VERSION 5.8 ;
BUSBITCHARS "[]" ;
DIVIDERCHAR "/" ;
UNITS
    DATABASE MICRONS 1000 ;
END UNITS

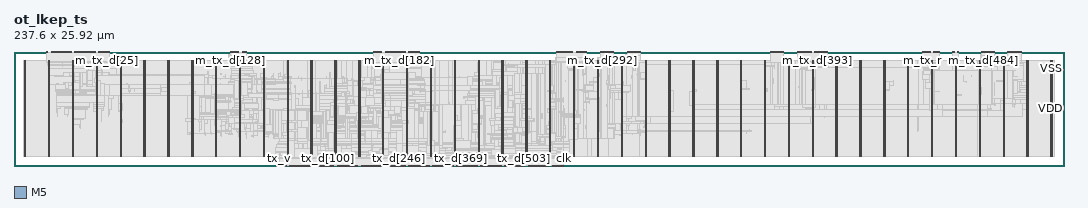
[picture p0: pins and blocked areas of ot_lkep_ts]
MACRO ot_lkep_ts
  FOREIGN ot_lkep_ts 0 0 ;
  CLASS BLOCK ;
  SIZE 237.6 BY 25.92 ;
  PIN clk
    DIRECTION INPUT ;
    USE SIGNAL ;
    PORT
      LAYER M5 ;
        RECT  124.368 0 124.392 0.192 ;
    END
  END clk
  PIN m_tx_d[0]
    DIRECTION INPUT ;
    USE SIGNAL ;
    PORT
      LAYER M5 ;
        RECT  17.904 25.728 17.928 25.92 ;
    END
  END m_tx_d[0]
  PIN m_tx_d[100]
    DIRECTION INPUT ;
    USE SIGNAL ;
    PORT
      LAYER M5 ;
        RECT  15.216 25.728 15.24 25.92 ;
    END
  END m_tx_d[100]
  PIN m_tx_d[101]
    DIRECTION INPUT ;
    USE SIGNAL ;
    PORT
      LAYER M5 ;
        RECT  15.312 25.728 15.336 25.92 ;
    END
  END m_tx_d[101]
  PIN m_tx_d[102]
    DIRECTION INPUT ;
    USE SIGNAL ;
    PORT
      LAYER M5 ;
        RECT  15.408 25.728 15.432 25.92 ;
    END
  END m_tx_d[102]
  PIN m_tx_d[103]
    DIRECTION INPUT ;
    USE SIGNAL ;
    PORT
      LAYER M5 ;
        RECT  15.504 25.728 15.528 25.92 ;
    END
  END m_tx_d[103]
  PIN m_tx_d[104]
    DIRECTION INPUT ;
    USE SIGNAL ;
    PORT
      LAYER M5 ;
        RECT  15.6 25.728 15.624 25.92 ;
    END
  END m_tx_d[104]
  PIN m_tx_d[105]
    DIRECTION INPUT ;
    USE SIGNAL ;
    PORT
      LAYER M5 ;
        RECT  15.696 25.728 15.72 25.92 ;
    END
  END m_tx_d[105]
  PIN m_tx_d[106]
    DIRECTION INPUT ;
    USE SIGNAL ;
    PORT
      LAYER M5 ;
        RECT  15.792 25.728 15.816 25.92 ;
    END
  END m_tx_d[106]
  PIN m_tx_d[107]
    DIRECTION INPUT ;
    USE SIGNAL ;
    PORT
      LAYER M5 ;
        RECT  15.888 25.728 15.912 25.92 ;
    END
  END m_tx_d[107]
  PIN m_tx_d[108]
    DIRECTION INPUT ;
    USE SIGNAL ;
    PORT
      LAYER M5 ;
        RECT  15.984 25.728 16.008 25.92 ;
    END
  END m_tx_d[108]
  PIN m_tx_d[109]
    DIRECTION INPUT ;
    USE SIGNAL ;
    PORT
      LAYER M5 ;
        RECT  16.08 25.728 16.104 25.92 ;
    END
  END m_tx_d[109]
  PIN m_tx_d[10]
    DIRECTION INPUT ;
    USE SIGNAL ;
    PORT
      LAYER M5 ;
        RECT  19.584 25.728 19.608 25.92 ;
    END
  END m_tx_d[10]
  PIN m_tx_d[110]
    DIRECTION INPUT ;
    USE SIGNAL ;
    PORT
      LAYER M5 ;
        RECT  16.176 25.728 16.2 25.92 ;
    END
  END m_tx_d[110]
  PIN m_tx_d[111]
    DIRECTION INPUT ;
    USE SIGNAL ;
    PORT
      LAYER M5 ;
        RECT  16.272 25.728 16.296 25.92 ;
    END
  END m_tx_d[111]
  PIN m_tx_d[112]
    DIRECTION INPUT ;
    USE SIGNAL ;
    PORT
      LAYER M5 ;
        RECT  16.368 25.728 16.392 25.92 ;
    END
  END m_tx_d[112]
  PIN m_tx_d[113]
    DIRECTION INPUT ;
    USE SIGNAL ;
    PORT
      LAYER M5 ;
        RECT  16.464 25.728 16.488 25.92 ;
    END
  END m_tx_d[113]
  PIN m_tx_d[114]
    DIRECTION INPUT ;
    USE SIGNAL ;
    PORT
      LAYER M5 ;
        RECT  16.56 25.728 16.584 25.92 ;
    END
  END m_tx_d[114]
  PIN m_tx_d[115]
    DIRECTION INPUT ;
    USE SIGNAL ;
    PORT
      LAYER M5 ;
        RECT  16.656 25.728 16.68 25.92 ;
    END
  END m_tx_d[115]
  PIN m_tx_d[116]
    DIRECTION INPUT ;
    USE SIGNAL ;
    PORT
      LAYER M5 ;
        RECT  16.752 25.728 16.776 25.92 ;
    END
  END m_tx_d[116]
  PIN m_tx_d[117]
    DIRECTION INPUT ;
    USE SIGNAL ;
    PORT
      LAYER M5 ;
        RECT  16.848 25.728 16.872 25.92 ;
    END
  END m_tx_d[117]
  PIN m_tx_d[118]
    DIRECTION INPUT ;
    USE SIGNAL ;
    PORT
      LAYER M5 ;
        RECT  16.944 25.728 16.968 25.92 ;
    END
  END m_tx_d[118]
  PIN m_tx_d[119]
    DIRECTION INPUT ;
    USE SIGNAL ;
    PORT
      LAYER M5 ;
        RECT  17.04 25.728 17.064 25.92 ;
    END
  END m_tx_d[119]
  PIN m_tx_d[11]
    DIRECTION INPUT ;
    USE SIGNAL ;
    PORT
      LAYER M5 ;
        RECT  19.68 25.728 19.704 25.92 ;
    END
  END m_tx_d[11]
  PIN m_tx_d[120]
    DIRECTION INPUT ;
    USE SIGNAL ;
    PORT
      LAYER M5 ;
        RECT  17.136 25.728 17.16 25.92 ;
    END
  END m_tx_d[120]
  PIN m_tx_d[121]
    DIRECTION INPUT ;
    USE SIGNAL ;
    PORT
      LAYER M5 ;
        RECT  17.232 25.728 17.256 25.92 ;
    END
  END m_tx_d[121]
  PIN m_tx_d[122]
    DIRECTION INPUT ;
    USE SIGNAL ;
    PORT
      LAYER M5 ;
        RECT  17.328 25.728 17.352 25.92 ;
    END
  END m_tx_d[122]
  PIN m_tx_d[123]
    DIRECTION INPUT ;
    USE SIGNAL ;
    PORT
      LAYER M5 ;
        RECT  17.424 25.728 17.448 25.92 ;
    END
  END m_tx_d[123]
  PIN m_tx_d[124]
    DIRECTION INPUT ;
    USE SIGNAL ;
    PORT
      LAYER M5 ;
        RECT  17.52 25.728 17.544 25.92 ;
    END
  END m_tx_d[124]
  PIN m_tx_d[125]
    DIRECTION INPUT ;
    USE SIGNAL ;
    PORT
      LAYER M5 ;
        RECT  17.616 25.728 17.64 25.92 ;
    END
  END m_tx_d[125]
  PIN m_tx_d[126]
    DIRECTION INPUT ;
    USE SIGNAL ;
    PORT
      LAYER M5 ;
        RECT  17.712 25.728 17.736 25.92 ;
    END
  END m_tx_d[126]
  PIN m_tx_d[127]
    DIRECTION INPUT ;
    USE SIGNAL ;
    PORT
      LAYER M5 ;
        RECT  17.808 25.728 17.832 25.92 ;
    END
  END m_tx_d[127]
  PIN m_tx_d[128]
    DIRECTION INPUT ;
    USE SIGNAL ;
    PORT
      LAYER M5 ;
        RECT  49.008 25.728 49.032 25.92 ;
    END
  END m_tx_d[128]
  PIN m_tx_d[129]
    DIRECTION INPUT ;
    USE SIGNAL ;
    PORT
      LAYER M5 ;
        RECT  49.104 25.728 49.128 25.92 ;
    END
  END m_tx_d[129]
  PIN m_tx_d[12]
    DIRECTION INPUT ;
    USE SIGNAL ;
    PORT
      LAYER M5 ;
        RECT  19.776 25.728 19.8 25.92 ;
    END
  END m_tx_d[12]
  PIN m_tx_d[130]
    DIRECTION INPUT ;
    USE SIGNAL ;
    PORT
      LAYER M5 ;
        RECT  49.2 25.728 49.224 25.92 ;
    END
  END m_tx_d[130]
  PIN m_tx_d[131]
    DIRECTION INPUT ;
    USE SIGNAL ;
    PORT
      LAYER M5 ;
        RECT  49.296 25.728 49.32 25.92 ;
    END
  END m_tx_d[131]
  PIN m_tx_d[132]
    DIRECTION INPUT ;
    USE SIGNAL ;
    PORT
      LAYER M5 ;
        RECT  49.392 25.728 49.416 25.92 ;
    END
  END m_tx_d[132]
  PIN m_tx_d[133]
    DIRECTION INPUT ;
    USE SIGNAL ;
    PORT
      LAYER M5 ;
        RECT  49.488 25.728 49.512 25.92 ;
    END
  END m_tx_d[133]
  PIN m_tx_d[134]
    DIRECTION INPUT ;
    USE SIGNAL ;
    PORT
      LAYER M5 ;
        RECT  49.584 25.728 49.608 25.92 ;
    END
  END m_tx_d[134]
  PIN m_tx_d[135]
    DIRECTION INPUT ;
    USE SIGNAL ;
    PORT
      LAYER M5 ;
        RECT  49.68 25.728 49.704 25.92 ;
    END
  END m_tx_d[135]
  PIN m_tx_d[136]
    DIRECTION INPUT ;
    USE SIGNAL ;
    PORT
      LAYER M5 ;
        RECT  49.776 25.728 49.8 25.92 ;
    END
  END m_tx_d[136]
  PIN m_tx_d[137]
    DIRECTION INPUT ;
    USE SIGNAL ;
    PORT
      LAYER M5 ;
        RECT  49.872 25.728 49.896 25.92 ;
    END
  END m_tx_d[137]
  PIN m_tx_d[138]
    DIRECTION INPUT ;
    USE SIGNAL ;
    PORT
      LAYER M5 ;
        RECT  49.968 25.728 49.992 25.92 ;
    END
  END m_tx_d[138]
  PIN m_tx_d[139]
    DIRECTION INPUT ;
    USE SIGNAL ;
    PORT
      LAYER M5 ;
        RECT  50.064 25.728 50.088 25.92 ;
    END
  END m_tx_d[139]
  PIN m_tx_d[13]
    DIRECTION INPUT ;
    USE SIGNAL ;
    PORT
      LAYER M5 ;
        RECT  19.872 25.728 19.896 25.92 ;
    END
  END m_tx_d[13]
  PIN m_tx_d[140]
    DIRECTION INPUT ;
    USE SIGNAL ;
    PORT
      LAYER M5 ;
        RECT  50.16 25.728 50.184 25.92 ;
    END
  END m_tx_d[140]
  PIN m_tx_d[141]
    DIRECTION INPUT ;
    USE SIGNAL ;
    PORT
      LAYER M5 ;
        RECT  50.256 25.728 50.28 25.92 ;
    END
  END m_tx_d[141]
  PIN m_tx_d[142]
    DIRECTION INPUT ;
    USE SIGNAL ;
    PORT
      LAYER M5 ;
        RECT  50.352 25.728 50.376 25.92 ;
    END
  END m_tx_d[142]
  PIN m_tx_d[143]
    DIRECTION INPUT ;
    USE SIGNAL ;
    PORT
      LAYER M5 ;
        RECT  50.448 25.728 50.472 25.92 ;
    END
  END m_tx_d[143]
  PIN m_tx_d[144]
    DIRECTION INPUT ;
    USE SIGNAL ;
    PORT
      LAYER M5 ;
        RECT  50.544 25.728 50.568 25.92 ;
    END
  END m_tx_d[144]
  PIN m_tx_d[145]
    DIRECTION INPUT ;
    USE SIGNAL ;
    PORT
      LAYER M5 ;
        RECT  50.64 25.728 50.664 25.92 ;
    END
  END m_tx_d[145]
  PIN m_tx_d[146]
    DIRECTION INPUT ;
    USE SIGNAL ;
    PORT
      LAYER M5 ;
        RECT  50.736 25.728 50.76 25.92 ;
    END
  END m_tx_d[146]
  PIN m_tx_d[147]
    DIRECTION INPUT ;
    USE SIGNAL ;
    PORT
      LAYER M5 ;
        RECT  50.832 25.728 50.856 25.92 ;
    END
  END m_tx_d[147]
  PIN m_tx_d[148]
    DIRECTION INPUT ;
    USE SIGNAL ;
    PORT
      LAYER M5 ;
        RECT  51.6 25.728 51.624 25.92 ;
    END
  END m_tx_d[148]
  PIN m_tx_d[149]
    DIRECTION INPUT ;
    USE SIGNAL ;
    PORT
      LAYER M5 ;
        RECT  51.696 25.728 51.72 25.92 ;
    END
  END m_tx_d[149]
  PIN m_tx_d[14]
    DIRECTION INPUT ;
    USE SIGNAL ;
    PORT
      LAYER M5 ;
        RECT  19.968 25.728 19.992 25.92 ;
    END
  END m_tx_d[14]
  PIN m_tx_d[150]
    DIRECTION INPUT ;
    USE SIGNAL ;
    PORT
      LAYER M5 ;
        RECT  51.792 25.728 51.816 25.92 ;
    END
  END m_tx_d[150]
  PIN m_tx_d[151]
    DIRECTION INPUT ;
    USE SIGNAL ;
    PORT
      LAYER M5 ;
        RECT  51.888 25.728 51.912 25.92 ;
    END
  END m_tx_d[151]
  PIN m_tx_d[152]
    DIRECTION INPUT ;
    USE SIGNAL ;
    PORT
      LAYER M5 ;
        RECT  51.984 25.728 52.008 25.92 ;
    END
  END m_tx_d[152]
  PIN m_tx_d[153]
    DIRECTION INPUT ;
    USE SIGNAL ;
    PORT
      LAYER M5 ;
        RECT  52.08 25.728 52.104 25.92 ;
    END
  END m_tx_d[153]
  PIN m_tx_d[154]
    DIRECTION INPUT ;
    USE SIGNAL ;
    PORT
      LAYER M5 ;
        RECT  52.176 25.728 52.2 25.92 ;
    END
  END m_tx_d[154]
  PIN m_tx_d[155]
    DIRECTION INPUT ;
    USE SIGNAL ;
    PORT
      LAYER M5 ;
        RECT  52.272 25.728 52.296 25.92 ;
    END
  END m_tx_d[155]
  PIN m_tx_d[156]
    DIRECTION INPUT ;
    USE SIGNAL ;
    PORT
      LAYER M5 ;
        RECT  52.368 25.728 52.392 25.92 ;
    END
  END m_tx_d[156]
  PIN m_tx_d[157]
    DIRECTION INPUT ;
    USE SIGNAL ;
    PORT
      LAYER M5 ;
        RECT  52.464 25.728 52.488 25.92 ;
    END
  END m_tx_d[157]
  PIN m_tx_d[158]
    DIRECTION INPUT ;
    USE SIGNAL ;
    PORT
      LAYER M5 ;
        RECT  52.56 25.728 52.584 25.92 ;
    END
  END m_tx_d[158]
  PIN m_tx_d[159]
    DIRECTION INPUT ;
    USE SIGNAL ;
    PORT
      LAYER M5 ;
        RECT  52.656 25.728 52.68 25.92 ;
    END
  END m_tx_d[159]
  PIN m_tx_d[15]
    DIRECTION INPUT ;
    USE SIGNAL ;
    PORT
      LAYER M5 ;
        RECT  20.064 25.728 20.088 25.92 ;
    END
  END m_tx_d[15]
  PIN m_tx_d[160]
    DIRECTION INPUT ;
    USE SIGNAL ;
    PORT
      LAYER M5 ;
        RECT  85.056 25.728 85.08 25.92 ;
    END
  END m_tx_d[160]
  PIN m_tx_d[161]
    DIRECTION INPUT ;
    USE SIGNAL ;
    PORT
      LAYER M5 ;
        RECT  85.152 25.728 85.176 25.92 ;
    END
  END m_tx_d[161]
  PIN m_tx_d[162]
    DIRECTION INPUT ;
    USE SIGNAL ;
    PORT
      LAYER M5 ;
        RECT  85.248 25.728 85.272 25.92 ;
    END
  END m_tx_d[162]
  PIN m_tx_d[163]
    DIRECTION INPUT ;
    USE SIGNAL ;
    PORT
      LAYER M5 ;
        RECT  85.344 25.728 85.368 25.92 ;
    END
  END m_tx_d[163]
  PIN m_tx_d[164]
    DIRECTION INPUT ;
    USE SIGNAL ;
    PORT
      LAYER M5 ;
        RECT  85.44 25.728 85.464 25.92 ;
    END
  END m_tx_d[164]
  PIN m_tx_d[165]
    DIRECTION INPUT ;
    USE SIGNAL ;
    PORT
      LAYER M5 ;
        RECT  85.536 25.728 85.56 25.92 ;
    END
  END m_tx_d[165]
  PIN m_tx_d[166]
    DIRECTION INPUT ;
    USE SIGNAL ;
    PORT
      LAYER M5 ;
        RECT  85.632 25.728 85.656 25.92 ;
    END
  END m_tx_d[166]
  PIN m_tx_d[167]
    DIRECTION INPUT ;
    USE SIGNAL ;
    PORT
      LAYER M5 ;
        RECT  85.728 25.728 85.752 25.92 ;
    END
  END m_tx_d[167]
  PIN m_tx_d[168]
    DIRECTION INPUT ;
    USE SIGNAL ;
    PORT
      LAYER M5 ;
        RECT  85.824 25.728 85.848 25.92 ;
    END
  END m_tx_d[168]
  PIN m_tx_d[169]
    DIRECTION INPUT ;
    USE SIGNAL ;
    PORT
      LAYER M5 ;
        RECT  85.92 25.728 85.944 25.92 ;
    END
  END m_tx_d[169]
  PIN m_tx_d[16]
    DIRECTION INPUT ;
    USE SIGNAL ;
    PORT
      LAYER M5 ;
        RECT  20.16 25.728 20.184 25.92 ;
    END
  END m_tx_d[16]
  PIN m_tx_d[170]
    DIRECTION INPUT ;
    USE SIGNAL ;
    PORT
      LAYER M5 ;
        RECT  86.016 25.728 86.04 25.92 ;
    END
  END m_tx_d[170]
  PIN m_tx_d[171]
    DIRECTION INPUT ;
    USE SIGNAL ;
    PORT
      LAYER M5 ;
        RECT  86.112 25.728 86.136 25.92 ;
    END
  END m_tx_d[171]
  PIN m_tx_d[172]
    DIRECTION INPUT ;
    USE SIGNAL ;
    PORT
      LAYER M5 ;
        RECT  86.208 25.728 86.232 25.92 ;
    END
  END m_tx_d[172]
  PIN m_tx_d[173]
    DIRECTION INPUT ;
    USE SIGNAL ;
    PORT
      LAYER M5 ;
        RECT  86.304 25.728 86.328 25.92 ;
    END
  END m_tx_d[173]
  PIN m_tx_d[174]
    DIRECTION INPUT ;
    USE SIGNAL ;
    PORT
      LAYER M5 ;
        RECT  86.4 25.728 86.424 25.92 ;
    END
  END m_tx_d[174]
  PIN m_tx_d[175]
    DIRECTION INPUT ;
    USE SIGNAL ;
    PORT
      LAYER M5 ;
        RECT  86.496 25.728 86.52 25.92 ;
    END
  END m_tx_d[175]
  PIN m_tx_d[176]
    DIRECTION INPUT ;
    USE SIGNAL ;
    PORT
      LAYER M5 ;
        RECT  86.592 25.728 86.616 25.92 ;
    END
  END m_tx_d[176]
  PIN m_tx_d[177]
    DIRECTION INPUT ;
    USE SIGNAL ;
    PORT
      LAYER M5 ;
        RECT  86.688 25.728 86.712 25.92 ;
    END
  END m_tx_d[177]
  PIN m_tx_d[178]
    DIRECTION INPUT ;
    USE SIGNAL ;
    PORT
      LAYER M5 ;
        RECT  86.784 25.728 86.808 25.92 ;
    END
  END m_tx_d[178]
  PIN m_tx_d[179]
    DIRECTION INPUT ;
    USE SIGNAL ;
    PORT
      LAYER M5 ;
        RECT  86.88 25.728 86.904 25.92 ;
    END
  END m_tx_d[179]
  PIN m_tx_d[17]
    DIRECTION INPUT ;
    USE SIGNAL ;
    PORT
      LAYER M5 ;
        RECT  20.256 25.728 20.28 25.92 ;
    END
  END m_tx_d[17]
  PIN m_tx_d[180]
    DIRECTION INPUT ;
    USE SIGNAL ;
    PORT
      LAYER M5 ;
        RECT  86.976 25.728 87 25.92 ;
    END
  END m_tx_d[180]
  PIN m_tx_d[181]
    DIRECTION INPUT ;
    USE SIGNAL ;
    PORT
      LAYER M5 ;
        RECT  87.072 25.728 87.096 25.92 ;
    END
  END m_tx_d[181]
  PIN m_tx_d[182]
    DIRECTION INPUT ;
    USE SIGNAL ;
    PORT
      LAYER M5 ;
        RECT  87.168 25.728 87.192 25.92 ;
    END
  END m_tx_d[182]
  PIN m_tx_d[183]
    DIRECTION INPUT ;
    USE SIGNAL ;
    PORT
      LAYER M5 ;
        RECT  87.264 25.728 87.288 25.92 ;
    END
  END m_tx_d[183]
  PIN m_tx_d[184]
    DIRECTION INPUT ;
    USE SIGNAL ;
    PORT
      LAYER M5 ;
        RECT  87.36 25.728 87.384 25.92 ;
    END
  END m_tx_d[184]
  PIN m_tx_d[185]
    DIRECTION INPUT ;
    USE SIGNAL ;
    PORT
      LAYER M5 ;
        RECT  87.456 25.728 87.48 25.92 ;
    END
  END m_tx_d[185]
  PIN m_tx_d[186]
    DIRECTION INPUT ;
    USE SIGNAL ;
    PORT
      LAYER M5 ;
        RECT  87.552 25.728 87.576 25.92 ;
    END
  END m_tx_d[186]
  PIN m_tx_d[187]
    DIRECTION INPUT ;
    USE SIGNAL ;
    PORT
      LAYER M5 ;
        RECT  87.648 25.728 87.672 25.92 ;
    END
  END m_tx_d[187]
  PIN m_tx_d[188]
    DIRECTION INPUT ;
    USE SIGNAL ;
    PORT
      LAYER M5 ;
        RECT  87.744 25.728 87.768 25.92 ;
    END
  END m_tx_d[188]
  PIN m_tx_d[189]
    DIRECTION INPUT ;
    USE SIGNAL ;
    PORT
      LAYER M5 ;
        RECT  87.84 25.728 87.864 25.92 ;
    END
  END m_tx_d[189]
  PIN m_tx_d[18]
    DIRECTION INPUT ;
    USE SIGNAL ;
    PORT
      LAYER M5 ;
        RECT  20.352 25.728 20.376 25.92 ;
    END
  END m_tx_d[18]
  PIN m_tx_d[190]
    DIRECTION INPUT ;
    USE SIGNAL ;
    PORT
      LAYER M5 ;
        RECT  87.936 25.728 87.96 25.92 ;
    END
  END m_tx_d[190]
  PIN m_tx_d[191]
    DIRECTION INPUT ;
    USE SIGNAL ;
    PORT
      LAYER M5 ;
        RECT  88.032 25.728 88.056 25.92 ;
    END
  END m_tx_d[191]
  PIN m_tx_d[192]
    DIRECTION INPUT ;
    USE SIGNAL ;
    PORT
      LAYER M5 ;
        RECT  88.128 25.728 88.152 25.92 ;
    END
  END m_tx_d[192]
  PIN m_tx_d[193]
    DIRECTION INPUT ;
    USE SIGNAL ;
    PORT
      LAYER M5 ;
        RECT  88.224 25.728 88.248 25.92 ;
    END
  END m_tx_d[193]
  PIN m_tx_d[194]
    DIRECTION INPUT ;
    USE SIGNAL ;
    PORT
      LAYER M5 ;
        RECT  88.32 25.728 88.344 25.92 ;
    END
  END m_tx_d[194]
  PIN m_tx_d[195]
    DIRECTION INPUT ;
    USE SIGNAL ;
    PORT
      LAYER M5 ;
        RECT  88.416 25.728 88.44 25.92 ;
    END
  END m_tx_d[195]
  PIN m_tx_d[196]
    DIRECTION INPUT ;
    USE SIGNAL ;
    PORT
      LAYER M5 ;
        RECT  88.512 25.728 88.536 25.92 ;
    END
  END m_tx_d[196]
  PIN m_tx_d[197]
    DIRECTION INPUT ;
    USE SIGNAL ;
    PORT
      LAYER M5 ;
        RECT  88.608 25.728 88.632 25.92 ;
    END
  END m_tx_d[197]
  PIN m_tx_d[198]
    DIRECTION INPUT ;
    USE SIGNAL ;
    PORT
      LAYER M5 ;
        RECT  89.376 25.728 89.4 25.92 ;
    END
  END m_tx_d[198]
  PIN m_tx_d[199]
    DIRECTION INPUT ;
    USE SIGNAL ;
    PORT
      LAYER M5 ;
        RECT  89.472 25.728 89.496 25.92 ;
    END
  END m_tx_d[199]
  PIN m_tx_d[19]
    DIRECTION INPUT ;
    USE SIGNAL ;
    PORT
      LAYER M5 ;
        RECT  20.448 25.728 20.472 25.92 ;
    END
  END m_tx_d[19]
  PIN m_tx_d[1]
    DIRECTION INPUT ;
    USE SIGNAL ;
    PORT
      LAYER M5 ;
        RECT  18 25.728 18.024 25.92 ;
    END
  END m_tx_d[1]
  PIN m_tx_d[200]
    DIRECTION INPUT ;
    USE SIGNAL ;
    PORT
      LAYER M5 ;
        RECT  89.568 25.728 89.592 25.92 ;
    END
  END m_tx_d[200]
  PIN m_tx_d[201]
    DIRECTION INPUT ;
    USE SIGNAL ;
    PORT
      LAYER M5 ;
        RECT  89.664 25.728 89.688 25.92 ;
    END
  END m_tx_d[201]
  PIN m_tx_d[202]
    DIRECTION INPUT ;
    USE SIGNAL ;
    PORT
      LAYER M5 ;
        RECT  89.76 25.728 89.784 25.92 ;
    END
  END m_tx_d[202]
  PIN m_tx_d[203]
    DIRECTION INPUT ;
    USE SIGNAL ;
    PORT
      LAYER M5 ;
        RECT  89.856 25.728 89.88 25.92 ;
    END
  END m_tx_d[203]
  PIN m_tx_d[204]
    DIRECTION INPUT ;
    USE SIGNAL ;
    PORT
      LAYER M5 ;
        RECT  89.952 25.728 89.976 25.92 ;
    END
  END m_tx_d[204]
  PIN m_tx_d[205]
    DIRECTION INPUT ;
    USE SIGNAL ;
    PORT
      LAYER M5 ;
        RECT  90.048 25.728 90.072 25.92 ;
    END
  END m_tx_d[205]
  PIN m_tx_d[206]
    DIRECTION INPUT ;
    USE SIGNAL ;
    PORT
      LAYER M5 ;
        RECT  90.144 25.728 90.168 25.92 ;
    END
  END m_tx_d[206]
  PIN m_tx_d[207]
    DIRECTION INPUT ;
    USE SIGNAL ;
    PORT
      LAYER M5 ;
        RECT  90.24 25.728 90.264 25.92 ;
    END
  END m_tx_d[207]
  PIN m_tx_d[208]
    DIRECTION INPUT ;
    USE SIGNAL ;
    PORT
      LAYER M5 ;
        RECT  90.336 25.728 90.36 25.92 ;
    END
  END m_tx_d[208]
  PIN m_tx_d[209]
    DIRECTION INPUT ;
    USE SIGNAL ;
    PORT
      LAYER M5 ;
        RECT  90.432 25.728 90.456 25.92 ;
    END
  END m_tx_d[209]
  PIN m_tx_d[20]
    DIRECTION INPUT ;
    USE SIGNAL ;
    PORT
      LAYER M5 ;
        RECT  20.544 25.728 20.568 25.92 ;
    END
  END m_tx_d[20]
  PIN m_tx_d[210]
    DIRECTION INPUT ;
    USE SIGNAL ;
    PORT
      LAYER M5 ;
        RECT  90.528 25.728 90.552 25.92 ;
    END
  END m_tx_d[210]
  PIN m_tx_d[211]
    DIRECTION INPUT ;
    USE SIGNAL ;
    PORT
      LAYER M5 ;
        RECT  90.624 25.728 90.648 25.92 ;
    END
  END m_tx_d[211]
  PIN m_tx_d[212]
    DIRECTION INPUT ;
    USE SIGNAL ;
    PORT
      LAYER M5 ;
        RECT  90.72 25.728 90.744 25.92 ;
    END
  END m_tx_d[212]
  PIN m_tx_d[213]
    DIRECTION INPUT ;
    USE SIGNAL ;
    PORT
      LAYER M5 ;
        RECT  90.816 25.728 90.84 25.92 ;
    END
  END m_tx_d[213]
  PIN m_tx_d[214]
    DIRECTION INPUT ;
    USE SIGNAL ;
    PORT
      LAYER M5 ;
        RECT  90.912 25.728 90.936 25.92 ;
    END
  END m_tx_d[214]
  PIN m_tx_d[215]
    DIRECTION INPUT ;
    USE SIGNAL ;
    PORT
      LAYER M5 ;
        RECT  91.008 25.728 91.032 25.92 ;
    END
  END m_tx_d[215]
  PIN m_tx_d[216]
    DIRECTION INPUT ;
    USE SIGNAL ;
    PORT
      LAYER M5 ;
        RECT  91.104 25.728 91.128 25.92 ;
    END
  END m_tx_d[216]
  PIN m_tx_d[217]
    DIRECTION INPUT ;
    USE SIGNAL ;
    PORT
      LAYER M5 ;
        RECT  91.2 25.728 91.224 25.92 ;
    END
  END m_tx_d[217]
  PIN m_tx_d[218]
    DIRECTION INPUT ;
    USE SIGNAL ;
    PORT
      LAYER M5 ;
        RECT  91.296 25.728 91.32 25.92 ;
    END
  END m_tx_d[218]
  PIN m_tx_d[219]
    DIRECTION INPUT ;
    USE SIGNAL ;
    PORT
      LAYER M5 ;
        RECT  91.392 25.728 91.416 25.92 ;
    END
  END m_tx_d[219]
  PIN m_tx_d[21]
    DIRECTION INPUT ;
    USE SIGNAL ;
    PORT
      LAYER M5 ;
        RECT  20.64 25.728 20.664 25.92 ;
    END
  END m_tx_d[21]
  PIN m_tx_d[220]
    DIRECTION INPUT ;
    USE SIGNAL ;
    PORT
      LAYER M5 ;
        RECT  91.488 25.728 91.512 25.92 ;
    END
  END m_tx_d[220]
  PIN m_tx_d[221]
    DIRECTION INPUT ;
    USE SIGNAL ;
    PORT
      LAYER M5 ;
        RECT  91.584 25.728 91.608 25.92 ;
    END
  END m_tx_d[221]
  PIN m_tx_d[222]
    DIRECTION INPUT ;
    USE SIGNAL ;
    PORT
      LAYER M5 ;
        RECT  91.68 25.728 91.704 25.92 ;
    END
  END m_tx_d[222]
  PIN m_tx_d[223]
    DIRECTION INPUT ;
    USE SIGNAL ;
    PORT
      LAYER M5 ;
        RECT  91.776 25.728 91.8 25.92 ;
    END
  END m_tx_d[223]
  PIN m_tx_d[224]
    DIRECTION INPUT ;
    USE SIGNAL ;
    PORT
      LAYER M5 ;
        RECT  81.264 25.728 81.288 25.92 ;
    END
  END m_tx_d[224]
  PIN m_tx_d[225]
    DIRECTION INPUT ;
    USE SIGNAL ;
    PORT
      LAYER M5 ;
        RECT  81.36 25.728 81.384 25.92 ;
    END
  END m_tx_d[225]
  PIN m_tx_d[226]
    DIRECTION INPUT ;
    USE SIGNAL ;
    PORT
      LAYER M5 ;
        RECT  81.456 25.728 81.48 25.92 ;
    END
  END m_tx_d[226]
  PIN m_tx_d[227]
    DIRECTION INPUT ;
    USE SIGNAL ;
    PORT
      LAYER M5 ;
        RECT  81.552 25.728 81.576 25.92 ;
    END
  END m_tx_d[227]
  PIN m_tx_d[228]
    DIRECTION INPUT ;
    USE SIGNAL ;
    PORT
      LAYER M5 ;
        RECT  81.648 25.728 81.672 25.92 ;
    END
  END m_tx_d[228]
  PIN m_tx_d[229]
    DIRECTION INPUT ;
    USE SIGNAL ;
    PORT
      LAYER M5 ;
        RECT  81.744 25.728 81.768 25.92 ;
    END
  END m_tx_d[229]
  PIN m_tx_d[22]
    DIRECTION INPUT ;
    USE SIGNAL ;
    PORT
      LAYER M5 ;
        RECT  20.736 25.728 20.76 25.92 ;
    END
  END m_tx_d[22]
  PIN m_tx_d[230]
    DIRECTION INPUT ;
    USE SIGNAL ;
    PORT
      LAYER M5 ;
        RECT  81.84 25.728 81.864 25.92 ;
    END
  END m_tx_d[230]
  PIN m_tx_d[231]
    DIRECTION INPUT ;
    USE SIGNAL ;
    PORT
      LAYER M5 ;
        RECT  81.936 25.728 81.96 25.92 ;
    END
  END m_tx_d[231]
  PIN m_tx_d[232]
    DIRECTION INPUT ;
    USE SIGNAL ;
    PORT
      LAYER M5 ;
        RECT  82.032 25.728 82.056 25.92 ;
    END
  END m_tx_d[232]
  PIN m_tx_d[233]
    DIRECTION INPUT ;
    USE SIGNAL ;
    PORT
      LAYER M5 ;
        RECT  82.128 25.728 82.152 25.92 ;
    END
  END m_tx_d[233]
  PIN m_tx_d[234]
    DIRECTION INPUT ;
    USE SIGNAL ;
    PORT
      LAYER M5 ;
        RECT  82.224 25.728 82.248 25.92 ;
    END
  END m_tx_d[234]
  PIN m_tx_d[235]
    DIRECTION INPUT ;
    USE SIGNAL ;
    PORT
      LAYER M5 ;
        RECT  82.32 25.728 82.344 25.92 ;
    END
  END m_tx_d[235]
  PIN m_tx_d[236]
    DIRECTION INPUT ;
    USE SIGNAL ;
    PORT
      LAYER M5 ;
        RECT  82.416 25.728 82.44 25.92 ;
    END
  END m_tx_d[236]
  PIN m_tx_d[237]
    DIRECTION INPUT ;
    USE SIGNAL ;
    PORT
      LAYER M5 ;
        RECT  82.512 25.728 82.536 25.92 ;
    END
  END m_tx_d[237]
  PIN m_tx_d[238]
    DIRECTION INPUT ;
    USE SIGNAL ;
    PORT
      LAYER M5 ;
        RECT  82.608 25.728 82.632 25.92 ;
    END
  END m_tx_d[238]
  PIN m_tx_d[239]
    DIRECTION INPUT ;
    USE SIGNAL ;
    PORT
      LAYER M5 ;
        RECT  82.704 25.728 82.728 25.92 ;
    END
  END m_tx_d[239]
  PIN m_tx_d[23]
    DIRECTION INPUT ;
    USE SIGNAL ;
    PORT
      LAYER M5 ;
        RECT  20.832 25.728 20.856 25.92 ;
    END
  END m_tx_d[23]
  PIN m_tx_d[240]
    DIRECTION INPUT ;
    USE SIGNAL ;
    PORT
      LAYER M5 ;
        RECT  82.8 25.728 82.824 25.92 ;
    END
  END m_tx_d[240]
  PIN m_tx_d[241]
    DIRECTION INPUT ;
    USE SIGNAL ;
    PORT
      LAYER M5 ;
        RECT  82.896 25.728 82.92 25.92 ;
    END
  END m_tx_d[241]
  PIN m_tx_d[242]
    DIRECTION INPUT ;
    USE SIGNAL ;
    PORT
      LAYER M5 ;
        RECT  82.992 25.728 83.016 25.92 ;
    END
  END m_tx_d[242]
  PIN m_tx_d[243]
    DIRECTION INPUT ;
    USE SIGNAL ;
    PORT
      LAYER M5 ;
        RECT  83.088 25.728 83.112 25.92 ;
    END
  END m_tx_d[243]
  PIN m_tx_d[244]
    DIRECTION INPUT ;
    USE SIGNAL ;
    PORT
      LAYER M5 ;
        RECT  83.184 25.728 83.208 25.92 ;
    END
  END m_tx_d[244]
  PIN m_tx_d[245]
    DIRECTION INPUT ;
    USE SIGNAL ;
    PORT
      LAYER M5 ;
        RECT  84 25.728 84.024 25.92 ;
    END
  END m_tx_d[245]
  PIN m_tx_d[246]
    DIRECTION INPUT ;
    USE SIGNAL ;
    PORT
      LAYER M5 ;
        RECT  84.096 25.728 84.12 25.92 ;
    END
  END m_tx_d[246]
  PIN m_tx_d[247]
    DIRECTION INPUT ;
    USE SIGNAL ;
    PORT
      LAYER M5 ;
        RECT  84.192 25.728 84.216 25.92 ;
    END
  END m_tx_d[247]
  PIN m_tx_d[248]
    DIRECTION INPUT ;
    USE SIGNAL ;
    PORT
      LAYER M5 ;
        RECT  84.288 25.728 84.312 25.92 ;
    END
  END m_tx_d[248]
  PIN m_tx_d[249]
    DIRECTION INPUT ;
    USE SIGNAL ;
    PORT
      LAYER M5 ;
        RECT  84.384 25.728 84.408 25.92 ;
    END
  END m_tx_d[249]
  PIN m_tx_d[24]
    DIRECTION INPUT ;
    USE SIGNAL ;
    PORT
      LAYER M5 ;
        RECT  20.928 25.728 20.952 25.92 ;
    END
  END m_tx_d[24]
  PIN m_tx_d[250]
    DIRECTION INPUT ;
    USE SIGNAL ;
    PORT
      LAYER M5 ;
        RECT  84.48 25.728 84.504 25.92 ;
    END
  END m_tx_d[250]
  PIN m_tx_d[251]
    DIRECTION INPUT ;
    USE SIGNAL ;
    PORT
      LAYER M5 ;
        RECT  84.576 25.728 84.6 25.92 ;
    END
  END m_tx_d[251]
  PIN m_tx_d[252]
    DIRECTION INPUT ;
    USE SIGNAL ;
    PORT
      LAYER M5 ;
        RECT  84.672 25.728 84.696 25.92 ;
    END
  END m_tx_d[252]
  PIN m_tx_d[253]
    DIRECTION INPUT ;
    USE SIGNAL ;
    PORT
      LAYER M5 ;
        RECT  84.768 25.728 84.792 25.92 ;
    END
  END m_tx_d[253]
  PIN m_tx_d[254]
    DIRECTION INPUT ;
    USE SIGNAL ;
    PORT
      LAYER M5 ;
        RECT  84.864 25.728 84.888 25.92 ;
    END
  END m_tx_d[254]
  PIN m_tx_d[255]
    DIRECTION INPUT ;
    USE SIGNAL ;
    PORT
      LAYER M5 ;
        RECT  84.96 25.728 84.984 25.92 ;
    END
  END m_tx_d[255]
  PIN m_tx_d[256]
    DIRECTION INPUT ;
    USE SIGNAL ;
    PORT
      LAYER M5 ;
        RECT  122.736 25.728 122.76 25.92 ;
    END
  END m_tx_d[256]
  PIN m_tx_d[257]
    DIRECTION INPUT ;
    USE SIGNAL ;
    PORT
      LAYER M5 ;
        RECT  122.832 25.728 122.856 25.92 ;
    END
  END m_tx_d[257]
  PIN m_tx_d[258]
    DIRECTION INPUT ;
    USE SIGNAL ;
    PORT
      LAYER M5 ;
        RECT  122.928 25.728 122.952 25.92 ;
    END
  END m_tx_d[258]
  PIN m_tx_d[259]
    DIRECTION INPUT ;
    USE SIGNAL ;
    PORT
      LAYER M5 ;
        RECT  123.024 25.728 123.048 25.92 ;
    END
  END m_tx_d[259]
  PIN m_tx_d[25]
    DIRECTION INPUT ;
    USE SIGNAL ;
    PORT
      LAYER M5 ;
        RECT  21.024 25.728 21.048 25.92 ;
    END
  END m_tx_d[25]
  PIN m_tx_d[260]
    DIRECTION INPUT ;
    USE SIGNAL ;
    PORT
      LAYER M5 ;
        RECT  123.12 25.728 123.144 25.92 ;
    END
  END m_tx_d[260]
  PIN m_tx_d[261]
    DIRECTION INPUT ;
    USE SIGNAL ;
    PORT
      LAYER M5 ;
        RECT  123.216 25.728 123.24 25.92 ;
    END
  END m_tx_d[261]
  PIN m_tx_d[262]
    DIRECTION INPUT ;
    USE SIGNAL ;
    PORT
      LAYER M5 ;
        RECT  123.312 25.728 123.336 25.92 ;
    END
  END m_tx_d[262]
  PIN m_tx_d[263]
    DIRECTION INPUT ;
    USE SIGNAL ;
    PORT
      LAYER M5 ;
        RECT  123.408 25.728 123.432 25.92 ;
    END
  END m_tx_d[263]
  PIN m_tx_d[264]
    DIRECTION INPUT ;
    USE SIGNAL ;
    PORT
      LAYER M5 ;
        RECT  123.504 25.728 123.528 25.92 ;
    END
  END m_tx_d[264]
  PIN m_tx_d[265]
    DIRECTION INPUT ;
    USE SIGNAL ;
    PORT
      LAYER M5 ;
        RECT  123.6 25.728 123.624 25.92 ;
    END
  END m_tx_d[265]
  PIN m_tx_d[266]
    DIRECTION INPUT ;
    USE SIGNAL ;
    PORT
      LAYER M5 ;
        RECT  123.696 25.728 123.72 25.92 ;
    END
  END m_tx_d[266]
  PIN m_tx_d[267]
    DIRECTION INPUT ;
    USE SIGNAL ;
    PORT
      LAYER M5 ;
        RECT  123.792 25.728 123.816 25.92 ;
    END
  END m_tx_d[267]
  PIN m_tx_d[268]
    DIRECTION INPUT ;
    USE SIGNAL ;
    PORT
      LAYER M5 ;
        RECT  123.888 25.728 123.912 25.92 ;
    END
  END m_tx_d[268]
  PIN m_tx_d[269]
    DIRECTION INPUT ;
    USE SIGNAL ;
    PORT
      LAYER M5 ;
        RECT  123.984 25.728 124.008 25.92 ;
    END
  END m_tx_d[269]
  PIN m_tx_d[26]
    DIRECTION INPUT ;
    USE SIGNAL ;
    PORT
      LAYER M5 ;
        RECT  21.12 25.728 21.144 25.92 ;
    END
  END m_tx_d[26]
  PIN m_tx_d[270]
    DIRECTION INPUT ;
    USE SIGNAL ;
    PORT
      LAYER M5 ;
        RECT  124.08 25.728 124.104 25.92 ;
    END
  END m_tx_d[270]
  PIN m_tx_d[271]
    DIRECTION INPUT ;
    USE SIGNAL ;
    PORT
      LAYER M5 ;
        RECT  124.176 25.728 124.2 25.92 ;
    END
  END m_tx_d[271]
  PIN m_tx_d[272]
    DIRECTION INPUT ;
    USE SIGNAL ;
    PORT
      LAYER M5 ;
        RECT  124.272 25.728 124.296 25.92 ;
    END
  END m_tx_d[272]
  PIN m_tx_d[273]
    DIRECTION INPUT ;
    USE SIGNAL ;
    PORT
      LAYER M5 ;
        RECT  124.368 25.728 124.392 25.92 ;
    END
  END m_tx_d[273]
  PIN m_tx_d[274]
    DIRECTION INPUT ;
    USE SIGNAL ;
    PORT
      LAYER M5 ;
        RECT  124.464 25.728 124.488 25.92 ;
    END
  END m_tx_d[274]
  PIN m_tx_d[275]
    DIRECTION INPUT ;
    USE SIGNAL ;
    PORT
      LAYER M5 ;
        RECT  124.56 25.728 124.584 25.92 ;
    END
  END m_tx_d[275]
  PIN m_tx_d[276]
    DIRECTION INPUT ;
    USE SIGNAL ;
    PORT
      LAYER M5 ;
        RECT  124.656 25.728 124.68 25.92 ;
    END
  END m_tx_d[276]
  PIN m_tx_d[277]
    DIRECTION INPUT ;
    USE SIGNAL ;
    PORT
      LAYER M5 ;
        RECT  124.752 25.728 124.776 25.92 ;
    END
  END m_tx_d[277]
  PIN m_tx_d[278]
    DIRECTION INPUT ;
    USE SIGNAL ;
    PORT
      LAYER M5 ;
        RECT  124.848 25.728 124.872 25.92 ;
    END
  END m_tx_d[278]
  PIN m_tx_d[279]
    DIRECTION INPUT ;
    USE SIGNAL ;
    PORT
      LAYER M5 ;
        RECT  124.944 25.728 124.968 25.92 ;
    END
  END m_tx_d[279]
  PIN m_tx_d[27]
    DIRECTION INPUT ;
    USE SIGNAL ;
    PORT
      LAYER M5 ;
        RECT  21.216 25.728 21.24 25.92 ;
    END
  END m_tx_d[27]
  PIN m_tx_d[280]
    DIRECTION INPUT ;
    USE SIGNAL ;
    PORT
      LAYER M5 ;
        RECT  125.04 25.728 125.064 25.92 ;
    END
  END m_tx_d[280]
  PIN m_tx_d[281]
    DIRECTION INPUT ;
    USE SIGNAL ;
    PORT
      LAYER M5 ;
        RECT  125.136 25.728 125.16 25.92 ;
    END
  END m_tx_d[281]
  PIN m_tx_d[282]
    DIRECTION INPUT ;
    USE SIGNAL ;
    PORT
      LAYER M5 ;
        RECT  125.232 25.728 125.256 25.92 ;
    END
  END m_tx_d[282]
  PIN m_tx_d[283]
    DIRECTION INPUT ;
    USE SIGNAL ;
    PORT
      LAYER M5 ;
        RECT  125.328 25.728 125.352 25.92 ;
    END
  END m_tx_d[283]
  PIN m_tx_d[284]
    DIRECTION INPUT ;
    USE SIGNAL ;
    PORT
      LAYER M5 ;
        RECT  125.424 25.728 125.448 25.92 ;
    END
  END m_tx_d[284]
  PIN m_tx_d[285]
    DIRECTION INPUT ;
    USE SIGNAL ;
    PORT
      LAYER M5 ;
        RECT  125.52 25.728 125.544 25.92 ;
    END
  END m_tx_d[285]
  PIN m_tx_d[286]
    DIRECTION INPUT ;
    USE SIGNAL ;
    PORT
      LAYER M5 ;
        RECT  125.616 25.728 125.64 25.92 ;
    END
  END m_tx_d[286]
  PIN m_tx_d[287]
    DIRECTION INPUT ;
    USE SIGNAL ;
    PORT
      LAYER M5 ;
        RECT  125.712 25.728 125.736 25.92 ;
    END
  END m_tx_d[287]
  PIN m_tx_d[288]
    DIRECTION INPUT ;
    USE SIGNAL ;
    PORT
      LAYER M5 ;
        RECT  132.72 25.728 132.744 25.92 ;
    END
  END m_tx_d[288]
  PIN m_tx_d[289]
    DIRECTION INPUT ;
    USE SIGNAL ;
    PORT
      LAYER M5 ;
        RECT  132.816 25.728 132.84 25.92 ;
    END
  END m_tx_d[289]
  PIN m_tx_d[28]
    DIRECTION INPUT ;
    USE SIGNAL ;
    PORT
      LAYER M5 ;
        RECT  21.312 25.728 21.336 25.92 ;
    END
  END m_tx_d[28]
  PIN m_tx_d[290]
    DIRECTION INPUT ;
    USE SIGNAL ;
    PORT
      LAYER M5 ;
        RECT  132.912 25.728 132.936 25.92 ;
    END
  END m_tx_d[290]
  PIN m_tx_d[291]
    DIRECTION INPUT ;
    USE SIGNAL ;
    PORT
      LAYER M5 ;
        RECT  133.008 25.728 133.032 25.92 ;
    END
  END m_tx_d[291]
  PIN m_tx_d[292]
    DIRECTION INPUT ;
    USE SIGNAL ;
    PORT
      LAYER M5 ;
        RECT  133.104 25.728 133.128 25.92 ;
    END
  END m_tx_d[292]
  PIN m_tx_d[293]
    DIRECTION INPUT ;
    USE SIGNAL ;
    PORT
      LAYER M5 ;
        RECT  133.2 25.728 133.224 25.92 ;
    END
  END m_tx_d[293]
  PIN m_tx_d[294]
    DIRECTION INPUT ;
    USE SIGNAL ;
    PORT
      LAYER M5 ;
        RECT  133.296 25.728 133.32 25.92 ;
    END
  END m_tx_d[294]
  PIN m_tx_d[295]
    DIRECTION INPUT ;
    USE SIGNAL ;
    PORT
      LAYER M5 ;
        RECT  133.392 25.728 133.416 25.92 ;
    END
  END m_tx_d[295]
  PIN m_tx_d[296]
    DIRECTION INPUT ;
    USE SIGNAL ;
    PORT
      LAYER M5 ;
        RECT  133.488 25.728 133.512 25.92 ;
    END
  END m_tx_d[296]
  PIN m_tx_d[297]
    DIRECTION INPUT ;
    USE SIGNAL ;
    PORT
      LAYER M5 ;
        RECT  133.584 25.728 133.608 25.92 ;
    END
  END m_tx_d[297]
  PIN m_tx_d[298]
    DIRECTION INPUT ;
    USE SIGNAL ;
    PORT
      LAYER M5 ;
        RECT  133.68 25.728 133.704 25.92 ;
    END
  END m_tx_d[298]
  PIN m_tx_d[299]
    DIRECTION INPUT ;
    USE SIGNAL ;
    PORT
      LAYER M5 ;
        RECT  133.776 25.728 133.8 25.92 ;
    END
  END m_tx_d[299]
  PIN m_tx_d[29]
    DIRECTION INPUT ;
    USE SIGNAL ;
    PORT
      LAYER M5 ;
        RECT  21.408 25.728 21.432 25.92 ;
    END
  END m_tx_d[29]
  PIN m_tx_d[2]
    DIRECTION INPUT ;
    USE SIGNAL ;
    PORT
      LAYER M5 ;
        RECT  18.096 25.728 18.12 25.92 ;
    END
  END m_tx_d[2]
  PIN m_tx_d[300]
    DIRECTION INPUT ;
    USE SIGNAL ;
    PORT
      LAYER M5 ;
        RECT  133.872 25.728 133.896 25.92 ;
    END
  END m_tx_d[300]
  PIN m_tx_d[301]
    DIRECTION INPUT ;
    USE SIGNAL ;
    PORT
      LAYER M5 ;
        RECT  133.968 25.728 133.992 25.92 ;
    END
  END m_tx_d[301]
  PIN m_tx_d[302]
    DIRECTION INPUT ;
    USE SIGNAL ;
    PORT
      LAYER M5 ;
        RECT  134.064 25.728 134.088 25.92 ;
    END
  END m_tx_d[302]
  PIN m_tx_d[303]
    DIRECTION INPUT ;
    USE SIGNAL ;
    PORT
      LAYER M5 ;
        RECT  134.16 25.728 134.184 25.92 ;
    END
  END m_tx_d[303]
  PIN m_tx_d[304]
    DIRECTION INPUT ;
    USE SIGNAL ;
    PORT
      LAYER M5 ;
        RECT  134.256 25.728 134.28 25.92 ;
    END
  END m_tx_d[304]
  PIN m_tx_d[305]
    DIRECTION INPUT ;
    USE SIGNAL ;
    PORT
      LAYER M5 ;
        RECT  134.352 25.728 134.376 25.92 ;
    END
  END m_tx_d[305]
  PIN m_tx_d[306]
    DIRECTION INPUT ;
    USE SIGNAL ;
    PORT
      LAYER M5 ;
        RECT  134.448 25.728 134.472 25.92 ;
    END
  END m_tx_d[306]
  PIN m_tx_d[307]
    DIRECTION INPUT ;
    USE SIGNAL ;
    PORT
      LAYER M5 ;
        RECT  134.544 25.728 134.568 25.92 ;
    END
  END m_tx_d[307]
  PIN m_tx_d[308]
    DIRECTION INPUT ;
    USE SIGNAL ;
    PORT
      LAYER M5 ;
        RECT  134.64 25.728 134.664 25.92 ;
    END
  END m_tx_d[308]
  PIN m_tx_d[309]
    DIRECTION INPUT ;
    USE SIGNAL ;
    PORT
      LAYER M5 ;
        RECT  134.736 25.728 134.76 25.92 ;
    END
  END m_tx_d[309]
  PIN m_tx_d[30]
    DIRECTION INPUT ;
    USE SIGNAL ;
    PORT
      LAYER M5 ;
        RECT  21.504 25.728 21.528 25.92 ;
    END
  END m_tx_d[30]
  PIN m_tx_d[310]
    DIRECTION INPUT ;
    USE SIGNAL ;
    PORT
      LAYER M5 ;
        RECT  134.832 25.728 134.856 25.92 ;
    END
  END m_tx_d[310]
  PIN m_tx_d[311]
    DIRECTION INPUT ;
    USE SIGNAL ;
    PORT
      LAYER M5 ;
        RECT  134.928 25.728 134.952 25.92 ;
    END
  END m_tx_d[311]
  PIN m_tx_d[312]
    DIRECTION INPUT ;
    USE SIGNAL ;
    PORT
      LAYER M5 ;
        RECT  135.024 25.728 135.048 25.92 ;
    END
  END m_tx_d[312]
  PIN m_tx_d[313]
    DIRECTION INPUT ;
    USE SIGNAL ;
    PORT
      LAYER M5 ;
        RECT  135.12 25.728 135.144 25.92 ;
    END
  END m_tx_d[313]
  PIN m_tx_d[314]
    DIRECTION INPUT ;
    USE SIGNAL ;
    PORT
      LAYER M5 ;
        RECT  135.216 25.728 135.24 25.92 ;
    END
  END m_tx_d[314]
  PIN m_tx_d[315]
    DIRECTION INPUT ;
    USE SIGNAL ;
    PORT
      LAYER M5 ;
        RECT  135.312 25.728 135.336 25.92 ;
    END
  END m_tx_d[315]
  PIN m_tx_d[316]
    DIRECTION INPUT ;
    USE SIGNAL ;
    PORT
      LAYER M5 ;
        RECT  135.408 25.728 135.432 25.92 ;
    END
  END m_tx_d[316]
  PIN m_tx_d[317]
    DIRECTION INPUT ;
    USE SIGNAL ;
    PORT
      LAYER M5 ;
        RECT  135.504 25.728 135.528 25.92 ;
    END
  END m_tx_d[317]
  PIN m_tx_d[318]
    DIRECTION INPUT ;
    USE SIGNAL ;
    PORT
      LAYER M5 ;
        RECT  135.6 25.728 135.624 25.92 ;
    END
  END m_tx_d[318]
  PIN m_tx_d[319]
    DIRECTION INPUT ;
    USE SIGNAL ;
    PORT
      LAYER M5 ;
        RECT  135.696 25.728 135.72 25.92 ;
    END
  END m_tx_d[319]
  PIN m_tx_d[31]
    DIRECTION INPUT ;
    USE SIGNAL ;
    PORT
      LAYER M5 ;
        RECT  21.6 25.728 21.624 25.92 ;
    END
  END m_tx_d[31]
  PIN m_tx_d[320]
    DIRECTION INPUT ;
    USE SIGNAL ;
    PORT
      LAYER M5 ;
        RECT  125.808 25.728 125.832 25.92 ;
    END
  END m_tx_d[320]
  PIN m_tx_d[321]
    DIRECTION INPUT ;
    USE SIGNAL ;
    PORT
      LAYER M5 ;
        RECT  125.904 25.728 125.928 25.92 ;
    END
  END m_tx_d[321]
  PIN m_tx_d[322]
    DIRECTION INPUT ;
    USE SIGNAL ;
    PORT
      LAYER M5 ;
        RECT  126 25.728 126.024 25.92 ;
    END
  END m_tx_d[322]
  PIN m_tx_d[323]
    DIRECTION INPUT ;
    USE SIGNAL ;
    PORT
      LAYER M5 ;
        RECT  126.096 25.728 126.12 25.92 ;
    END
  END m_tx_d[323]
  PIN m_tx_d[324]
    DIRECTION INPUT ;
    USE SIGNAL ;
    PORT
      LAYER M5 ;
        RECT  126.192 25.728 126.216 25.92 ;
    END
  END m_tx_d[324]
  PIN m_tx_d[325]
    DIRECTION INPUT ;
    USE SIGNAL ;
    PORT
      LAYER M5 ;
        RECT  126.288 25.728 126.312 25.92 ;
    END
  END m_tx_d[325]
  PIN m_tx_d[326]
    DIRECTION INPUT ;
    USE SIGNAL ;
    PORT
      LAYER M5 ;
        RECT  126.384 25.728 126.408 25.92 ;
    END
  END m_tx_d[326]
  PIN m_tx_d[327]
    DIRECTION INPUT ;
    USE SIGNAL ;
    PORT
      LAYER M5 ;
        RECT  127.2 25.728 127.224 25.92 ;
    END
  END m_tx_d[327]
  PIN m_tx_d[328]
    DIRECTION INPUT ;
    USE SIGNAL ;
    PORT
      LAYER M5 ;
        RECT  127.296 25.728 127.32 25.92 ;
    END
  END m_tx_d[328]
  PIN m_tx_d[329]
    DIRECTION INPUT ;
    USE SIGNAL ;
    PORT
      LAYER M5 ;
        RECT  127.392 25.728 127.416 25.92 ;
    END
  END m_tx_d[329]
  PIN m_tx_d[32]
    DIRECTION INPUT ;
    USE SIGNAL ;
    PORT
      LAYER M5 ;
        RECT  7.536 25.728 7.56 25.92 ;
    END
  END m_tx_d[32]
  PIN m_tx_d[330]
    DIRECTION INPUT ;
    USE SIGNAL ;
    PORT
      LAYER M5 ;
        RECT  127.488 25.728 127.512 25.92 ;
    END
  END m_tx_d[330]
  PIN m_tx_d[331]
    DIRECTION INPUT ;
    USE SIGNAL ;
    PORT
      LAYER M5 ;
        RECT  127.584 25.728 127.608 25.92 ;
    END
  END m_tx_d[331]
  PIN m_tx_d[332]
    DIRECTION INPUT ;
    USE SIGNAL ;
    PORT
      LAYER M5 ;
        RECT  127.68 25.728 127.704 25.92 ;
    END
  END m_tx_d[332]
  PIN m_tx_d[333]
    DIRECTION INPUT ;
    USE SIGNAL ;
    PORT
      LAYER M5 ;
        RECT  127.776 25.728 127.8 25.92 ;
    END
  END m_tx_d[333]
  PIN m_tx_d[334]
    DIRECTION INPUT ;
    USE SIGNAL ;
    PORT
      LAYER M5 ;
        RECT  127.872 25.728 127.896 25.92 ;
    END
  END m_tx_d[334]
  PIN m_tx_d[335]
    DIRECTION INPUT ;
    USE SIGNAL ;
    PORT
      LAYER M5 ;
        RECT  127.968 25.728 127.992 25.92 ;
    END
  END m_tx_d[335]
  PIN m_tx_d[336]
    DIRECTION INPUT ;
    USE SIGNAL ;
    PORT
      LAYER M5 ;
        RECT  128.064 25.728 128.088 25.92 ;
    END
  END m_tx_d[336]
  PIN m_tx_d[337]
    DIRECTION INPUT ;
    USE SIGNAL ;
    PORT
      LAYER M5 ;
        RECT  128.16 25.728 128.184 25.92 ;
    END
  END m_tx_d[337]
  PIN m_tx_d[338]
    DIRECTION INPUT ;
    USE SIGNAL ;
    PORT
      LAYER M5 ;
        RECT  128.256 25.728 128.28 25.92 ;
    END
  END m_tx_d[338]
  PIN m_tx_d[339]
    DIRECTION INPUT ;
    USE SIGNAL ;
    PORT
      LAYER M5 ;
        RECT  128.352 25.728 128.376 25.92 ;
    END
  END m_tx_d[339]
  PIN m_tx_d[33]
    DIRECTION INPUT ;
    USE SIGNAL ;
    PORT
      LAYER M5 ;
        RECT  7.632 25.728 7.656 25.92 ;
    END
  END m_tx_d[33]
  PIN m_tx_d[340]
    DIRECTION INPUT ;
    USE SIGNAL ;
    PORT
      LAYER M5 ;
        RECT  128.448 25.728 128.472 25.92 ;
    END
  END m_tx_d[340]
  PIN m_tx_d[341]
    DIRECTION INPUT ;
    USE SIGNAL ;
    PORT
      LAYER M5 ;
        RECT  128.544 25.728 128.568 25.92 ;
    END
  END m_tx_d[341]
  PIN m_tx_d[342]
    DIRECTION INPUT ;
    USE SIGNAL ;
    PORT
      LAYER M5 ;
        RECT  128.64 25.728 128.664 25.92 ;
    END
  END m_tx_d[342]
  PIN m_tx_d[343]
    DIRECTION INPUT ;
    USE SIGNAL ;
    PORT
      LAYER M5 ;
        RECT  128.736 25.728 128.76 25.92 ;
    END
  END m_tx_d[343]
  PIN m_tx_d[344]
    DIRECTION INPUT ;
    USE SIGNAL ;
    PORT
      LAYER M5 ;
        RECT  128.832 25.728 128.856 25.92 ;
    END
  END m_tx_d[344]
  PIN m_tx_d[345]
    DIRECTION INPUT ;
    USE SIGNAL ;
    PORT
      LAYER M5 ;
        RECT  128.928 25.728 128.952 25.92 ;
    END
  END m_tx_d[345]
  PIN m_tx_d[346]
    DIRECTION INPUT ;
    USE SIGNAL ;
    PORT
      LAYER M5 ;
        RECT  129.024 25.728 129.048 25.92 ;
    END
  END m_tx_d[346]
  PIN m_tx_d[347]
    DIRECTION INPUT ;
    USE SIGNAL ;
    PORT
      LAYER M5 ;
        RECT  129.12 25.728 129.144 25.92 ;
    END
  END m_tx_d[347]
  PIN m_tx_d[348]
    DIRECTION INPUT ;
    USE SIGNAL ;
    PORT
      LAYER M5 ;
        RECT  129.216 25.728 129.24 25.92 ;
    END
  END m_tx_d[348]
  PIN m_tx_d[349]
    DIRECTION INPUT ;
    USE SIGNAL ;
    PORT
      LAYER M5 ;
        RECT  129.312 25.728 129.336 25.92 ;
    END
  END m_tx_d[349]
  PIN m_tx_d[34]
    DIRECTION INPUT ;
    USE SIGNAL ;
    PORT
      LAYER M5 ;
        RECT  7.44 25.728 7.464 25.92 ;
    END
  END m_tx_d[34]
  PIN m_tx_d[350]
    DIRECTION INPUT ;
    USE SIGNAL ;
    PORT
      LAYER M5 ;
        RECT  129.408 25.728 129.432 25.92 ;
    END
  END m_tx_d[350]
  PIN m_tx_d[351]
    DIRECTION INPUT ;
    USE SIGNAL ;
    PORT
      LAYER M5 ;
        RECT  129.504 25.728 129.528 25.92 ;
    END
  END m_tx_d[351]
  PIN m_tx_d[352]
    DIRECTION INPUT ;
    USE SIGNAL ;
    PORT
      LAYER M5 ;
        RECT  138.864 25.728 138.888 25.92 ;
    END
  END m_tx_d[352]
  PIN m_tx_d[353]
    DIRECTION INPUT ;
    USE SIGNAL ;
    PORT
      LAYER M5 ;
        RECT  138.96 25.728 138.984 25.92 ;
    END
  END m_tx_d[353]
  PIN m_tx_d[354]
    DIRECTION INPUT ;
    USE SIGNAL ;
    PORT
      LAYER M5 ;
        RECT  139.056 25.728 139.08 25.92 ;
    END
  END m_tx_d[354]
  PIN m_tx_d[355]
    DIRECTION INPUT ;
    USE SIGNAL ;
    PORT
      LAYER M5 ;
        RECT  139.152 25.728 139.176 25.92 ;
    END
  END m_tx_d[355]
  PIN m_tx_d[356]
    DIRECTION INPUT ;
    USE SIGNAL ;
    PORT
      LAYER M5 ;
        RECT  139.248 25.728 139.272 25.92 ;
    END
  END m_tx_d[356]
  PIN m_tx_d[357]
    DIRECTION INPUT ;
    USE SIGNAL ;
    PORT
      LAYER M5 ;
        RECT  139.344 25.728 139.368 25.92 ;
    END
  END m_tx_d[357]
  PIN m_tx_d[358]
    DIRECTION INPUT ;
    USE SIGNAL ;
    PORT
      LAYER M5 ;
        RECT  139.44 25.728 139.464 25.92 ;
    END
  END m_tx_d[358]
  PIN m_tx_d[359]
    DIRECTION INPUT ;
    USE SIGNAL ;
    PORT
      LAYER M5 ;
        RECT  139.536 25.728 139.56 25.92 ;
    END
  END m_tx_d[359]
  PIN m_tx_d[35]
    DIRECTION INPUT ;
    USE SIGNAL ;
    PORT
      LAYER M5 ;
        RECT  7.344 25.728 7.368 25.92 ;
    END
  END m_tx_d[35]
  PIN m_tx_d[360]
    DIRECTION INPUT ;
    USE SIGNAL ;
    PORT
      LAYER M5 ;
        RECT  139.632 25.728 139.656 25.92 ;
    END
  END m_tx_d[360]
  PIN m_tx_d[361]
    DIRECTION INPUT ;
    USE SIGNAL ;
    PORT
      LAYER M5 ;
        RECT  139.728 25.728 139.752 25.92 ;
    END
  END m_tx_d[361]
  PIN m_tx_d[362]
    DIRECTION INPUT ;
    USE SIGNAL ;
    PORT
      LAYER M5 ;
        RECT  139.824 25.728 139.848 25.92 ;
    END
  END m_tx_d[362]
  PIN m_tx_d[363]
    DIRECTION INPUT ;
    USE SIGNAL ;
    PORT
      LAYER M5 ;
        RECT  139.92 25.728 139.944 25.92 ;
    END
  END m_tx_d[363]
  PIN m_tx_d[364]
    DIRECTION INPUT ;
    USE SIGNAL ;
    PORT
      LAYER M5 ;
        RECT  140.016 25.728 140.04 25.92 ;
    END
  END m_tx_d[364]
  PIN m_tx_d[365]
    DIRECTION INPUT ;
    USE SIGNAL ;
    PORT
      LAYER M5 ;
        RECT  140.112 25.728 140.136 25.92 ;
    END
  END m_tx_d[365]
  PIN m_tx_d[366]
    DIRECTION INPUT ;
    USE SIGNAL ;
    PORT
      LAYER M5 ;
        RECT  140.208 25.728 140.232 25.92 ;
    END
  END m_tx_d[366]
  PIN m_tx_d[367]
    DIRECTION INPUT ;
    USE SIGNAL ;
    PORT
      LAYER M5 ;
        RECT  140.304 25.728 140.328 25.92 ;
    END
  END m_tx_d[367]
  PIN m_tx_d[368]
    DIRECTION INPUT ;
    USE SIGNAL ;
    PORT
      LAYER M5 ;
        RECT  140.4 25.728 140.424 25.92 ;
    END
  END m_tx_d[368]
  PIN m_tx_d[369]
    DIRECTION INPUT ;
    USE SIGNAL ;
    PORT
      LAYER M5 ;
        RECT  140.496 25.728 140.52 25.92 ;
    END
  END m_tx_d[369]
  PIN m_tx_d[36]
    DIRECTION INPUT ;
    USE SIGNAL ;
    PORT
      LAYER M5 ;
        RECT  8.4 25.728 8.424 25.92 ;
    END
  END m_tx_d[36]
  PIN m_tx_d[370]
    DIRECTION INPUT ;
    USE SIGNAL ;
    PORT
      LAYER M5 ;
        RECT  140.592 25.728 140.616 25.92 ;
    END
  END m_tx_d[370]
  PIN m_tx_d[371]
    DIRECTION INPUT ;
    USE SIGNAL ;
    PORT
      LAYER M5 ;
        RECT  140.688 25.728 140.712 25.92 ;
    END
  END m_tx_d[371]
  PIN m_tx_d[372]
    DIRECTION INPUT ;
    USE SIGNAL ;
    PORT
      LAYER M5 ;
        RECT  140.784 25.728 140.808 25.92 ;
    END
  END m_tx_d[372]
  PIN m_tx_d[373]
    DIRECTION INPUT ;
    USE SIGNAL ;
    PORT
      LAYER M5 ;
        RECT  140.88 25.728 140.904 25.92 ;
    END
  END m_tx_d[373]
  PIN m_tx_d[374]
    DIRECTION INPUT ;
    USE SIGNAL ;
    PORT
      LAYER M5 ;
        RECT  140.976 25.728 141 25.92 ;
    END
  END m_tx_d[374]
  PIN m_tx_d[375]
    DIRECTION INPUT ;
    USE SIGNAL ;
    PORT
      LAYER M5 ;
        RECT  141.072 25.728 141.096 25.92 ;
    END
  END m_tx_d[375]
  PIN m_tx_d[376]
    DIRECTION INPUT ;
    USE SIGNAL ;
    PORT
      LAYER M5 ;
        RECT  141.168 25.728 141.192 25.92 ;
    END
  END m_tx_d[376]
  PIN m_tx_d[377]
    DIRECTION INPUT ;
    USE SIGNAL ;
    PORT
      LAYER M5 ;
        RECT  141.264 25.728 141.288 25.92 ;
    END
  END m_tx_d[377]
  PIN m_tx_d[378]
    DIRECTION INPUT ;
    USE SIGNAL ;
    PORT
      LAYER M5 ;
        RECT  141.36 25.728 141.384 25.92 ;
    END
  END m_tx_d[378]
  PIN m_tx_d[379]
    DIRECTION INPUT ;
    USE SIGNAL ;
    PORT
      LAYER M5 ;
        RECT  141.456 25.728 141.48 25.92 ;
    END
  END m_tx_d[379]
  PIN m_tx_d[37]
    DIRECTION INPUT ;
    USE SIGNAL ;
    PORT
      LAYER M5 ;
        RECT  8.496 25.728 8.52 25.92 ;
    END
  END m_tx_d[37]
  PIN m_tx_d[380]
    DIRECTION INPUT ;
    USE SIGNAL ;
    PORT
      LAYER M5 ;
        RECT  141.552 25.728 141.576 25.92 ;
    END
  END m_tx_d[380]
  PIN m_tx_d[381]
    DIRECTION INPUT ;
    USE SIGNAL ;
    PORT
      LAYER M5 ;
        RECT  141.648 25.728 141.672 25.92 ;
    END
  END m_tx_d[381]
  PIN m_tx_d[382]
    DIRECTION INPUT ;
    USE SIGNAL ;
    PORT
      LAYER M5 ;
        RECT  141.744 25.728 141.768 25.92 ;
    END
  END m_tx_d[382]
  PIN m_tx_d[383]
    DIRECTION INPUT ;
    USE SIGNAL ;
    PORT
      LAYER M5 ;
        RECT  141.84 25.728 141.864 25.92 ;
    END
  END m_tx_d[383]
  PIN m_tx_d[384]
    DIRECTION INPUT ;
    USE SIGNAL ;
    PORT
      LAYER M5 ;
        RECT  180.336 25.728 180.36 25.92 ;
    END
  END m_tx_d[384]
  PIN m_tx_d[385]
    DIRECTION INPUT ;
    USE SIGNAL ;
    PORT
      LAYER M5 ;
        RECT  180.432 25.728 180.456 25.92 ;
    END
  END m_tx_d[385]
  PIN m_tx_d[386]
    DIRECTION INPUT ;
    USE SIGNAL ;
    PORT
      LAYER M5 ;
        RECT  181.2 25.728 181.224 25.92 ;
    END
  END m_tx_d[386]
  PIN m_tx_d[387]
    DIRECTION INPUT ;
    USE SIGNAL ;
    PORT
      LAYER M5 ;
        RECT  181.296 25.728 181.32 25.92 ;
    END
  END m_tx_d[387]
  PIN m_tx_d[388]
    DIRECTION INPUT ;
    USE SIGNAL ;
    PORT
      LAYER M5 ;
        RECT  181.392 25.728 181.416 25.92 ;
    END
  END m_tx_d[388]
  PIN m_tx_d[389]
    DIRECTION INPUT ;
    USE SIGNAL ;
    PORT
      LAYER M5 ;
        RECT  181.488 25.728 181.512 25.92 ;
    END
  END m_tx_d[389]
  PIN m_tx_d[38]
    DIRECTION INPUT ;
    USE SIGNAL ;
    PORT
      LAYER M5 ;
        RECT  8.592 25.728 8.616 25.92 ;
    END
  END m_tx_d[38]
  PIN m_tx_d[390]
    DIRECTION INPUT ;
    USE SIGNAL ;
    PORT
      LAYER M5 ;
        RECT  181.584 25.728 181.608 25.92 ;
    END
  END m_tx_d[390]
  PIN m_tx_d[391]
    DIRECTION INPUT ;
    USE SIGNAL ;
    PORT
      LAYER M5 ;
        RECT  181.68 25.728 181.704 25.92 ;
    END
  END m_tx_d[391]
  PIN m_tx_d[392]
    DIRECTION INPUT ;
    USE SIGNAL ;
    PORT
      LAYER M5 ;
        RECT  181.776 25.728 181.8 25.92 ;
    END
  END m_tx_d[392]
  PIN m_tx_d[393]
    DIRECTION INPUT ;
    USE SIGNAL ;
    PORT
      LAYER M5 ;
        RECT  181.872 25.728 181.896 25.92 ;
    END
  END m_tx_d[393]
  PIN m_tx_d[394]
    DIRECTION INPUT ;
    USE SIGNAL ;
    PORT
      LAYER M5 ;
        RECT  181.968 25.728 181.992 25.92 ;
    END
  END m_tx_d[394]
  PIN m_tx_d[395]
    DIRECTION INPUT ;
    USE SIGNAL ;
    PORT
      LAYER M5 ;
        RECT  182.064 25.728 182.088 25.92 ;
    END
  END m_tx_d[395]
  PIN m_tx_d[396]
    DIRECTION INPUT ;
    USE SIGNAL ;
    PORT
      LAYER M5 ;
        RECT  182.16 25.728 182.184 25.92 ;
    END
  END m_tx_d[396]
  PIN m_tx_d[397]
    DIRECTION INPUT ;
    USE SIGNAL ;
    PORT
      LAYER M5 ;
        RECT  182.256 25.728 182.28 25.92 ;
    END
  END m_tx_d[397]
  PIN m_tx_d[398]
    DIRECTION INPUT ;
    USE SIGNAL ;
    PORT
      LAYER M5 ;
        RECT  182.352 25.728 182.376 25.92 ;
    END
  END m_tx_d[398]
  PIN m_tx_d[399]
    DIRECTION INPUT ;
    USE SIGNAL ;
    PORT
      LAYER M5 ;
        RECT  182.448 25.728 182.472 25.92 ;
    END
  END m_tx_d[399]
  PIN m_tx_d[39]
    DIRECTION INPUT ;
    USE SIGNAL ;
    PORT
      LAYER M5 ;
        RECT  8.688 25.728 8.712 25.92 ;
    END
  END m_tx_d[39]
  PIN m_tx_d[3]
    DIRECTION INPUT ;
    USE SIGNAL ;
    PORT
      LAYER M5 ;
        RECT  18.192 25.728 18.216 25.92 ;
    END
  END m_tx_d[3]
  PIN m_tx_d[400]
    DIRECTION INPUT ;
    USE SIGNAL ;
    PORT
      LAYER M5 ;
        RECT  182.544 25.728 182.568 25.92 ;
    END
  END m_tx_d[400]
  PIN m_tx_d[401]
    DIRECTION INPUT ;
    USE SIGNAL ;
    PORT
      LAYER M5 ;
        RECT  182.64 25.728 182.664 25.92 ;
    END
  END m_tx_d[401]
  PIN m_tx_d[402]
    DIRECTION INPUT ;
    USE SIGNAL ;
    PORT
      LAYER M5 ;
        RECT  182.736 25.728 182.76 25.92 ;
    END
  END m_tx_d[402]
  PIN m_tx_d[403]
    DIRECTION INPUT ;
    USE SIGNAL ;
    PORT
      LAYER M5 ;
        RECT  182.832 25.728 182.856 25.92 ;
    END
  END m_tx_d[403]
  PIN m_tx_d[404]
    DIRECTION INPUT ;
    USE SIGNAL ;
    PORT
      LAYER M5 ;
        RECT  182.928 25.728 182.952 25.92 ;
    END
  END m_tx_d[404]
  PIN m_tx_d[405]
    DIRECTION INPUT ;
    USE SIGNAL ;
    PORT
      LAYER M5 ;
        RECT  183.024 25.728 183.048 25.92 ;
    END
  END m_tx_d[405]
  PIN m_tx_d[406]
    DIRECTION INPUT ;
    USE SIGNAL ;
    PORT
      LAYER M5 ;
        RECT  183.12 25.728 183.144 25.92 ;
    END
  END m_tx_d[406]
  PIN m_tx_d[407]
    DIRECTION INPUT ;
    USE SIGNAL ;
    PORT
      LAYER M5 ;
        RECT  183.216 25.728 183.24 25.92 ;
    END
  END m_tx_d[407]
  PIN m_tx_d[408]
    DIRECTION INPUT ;
    USE SIGNAL ;
    PORT
      LAYER M5 ;
        RECT  183.312 25.728 183.336 25.92 ;
    END
  END m_tx_d[408]
  PIN m_tx_d[409]
    DIRECTION INPUT ;
    USE SIGNAL ;
    PORT
      LAYER M5 ;
        RECT  183.408 25.728 183.432 25.92 ;
    END
  END m_tx_d[409]
  PIN m_tx_d[40]
    DIRECTION INPUT ;
    USE SIGNAL ;
    PORT
      LAYER M5 ;
        RECT  8.784 25.728 8.808 25.92 ;
    END
  END m_tx_d[40]
  PIN m_tx_d[410]
    DIRECTION INPUT ;
    USE SIGNAL ;
    PORT
      LAYER M5 ;
        RECT  183.504 25.728 183.528 25.92 ;
    END
  END m_tx_d[410]
  PIN m_tx_d[411]
    DIRECTION INPUT ;
    USE SIGNAL ;
    PORT
      LAYER M5 ;
        RECT  183.6 25.728 183.624 25.92 ;
    END
  END m_tx_d[411]
  PIN m_tx_d[412]
    DIRECTION INPUT ;
    USE SIGNAL ;
    PORT
      LAYER M5 ;
        RECT  183.696 25.728 183.72 25.92 ;
    END
  END m_tx_d[412]
  PIN m_tx_d[413]
    DIRECTION INPUT ;
    USE SIGNAL ;
    PORT
      LAYER M5 ;
        RECT  183.792 25.728 183.816 25.92 ;
    END
  END m_tx_d[413]
  PIN m_tx_d[414]
    DIRECTION INPUT ;
    USE SIGNAL ;
    PORT
      LAYER M5 ;
        RECT  183.888 25.728 183.912 25.92 ;
    END
  END m_tx_d[414]
  PIN m_tx_d[415]
    DIRECTION INPUT ;
    USE SIGNAL ;
    PORT
      LAYER M5 ;
        RECT  183.984 25.728 184.008 25.92 ;
    END
  END m_tx_d[415]
  PIN m_tx_d[416]
    DIRECTION INPUT ;
    USE SIGNAL ;
    PORT
      LAYER M5 ;
        RECT  171.12 25.728 171.144 25.92 ;
    END
  END m_tx_d[416]
  PIN m_tx_d[417]
    DIRECTION INPUT ;
    USE SIGNAL ;
    PORT
      LAYER M5 ;
        RECT  171.216 25.728 171.24 25.92 ;
    END
  END m_tx_d[417]
  PIN m_tx_d[418]
    DIRECTION INPUT ;
    USE SIGNAL ;
    PORT
      LAYER M5 ;
        RECT  171.312 25.728 171.336 25.92 ;
    END
  END m_tx_d[418]
  PIN m_tx_d[419]
    DIRECTION INPUT ;
    USE SIGNAL ;
    PORT
      LAYER M5 ;
        RECT  171.408 25.728 171.432 25.92 ;
    END
  END m_tx_d[419]
  PIN m_tx_d[41]
    DIRECTION INPUT ;
    USE SIGNAL ;
    PORT
      LAYER M5 ;
        RECT  8.88 25.728 8.904 25.92 ;
    END
  END m_tx_d[41]
  PIN m_tx_d[420]
    DIRECTION INPUT ;
    USE SIGNAL ;
    PORT
      LAYER M5 ;
        RECT  171.504 25.728 171.528 25.92 ;
    END
  END m_tx_d[420]
  PIN m_tx_d[421]
    DIRECTION INPUT ;
    USE SIGNAL ;
    PORT
      LAYER M5 ;
        RECT  171.6 25.728 171.624 25.92 ;
    END
  END m_tx_d[421]
  PIN m_tx_d[422]
    DIRECTION INPUT ;
    USE SIGNAL ;
    PORT
      LAYER M5 ;
        RECT  171.696 25.728 171.72 25.92 ;
    END
  END m_tx_d[422]
  PIN m_tx_d[423]
    DIRECTION INPUT ;
    USE SIGNAL ;
    PORT
      LAYER M5 ;
        RECT  171.792 25.728 171.816 25.92 ;
    END
  END m_tx_d[423]
  PIN m_tx_d[424]
    DIRECTION INPUT ;
    USE SIGNAL ;
    PORT
      LAYER M5 ;
        RECT  171.888 25.728 171.912 25.92 ;
    END
  END m_tx_d[424]
  PIN m_tx_d[425]
    DIRECTION INPUT ;
    USE SIGNAL ;
    PORT
      LAYER M5 ;
        RECT  171.984 25.728 172.008 25.92 ;
    END
  END m_tx_d[425]
  PIN m_tx_d[426]
    DIRECTION INPUT ;
    USE SIGNAL ;
    PORT
      LAYER M5 ;
        RECT  172.08 25.728 172.104 25.92 ;
    END
  END m_tx_d[426]
  PIN m_tx_d[427]
    DIRECTION INPUT ;
    USE SIGNAL ;
    PORT
      LAYER M5 ;
        RECT  172.176 25.728 172.2 25.92 ;
    END
  END m_tx_d[427]
  PIN m_tx_d[428]
    DIRECTION INPUT ;
    USE SIGNAL ;
    PORT
      LAYER M5 ;
        RECT  172.272 25.728 172.296 25.92 ;
    END
  END m_tx_d[428]
  PIN m_tx_d[429]
    DIRECTION INPUT ;
    USE SIGNAL ;
    PORT
      LAYER M5 ;
        RECT  172.368 25.728 172.392 25.92 ;
    END
  END m_tx_d[429]
  PIN m_tx_d[42]
    DIRECTION INPUT ;
    USE SIGNAL ;
    PORT
      LAYER M5 ;
        RECT  8.976 25.728 9 25.92 ;
    END
  END m_tx_d[42]
  PIN m_tx_d[430]
    DIRECTION INPUT ;
    USE SIGNAL ;
    PORT
      LAYER M5 ;
        RECT  172.464 25.728 172.488 25.92 ;
    END
  END m_tx_d[430]
  PIN m_tx_d[431]
    DIRECTION INPUT ;
    USE SIGNAL ;
    PORT
      LAYER M5 ;
        RECT  172.56 25.728 172.584 25.92 ;
    END
  END m_tx_d[431]
  PIN m_tx_d[432]
    DIRECTION INPUT ;
    USE SIGNAL ;
    PORT
      LAYER M5 ;
        RECT  172.656 25.728 172.68 25.92 ;
    END
  END m_tx_d[432]
  PIN m_tx_d[433]
    DIRECTION INPUT ;
    USE SIGNAL ;
    PORT
      LAYER M5 ;
        RECT  172.752 25.728 172.776 25.92 ;
    END
  END m_tx_d[433]
  PIN m_tx_d[434]
    DIRECTION INPUT ;
    USE SIGNAL ;
    PORT
      LAYER M5 ;
        RECT  172.848 25.728 172.872 25.92 ;
    END
  END m_tx_d[434]
  PIN m_tx_d[435]
    DIRECTION INPUT ;
    USE SIGNAL ;
    PORT
      LAYER M5 ;
        RECT  172.944 25.728 172.968 25.92 ;
    END
  END m_tx_d[435]
  PIN m_tx_d[436]
    DIRECTION INPUT ;
    USE SIGNAL ;
    PORT
      LAYER M5 ;
        RECT  173.04 25.728 173.064 25.92 ;
    END
  END m_tx_d[436]
  PIN m_tx_d[437]
    DIRECTION INPUT ;
    USE SIGNAL ;
    PORT
      LAYER M5 ;
        RECT  173.136 25.728 173.16 25.92 ;
    END
  END m_tx_d[437]
  PIN m_tx_d[438]
    DIRECTION INPUT ;
    USE SIGNAL ;
    PORT
      LAYER M5 ;
        RECT  173.232 25.728 173.256 25.92 ;
    END
  END m_tx_d[438]
  PIN m_tx_d[439]
    DIRECTION INPUT ;
    USE SIGNAL ;
    PORT
      LAYER M5 ;
        RECT  173.328 25.728 173.352 25.92 ;
    END
  END m_tx_d[439]
  PIN m_tx_d[43]
    DIRECTION INPUT ;
    USE SIGNAL ;
    PORT
      LAYER M5 ;
        RECT  9.072 25.728 9.096 25.92 ;
    END
  END m_tx_d[43]
  PIN m_tx_d[440]
    DIRECTION INPUT ;
    USE SIGNAL ;
    PORT
      LAYER M5 ;
        RECT  173.424 25.728 173.448 25.92 ;
    END
  END m_tx_d[440]
  PIN m_tx_d[441]
    DIRECTION INPUT ;
    USE SIGNAL ;
    PORT
      LAYER M5 ;
        RECT  173.52 25.728 173.544 25.92 ;
    END
  END m_tx_d[441]
  PIN m_tx_d[442]
    DIRECTION INPUT ;
    USE SIGNAL ;
    PORT
      LAYER M5 ;
        RECT  173.616 25.728 173.64 25.92 ;
    END
  END m_tx_d[442]
  PIN m_tx_d[443]
    DIRECTION INPUT ;
    USE SIGNAL ;
    PORT
      LAYER M5 ;
        RECT  173.712 25.728 173.736 25.92 ;
    END
  END m_tx_d[443]
  PIN m_tx_d[444]
    DIRECTION INPUT ;
    USE SIGNAL ;
    PORT
      LAYER M5 ;
        RECT  173.808 25.728 173.832 25.92 ;
    END
  END m_tx_d[444]
  PIN m_tx_d[445]
    DIRECTION INPUT ;
    USE SIGNAL ;
    PORT
      LAYER M5 ;
        RECT  173.904 25.728 173.928 25.92 ;
    END
  END m_tx_d[445]
  PIN m_tx_d[446]
    DIRECTION INPUT ;
    USE SIGNAL ;
    PORT
      LAYER M5 ;
        RECT  174 25.728 174.024 25.92 ;
    END
  END m_tx_d[446]
  PIN m_tx_d[447]
    DIRECTION INPUT ;
    USE SIGNAL ;
    PORT
      LAYER M5 ;
        RECT  174.096 25.728 174.12 25.92 ;
    END
  END m_tx_d[447]
  PIN m_tx_d[448]
    DIRECTION INPUT ;
    USE SIGNAL ;
    PORT
      LAYER M5 ;
        RECT  177.264 25.728 177.288 25.92 ;
    END
  END m_tx_d[448]
  PIN m_tx_d[449]
    DIRECTION INPUT ;
    USE SIGNAL ;
    PORT
      LAYER M5 ;
        RECT  177.36 25.728 177.384 25.92 ;
    END
  END m_tx_d[449]
  PIN m_tx_d[44]
    DIRECTION INPUT ;
    USE SIGNAL ;
    PORT
      LAYER M5 ;
        RECT  9.168 25.728 9.192 25.92 ;
    END
  END m_tx_d[44]
  PIN m_tx_d[450]
    DIRECTION INPUT ;
    USE SIGNAL ;
    PORT
      LAYER M5 ;
        RECT  177.456 25.728 177.48 25.92 ;
    END
  END m_tx_d[450]
  PIN m_tx_d[451]
    DIRECTION INPUT ;
    USE SIGNAL ;
    PORT
      LAYER M5 ;
        RECT  177.552 25.728 177.576 25.92 ;
    END
  END m_tx_d[451]
  PIN m_tx_d[452]
    DIRECTION INPUT ;
    USE SIGNAL ;
    PORT
      LAYER M5 ;
        RECT  177.648 25.728 177.672 25.92 ;
    END
  END m_tx_d[452]
  PIN m_tx_d[453]
    DIRECTION INPUT ;
    USE SIGNAL ;
    PORT
      LAYER M5 ;
        RECT  177.744 25.728 177.768 25.92 ;
    END
  END m_tx_d[453]
  PIN m_tx_d[454]
    DIRECTION INPUT ;
    USE SIGNAL ;
    PORT
      LAYER M5 ;
        RECT  177.84 25.728 177.864 25.92 ;
    END
  END m_tx_d[454]
  PIN m_tx_d[455]
    DIRECTION INPUT ;
    USE SIGNAL ;
    PORT
      LAYER M5 ;
        RECT  177.936 25.728 177.96 25.92 ;
    END
  END m_tx_d[455]
  PIN m_tx_d[456]
    DIRECTION INPUT ;
    USE SIGNAL ;
    PORT
      LAYER M5 ;
        RECT  178.032 25.728 178.056 25.92 ;
    END
  END m_tx_d[456]
  PIN m_tx_d[457]
    DIRECTION INPUT ;
    USE SIGNAL ;
    PORT
      LAYER M5 ;
        RECT  178.128 25.728 178.152 25.92 ;
    END
  END m_tx_d[457]
  PIN m_tx_d[458]
    DIRECTION INPUT ;
    USE SIGNAL ;
    PORT
      LAYER M5 ;
        RECT  178.224 25.728 178.248 25.92 ;
    END
  END m_tx_d[458]
  PIN m_tx_d[459]
    DIRECTION INPUT ;
    USE SIGNAL ;
    PORT
      LAYER M5 ;
        RECT  178.32 25.728 178.344 25.92 ;
    END
  END m_tx_d[459]
  PIN m_tx_d[45]
    DIRECTION INPUT ;
    USE SIGNAL ;
    PORT
      LAYER M5 ;
        RECT  9.264 25.728 9.288 25.92 ;
    END
  END m_tx_d[45]
  PIN m_tx_d[460]
    DIRECTION INPUT ;
    USE SIGNAL ;
    PORT
      LAYER M5 ;
        RECT  178.416 25.728 178.44 25.92 ;
    END
  END m_tx_d[460]
  PIN m_tx_d[461]
    DIRECTION INPUT ;
    USE SIGNAL ;
    PORT
      LAYER M5 ;
        RECT  178.512 25.728 178.536 25.92 ;
    END
  END m_tx_d[461]
  PIN m_tx_d[462]
    DIRECTION INPUT ;
    USE SIGNAL ;
    PORT
      LAYER M5 ;
        RECT  178.608 25.728 178.632 25.92 ;
    END
  END m_tx_d[462]
  PIN m_tx_d[463]
    DIRECTION INPUT ;
    USE SIGNAL ;
    PORT
      LAYER M5 ;
        RECT  178.704 25.728 178.728 25.92 ;
    END
  END m_tx_d[463]
  PIN m_tx_d[464]
    DIRECTION INPUT ;
    USE SIGNAL ;
    PORT
      LAYER M5 ;
        RECT  178.8 25.728 178.824 25.92 ;
    END
  END m_tx_d[464]
  PIN m_tx_d[465]
    DIRECTION INPUT ;
    USE SIGNAL ;
    PORT
      LAYER M5 ;
        RECT  178.896 25.728 178.92 25.92 ;
    END
  END m_tx_d[465]
  PIN m_tx_d[466]
    DIRECTION INPUT ;
    USE SIGNAL ;
    PORT
      LAYER M5 ;
        RECT  178.992 25.728 179.016 25.92 ;
    END
  END m_tx_d[466]
  PIN m_tx_d[467]
    DIRECTION INPUT ;
    USE SIGNAL ;
    PORT
      LAYER M5 ;
        RECT  179.088 25.728 179.112 25.92 ;
    END
  END m_tx_d[467]
  PIN m_tx_d[468]
    DIRECTION INPUT ;
    USE SIGNAL ;
    PORT
      LAYER M5 ;
        RECT  179.184 25.728 179.208 25.92 ;
    END
  END m_tx_d[468]
  PIN m_tx_d[469]
    DIRECTION INPUT ;
    USE SIGNAL ;
    PORT
      LAYER M5 ;
        RECT  179.28 25.728 179.304 25.92 ;
    END
  END m_tx_d[469]
  PIN m_tx_d[46]
    DIRECTION INPUT ;
    USE SIGNAL ;
    PORT
      LAYER M5 ;
        RECT  9.36 25.728 9.384 25.92 ;
    END
  END m_tx_d[46]
  PIN m_tx_d[470]
    DIRECTION INPUT ;
    USE SIGNAL ;
    PORT
      LAYER M5 ;
        RECT  179.376 25.728 179.4 25.92 ;
    END
  END m_tx_d[470]
  PIN m_tx_d[471]
    DIRECTION INPUT ;
    USE SIGNAL ;
    PORT
      LAYER M5 ;
        RECT  179.472 25.728 179.496 25.92 ;
    END
  END m_tx_d[471]
  PIN m_tx_d[472]
    DIRECTION INPUT ;
    USE SIGNAL ;
    PORT
      LAYER M5 ;
        RECT  179.568 25.728 179.592 25.92 ;
    END
  END m_tx_d[472]
  PIN m_tx_d[473]
    DIRECTION INPUT ;
    USE SIGNAL ;
    PORT
      LAYER M5 ;
        RECT  179.664 25.728 179.688 25.92 ;
    END
  END m_tx_d[473]
  PIN m_tx_d[474]
    DIRECTION INPUT ;
    USE SIGNAL ;
    PORT
      LAYER M5 ;
        RECT  179.76 25.728 179.784 25.92 ;
    END
  END m_tx_d[474]
  PIN m_tx_d[475]
    DIRECTION INPUT ;
    USE SIGNAL ;
    PORT
      LAYER M5 ;
        RECT  179.856 25.728 179.88 25.92 ;
    END
  END m_tx_d[475]
  PIN m_tx_d[476]
    DIRECTION INPUT ;
    USE SIGNAL ;
    PORT
      LAYER M5 ;
        RECT  179.952 25.728 179.976 25.92 ;
    END
  END m_tx_d[476]
  PIN m_tx_d[477]
    DIRECTION INPUT ;
    USE SIGNAL ;
    PORT
      LAYER M5 ;
        RECT  180.048 25.728 180.072 25.92 ;
    END
  END m_tx_d[477]
  PIN m_tx_d[478]
    DIRECTION INPUT ;
    USE SIGNAL ;
    PORT
      LAYER M5 ;
        RECT  180.144 25.728 180.168 25.92 ;
    END
  END m_tx_d[478]
  PIN m_tx_d[479]
    DIRECTION INPUT ;
    USE SIGNAL ;
    PORT
      LAYER M5 ;
        RECT  180.24 25.728 180.264 25.92 ;
    END
  END m_tx_d[479]
  PIN m_tx_d[47]
    DIRECTION INPUT ;
    USE SIGNAL ;
    PORT
      LAYER M5 ;
        RECT  9.456 25.728 9.48 25.92 ;
    END
  END m_tx_d[47]
  PIN m_tx_d[480]
    DIRECTION INPUT ;
    USE SIGNAL ;
    PORT
      LAYER M5 ;
        RECT  218.976 25.728 219 25.92 ;
    END
  END m_tx_d[480]
  PIN m_tx_d[481]
    DIRECTION INPUT ;
    USE SIGNAL ;
    PORT
      LAYER M5 ;
        RECT  219.072 25.728 219.096 25.92 ;
    END
  END m_tx_d[481]
  PIN m_tx_d[482]
    DIRECTION INPUT ;
    USE SIGNAL ;
    PORT
      LAYER M5 ;
        RECT  219.168 25.728 219.192 25.92 ;
    END
  END m_tx_d[482]
  PIN m_tx_d[483]
    DIRECTION INPUT ;
    USE SIGNAL ;
    PORT
      LAYER M5 ;
        RECT  219.264 25.728 219.288 25.92 ;
    END
  END m_tx_d[483]
  PIN m_tx_d[484]
    DIRECTION INPUT ;
    USE SIGNAL ;
    PORT
      LAYER M5 ;
        RECT  219.36 25.728 219.384 25.92 ;
    END
  END m_tx_d[484]
  PIN m_tx_d[485]
    DIRECTION INPUT ;
    USE SIGNAL ;
    PORT
      LAYER M5 ;
        RECT  219.456 25.728 219.48 25.92 ;
    END
  END m_tx_d[485]
  PIN m_tx_d[486]
    DIRECTION INPUT ;
    USE SIGNAL ;
    PORT
      LAYER M5 ;
        RECT  219.552 25.728 219.576 25.92 ;
    END
  END m_tx_d[486]
  PIN m_tx_d[487]
    DIRECTION INPUT ;
    USE SIGNAL ;
    PORT
      LAYER M5 ;
        RECT  219.648 25.728 219.672 25.92 ;
    END
  END m_tx_d[487]
  PIN m_tx_d[488]
    DIRECTION INPUT ;
    USE SIGNAL ;
    PORT
      LAYER M5 ;
        RECT  219.744 25.728 219.768 25.92 ;
    END
  END m_tx_d[488]
  PIN m_tx_d[489]
    DIRECTION INPUT ;
    USE SIGNAL ;
    PORT
      LAYER M5 ;
        RECT  219.84 25.728 219.864 25.92 ;
    END
  END m_tx_d[489]
  PIN m_tx_d[48]
    DIRECTION INPUT ;
    USE SIGNAL ;
    PORT
      LAYER M5 ;
        RECT  9.552 25.728 9.576 25.92 ;
    END
  END m_tx_d[48]
  PIN m_tx_d[490]
    DIRECTION INPUT ;
    USE SIGNAL ;
    PORT
      LAYER M5 ;
        RECT  219.936 25.728 219.96 25.92 ;
    END
  END m_tx_d[490]
  PIN m_tx_d[491]
    DIRECTION INPUT ;
    USE SIGNAL ;
    PORT
      LAYER M5 ;
        RECT  220.032 25.728 220.056 25.92 ;
    END
  END m_tx_d[491]
  PIN m_tx_d[492]
    DIRECTION INPUT ;
    USE SIGNAL ;
    PORT
      LAYER M5 ;
        RECT  220.128 25.728 220.152 25.92 ;
    END
  END m_tx_d[492]
  PIN m_tx_d[493]
    DIRECTION INPUT ;
    USE SIGNAL ;
    PORT
      LAYER M5 ;
        RECT  220.224 25.728 220.248 25.92 ;
    END
  END m_tx_d[493]
  PIN m_tx_d[494]
    DIRECTION INPUT ;
    USE SIGNAL ;
    PORT
      LAYER M5 ;
        RECT  220.32 25.728 220.344 25.92 ;
    END
  END m_tx_d[494]
  PIN m_tx_d[495]
    DIRECTION INPUT ;
    USE SIGNAL ;
    PORT
      LAYER M5 ;
        RECT  220.416 25.728 220.44 25.92 ;
    END
  END m_tx_d[495]
  PIN m_tx_d[496]
    DIRECTION INPUT ;
    USE SIGNAL ;
    PORT
      LAYER M5 ;
        RECT  220.512 25.728 220.536 25.92 ;
    END
  END m_tx_d[496]
  PIN m_tx_d[497]
    DIRECTION INPUT ;
    USE SIGNAL ;
    PORT
      LAYER M5 ;
        RECT  220.608 25.728 220.632 25.92 ;
    END
  END m_tx_d[497]
  PIN m_tx_d[498]
    DIRECTION INPUT ;
    USE SIGNAL ;
    PORT
      LAYER M5 ;
        RECT  220.704 25.728 220.728 25.92 ;
    END
  END m_tx_d[498]
  PIN m_tx_d[499]
    DIRECTION INPUT ;
    USE SIGNAL ;
    PORT
      LAYER M5 ;
        RECT  220.8 25.728 220.824 25.92 ;
    END
  END m_tx_d[499]
  PIN m_tx_d[49]
    DIRECTION INPUT ;
    USE SIGNAL ;
    PORT
      LAYER M5 ;
        RECT  9.648 25.728 9.672 25.92 ;
    END
  END m_tx_d[49]
  PIN m_tx_d[4]
    DIRECTION INPUT ;
    USE SIGNAL ;
    PORT
      LAYER M5 ;
        RECT  18.288 25.728 18.312 25.92 ;
    END
  END m_tx_d[4]
  PIN m_tx_d[500]
    DIRECTION INPUT ;
    USE SIGNAL ;
    PORT
      LAYER M5 ;
        RECT  220.896 25.728 220.92 25.92 ;
    END
  END m_tx_d[500]
  PIN m_tx_d[501]
    DIRECTION INPUT ;
    USE SIGNAL ;
    PORT
      LAYER M5 ;
        RECT  220.992 25.728 221.016 25.92 ;
    END
  END m_tx_d[501]
  PIN m_tx_d[502]
    DIRECTION INPUT ;
    USE SIGNAL ;
    PORT
      LAYER M5 ;
        RECT  221.088 25.728 221.112 25.92 ;
    END
  END m_tx_d[502]
  PIN m_tx_d[503]
    DIRECTION INPUT ;
    USE SIGNAL ;
    PORT
      LAYER M5 ;
        RECT  221.184 25.728 221.208 25.92 ;
    END
  END m_tx_d[503]
  PIN m_tx_d[504]
    DIRECTION INPUT ;
    USE SIGNAL ;
    PORT
      LAYER M5 ;
        RECT  221.28 25.728 221.304 25.92 ;
    END
  END m_tx_d[504]
  PIN m_tx_d[505]
    DIRECTION INPUT ;
    USE SIGNAL ;
    PORT
      LAYER M5 ;
        RECT  221.376 25.728 221.4 25.92 ;
    END
  END m_tx_d[505]
  PIN m_tx_d[506]
    DIRECTION INPUT ;
    USE SIGNAL ;
    PORT
      LAYER M5 ;
        RECT  221.472 25.728 221.496 25.92 ;
    END
  END m_tx_d[506]
  PIN m_tx_d[507]
    DIRECTION INPUT ;
    USE SIGNAL ;
    PORT
      LAYER M5 ;
        RECT  221.568 25.728 221.592 25.92 ;
    END
  END m_tx_d[507]
  PIN m_tx_d[508]
    DIRECTION INPUT ;
    USE SIGNAL ;
    PORT
      LAYER M5 ;
        RECT  221.664 25.728 221.688 25.92 ;
    END
  END m_tx_d[508]
  PIN m_tx_d[509]
    DIRECTION INPUT ;
    USE SIGNAL ;
    PORT
      LAYER M5 ;
        RECT  221.76 25.728 221.784 25.92 ;
    END
  END m_tx_d[509]
  PIN m_tx_d[50]
    DIRECTION INPUT ;
    USE SIGNAL ;
    PORT
      LAYER M5 ;
        RECT  9.744 25.728 9.768 25.92 ;
    END
  END m_tx_d[50]
  PIN m_tx_d[510]
    DIRECTION INPUT ;
    USE SIGNAL ;
    PORT
      LAYER M5 ;
        RECT  221.856 25.728 221.88 25.92 ;
    END
  END m_tx_d[510]
  PIN m_tx_d[511]
    DIRECTION INPUT ;
    USE SIGNAL ;
    PORT
      LAYER M5 ;
        RECT  221.952 25.728 221.976 25.92 ;
    END
  END m_tx_d[511]
  PIN m_tx_d[512]
    DIRECTION INPUT ;
    USE SIGNAL ;
    PORT
      LAYER M5 ;
        RECT  224.88 25.728 224.904 25.92 ;
    END
  END m_tx_d[512]
  PIN m_tx_d[513]
    DIRECTION INPUT ;
    USE SIGNAL ;
    PORT
      LAYER M5 ;
        RECT  224.976 25.728 225 25.92 ;
    END
  END m_tx_d[513]
  PIN m_tx_d[514]
    DIRECTION INPUT ;
    USE SIGNAL ;
    PORT
      LAYER M5 ;
        RECT  225.072 25.728 225.096 25.92 ;
    END
  END m_tx_d[514]
  PIN m_tx_d[515]
    DIRECTION INPUT ;
    USE SIGNAL ;
    PORT
      LAYER M5 ;
        RECT  225.168 25.728 225.192 25.92 ;
    END
  END m_tx_d[515]
  PIN m_tx_d[516]
    DIRECTION INPUT ;
    USE SIGNAL ;
    PORT
      LAYER M5 ;
        RECT  225.264 25.728 225.288 25.92 ;
    END
  END m_tx_d[516]
  PIN m_tx_d[517]
    DIRECTION INPUT ;
    USE SIGNAL ;
    PORT
      LAYER M5 ;
        RECT  225.36 25.728 225.384 25.92 ;
    END
  END m_tx_d[517]
  PIN m_tx_d[518]
    DIRECTION INPUT ;
    USE SIGNAL ;
    PORT
      LAYER M5 ;
        RECT  225.456 25.728 225.48 25.92 ;
    END
  END m_tx_d[518]
  PIN m_tx_d[519]
    DIRECTION INPUT ;
    USE SIGNAL ;
    PORT
      LAYER M5 ;
        RECT  225.552 25.728 225.576 25.92 ;
    END
  END m_tx_d[519]
  PIN m_tx_d[51]
    DIRECTION INPUT ;
    USE SIGNAL ;
    PORT
      LAYER M5 ;
        RECT  9.84 25.728 9.864 25.92 ;
    END
  END m_tx_d[51]
  PIN m_tx_d[520]
    DIRECTION INPUT ;
    USE SIGNAL ;
    PORT
      LAYER M5 ;
        RECT  225.648 25.728 225.672 25.92 ;
    END
  END m_tx_d[520]
  PIN m_tx_d[521]
    DIRECTION INPUT ;
    USE SIGNAL ;
    PORT
      LAYER M5 ;
        RECT  225.744 25.728 225.768 25.92 ;
    END
  END m_tx_d[521]
  PIN m_tx_d[522]
    DIRECTION INPUT ;
    USE SIGNAL ;
    PORT
      LAYER M5 ;
        RECT  225.84 25.728 225.864 25.92 ;
    END
  END m_tx_d[522]
  PIN m_tx_d[523]
    DIRECTION INPUT ;
    USE SIGNAL ;
    PORT
      LAYER M5 ;
        RECT  225.936 25.728 225.96 25.92 ;
    END
  END m_tx_d[523]
  PIN m_tx_d[524]
    DIRECTION INPUT ;
    USE SIGNAL ;
    PORT
      LAYER M5 ;
        RECT  226.032 25.728 226.056 25.92 ;
    END
  END m_tx_d[524]
  PIN m_tx_d[525]
    DIRECTION INPUT ;
    USE SIGNAL ;
    PORT
      LAYER M5 ;
        RECT  226.128 25.728 226.152 25.92 ;
    END
  END m_tx_d[525]
  PIN m_tx_d[526]
    DIRECTION INPUT ;
    USE SIGNAL ;
    PORT
      LAYER M5 ;
        RECT  226.224 25.728 226.248 25.92 ;
    END
  END m_tx_d[526]
  PIN m_tx_d[527]
    DIRECTION INPUT ;
    USE SIGNAL ;
    PORT
      LAYER M5 ;
        RECT  226.32 25.728 226.344 25.92 ;
    END
  END m_tx_d[527]
  PIN m_tx_d[528]
    DIRECTION INPUT ;
    USE SIGNAL ;
    PORT
      LAYER M5 ;
        RECT  226.416 25.728 226.44 25.92 ;
    END
  END m_tx_d[528]
  PIN m_tx_d[529]
    DIRECTION INPUT ;
    USE SIGNAL ;
    PORT
      LAYER M5 ;
        RECT  226.512 25.728 226.536 25.92 ;
    END
  END m_tx_d[529]
  PIN m_tx_d[52]
    DIRECTION INPUT ;
    USE SIGNAL ;
    PORT
      LAYER M5 ;
        RECT  9.936 25.728 9.96 25.92 ;
    END
  END m_tx_d[52]
  PIN m_tx_d[530]
    DIRECTION INPUT ;
    USE SIGNAL ;
    PORT
      LAYER M5 ;
        RECT  226.608 25.728 226.632 25.92 ;
    END
  END m_tx_d[530]
  PIN m_tx_d[531]
    DIRECTION INPUT ;
    USE SIGNAL ;
    PORT
      LAYER M5 ;
        RECT  226.704 25.728 226.728 25.92 ;
    END
  END m_tx_d[531]
  PIN m_tx_d[532]
    DIRECTION INPUT ;
    USE SIGNAL ;
    PORT
      LAYER M5 ;
        RECT  226.8 25.728 226.824 25.92 ;
    END
  END m_tx_d[532]
  PIN m_tx_d[533]
    DIRECTION INPUT ;
    USE SIGNAL ;
    PORT
      LAYER M5 ;
        RECT  226.896 25.728 226.92 25.92 ;
    END
  END m_tx_d[533]
  PIN m_tx_d[534]
    DIRECTION INPUT ;
    USE SIGNAL ;
    PORT
      LAYER M5 ;
        RECT  226.992 25.728 227.016 25.92 ;
    END
  END m_tx_d[534]
  PIN m_tx_d[535]
    DIRECTION INPUT ;
    USE SIGNAL ;
    PORT
      LAYER M5 ;
        RECT  227.088 25.728 227.112 25.92 ;
    END
  END m_tx_d[535]
  PIN m_tx_d[536]
    DIRECTION INPUT ;
    USE SIGNAL ;
    PORT
      LAYER M5 ;
        RECT  227.184 25.728 227.208 25.92 ;
    END
  END m_tx_d[536]
  PIN m_tx_d[537]
    DIRECTION INPUT ;
    USE SIGNAL ;
    PORT
      LAYER M5 ;
        RECT  227.28 25.728 227.304 25.92 ;
    END
  END m_tx_d[537]
  PIN m_tx_d[538]
    DIRECTION INPUT ;
    USE SIGNAL ;
    PORT
      LAYER M5 ;
        RECT  227.376 25.728 227.4 25.92 ;
    END
  END m_tx_d[538]
  PIN m_tx_d[539]
    DIRECTION INPUT ;
    USE SIGNAL ;
    PORT
      LAYER M5 ;
        RECT  227.472 25.728 227.496 25.92 ;
    END
  END m_tx_d[539]
  PIN m_tx_d[53]
    DIRECTION INPUT ;
    USE SIGNAL ;
    PORT
      LAYER M5 ;
        RECT  10.032 25.728 10.056 25.92 ;
    END
  END m_tx_d[53]
  PIN m_tx_d[540]
    DIRECTION INPUT ;
    USE SIGNAL ;
    PORT
      LAYER M5 ;
        RECT  227.568 25.728 227.592 25.92 ;
    END
  END m_tx_d[540]
  PIN m_tx_d[541]
    DIRECTION INPUT ;
    USE SIGNAL ;
    PORT
      LAYER M5 ;
        RECT  227.664 25.728 227.688 25.92 ;
    END
  END m_tx_d[541]
  PIN m_tx_d[542]
    DIRECTION INPUT ;
    USE SIGNAL ;
    PORT
      LAYER M5 ;
        RECT  227.76 25.728 227.784 25.92 ;
    END
  END m_tx_d[542]
  PIN m_tx_d[543]
    DIRECTION INPUT ;
    USE SIGNAL ;
    PORT
      LAYER M5 ;
        RECT  227.856 25.728 227.88 25.92 ;
    END
  END m_tx_d[543]
  PIN m_tx_d[544]
    DIRECTION INPUT ;
    USE SIGNAL ;
    PORT
      LAYER M5 ;
        RECT  205.68 25.728 205.704 25.92 ;
    END
  END m_tx_d[544]
  PIN m_tx_d[54]
    DIRECTION INPUT ;
    USE SIGNAL ;
    PORT
      LAYER M5 ;
        RECT  10.128 25.728 10.152 25.92 ;
    END
  END m_tx_d[54]
  PIN m_tx_d[55]
    DIRECTION INPUT ;
    USE SIGNAL ;
    PORT
      LAYER M5 ;
        RECT  10.224 25.728 10.248 25.92 ;
    END
  END m_tx_d[55]
  PIN m_tx_d[56]
    DIRECTION INPUT ;
    USE SIGNAL ;
    PORT
      LAYER M5 ;
        RECT  10.32 25.728 10.344 25.92 ;
    END
  END m_tx_d[56]
  PIN m_tx_d[57]
    DIRECTION INPUT ;
    USE SIGNAL ;
    PORT
      LAYER M5 ;
        RECT  10.416 25.728 10.44 25.92 ;
    END
  END m_tx_d[57]
  PIN m_tx_d[58]
    DIRECTION INPUT ;
    USE SIGNAL ;
    PORT
      LAYER M5 ;
        RECT  10.512 25.728 10.536 25.92 ;
    END
  END m_tx_d[58]
  PIN m_tx_d[59]
    DIRECTION INPUT ;
    USE SIGNAL ;
    PORT
      LAYER M5 ;
        RECT  10.608 25.728 10.632 25.92 ;
    END
  END m_tx_d[59]
  PIN m_tx_d[5]
    DIRECTION INPUT ;
    USE SIGNAL ;
    PORT
      LAYER M5 ;
        RECT  18.384 25.728 18.408 25.92 ;
    END
  END m_tx_d[5]
  PIN m_tx_d[60]
    DIRECTION INPUT ;
    USE SIGNAL ;
    PORT
      LAYER M5 ;
        RECT  10.704 25.728 10.728 25.92 ;
    END
  END m_tx_d[60]
  PIN m_tx_d[61]
    DIRECTION INPUT ;
    USE SIGNAL ;
    PORT
      LAYER M5 ;
        RECT  10.8 25.728 10.824 25.92 ;
    END
  END m_tx_d[61]
  PIN m_tx_d[62]
    DIRECTION INPUT ;
    USE SIGNAL ;
    PORT
      LAYER M5 ;
        RECT  10.896 25.728 10.92 25.92 ;
    END
  END m_tx_d[62]
  PIN m_tx_d[63]
    DIRECTION INPUT ;
    USE SIGNAL ;
    PORT
      LAYER M5 ;
        RECT  10.992 25.728 11.016 25.92 ;
    END
  END m_tx_d[63]
  PIN m_tx_d[64]
    DIRECTION INPUT ;
    USE SIGNAL ;
    PORT
      LAYER M5 ;
        RECT  11.088 25.728 11.112 25.92 ;
    END
  END m_tx_d[64]
  PIN m_tx_d[65]
    DIRECTION INPUT ;
    USE SIGNAL ;
    PORT
      LAYER M5 ;
        RECT  11.184 25.728 11.208 25.92 ;
    END
  END m_tx_d[65]
  PIN m_tx_d[66]
    DIRECTION INPUT ;
    USE SIGNAL ;
    PORT
      LAYER M5 ;
        RECT  11.28 25.728 11.304 25.92 ;
    END
  END m_tx_d[66]
  PIN m_tx_d[67]
    DIRECTION INPUT ;
    USE SIGNAL ;
    PORT
      LAYER M5 ;
        RECT  11.376 25.728 11.4 25.92 ;
    END
  END m_tx_d[67]
  PIN m_tx_d[68]
    DIRECTION INPUT ;
    USE SIGNAL ;
    PORT
      LAYER M5 ;
        RECT  11.472 25.728 11.496 25.92 ;
    END
  END m_tx_d[68]
  PIN m_tx_d[69]
    DIRECTION INPUT ;
    USE SIGNAL ;
    PORT
      LAYER M5 ;
        RECT  11.568 25.728 11.592 25.92 ;
    END
  END m_tx_d[69]
  PIN m_tx_d[6]
    DIRECTION INPUT ;
    USE SIGNAL ;
    PORT
      LAYER M5 ;
        RECT  19.2 25.728 19.224 25.92 ;
    END
  END m_tx_d[6]
  PIN m_tx_d[70]
    DIRECTION INPUT ;
    USE SIGNAL ;
    PORT
      LAYER M5 ;
        RECT  11.664 25.728 11.688 25.92 ;
    END
  END m_tx_d[70]
  PIN m_tx_d[71]
    DIRECTION INPUT ;
    USE SIGNAL ;
    PORT
      LAYER M5 ;
        RECT  11.76 25.728 11.784 25.92 ;
    END
  END m_tx_d[71]
  PIN m_tx_d[72]
    DIRECTION INPUT ;
    USE SIGNAL ;
    PORT
      LAYER M5 ;
        RECT  11.856 25.728 11.88 25.92 ;
    END
  END m_tx_d[72]
  PIN m_tx_d[73]
    DIRECTION INPUT ;
    USE SIGNAL ;
    PORT
      LAYER M5 ;
        RECT  11.952 25.728 11.976 25.92 ;
    END
  END m_tx_d[73]
  PIN m_tx_d[74]
    DIRECTION INPUT ;
    USE SIGNAL ;
    PORT
      LAYER M5 ;
        RECT  12.048 25.728 12.072 25.92 ;
    END
  END m_tx_d[74]
  PIN m_tx_d[75]
    DIRECTION INPUT ;
    USE SIGNAL ;
    PORT
      LAYER M5 ;
        RECT  12.144 25.728 12.168 25.92 ;
    END
  END m_tx_d[75]
  PIN m_tx_d[76]
    DIRECTION INPUT ;
    USE SIGNAL ;
    PORT
      LAYER M5 ;
        RECT  12.24 25.728 12.264 25.92 ;
    END
  END m_tx_d[76]
  PIN m_tx_d[77]
    DIRECTION INPUT ;
    USE SIGNAL ;
    PORT
      LAYER M5 ;
        RECT  12.336 25.728 12.36 25.92 ;
    END
  END m_tx_d[77]
  PIN m_tx_d[78]
    DIRECTION INPUT ;
    USE SIGNAL ;
    PORT
      LAYER M5 ;
        RECT  12.432 25.728 12.456 25.92 ;
    END
  END m_tx_d[78]
  PIN m_tx_d[79]
    DIRECTION INPUT ;
    USE SIGNAL ;
    PORT
      LAYER M5 ;
        RECT  12.528 25.728 12.552 25.92 ;
    END
  END m_tx_d[79]
  PIN m_tx_d[7]
    DIRECTION INPUT ;
    USE SIGNAL ;
    PORT
      LAYER M5 ;
        RECT  19.296 25.728 19.32 25.92 ;
    END
  END m_tx_d[7]
  PIN m_tx_d[80]
    DIRECTION INPUT ;
    USE SIGNAL ;
    PORT
      LAYER M5 ;
        RECT  12.624 25.728 12.648 25.92 ;
    END
  END m_tx_d[80]
  PIN m_tx_d[81]
    DIRECTION INPUT ;
    USE SIGNAL ;
    PORT
      LAYER M5 ;
        RECT  12.72 25.728 12.744 25.92 ;
    END
  END m_tx_d[81]
  PIN m_tx_d[82]
    DIRECTION INPUT ;
    USE SIGNAL ;
    PORT
      LAYER M5 ;
        RECT  12.816 25.728 12.84 25.92 ;
    END
  END m_tx_d[82]
  PIN m_tx_d[83]
    DIRECTION INPUT ;
    USE SIGNAL ;
    PORT
      LAYER M5 ;
        RECT  12.912 25.728 12.936 25.92 ;
    END
  END m_tx_d[83]
  PIN m_tx_d[84]
    DIRECTION INPUT ;
    USE SIGNAL ;
    PORT
      LAYER M5 ;
        RECT  13.008 25.728 13.032 25.92 ;
    END
  END m_tx_d[84]
  PIN m_tx_d[85]
    DIRECTION INPUT ;
    USE SIGNAL ;
    PORT
      LAYER M5 ;
        RECT  13.776 25.728 13.8 25.92 ;
    END
  END m_tx_d[85]
  PIN m_tx_d[86]
    DIRECTION INPUT ;
    USE SIGNAL ;
    PORT
      LAYER M5 ;
        RECT  13.872 25.728 13.896 25.92 ;
    END
  END m_tx_d[86]
  PIN m_tx_d[87]
    DIRECTION INPUT ;
    USE SIGNAL ;
    PORT
      LAYER M5 ;
        RECT  13.968 25.728 13.992 25.92 ;
    END
  END m_tx_d[87]
  PIN m_tx_d[88]
    DIRECTION INPUT ;
    USE SIGNAL ;
    PORT
      LAYER M5 ;
        RECT  14.064 25.728 14.088 25.92 ;
    END
  END m_tx_d[88]
  PIN m_tx_d[89]
    DIRECTION INPUT ;
    USE SIGNAL ;
    PORT
      LAYER M5 ;
        RECT  14.16 25.728 14.184 25.92 ;
    END
  END m_tx_d[89]
  PIN m_tx_d[8]
    DIRECTION INPUT ;
    USE SIGNAL ;
    PORT
      LAYER M5 ;
        RECT  19.392 25.728 19.416 25.92 ;
    END
  END m_tx_d[8]
  PIN m_tx_d[90]
    DIRECTION INPUT ;
    USE SIGNAL ;
    PORT
      LAYER M5 ;
        RECT  14.256 25.728 14.28 25.92 ;
    END
  END m_tx_d[90]
  PIN m_tx_d[91]
    DIRECTION INPUT ;
    USE SIGNAL ;
    PORT
      LAYER M5 ;
        RECT  14.352 25.728 14.376 25.92 ;
    END
  END m_tx_d[91]
  PIN m_tx_d[92]
    DIRECTION INPUT ;
    USE SIGNAL ;
    PORT
      LAYER M5 ;
        RECT  14.448 25.728 14.472 25.92 ;
    END
  END m_tx_d[92]
  PIN m_tx_d[93]
    DIRECTION INPUT ;
    USE SIGNAL ;
    PORT
      LAYER M5 ;
        RECT  14.544 25.728 14.568 25.92 ;
    END
  END m_tx_d[93]
  PIN m_tx_d[94]
    DIRECTION INPUT ;
    USE SIGNAL ;
    PORT
      LAYER M5 ;
        RECT  14.64 25.728 14.664 25.92 ;
    END
  END m_tx_d[94]
  PIN m_tx_d[95]
    DIRECTION INPUT ;
    USE SIGNAL ;
    PORT
      LAYER M5 ;
        RECT  14.736 25.728 14.76 25.92 ;
    END
  END m_tx_d[95]
  PIN m_tx_d[96]
    DIRECTION INPUT ;
    USE SIGNAL ;
    PORT
      LAYER M5 ;
        RECT  14.832 25.728 14.856 25.92 ;
    END
  END m_tx_d[96]
  PIN m_tx_d[97]
    DIRECTION INPUT ;
    USE SIGNAL ;
    PORT
      LAYER M5 ;
        RECT  14.928 25.728 14.952 25.92 ;
    END
  END m_tx_d[97]
  PIN m_tx_d[98]
    DIRECTION INPUT ;
    USE SIGNAL ;
    PORT
      LAYER M5 ;
        RECT  15.024 25.728 15.048 25.92 ;
    END
  END m_tx_d[98]
  PIN m_tx_d[99]
    DIRECTION INPUT ;
    USE SIGNAL ;
    PORT
      LAYER M5 ;
        RECT  15.12 25.728 15.144 25.92 ;
    END
  END m_tx_d[99]
  PIN m_tx_d[9]
    DIRECTION INPUT ;
    USE SIGNAL ;
    PORT
      LAYER M5 ;
        RECT  19.488 25.728 19.512 25.92 ;
    END
  END m_tx_d[9]
  PIN m_tx_e[0]
    DIRECTION INPUT ;
    USE SIGNAL ;
    PORT
      LAYER M5 ;
        RECT  207.024 25.728 207.048 25.92 ;
    END
  END m_tx_e[0]
  PIN m_tx_e[10]
    DIRECTION INPUT ;
    USE SIGNAL ;
    PORT
      LAYER M5 ;
        RECT  208.656 25.728 208.68 25.92 ;
    END
  END m_tx_e[10]
  PIN m_tx_e[11]
    DIRECTION INPUT ;
    USE SIGNAL ;
    PORT
      LAYER M5 ;
        RECT  208.752 25.728 208.776 25.92 ;
    END
  END m_tx_e[11]
  PIN m_tx_e[12]
    DIRECTION INPUT ;
    USE SIGNAL ;
    PORT
      LAYER M5 ;
        RECT  208.848 25.728 208.872 25.92 ;
    END
  END m_tx_e[12]
  PIN m_tx_e[13]
    DIRECTION INPUT ;
    USE SIGNAL ;
    PORT
      LAYER M5 ;
        RECT  208.944 25.728 208.968 25.92 ;
    END
  END m_tx_e[13]
  PIN m_tx_e[14]
    DIRECTION INPUT ;
    USE SIGNAL ;
    PORT
      LAYER M5 ;
        RECT  209.04 25.728 209.064 25.92 ;
    END
  END m_tx_e[14]
  PIN m_tx_e[15]
    DIRECTION INPUT ;
    USE SIGNAL ;
    PORT
      LAYER M5 ;
        RECT  209.136 25.728 209.16 25.92 ;
    END
  END m_tx_e[15]
  PIN m_tx_e[16]
    DIRECTION INPUT ;
    USE SIGNAL ;
    PORT
      LAYER M5 ;
        RECT  209.232 25.728 209.256 25.92 ;
    END
  END m_tx_e[16]
  PIN m_tx_e[17]
    DIRECTION INPUT ;
    USE SIGNAL ;
    PORT
      LAYER M5 ;
        RECT  209.328 25.728 209.352 25.92 ;
    END
  END m_tx_e[17]
  PIN m_tx_e[18]
    DIRECTION INPUT ;
    USE SIGNAL ;
    PORT
      LAYER M5 ;
        RECT  212.592 25.728 212.616 25.92 ;
    END
  END m_tx_e[18]
  PIN m_tx_e[19]
    DIRECTION INPUT ;
    USE SIGNAL ;
    PORT
      LAYER M5 ;
        RECT  212.688 25.728 212.712 25.92 ;
    END
  END m_tx_e[19]
  PIN m_tx_e[1]
    DIRECTION INPUT ;
    USE SIGNAL ;
    PORT
      LAYER M5 ;
        RECT  207.12 25.728 207.144 25.92 ;
    END
  END m_tx_e[1]
  PIN m_tx_e[20]
    DIRECTION INPUT ;
    USE SIGNAL ;
    PORT
      LAYER M5 ;
        RECT  212.784 25.728 212.808 25.92 ;
    END
  END m_tx_e[20]
  PIN m_tx_e[21]
    DIRECTION INPUT ;
    USE SIGNAL ;
    PORT
      LAYER M5 ;
        RECT  212.496 25.728 212.52 25.92 ;
    END
  END m_tx_e[21]
  PIN m_tx_e[22]
    DIRECTION INPUT ;
    USE SIGNAL ;
    PORT
      LAYER M5 ;
        RECT  212.4 25.728 212.424 25.92 ;
    END
  END m_tx_e[22]
  PIN m_tx_e[23]
    DIRECTION INPUT ;
    USE SIGNAL ;
    PORT
      LAYER M5 ;
        RECT  213.6 25.728 213.624 25.92 ;
    END
  END m_tx_e[23]
  PIN m_tx_e[2]
    DIRECTION INPUT ;
    USE SIGNAL ;
    PORT
      LAYER M5 ;
        RECT  207.216 25.728 207.24 25.92 ;
    END
  END m_tx_e[2]
  PIN m_tx_e[3]
    DIRECTION INPUT ;
    USE SIGNAL ;
    PORT
      LAYER M5 ;
        RECT  207.312 25.728 207.336 25.92 ;
    END
  END m_tx_e[3]
  PIN m_tx_e[4]
    DIRECTION INPUT ;
    USE SIGNAL ;
    PORT
      LAYER M5 ;
        RECT  207.408 25.728 207.432 25.92 ;
    END
  END m_tx_e[4]
  PIN m_tx_e[5]
    DIRECTION INPUT ;
    USE SIGNAL ;
    PORT
      LAYER M5 ;
        RECT  208.176 25.728 208.2 25.92 ;
    END
  END m_tx_e[5]
  PIN m_tx_e[6]
    DIRECTION INPUT ;
    USE SIGNAL ;
    PORT
      LAYER M5 ;
        RECT  208.272 25.728 208.296 25.92 ;
    END
  END m_tx_e[6]
  PIN m_tx_e[7]
    DIRECTION INPUT ;
    USE SIGNAL ;
    PORT
      LAYER M5 ;
        RECT  208.368 25.728 208.392 25.92 ;
    END
  END m_tx_e[7]
  PIN m_tx_e[8]
    DIRECTION INPUT ;
    USE SIGNAL ;
    PORT
      LAYER M5 ;
        RECT  208.464 25.728 208.488 25.92 ;
    END
  END m_tx_e[8]
  PIN m_tx_e[9]
    DIRECTION INPUT ;
    USE SIGNAL ;
    PORT
      LAYER M5 ;
        RECT  208.56 25.728 208.584 25.92 ;
    END
  END m_tx_e[9]
  PIN m_tx_r
    DIRECTION OUTPUT ;
    USE SIGNAL ;
    PORT
      LAYER M5 ;
        RECT  205.776 25.728 205.8 25.92 ;
    END
  END m_tx_r
  PIN m_tx_s[0]
    DIRECTION INPUT ;
    USE SIGNAL ;
    PORT
      LAYER M5 ;
        RECT  205.872 25.728 205.896 25.92 ;
    END
  END m_tx_s[0]
  PIN m_tx_s[10]
    DIRECTION INPUT ;
    USE SIGNAL ;
    PORT
      LAYER M5 ;
        RECT  206.832 25.728 206.856 25.92 ;
    END
  END m_tx_s[10]
  PIN m_tx_s[11]
    DIRECTION INPUT ;
    USE SIGNAL ;
    PORT
      LAYER M5 ;
        RECT  206.928 25.728 206.952 25.92 ;
    END
  END m_tx_s[11]
  PIN m_tx_s[1]
    DIRECTION INPUT ;
    USE SIGNAL ;
    PORT
      LAYER M5 ;
        RECT  205.968 25.728 205.992 25.92 ;
    END
  END m_tx_s[1]
  PIN m_tx_s[2]
    DIRECTION INPUT ;
    USE SIGNAL ;
    PORT
      LAYER M5 ;
        RECT  206.064 25.728 206.088 25.92 ;
    END
  END m_tx_s[2]
  PIN m_tx_s[3]
    DIRECTION INPUT ;
    USE SIGNAL ;
    PORT
      LAYER M5 ;
        RECT  206.16 25.728 206.184 25.92 ;
    END
  END m_tx_s[3]
  PIN m_tx_s[4]
    DIRECTION INPUT ;
    USE SIGNAL ;
    PORT
      LAYER M5 ;
        RECT  206.256 25.728 206.28 25.92 ;
    END
  END m_tx_s[4]
  PIN m_tx_s[5]
    DIRECTION INPUT ;
    USE SIGNAL ;
    PORT
      LAYER M5 ;
        RECT  206.352 25.728 206.376 25.92 ;
    END
  END m_tx_s[5]
  PIN m_tx_s[6]
    DIRECTION INPUT ;
    USE SIGNAL ;
    PORT
      LAYER M5 ;
        RECT  206.448 25.728 206.472 25.92 ;
    END
  END m_tx_s[6]
  PIN m_tx_s[7]
    DIRECTION INPUT ;
    USE SIGNAL ;
    PORT
      LAYER M5 ;
        RECT  206.544 25.728 206.568 25.92 ;
    END
  END m_tx_s[7]
  PIN m_tx_s[8]
    DIRECTION INPUT ;
    USE SIGNAL ;
    PORT
      LAYER M5 ;
        RECT  206.64 25.728 206.664 25.92 ;
    END
  END m_tx_s[8]
  PIN m_tx_s[9]
    DIRECTION INPUT ;
    USE SIGNAL ;
    PORT
      LAYER M5 ;
        RECT  206.736 25.728 206.76 25.92 ;
    END
  END m_tx_s[9]
  PIN m_tx_v
    DIRECTION INPUT ;
    USE SIGNAL ;
    PORT
      LAYER M5 ;
        RECT  213.696 25.728 213.72 25.92 ;
    END
  END m_tx_v
  PIN rst_n
    DIRECTION INPUT ;
    USE SIGNAL ;
    PORT
      LAYER M5 ;
        RECT  124.272 0 124.296 0.192 ;
    END
  END rst_n
  PIN tx_cr
    DIRECTION INPUT ;
    USE SIGNAL ;
    PORT
      LAYER M5 ;
        RECT  124.176 0 124.2 0.192 ;
    END
  END tx_cr
  PIN tx_d[0]
    DIRECTION OUTPUT ;
    USE SIGNAL ;
    PORT
      LAYER M5 ;
        RECT  60.096 0 60.12 0.192 ;
    END
  END tx_d[0]
  PIN tx_d[100]
    DIRECTION OUTPUT ;
    USE SIGNAL ;
    PORT
      LAYER M5 ;
        RECT  71.04 0 71.064 0.192 ;
    END
  END tx_d[100]
  PIN tx_d[101]
    DIRECTION OUTPUT ;
    USE SIGNAL ;
    PORT
      LAYER M5 ;
        RECT  71.136 0 71.16 0.192 ;
    END
  END tx_d[101]
  PIN tx_d[102]
    DIRECTION OUTPUT ;
    USE SIGNAL ;
    PORT
      LAYER M5 ;
        RECT  71.232 0 71.256 0.192 ;
    END
  END tx_d[102]
  PIN tx_d[103]
    DIRECTION OUTPUT ;
    USE SIGNAL ;
    PORT
      LAYER M5 ;
        RECT  71.328 0 71.352 0.192 ;
    END
  END tx_d[103]
  PIN tx_d[104]
    DIRECTION OUTPUT ;
    USE SIGNAL ;
    PORT
      LAYER M5 ;
        RECT  71.424 0 71.448 0.192 ;
    END
  END tx_d[104]
  PIN tx_d[105]
    DIRECTION OUTPUT ;
    USE SIGNAL ;
    PORT
      LAYER M5 ;
        RECT  71.52 0 71.544 0.192 ;
    END
  END tx_d[105]
  PIN tx_d[106]
    DIRECTION OUTPUT ;
    USE SIGNAL ;
    PORT
      LAYER M5 ;
        RECT  71.616 0 71.64 0.192 ;
    END
  END tx_d[106]
  PIN tx_d[107]
    DIRECTION OUTPUT ;
    USE SIGNAL ;
    PORT
      LAYER M5 ;
        RECT  71.712 0 71.736 0.192 ;
    END
  END tx_d[107]
  PIN tx_d[108]
    DIRECTION OUTPUT ;
    USE SIGNAL ;
    PORT
      LAYER M5 ;
        RECT  71.808 0 71.832 0.192 ;
    END
  END tx_d[108]
  PIN tx_d[109]
    DIRECTION OUTPUT ;
    USE SIGNAL ;
    PORT
      LAYER M5 ;
        RECT  71.904 0 71.928 0.192 ;
    END
  END tx_d[109]
  PIN tx_d[10]
    DIRECTION OUTPUT ;
    USE SIGNAL ;
    PORT
      LAYER M5 ;
        RECT  61.056 0 61.08 0.192 ;
    END
  END tx_d[10]
  PIN tx_d[110]
    DIRECTION OUTPUT ;
    USE SIGNAL ;
    PORT
      LAYER M5 ;
        RECT  72 0 72.024 0.192 ;
    END
  END tx_d[110]
  PIN tx_d[111]
    DIRECTION OUTPUT ;
    USE SIGNAL ;
    PORT
      LAYER M5 ;
        RECT  72.096 0 72.12 0.192 ;
    END
  END tx_d[111]
  PIN tx_d[112]
    DIRECTION OUTPUT ;
    USE SIGNAL ;
    PORT
      LAYER M5 ;
        RECT  72.192 0 72.216 0.192 ;
    END
  END tx_d[112]
  PIN tx_d[113]
    DIRECTION OUTPUT ;
    USE SIGNAL ;
    PORT
      LAYER M5 ;
        RECT  72.288 0 72.312 0.192 ;
    END
  END tx_d[113]
  PIN tx_d[114]
    DIRECTION OUTPUT ;
    USE SIGNAL ;
    PORT
      LAYER M5 ;
        RECT  72.384 0 72.408 0.192 ;
    END
  END tx_d[114]
  PIN tx_d[115]
    DIRECTION OUTPUT ;
    USE SIGNAL ;
    PORT
      LAYER M5 ;
        RECT  73.2 0 73.224 0.192 ;
    END
  END tx_d[115]
  PIN tx_d[116]
    DIRECTION OUTPUT ;
    USE SIGNAL ;
    PORT
      LAYER M5 ;
        RECT  73.296 0 73.32 0.192 ;
    END
  END tx_d[116]
  PIN tx_d[117]
    DIRECTION OUTPUT ;
    USE SIGNAL ;
    PORT
      LAYER M5 ;
        RECT  73.392 0 73.416 0.192 ;
    END
  END tx_d[117]
  PIN tx_d[118]
    DIRECTION OUTPUT ;
    USE SIGNAL ;
    PORT
      LAYER M5 ;
        RECT  73.488 0 73.512 0.192 ;
    END
  END tx_d[118]
  PIN tx_d[119]
    DIRECTION OUTPUT ;
    USE SIGNAL ;
    PORT
      LAYER M5 ;
        RECT  73.584 0 73.608 0.192 ;
    END
  END tx_d[119]
  PIN tx_d[11]
    DIRECTION OUTPUT ;
    USE SIGNAL ;
    PORT
      LAYER M5 ;
        RECT  61.152 0 61.176 0.192 ;
    END
  END tx_d[11]
  PIN tx_d[120]
    DIRECTION OUTPUT ;
    USE SIGNAL ;
    PORT
      LAYER M5 ;
        RECT  73.68 0 73.704 0.192 ;
    END
  END tx_d[120]
  PIN tx_d[121]
    DIRECTION OUTPUT ;
    USE SIGNAL ;
    PORT
      LAYER M5 ;
        RECT  73.776 0 73.8 0.192 ;
    END
  END tx_d[121]
  PIN tx_d[122]
    DIRECTION OUTPUT ;
    USE SIGNAL ;
    PORT
      LAYER M5 ;
        RECT  73.872 0 73.896 0.192 ;
    END
  END tx_d[122]
  PIN tx_d[123]
    DIRECTION OUTPUT ;
    USE SIGNAL ;
    PORT
      LAYER M5 ;
        RECT  73.968 0 73.992 0.192 ;
    END
  END tx_d[123]
  PIN tx_d[124]
    DIRECTION OUTPUT ;
    USE SIGNAL ;
    PORT
      LAYER M5 ;
        RECT  74.064 0 74.088 0.192 ;
    END
  END tx_d[124]
  PIN tx_d[125]
    DIRECTION OUTPUT ;
    USE SIGNAL ;
    PORT
      LAYER M5 ;
        RECT  74.16 0 74.184 0.192 ;
    END
  END tx_d[125]
  PIN tx_d[126]
    DIRECTION OUTPUT ;
    USE SIGNAL ;
    PORT
      LAYER M5 ;
        RECT  74.256 0 74.28 0.192 ;
    END
  END tx_d[126]
  PIN tx_d[127]
    DIRECTION OUTPUT ;
    USE SIGNAL ;
    PORT
      LAYER M5 ;
        RECT  74.352 0 74.376 0.192 ;
    END
  END tx_d[127]
  PIN tx_d[128]
    DIRECTION OUTPUT ;
    USE SIGNAL ;
    PORT
      LAYER M5 ;
        RECT  74.448 0 74.472 0.192 ;
    END
  END tx_d[128]
  PIN tx_d[129]
    DIRECTION OUTPUT ;
    USE SIGNAL ;
    PORT
      LAYER M5 ;
        RECT  74.544 0 74.568 0.192 ;
    END
  END tx_d[129]
  PIN tx_d[12]
    DIRECTION OUTPUT ;
    USE SIGNAL ;
    PORT
      LAYER M5 ;
        RECT  61.248 0 61.272 0.192 ;
    END
  END tx_d[12]
  PIN tx_d[130]
    DIRECTION OUTPUT ;
    USE SIGNAL ;
    PORT
      LAYER M5 ;
        RECT  74.64 0 74.664 0.192 ;
    END
  END tx_d[130]
  PIN tx_d[131]
    DIRECTION OUTPUT ;
    USE SIGNAL ;
    PORT
      LAYER M5 ;
        RECT  74.736 0 74.76 0.192 ;
    END
  END tx_d[131]
  PIN tx_d[132]
    DIRECTION OUTPUT ;
    USE SIGNAL ;
    PORT
      LAYER M5 ;
        RECT  74.832 0 74.856 0.192 ;
    END
  END tx_d[132]
  PIN tx_d[133]
    DIRECTION OUTPUT ;
    USE SIGNAL ;
    PORT
      LAYER M5 ;
        RECT  74.928 0 74.952 0.192 ;
    END
  END tx_d[133]
  PIN tx_d[134]
    DIRECTION OUTPUT ;
    USE SIGNAL ;
    PORT
      LAYER M5 ;
        RECT  75.024 0 75.048 0.192 ;
    END
  END tx_d[134]
  PIN tx_d[135]
    DIRECTION OUTPUT ;
    USE SIGNAL ;
    PORT
      LAYER M5 ;
        RECT  75.12 0 75.144 0.192 ;
    END
  END tx_d[135]
  PIN tx_d[136]
    DIRECTION OUTPUT ;
    USE SIGNAL ;
    PORT
      LAYER M5 ;
        RECT  75.216 0 75.24 0.192 ;
    END
  END tx_d[136]
  PIN tx_d[137]
    DIRECTION OUTPUT ;
    USE SIGNAL ;
    PORT
      LAYER M5 ;
        RECT  75.312 0 75.336 0.192 ;
    END
  END tx_d[137]
  PIN tx_d[138]
    DIRECTION OUTPUT ;
    USE SIGNAL ;
    PORT
      LAYER M5 ;
        RECT  75.408 0 75.432 0.192 ;
    END
  END tx_d[138]
  PIN tx_d[139]
    DIRECTION OUTPUT ;
    USE SIGNAL ;
    PORT
      LAYER M5 ;
        RECT  75.504 0 75.528 0.192 ;
    END
  END tx_d[139]
  PIN tx_d[13]
    DIRECTION OUTPUT ;
    USE SIGNAL ;
    PORT
      LAYER M5 ;
        RECT  61.344 0 61.368 0.192 ;
    END
  END tx_d[13]
  PIN tx_d[140]
    DIRECTION OUTPUT ;
    USE SIGNAL ;
    PORT
      LAYER M5 ;
        RECT  75.6 0 75.624 0.192 ;
    END
  END tx_d[140]
  PIN tx_d[141]
    DIRECTION OUTPUT ;
    USE SIGNAL ;
    PORT
      LAYER M5 ;
        RECT  75.696 0 75.72 0.192 ;
    END
  END tx_d[141]
  PIN tx_d[142]
    DIRECTION OUTPUT ;
    USE SIGNAL ;
    PORT
      LAYER M5 ;
        RECT  75.792 0 75.816 0.192 ;
    END
  END tx_d[142]
  PIN tx_d[143]
    DIRECTION OUTPUT ;
    USE SIGNAL ;
    PORT
      LAYER M5 ;
        RECT  75.888 0 75.912 0.192 ;
    END
  END tx_d[143]
  PIN tx_d[144]
    DIRECTION OUTPUT ;
    USE SIGNAL ;
    PORT
      LAYER M5 ;
        RECT  75.984 0 76.008 0.192 ;
    END
  END tx_d[144]
  PIN tx_d[145]
    DIRECTION OUTPUT ;
    USE SIGNAL ;
    PORT
      LAYER M5 ;
        RECT  76.08 0 76.104 0.192 ;
    END
  END tx_d[145]
  PIN tx_d[146]
    DIRECTION OUTPUT ;
    USE SIGNAL ;
    PORT
      LAYER M5 ;
        RECT  76.176 0 76.2 0.192 ;
    END
  END tx_d[146]
  PIN tx_d[147]
    DIRECTION OUTPUT ;
    USE SIGNAL ;
    PORT
      LAYER M5 ;
        RECT  76.272 0 76.296 0.192 ;
    END
  END tx_d[147]
  PIN tx_d[148]
    DIRECTION OUTPUT ;
    USE SIGNAL ;
    PORT
      LAYER M5 ;
        RECT  76.368 0 76.392 0.192 ;
    END
  END tx_d[148]
  PIN tx_d[149]
    DIRECTION OUTPUT ;
    USE SIGNAL ;
    PORT
      LAYER M5 ;
        RECT  76.464 0 76.488 0.192 ;
    END
  END tx_d[149]
  PIN tx_d[14]
    DIRECTION OUTPUT ;
    USE SIGNAL ;
    PORT
      LAYER M5 ;
        RECT  61.44 0 61.464 0.192 ;
    END
  END tx_d[14]
  PIN tx_d[150]
    DIRECTION OUTPUT ;
    USE SIGNAL ;
    PORT
      LAYER M5 ;
        RECT  76.56 0 76.584 0.192 ;
    END
  END tx_d[150]
  PIN tx_d[151]
    DIRECTION OUTPUT ;
    USE SIGNAL ;
    PORT
      LAYER M5 ;
        RECT  76.656 0 76.68 0.192 ;
    END
  END tx_d[151]
  PIN tx_d[152]
    DIRECTION OUTPUT ;
    USE SIGNAL ;
    PORT
      LAYER M5 ;
        RECT  76.752 0 76.776 0.192 ;
    END
  END tx_d[152]
  PIN tx_d[153]
    DIRECTION OUTPUT ;
    USE SIGNAL ;
    PORT
      LAYER M5 ;
        RECT  76.848 0 76.872 0.192 ;
    END
  END tx_d[153]
  PIN tx_d[154]
    DIRECTION OUTPUT ;
    USE SIGNAL ;
    PORT
      LAYER M5 ;
        RECT  76.944 0 76.968 0.192 ;
    END
  END tx_d[154]
  PIN tx_d[155]
    DIRECTION OUTPUT ;
    USE SIGNAL ;
    PORT
      LAYER M5 ;
        RECT  77.04 0 77.064 0.192 ;
    END
  END tx_d[155]
  PIN tx_d[156]
    DIRECTION OUTPUT ;
    USE SIGNAL ;
    PORT
      LAYER M5 ;
        RECT  77.136 0 77.16 0.192 ;
    END
  END tx_d[156]
  PIN tx_d[157]
    DIRECTION OUTPUT ;
    USE SIGNAL ;
    PORT
      LAYER M5 ;
        RECT  77.232 0 77.256 0.192 ;
    END
  END tx_d[157]
  PIN tx_d[158]
    DIRECTION OUTPUT ;
    USE SIGNAL ;
    PORT
      LAYER M5 ;
        RECT  77.328 0 77.352 0.192 ;
    END
  END tx_d[158]
  PIN tx_d[159]
    DIRECTION OUTPUT ;
    USE SIGNAL ;
    PORT
      LAYER M5 ;
        RECT  77.424 0 77.448 0.192 ;
    END
  END tx_d[159]
  PIN tx_d[15]
    DIRECTION OUTPUT ;
    USE SIGNAL ;
    PORT
      LAYER M5 ;
        RECT  61.536 0 61.56 0.192 ;
    END
  END tx_d[15]
  PIN tx_d[160]
    DIRECTION OUTPUT ;
    USE SIGNAL ;
    PORT
      LAYER M5 ;
        RECT  77.52 0 77.544 0.192 ;
    END
  END tx_d[160]
  PIN tx_d[161]
    DIRECTION OUTPUT ;
    USE SIGNAL ;
    PORT
      LAYER M5 ;
        RECT  77.616 0 77.64 0.192 ;
    END
  END tx_d[161]
  PIN tx_d[162]
    DIRECTION OUTPUT ;
    USE SIGNAL ;
    PORT
      LAYER M5 ;
        RECT  77.712 0 77.736 0.192 ;
    END
  END tx_d[162]
  PIN tx_d[163]
    DIRECTION OUTPUT ;
    USE SIGNAL ;
    PORT
      LAYER M5 ;
        RECT  77.808 0 77.832 0.192 ;
    END
  END tx_d[163]
  PIN tx_d[164]
    DIRECTION OUTPUT ;
    USE SIGNAL ;
    PORT
      LAYER M5 ;
        RECT  78.576 0 78.6 0.192 ;
    END
  END tx_d[164]
  PIN tx_d[165]
    DIRECTION OUTPUT ;
    USE SIGNAL ;
    PORT
      LAYER M5 ;
        RECT  78.672 0 78.696 0.192 ;
    END
  END tx_d[165]
  PIN tx_d[166]
    DIRECTION OUTPUT ;
    USE SIGNAL ;
    PORT
      LAYER M5 ;
        RECT  78.768 0 78.792 0.192 ;
    END
  END tx_d[166]
  PIN tx_d[167]
    DIRECTION OUTPUT ;
    USE SIGNAL ;
    PORT
      LAYER M5 ;
        RECT  78.864 0 78.888 0.192 ;
    END
  END tx_d[167]
  PIN tx_d[168]
    DIRECTION OUTPUT ;
    USE SIGNAL ;
    PORT
      LAYER M5 ;
        RECT  78.96 0 78.984 0.192 ;
    END
  END tx_d[168]
  PIN tx_d[169]
    DIRECTION OUTPUT ;
    USE SIGNAL ;
    PORT
      LAYER M5 ;
        RECT  79.056 0 79.08 0.192 ;
    END
  END tx_d[169]
  PIN tx_d[16]
    DIRECTION OUTPUT ;
    USE SIGNAL ;
    PORT
      LAYER M5 ;
        RECT  61.632 0 61.656 0.192 ;
    END
  END tx_d[16]
  PIN tx_d[170]
    DIRECTION OUTPUT ;
    USE SIGNAL ;
    PORT
      LAYER M5 ;
        RECT  79.152 0 79.176 0.192 ;
    END
  END tx_d[170]
  PIN tx_d[171]
    DIRECTION OUTPUT ;
    USE SIGNAL ;
    PORT
      LAYER M5 ;
        RECT  79.248 0 79.272 0.192 ;
    END
  END tx_d[171]
  PIN tx_d[172]
    DIRECTION OUTPUT ;
    USE SIGNAL ;
    PORT
      LAYER M5 ;
        RECT  79.344 0 79.368 0.192 ;
    END
  END tx_d[172]
  PIN tx_d[173]
    DIRECTION OUTPUT ;
    USE SIGNAL ;
    PORT
      LAYER M5 ;
        RECT  79.44 0 79.464 0.192 ;
    END
  END tx_d[173]
  PIN tx_d[174]
    DIRECTION OUTPUT ;
    USE SIGNAL ;
    PORT
      LAYER M5 ;
        RECT  79.536 0 79.56 0.192 ;
    END
  END tx_d[174]
  PIN tx_d[175]
    DIRECTION OUTPUT ;
    USE SIGNAL ;
    PORT
      LAYER M5 ;
        RECT  79.632 0 79.656 0.192 ;
    END
  END tx_d[175]
  PIN tx_d[176]
    DIRECTION OUTPUT ;
    USE SIGNAL ;
    PORT
      LAYER M5 ;
        RECT  79.728 0 79.752 0.192 ;
    END
  END tx_d[176]
  PIN tx_d[177]
    DIRECTION OUTPUT ;
    USE SIGNAL ;
    PORT
      LAYER M5 ;
        RECT  79.824 0 79.848 0.192 ;
    END
  END tx_d[177]
  PIN tx_d[178]
    DIRECTION OUTPUT ;
    USE SIGNAL ;
    PORT
      LAYER M5 ;
        RECT  79.92 0 79.944 0.192 ;
    END
  END tx_d[178]
  PIN tx_d[179]
    DIRECTION OUTPUT ;
    USE SIGNAL ;
    PORT
      LAYER M5 ;
        RECT  80.016 0 80.04 0.192 ;
    END
  END tx_d[179]
  PIN tx_d[17]
    DIRECTION OUTPUT ;
    USE SIGNAL ;
    PORT
      LAYER M5 ;
        RECT  62.4 0 62.424 0.192 ;
    END
  END tx_d[17]
  PIN tx_d[180]
    DIRECTION OUTPUT ;
    USE SIGNAL ;
    PORT
      LAYER M5 ;
        RECT  80.112 0 80.136 0.192 ;
    END
  END tx_d[180]
  PIN tx_d[181]
    DIRECTION OUTPUT ;
    USE SIGNAL ;
    PORT
      LAYER M5 ;
        RECT  80.208 0 80.232 0.192 ;
    END
  END tx_d[181]
  PIN tx_d[182]
    DIRECTION OUTPUT ;
    USE SIGNAL ;
    PORT
      LAYER M5 ;
        RECT  80.304 0 80.328 0.192 ;
    END
  END tx_d[182]
  PIN tx_d[183]
    DIRECTION OUTPUT ;
    USE SIGNAL ;
    PORT
      LAYER M5 ;
        RECT  80.4 0 80.424 0.192 ;
    END
  END tx_d[183]
  PIN tx_d[184]
    DIRECTION OUTPUT ;
    USE SIGNAL ;
    PORT
      LAYER M5 ;
        RECT  80.496 0 80.52 0.192 ;
    END
  END tx_d[184]
  PIN tx_d[185]
    DIRECTION OUTPUT ;
    USE SIGNAL ;
    PORT
      LAYER M5 ;
        RECT  80.592 0 80.616 0.192 ;
    END
  END tx_d[185]
  PIN tx_d[186]
    DIRECTION OUTPUT ;
    USE SIGNAL ;
    PORT
      LAYER M5 ;
        RECT  80.688 0 80.712 0.192 ;
    END
  END tx_d[186]
  PIN tx_d[187]
    DIRECTION OUTPUT ;
    USE SIGNAL ;
    PORT
      LAYER M5 ;
        RECT  80.784 0 80.808 0.192 ;
    END
  END tx_d[187]
  PIN tx_d[188]
    DIRECTION OUTPUT ;
    USE SIGNAL ;
    PORT
      LAYER M5 ;
        RECT  80.88 0 80.904 0.192 ;
    END
  END tx_d[188]
  PIN tx_d[189]
    DIRECTION OUTPUT ;
    USE SIGNAL ;
    PORT
      LAYER M5 ;
        RECT  80.976 0 81 0.192 ;
    END
  END tx_d[189]
  PIN tx_d[18]
    DIRECTION OUTPUT ;
    USE SIGNAL ;
    PORT
      LAYER M5 ;
        RECT  62.496 0 62.52 0.192 ;
    END
  END tx_d[18]
  PIN tx_d[190]
    DIRECTION OUTPUT ;
    USE SIGNAL ;
    PORT
      LAYER M5 ;
        RECT  81.072 0 81.096 0.192 ;
    END
  END tx_d[190]
  PIN tx_d[191]
    DIRECTION OUTPUT ;
    USE SIGNAL ;
    PORT
      LAYER M5 ;
        RECT  81.168 0 81.192 0.192 ;
    END
  END tx_d[191]
  PIN tx_d[192]
    DIRECTION OUTPUT ;
    USE SIGNAL ;
    PORT
      LAYER M5 ;
        RECT  81.264 0 81.288 0.192 ;
    END
  END tx_d[192]
  PIN tx_d[193]
    DIRECTION OUTPUT ;
    USE SIGNAL ;
    PORT
      LAYER M5 ;
        RECT  81.36 0 81.384 0.192 ;
    END
  END tx_d[193]
  PIN tx_d[194]
    DIRECTION OUTPUT ;
    USE SIGNAL ;
    PORT
      LAYER M5 ;
        RECT  81.456 0 81.48 0.192 ;
    END
  END tx_d[194]
  PIN tx_d[195]
    DIRECTION OUTPUT ;
    USE SIGNAL ;
    PORT
      LAYER M5 ;
        RECT  81.552 0 81.576 0.192 ;
    END
  END tx_d[195]
  PIN tx_d[196]
    DIRECTION OUTPUT ;
    USE SIGNAL ;
    PORT
      LAYER M5 ;
        RECT  81.648 0 81.672 0.192 ;
    END
  END tx_d[196]
  PIN tx_d[197]
    DIRECTION OUTPUT ;
    USE SIGNAL ;
    PORT
      LAYER M5 ;
        RECT  81.744 0 81.768 0.192 ;
    END
  END tx_d[197]
  PIN tx_d[198]
    DIRECTION OUTPUT ;
    USE SIGNAL ;
    PORT
      LAYER M5 ;
        RECT  81.84 0 81.864 0.192 ;
    END
  END tx_d[198]
  PIN tx_d[199]
    DIRECTION OUTPUT ;
    USE SIGNAL ;
    PORT
      LAYER M5 ;
        RECT  81.936 0 81.96 0.192 ;
    END
  END tx_d[199]
  PIN tx_d[19]
    DIRECTION OUTPUT ;
    USE SIGNAL ;
    PORT
      LAYER M5 ;
        RECT  62.592 0 62.616 0.192 ;
    END
  END tx_d[19]
  PIN tx_d[1]
    DIRECTION OUTPUT ;
    USE SIGNAL ;
    PORT
      LAYER M5 ;
        RECT  60.192 0 60.216 0.192 ;
    END
  END tx_d[1]
  PIN tx_d[200]
    DIRECTION OUTPUT ;
    USE SIGNAL ;
    PORT
      LAYER M5 ;
        RECT  82.032 0 82.056 0.192 ;
    END
  END tx_d[200]
  PIN tx_d[201]
    DIRECTION OUTPUT ;
    USE SIGNAL ;
    PORT
      LAYER M5 ;
        RECT  82.128 0 82.152 0.192 ;
    END
  END tx_d[201]
  PIN tx_d[202]
    DIRECTION OUTPUT ;
    USE SIGNAL ;
    PORT
      LAYER M5 ;
        RECT  82.224 0 82.248 0.192 ;
    END
  END tx_d[202]
  PIN tx_d[203]
    DIRECTION OUTPUT ;
    USE SIGNAL ;
    PORT
      LAYER M5 ;
        RECT  82.32 0 82.344 0.192 ;
    END
  END tx_d[203]
  PIN tx_d[204]
    DIRECTION OUTPUT ;
    USE SIGNAL ;
    PORT
      LAYER M5 ;
        RECT  82.416 0 82.44 0.192 ;
    END
  END tx_d[204]
  PIN tx_d[205]
    DIRECTION OUTPUT ;
    USE SIGNAL ;
    PORT
      LAYER M5 ;
        RECT  82.512 0 82.536 0.192 ;
    END
  END tx_d[205]
  PIN tx_d[206]
    DIRECTION OUTPUT ;
    USE SIGNAL ;
    PORT
      LAYER M5 ;
        RECT  82.608 0 82.632 0.192 ;
    END
  END tx_d[206]
  PIN tx_d[207]
    DIRECTION OUTPUT ;
    USE SIGNAL ;
    PORT
      LAYER M5 ;
        RECT  82.704 0 82.728 0.192 ;
    END
  END tx_d[207]
  PIN tx_d[208]
    DIRECTION OUTPUT ;
    USE SIGNAL ;
    PORT
      LAYER M5 ;
        RECT  82.8 0 82.824 0.192 ;
    END
  END tx_d[208]
  PIN tx_d[209]
    DIRECTION OUTPUT ;
    USE SIGNAL ;
    PORT
      LAYER M5 ;
        RECT  82.896 0 82.92 0.192 ;
    END
  END tx_d[209]
  PIN tx_d[20]
    DIRECTION OUTPUT ;
    USE SIGNAL ;
    PORT
      LAYER M5 ;
        RECT  62.688 0 62.712 0.192 ;
    END
  END tx_d[20]
  PIN tx_d[210]
    DIRECTION OUTPUT ;
    USE SIGNAL ;
    PORT
      LAYER M5 ;
        RECT  82.992 0 83.016 0.192 ;
    END
  END tx_d[210]
  PIN tx_d[211]
    DIRECTION OUTPUT ;
    USE SIGNAL ;
    PORT
      LAYER M5 ;
        RECT  83.088 0 83.112 0.192 ;
    END
  END tx_d[211]
  PIN tx_d[212]
    DIRECTION OUTPUT ;
    USE SIGNAL ;
    PORT
      LAYER M5 ;
        RECT  83.184 0 83.208 0.192 ;
    END
  END tx_d[212]
  PIN tx_d[213]
    DIRECTION OUTPUT ;
    USE SIGNAL ;
    PORT
      LAYER M5 ;
        RECT  84 0 84.024 0.192 ;
    END
  END tx_d[213]
  PIN tx_d[214]
    DIRECTION OUTPUT ;
    USE SIGNAL ;
    PORT
      LAYER M5 ;
        RECT  84.096 0 84.12 0.192 ;
    END
  END tx_d[214]
  PIN tx_d[215]
    DIRECTION OUTPUT ;
    USE SIGNAL ;
    PORT
      LAYER M5 ;
        RECT  84.192 0 84.216 0.192 ;
    END
  END tx_d[215]
  PIN tx_d[216]
    DIRECTION OUTPUT ;
    USE SIGNAL ;
    PORT
      LAYER M5 ;
        RECT  84.288 0 84.312 0.192 ;
    END
  END tx_d[216]
  PIN tx_d[217]
    DIRECTION OUTPUT ;
    USE SIGNAL ;
    PORT
      LAYER M5 ;
        RECT  84.384 0 84.408 0.192 ;
    END
  END tx_d[217]
  PIN tx_d[218]
    DIRECTION OUTPUT ;
    USE SIGNAL ;
    PORT
      LAYER M5 ;
        RECT  84.48 0 84.504 0.192 ;
    END
  END tx_d[218]
  PIN tx_d[219]
    DIRECTION OUTPUT ;
    USE SIGNAL ;
    PORT
      LAYER M5 ;
        RECT  84.576 0 84.6 0.192 ;
    END
  END tx_d[219]
  PIN tx_d[21]
    DIRECTION OUTPUT ;
    USE SIGNAL ;
    PORT
      LAYER M5 ;
        RECT  62.784 0 62.808 0.192 ;
    END
  END tx_d[21]
  PIN tx_d[220]
    DIRECTION OUTPUT ;
    USE SIGNAL ;
    PORT
      LAYER M5 ;
        RECT  84.672 0 84.696 0.192 ;
    END
  END tx_d[220]
  PIN tx_d[221]
    DIRECTION OUTPUT ;
    USE SIGNAL ;
    PORT
      LAYER M5 ;
        RECT  84.768 0 84.792 0.192 ;
    END
  END tx_d[221]
  PIN tx_d[222]
    DIRECTION OUTPUT ;
    USE SIGNAL ;
    PORT
      LAYER M5 ;
        RECT  84.864 0 84.888 0.192 ;
    END
  END tx_d[222]
  PIN tx_d[223]
    DIRECTION OUTPUT ;
    USE SIGNAL ;
    PORT
      LAYER M5 ;
        RECT  84.96 0 84.984 0.192 ;
    END
  END tx_d[223]
  PIN tx_d[224]
    DIRECTION OUTPUT ;
    USE SIGNAL ;
    PORT
      LAYER M5 ;
        RECT  85.056 0 85.08 0.192 ;
    END
  END tx_d[224]
  PIN tx_d[225]
    DIRECTION OUTPUT ;
    USE SIGNAL ;
    PORT
      LAYER M5 ;
        RECT  85.152 0 85.176 0.192 ;
    END
  END tx_d[225]
  PIN tx_d[226]
    DIRECTION OUTPUT ;
    USE SIGNAL ;
    PORT
      LAYER M5 ;
        RECT  85.248 0 85.272 0.192 ;
    END
  END tx_d[226]
  PIN tx_d[227]
    DIRECTION OUTPUT ;
    USE SIGNAL ;
    PORT
      LAYER M5 ;
        RECT  85.344 0 85.368 0.192 ;
    END
  END tx_d[227]
  PIN tx_d[228]
    DIRECTION OUTPUT ;
    USE SIGNAL ;
    PORT
      LAYER M5 ;
        RECT  85.44 0 85.464 0.192 ;
    END
  END tx_d[228]
  PIN tx_d[229]
    DIRECTION OUTPUT ;
    USE SIGNAL ;
    PORT
      LAYER M5 ;
        RECT  85.536 0 85.56 0.192 ;
    END
  END tx_d[229]
  PIN tx_d[22]
    DIRECTION OUTPUT ;
    USE SIGNAL ;
    PORT
      LAYER M5 ;
        RECT  62.88 0 62.904 0.192 ;
    END
  END tx_d[22]
  PIN tx_d[230]
    DIRECTION OUTPUT ;
    USE SIGNAL ;
    PORT
      LAYER M5 ;
        RECT  85.632 0 85.656 0.192 ;
    END
  END tx_d[230]
  PIN tx_d[231]
    DIRECTION OUTPUT ;
    USE SIGNAL ;
    PORT
      LAYER M5 ;
        RECT  85.728 0 85.752 0.192 ;
    END
  END tx_d[231]
  PIN tx_d[232]
    DIRECTION OUTPUT ;
    USE SIGNAL ;
    PORT
      LAYER M5 ;
        RECT  85.824 0 85.848 0.192 ;
    END
  END tx_d[232]
  PIN tx_d[233]
    DIRECTION OUTPUT ;
    USE SIGNAL ;
    PORT
      LAYER M5 ;
        RECT  85.92 0 85.944 0.192 ;
    END
  END tx_d[233]
  PIN tx_d[234]
    DIRECTION OUTPUT ;
    USE SIGNAL ;
    PORT
      LAYER M5 ;
        RECT  86.016 0 86.04 0.192 ;
    END
  END tx_d[234]
  PIN tx_d[235]
    DIRECTION OUTPUT ;
    USE SIGNAL ;
    PORT
      LAYER M5 ;
        RECT  86.112 0 86.136 0.192 ;
    END
  END tx_d[235]
  PIN tx_d[236]
    DIRECTION OUTPUT ;
    USE SIGNAL ;
    PORT
      LAYER M5 ;
        RECT  86.208 0 86.232 0.192 ;
    END
  END tx_d[236]
  PIN tx_d[237]
    DIRECTION OUTPUT ;
    USE SIGNAL ;
    PORT
      LAYER M5 ;
        RECT  86.304 0 86.328 0.192 ;
    END
  END tx_d[237]
  PIN tx_d[238]
    DIRECTION OUTPUT ;
    USE SIGNAL ;
    PORT
      LAYER M5 ;
        RECT  86.4 0 86.424 0.192 ;
    END
  END tx_d[238]
  PIN tx_d[239]
    DIRECTION OUTPUT ;
    USE SIGNAL ;
    PORT
      LAYER M5 ;
        RECT  86.496 0 86.52 0.192 ;
    END
  END tx_d[239]
  PIN tx_d[23]
    DIRECTION OUTPUT ;
    USE SIGNAL ;
    PORT
      LAYER M5 ;
        RECT  62.976 0 63 0.192 ;
    END
  END tx_d[23]
  PIN tx_d[240]
    DIRECTION OUTPUT ;
    USE SIGNAL ;
    PORT
      LAYER M5 ;
        RECT  86.592 0 86.616 0.192 ;
    END
  END tx_d[240]
  PIN tx_d[241]
    DIRECTION OUTPUT ;
    USE SIGNAL ;
    PORT
      LAYER M5 ;
        RECT  86.688 0 86.712 0.192 ;
    END
  END tx_d[241]
  PIN tx_d[242]
    DIRECTION OUTPUT ;
    USE SIGNAL ;
    PORT
      LAYER M5 ;
        RECT  86.784 0 86.808 0.192 ;
    END
  END tx_d[242]
  PIN tx_d[243]
    DIRECTION OUTPUT ;
    USE SIGNAL ;
    PORT
      LAYER M5 ;
        RECT  86.88 0 86.904 0.192 ;
    END
  END tx_d[243]
  PIN tx_d[244]
    DIRECTION OUTPUT ;
    USE SIGNAL ;
    PORT
      LAYER M5 ;
        RECT  86.976 0 87 0.192 ;
    END
  END tx_d[244]
  PIN tx_d[245]
    DIRECTION OUTPUT ;
    USE SIGNAL ;
    PORT
      LAYER M5 ;
        RECT  87.072 0 87.096 0.192 ;
    END
  END tx_d[245]
  PIN tx_d[246]
    DIRECTION OUTPUT ;
    USE SIGNAL ;
    PORT
      LAYER M5 ;
        RECT  87.168 0 87.192 0.192 ;
    END
  END tx_d[246]
  PIN tx_d[247]
    DIRECTION OUTPUT ;
    USE SIGNAL ;
    PORT
      LAYER M5 ;
        RECT  87.264 0 87.288 0.192 ;
    END
  END tx_d[247]
  PIN tx_d[248]
    DIRECTION OUTPUT ;
    USE SIGNAL ;
    PORT
      LAYER M5 ;
        RECT  87.36 0 87.384 0.192 ;
    END
  END tx_d[248]
  PIN tx_d[249]
    DIRECTION OUTPUT ;
    USE SIGNAL ;
    PORT
      LAYER M5 ;
        RECT  87.456 0 87.48 0.192 ;
    END
  END tx_d[249]
  PIN tx_d[24]
    DIRECTION OUTPUT ;
    USE SIGNAL ;
    PORT
      LAYER M5 ;
        RECT  63.072 0 63.096 0.192 ;
    END
  END tx_d[24]
  PIN tx_d[250]
    DIRECTION OUTPUT ;
    USE SIGNAL ;
    PORT
      LAYER M5 ;
        RECT  87.552 0 87.576 0.192 ;
    END
  END tx_d[250]
  PIN tx_d[251]
    DIRECTION OUTPUT ;
    USE SIGNAL ;
    PORT
      LAYER M5 ;
        RECT  87.648 0 87.672 0.192 ;
    END
  END tx_d[251]
  PIN tx_d[252]
    DIRECTION OUTPUT ;
    USE SIGNAL ;
    PORT
      LAYER M5 ;
        RECT  87.744 0 87.768 0.192 ;
    END
  END tx_d[252]
  PIN tx_d[253]
    DIRECTION OUTPUT ;
    USE SIGNAL ;
    PORT
      LAYER M5 ;
        RECT  87.84 0 87.864 0.192 ;
    END
  END tx_d[253]
  PIN tx_d[254]
    DIRECTION OUTPUT ;
    USE SIGNAL ;
    PORT
      LAYER M5 ;
        RECT  87.936 0 87.96 0.192 ;
    END
  END tx_d[254]
  PIN tx_d[255]
    DIRECTION OUTPUT ;
    USE SIGNAL ;
    PORT
      LAYER M5 ;
        RECT  88.032 0 88.056 0.192 ;
    END
  END tx_d[255]
  PIN tx_d[256]
    DIRECTION OUTPUT ;
    USE SIGNAL ;
    PORT
      LAYER M5 ;
        RECT  88.128 0 88.152 0.192 ;
    END
  END tx_d[256]
  PIN tx_d[257]
    DIRECTION OUTPUT ;
    USE SIGNAL ;
    PORT
      LAYER M5 ;
        RECT  88.224 0 88.248 0.192 ;
    END
  END tx_d[257]
  PIN tx_d[258]
    DIRECTION OUTPUT ;
    USE SIGNAL ;
    PORT
      LAYER M5 ;
        RECT  88.32 0 88.344 0.192 ;
    END
  END tx_d[258]
  PIN tx_d[259]
    DIRECTION OUTPUT ;
    USE SIGNAL ;
    PORT
      LAYER M5 ;
        RECT  88.416 0 88.44 0.192 ;
    END
  END tx_d[259]
  PIN tx_d[25]
    DIRECTION OUTPUT ;
    USE SIGNAL ;
    PORT
      LAYER M5 ;
        RECT  63.168 0 63.192 0.192 ;
    END
  END tx_d[25]
  PIN tx_d[260]
    DIRECTION OUTPUT ;
    USE SIGNAL ;
    PORT
      LAYER M5 ;
        RECT  88.512 0 88.536 0.192 ;
    END
  END tx_d[260]
  PIN tx_d[261]
    DIRECTION OUTPUT ;
    USE SIGNAL ;
    PORT
      LAYER M5 ;
        RECT  88.608 0 88.632 0.192 ;
    END
  END tx_d[261]
  PIN tx_d[262]
    DIRECTION OUTPUT ;
    USE SIGNAL ;
    PORT
      LAYER M5 ;
        RECT  89.376 0 89.4 0.192 ;
    END
  END tx_d[262]
  PIN tx_d[263]
    DIRECTION OUTPUT ;
    USE SIGNAL ;
    PORT
      LAYER M5 ;
        RECT  89.472 0 89.496 0.192 ;
    END
  END tx_d[263]
  PIN tx_d[264]
    DIRECTION OUTPUT ;
    USE SIGNAL ;
    PORT
      LAYER M5 ;
        RECT  89.568 0 89.592 0.192 ;
    END
  END tx_d[264]
  PIN tx_d[265]
    DIRECTION OUTPUT ;
    USE SIGNAL ;
    PORT
      LAYER M5 ;
        RECT  89.664 0 89.688 0.192 ;
    END
  END tx_d[265]
  PIN tx_d[266]
    DIRECTION OUTPUT ;
    USE SIGNAL ;
    PORT
      LAYER M5 ;
        RECT  89.76 0 89.784 0.192 ;
    END
  END tx_d[266]
  PIN tx_d[267]
    DIRECTION OUTPUT ;
    USE SIGNAL ;
    PORT
      LAYER M5 ;
        RECT  89.856 0 89.88 0.192 ;
    END
  END tx_d[267]
  PIN tx_d[268]
    DIRECTION OUTPUT ;
    USE SIGNAL ;
    PORT
      LAYER M5 ;
        RECT  89.952 0 89.976 0.192 ;
    END
  END tx_d[268]
  PIN tx_d[269]
    DIRECTION OUTPUT ;
    USE SIGNAL ;
    PORT
      LAYER M5 ;
        RECT  90.048 0 90.072 0.192 ;
    END
  END tx_d[269]
  PIN tx_d[26]
    DIRECTION OUTPUT ;
    USE SIGNAL ;
    PORT
      LAYER M5 ;
        RECT  63.264 0 63.288 0.192 ;
    END
  END tx_d[26]
  PIN tx_d[270]
    DIRECTION OUTPUT ;
    USE SIGNAL ;
    PORT
      LAYER M5 ;
        RECT  90.144 0 90.168 0.192 ;
    END
  END tx_d[270]
  PIN tx_d[271]
    DIRECTION OUTPUT ;
    USE SIGNAL ;
    PORT
      LAYER M5 ;
        RECT  90.24 0 90.264 0.192 ;
    END
  END tx_d[271]
  PIN tx_d[272]
    DIRECTION OUTPUT ;
    USE SIGNAL ;
    PORT
      LAYER M5 ;
        RECT  90.336 0 90.36 0.192 ;
    END
  END tx_d[272]
  PIN tx_d[273]
    DIRECTION OUTPUT ;
    USE SIGNAL ;
    PORT
      LAYER M5 ;
        RECT  90.432 0 90.456 0.192 ;
    END
  END tx_d[273]
  PIN tx_d[274]
    DIRECTION OUTPUT ;
    USE SIGNAL ;
    PORT
      LAYER M5 ;
        RECT  90.528 0 90.552 0.192 ;
    END
  END tx_d[274]
  PIN tx_d[275]
    DIRECTION OUTPUT ;
    USE SIGNAL ;
    PORT
      LAYER M5 ;
        RECT  90.624 0 90.648 0.192 ;
    END
  END tx_d[275]
  PIN tx_d[276]
    DIRECTION OUTPUT ;
    USE SIGNAL ;
    PORT
      LAYER M5 ;
        RECT  90.72 0 90.744 0.192 ;
    END
  END tx_d[276]
  PIN tx_d[277]
    DIRECTION OUTPUT ;
    USE SIGNAL ;
    PORT
      LAYER M5 ;
        RECT  90.816 0 90.84 0.192 ;
    END
  END tx_d[277]
  PIN tx_d[278]
    DIRECTION OUTPUT ;
    USE SIGNAL ;
    PORT
      LAYER M5 ;
        RECT  90.912 0 90.936 0.192 ;
    END
  END tx_d[278]
  PIN tx_d[279]
    DIRECTION OUTPUT ;
    USE SIGNAL ;
    PORT
      LAYER M5 ;
        RECT  91.008 0 91.032 0.192 ;
    END
  END tx_d[279]
  PIN tx_d[27]
    DIRECTION OUTPUT ;
    USE SIGNAL ;
    PORT
      LAYER M5 ;
        RECT  63.36 0 63.384 0.192 ;
    END
  END tx_d[27]
  PIN tx_d[280]
    DIRECTION OUTPUT ;
    USE SIGNAL ;
    PORT
      LAYER M5 ;
        RECT  91.104 0 91.128 0.192 ;
    END
  END tx_d[280]
  PIN tx_d[281]
    DIRECTION OUTPUT ;
    USE SIGNAL ;
    PORT
      LAYER M5 ;
        RECT  91.2 0 91.224 0.192 ;
    END
  END tx_d[281]
  PIN tx_d[282]
    DIRECTION OUTPUT ;
    USE SIGNAL ;
    PORT
      LAYER M5 ;
        RECT  91.296 0 91.32 0.192 ;
    END
  END tx_d[282]
  PIN tx_d[283]
    DIRECTION OUTPUT ;
    USE SIGNAL ;
    PORT
      LAYER M5 ;
        RECT  91.392 0 91.416 0.192 ;
    END
  END tx_d[283]
  PIN tx_d[284]
    DIRECTION OUTPUT ;
    USE SIGNAL ;
    PORT
      LAYER M5 ;
        RECT  91.488 0 91.512 0.192 ;
    END
  END tx_d[284]
  PIN tx_d[285]
    DIRECTION OUTPUT ;
    USE SIGNAL ;
    PORT
      LAYER M5 ;
        RECT  91.584 0 91.608 0.192 ;
    END
  END tx_d[285]
  PIN tx_d[286]
    DIRECTION OUTPUT ;
    USE SIGNAL ;
    PORT
      LAYER M5 ;
        RECT  91.68 0 91.704 0.192 ;
    END
  END tx_d[286]
  PIN tx_d[287]
    DIRECTION OUTPUT ;
    USE SIGNAL ;
    PORT
      LAYER M5 ;
        RECT  91.776 0 91.8 0.192 ;
    END
  END tx_d[287]
  PIN tx_d[288]
    DIRECTION OUTPUT ;
    USE SIGNAL ;
    PORT
      LAYER M5 ;
        RECT  91.872 0 91.896 0.192 ;
    END
  END tx_d[288]
  PIN tx_d[289]
    DIRECTION OUTPUT ;
    USE SIGNAL ;
    PORT
      LAYER M5 ;
        RECT  91.968 0 91.992 0.192 ;
    END
  END tx_d[289]
  PIN tx_d[28]
    DIRECTION OUTPUT ;
    USE SIGNAL ;
    PORT
      LAYER M5 ;
        RECT  63.456 0 63.48 0.192 ;
    END
  END tx_d[28]
  PIN tx_d[290]
    DIRECTION OUTPUT ;
    USE SIGNAL ;
    PORT
      LAYER M5 ;
        RECT  92.064 0 92.088 0.192 ;
    END
  END tx_d[290]
  PIN tx_d[291]
    DIRECTION OUTPUT ;
    USE SIGNAL ;
    PORT
      LAYER M5 ;
        RECT  92.16 0 92.184 0.192 ;
    END
  END tx_d[291]
  PIN tx_d[292]
    DIRECTION OUTPUT ;
    USE SIGNAL ;
    PORT
      LAYER M5 ;
        RECT  92.256 0 92.28 0.192 ;
    END
  END tx_d[292]
  PIN tx_d[293]
    DIRECTION OUTPUT ;
    USE SIGNAL ;
    PORT
      LAYER M5 ;
        RECT  92.352 0 92.376 0.192 ;
    END
  END tx_d[293]
  PIN tx_d[294]
    DIRECTION OUTPUT ;
    USE SIGNAL ;
    PORT
      LAYER M5 ;
        RECT  92.448 0 92.472 0.192 ;
    END
  END tx_d[294]
  PIN tx_d[295]
    DIRECTION OUTPUT ;
    USE SIGNAL ;
    PORT
      LAYER M5 ;
        RECT  92.544 0 92.568 0.192 ;
    END
  END tx_d[295]
  PIN tx_d[296]
    DIRECTION OUTPUT ;
    USE SIGNAL ;
    PORT
      LAYER M5 ;
        RECT  92.64 0 92.664 0.192 ;
    END
  END tx_d[296]
  PIN tx_d[297]
    DIRECTION OUTPUT ;
    USE SIGNAL ;
    PORT
      LAYER M5 ;
        RECT  92.736 0 92.76 0.192 ;
    END
  END tx_d[297]
  PIN tx_d[298]
    DIRECTION OUTPUT ;
    USE SIGNAL ;
    PORT
      LAYER M5 ;
        RECT  92.832 0 92.856 0.192 ;
    END
  END tx_d[298]
  PIN tx_d[299]
    DIRECTION OUTPUT ;
    USE SIGNAL ;
    PORT
      LAYER M5 ;
        RECT  92.928 0 92.952 0.192 ;
    END
  END tx_d[299]
  PIN tx_d[29]
    DIRECTION OUTPUT ;
    USE SIGNAL ;
    PORT
      LAYER M5 ;
        RECT  63.552 0 63.576 0.192 ;
    END
  END tx_d[29]
  PIN tx_d[2]
    DIRECTION OUTPUT ;
    USE SIGNAL ;
    PORT
      LAYER M5 ;
        RECT  60.288 0 60.312 0.192 ;
    END
  END tx_d[2]
  PIN tx_d[300]
    DIRECTION OUTPUT ;
    USE SIGNAL ;
    PORT
      LAYER M5 ;
        RECT  93.024 0 93.048 0.192 ;
    END
  END tx_d[300]
  PIN tx_d[301]
    DIRECTION OUTPUT ;
    USE SIGNAL ;
    PORT
      LAYER M5 ;
        RECT  93.12 0 93.144 0.192 ;
    END
  END tx_d[301]
  PIN tx_d[302]
    DIRECTION OUTPUT ;
    USE SIGNAL ;
    PORT
      LAYER M5 ;
        RECT  93.216 0 93.24 0.192 ;
    END
  END tx_d[302]
  PIN tx_d[303]
    DIRECTION OUTPUT ;
    USE SIGNAL ;
    PORT
      LAYER M5 ;
        RECT  93.312 0 93.336 0.192 ;
    END
  END tx_d[303]
  PIN tx_d[304]
    DIRECTION OUTPUT ;
    USE SIGNAL ;
    PORT
      LAYER M5 ;
        RECT  93.408 0 93.432 0.192 ;
    END
  END tx_d[304]
  PIN tx_d[305]
    DIRECTION OUTPUT ;
    USE SIGNAL ;
    PORT
      LAYER M5 ;
        RECT  93.504 0 93.528 0.192 ;
    END
  END tx_d[305]
  PIN tx_d[306]
    DIRECTION OUTPUT ;
    USE SIGNAL ;
    PORT
      LAYER M5 ;
        RECT  93.6 0 93.624 0.192 ;
    END
  END tx_d[306]
  PIN tx_d[307]
    DIRECTION OUTPUT ;
    USE SIGNAL ;
    PORT
      LAYER M5 ;
        RECT  93.696 0 93.72 0.192 ;
    END
  END tx_d[307]
  PIN tx_d[308]
    DIRECTION OUTPUT ;
    USE SIGNAL ;
    PORT
      LAYER M5 ;
        RECT  93.792 0 93.816 0.192 ;
    END
  END tx_d[308]
  PIN tx_d[309]
    DIRECTION OUTPUT ;
    USE SIGNAL ;
    PORT
      LAYER M5 ;
        RECT  93.888 0 93.912 0.192 ;
    END
  END tx_d[309]
  PIN tx_d[30]
    DIRECTION OUTPUT ;
    USE SIGNAL ;
    PORT
      LAYER M5 ;
        RECT  63.648 0 63.672 0.192 ;
    END
  END tx_d[30]
  PIN tx_d[310]
    DIRECTION OUTPUT ;
    USE SIGNAL ;
    PORT
      LAYER M5 ;
        RECT  93.984 0 94.008 0.192 ;
    END
  END tx_d[310]
  PIN tx_d[311]
    DIRECTION OUTPUT ;
    USE SIGNAL ;
    PORT
      LAYER M5 ;
        RECT  94.8 0 94.824 0.192 ;
    END
  END tx_d[311]
  PIN tx_d[312]
    DIRECTION OUTPUT ;
    USE SIGNAL ;
    PORT
      LAYER M5 ;
        RECT  94.896 0 94.92 0.192 ;
    END
  END tx_d[312]
  PIN tx_d[313]
    DIRECTION OUTPUT ;
    USE SIGNAL ;
    PORT
      LAYER M5 ;
        RECT  94.992 0 95.016 0.192 ;
    END
  END tx_d[313]
  PIN tx_d[314]
    DIRECTION OUTPUT ;
    USE SIGNAL ;
    PORT
      LAYER M5 ;
        RECT  95.088 0 95.112 0.192 ;
    END
  END tx_d[314]
  PIN tx_d[315]
    DIRECTION OUTPUT ;
    USE SIGNAL ;
    PORT
      LAYER M5 ;
        RECT  95.184 0 95.208 0.192 ;
    END
  END tx_d[315]
  PIN tx_d[316]
    DIRECTION OUTPUT ;
    USE SIGNAL ;
    PORT
      LAYER M5 ;
        RECT  95.28 0 95.304 0.192 ;
    END
  END tx_d[316]
  PIN tx_d[317]
    DIRECTION OUTPUT ;
    USE SIGNAL ;
    PORT
      LAYER M5 ;
        RECT  95.376 0 95.4 0.192 ;
    END
  END tx_d[317]
  PIN tx_d[318]
    DIRECTION OUTPUT ;
    USE SIGNAL ;
    PORT
      LAYER M5 ;
        RECT  95.472 0 95.496 0.192 ;
    END
  END tx_d[318]
  PIN tx_d[319]
    DIRECTION OUTPUT ;
    USE SIGNAL ;
    PORT
      LAYER M5 ;
        RECT  95.568 0 95.592 0.192 ;
    END
  END tx_d[319]
  PIN tx_d[31]
    DIRECTION OUTPUT ;
    USE SIGNAL ;
    PORT
      LAYER M5 ;
        RECT  63.744 0 63.768 0.192 ;
    END
  END tx_d[31]
  PIN tx_d[320]
    DIRECTION OUTPUT ;
    USE SIGNAL ;
    PORT
      LAYER M5 ;
        RECT  95.664 0 95.688 0.192 ;
    END
  END tx_d[320]
  PIN tx_d[321]
    DIRECTION OUTPUT ;
    USE SIGNAL ;
    PORT
      LAYER M5 ;
        RECT  95.76 0 95.784 0.192 ;
    END
  END tx_d[321]
  PIN tx_d[322]
    DIRECTION OUTPUT ;
    USE SIGNAL ;
    PORT
      LAYER M5 ;
        RECT  95.856 0 95.88 0.192 ;
    END
  END tx_d[322]
  PIN tx_d[323]
    DIRECTION OUTPUT ;
    USE SIGNAL ;
    PORT
      LAYER M5 ;
        RECT  95.952 0 95.976 0.192 ;
    END
  END tx_d[323]
  PIN tx_d[324]
    DIRECTION OUTPUT ;
    USE SIGNAL ;
    PORT
      LAYER M5 ;
        RECT  96.048 0 96.072 0.192 ;
    END
  END tx_d[324]
  PIN tx_d[325]
    DIRECTION OUTPUT ;
    USE SIGNAL ;
    PORT
      LAYER M5 ;
        RECT  96.144 0 96.168 0.192 ;
    END
  END tx_d[325]
  PIN tx_d[326]
    DIRECTION OUTPUT ;
    USE SIGNAL ;
    PORT
      LAYER M5 ;
        RECT  96.24 0 96.264 0.192 ;
    END
  END tx_d[326]
  PIN tx_d[327]
    DIRECTION OUTPUT ;
    USE SIGNAL ;
    PORT
      LAYER M5 ;
        RECT  96.336 0 96.36 0.192 ;
    END
  END tx_d[327]
  PIN tx_d[328]
    DIRECTION OUTPUT ;
    USE SIGNAL ;
    PORT
      LAYER M5 ;
        RECT  96.432 0 96.456 0.192 ;
    END
  END tx_d[328]
  PIN tx_d[329]
    DIRECTION OUTPUT ;
    USE SIGNAL ;
    PORT
      LAYER M5 ;
        RECT  96.528 0 96.552 0.192 ;
    END
  END tx_d[329]
  PIN tx_d[32]
    DIRECTION OUTPUT ;
    USE SIGNAL ;
    PORT
      LAYER M5 ;
        RECT  63.84 0 63.864 0.192 ;
    END
  END tx_d[32]
  PIN tx_d[330]
    DIRECTION OUTPUT ;
    USE SIGNAL ;
    PORT
      LAYER M5 ;
        RECT  96.624 0 96.648 0.192 ;
    END
  END tx_d[330]
  PIN tx_d[331]
    DIRECTION OUTPUT ;
    USE SIGNAL ;
    PORT
      LAYER M5 ;
        RECT  96.72 0 96.744 0.192 ;
    END
  END tx_d[331]
  PIN tx_d[332]
    DIRECTION OUTPUT ;
    USE SIGNAL ;
    PORT
      LAYER M5 ;
        RECT  96.816 0 96.84 0.192 ;
    END
  END tx_d[332]
  PIN tx_d[333]
    DIRECTION OUTPUT ;
    USE SIGNAL ;
    PORT
      LAYER M5 ;
        RECT  96.912 0 96.936 0.192 ;
    END
  END tx_d[333]
  PIN tx_d[334]
    DIRECTION OUTPUT ;
    USE SIGNAL ;
    PORT
      LAYER M5 ;
        RECT  97.008 0 97.032 0.192 ;
    END
  END tx_d[334]
  PIN tx_d[335]
    DIRECTION OUTPUT ;
    USE SIGNAL ;
    PORT
      LAYER M5 ;
        RECT  97.104 0 97.128 0.192 ;
    END
  END tx_d[335]
  PIN tx_d[336]
    DIRECTION OUTPUT ;
    USE SIGNAL ;
    PORT
      LAYER M5 ;
        RECT  97.2 0 97.224 0.192 ;
    END
  END tx_d[336]
  PIN tx_d[337]
    DIRECTION OUTPUT ;
    USE SIGNAL ;
    PORT
      LAYER M5 ;
        RECT  97.296 0 97.32 0.192 ;
    END
  END tx_d[337]
  PIN tx_d[338]
    DIRECTION OUTPUT ;
    USE SIGNAL ;
    PORT
      LAYER M5 ;
        RECT  97.392 0 97.416 0.192 ;
    END
  END tx_d[338]
  PIN tx_d[339]
    DIRECTION OUTPUT ;
    USE SIGNAL ;
    PORT
      LAYER M5 ;
        RECT  97.488 0 97.512 0.192 ;
    END
  END tx_d[339]
  PIN tx_d[33]
    DIRECTION OUTPUT ;
    USE SIGNAL ;
    PORT
      LAYER M5 ;
        RECT  63.936 0 63.96 0.192 ;
    END
  END tx_d[33]
  PIN tx_d[340]
    DIRECTION OUTPUT ;
    USE SIGNAL ;
    PORT
      LAYER M5 ;
        RECT  97.584 0 97.608 0.192 ;
    END
  END tx_d[340]
  PIN tx_d[341]
    DIRECTION OUTPUT ;
    USE SIGNAL ;
    PORT
      LAYER M5 ;
        RECT  97.68 0 97.704 0.192 ;
    END
  END tx_d[341]
  PIN tx_d[342]
    DIRECTION OUTPUT ;
    USE SIGNAL ;
    PORT
      LAYER M5 ;
        RECT  97.776 0 97.8 0.192 ;
    END
  END tx_d[342]
  PIN tx_d[343]
    DIRECTION OUTPUT ;
    USE SIGNAL ;
    PORT
      LAYER M5 ;
        RECT  97.872 0 97.896 0.192 ;
    END
  END tx_d[343]
  PIN tx_d[344]
    DIRECTION OUTPUT ;
    USE SIGNAL ;
    PORT
      LAYER M5 ;
        RECT  97.968 0 97.992 0.192 ;
    END
  END tx_d[344]
  PIN tx_d[345]
    DIRECTION OUTPUT ;
    USE SIGNAL ;
    PORT
      LAYER M5 ;
        RECT  98.064 0 98.088 0.192 ;
    END
  END tx_d[345]
  PIN tx_d[346]
    DIRECTION OUTPUT ;
    USE SIGNAL ;
    PORT
      LAYER M5 ;
        RECT  98.16 0 98.184 0.192 ;
    END
  END tx_d[346]
  PIN tx_d[347]
    DIRECTION OUTPUT ;
    USE SIGNAL ;
    PORT
      LAYER M5 ;
        RECT  98.256 0 98.28 0.192 ;
    END
  END tx_d[347]
  PIN tx_d[348]
    DIRECTION OUTPUT ;
    USE SIGNAL ;
    PORT
      LAYER M5 ;
        RECT  98.352 0 98.376 0.192 ;
    END
  END tx_d[348]
  PIN tx_d[349]
    DIRECTION OUTPUT ;
    USE SIGNAL ;
    PORT
      LAYER M5 ;
        RECT  98.448 0 98.472 0.192 ;
    END
  END tx_d[349]
  PIN tx_d[34]
    DIRECTION OUTPUT ;
    USE SIGNAL ;
    PORT
      LAYER M5 ;
        RECT  64.032 0 64.056 0.192 ;
    END
  END tx_d[34]
  PIN tx_d[350]
    DIRECTION OUTPUT ;
    USE SIGNAL ;
    PORT
      LAYER M5 ;
        RECT  98.544 0 98.568 0.192 ;
    END
  END tx_d[350]
  PIN tx_d[351]
    DIRECTION OUTPUT ;
    USE SIGNAL ;
    PORT
      LAYER M5 ;
        RECT  98.64 0 98.664 0.192 ;
    END
  END tx_d[351]
  PIN tx_d[352]
    DIRECTION OUTPUT ;
    USE SIGNAL ;
    PORT
      LAYER M5 ;
        RECT  98.736 0 98.76 0.192 ;
    END
  END tx_d[352]
  PIN tx_d[353]
    DIRECTION OUTPUT ;
    USE SIGNAL ;
    PORT
      LAYER M5 ;
        RECT  98.832 0 98.856 0.192 ;
    END
  END tx_d[353]
  PIN tx_d[354]
    DIRECTION OUTPUT ;
    USE SIGNAL ;
    PORT
      LAYER M5 ;
        RECT  98.928 0 98.952 0.192 ;
    END
  END tx_d[354]
  PIN tx_d[355]
    DIRECTION OUTPUT ;
    USE SIGNAL ;
    PORT
      LAYER M5 ;
        RECT  99.024 0 99.048 0.192 ;
    END
  END tx_d[355]
  PIN tx_d[356]
    DIRECTION OUTPUT ;
    USE SIGNAL ;
    PORT
      LAYER M5 ;
        RECT  99.12 0 99.144 0.192 ;
    END
  END tx_d[356]
  PIN tx_d[357]
    DIRECTION OUTPUT ;
    USE SIGNAL ;
    PORT
      LAYER M5 ;
        RECT  99.216 0 99.24 0.192 ;
    END
  END tx_d[357]
  PIN tx_d[358]
    DIRECTION OUTPUT ;
    USE SIGNAL ;
    PORT
      LAYER M5 ;
        RECT  99.312 0 99.336 0.192 ;
    END
  END tx_d[358]
  PIN tx_d[359]
    DIRECTION OUTPUT ;
    USE SIGNAL ;
    PORT
      LAYER M5 ;
        RECT  99.408 0 99.432 0.192 ;
    END
  END tx_d[359]
  PIN tx_d[35]
    DIRECTION OUTPUT ;
    USE SIGNAL ;
    PORT
      LAYER M5 ;
        RECT  64.128 0 64.152 0.192 ;
    END
  END tx_d[35]
  PIN tx_d[360]
    DIRECTION OUTPUT ;
    USE SIGNAL ;
    PORT
      LAYER M5 ;
        RECT  100.176 0 100.2 0.192 ;
    END
  END tx_d[360]
  PIN tx_d[361]
    DIRECTION OUTPUT ;
    USE SIGNAL ;
    PORT
      LAYER M5 ;
        RECT  100.272 0 100.296 0.192 ;
    END
  END tx_d[361]
  PIN tx_d[362]
    DIRECTION OUTPUT ;
    USE SIGNAL ;
    PORT
      LAYER M5 ;
        RECT  100.368 0 100.392 0.192 ;
    END
  END tx_d[362]
  PIN tx_d[363]
    DIRECTION OUTPUT ;
    USE SIGNAL ;
    PORT
      LAYER M5 ;
        RECT  100.464 0 100.488 0.192 ;
    END
  END tx_d[363]
  PIN tx_d[364]
    DIRECTION OUTPUT ;
    USE SIGNAL ;
    PORT
      LAYER M5 ;
        RECT  100.56 0 100.584 0.192 ;
    END
  END tx_d[364]
  PIN tx_d[365]
    DIRECTION OUTPUT ;
    USE SIGNAL ;
    PORT
      LAYER M5 ;
        RECT  100.656 0 100.68 0.192 ;
    END
  END tx_d[365]
  PIN tx_d[366]
    DIRECTION OUTPUT ;
    USE SIGNAL ;
    PORT
      LAYER M5 ;
        RECT  100.752 0 100.776 0.192 ;
    END
  END tx_d[366]
  PIN tx_d[367]
    DIRECTION OUTPUT ;
    USE SIGNAL ;
    PORT
      LAYER M5 ;
        RECT  100.848 0 100.872 0.192 ;
    END
  END tx_d[367]
  PIN tx_d[368]
    DIRECTION OUTPUT ;
    USE SIGNAL ;
    PORT
      LAYER M5 ;
        RECT  100.944 0 100.968 0.192 ;
    END
  END tx_d[368]
  PIN tx_d[369]
    DIRECTION OUTPUT ;
    USE SIGNAL ;
    PORT
      LAYER M5 ;
        RECT  101.04 0 101.064 0.192 ;
    END
  END tx_d[369]
  PIN tx_d[36]
    DIRECTION OUTPUT ;
    USE SIGNAL ;
    PORT
      LAYER M5 ;
        RECT  64.224 0 64.248 0.192 ;
    END
  END tx_d[36]
  PIN tx_d[370]
    DIRECTION OUTPUT ;
    USE SIGNAL ;
    PORT
      LAYER M5 ;
        RECT  101.136 0 101.16 0.192 ;
    END
  END tx_d[370]
  PIN tx_d[371]
    DIRECTION OUTPUT ;
    USE SIGNAL ;
    PORT
      LAYER M5 ;
        RECT  101.232 0 101.256 0.192 ;
    END
  END tx_d[371]
  PIN tx_d[372]
    DIRECTION OUTPUT ;
    USE SIGNAL ;
    PORT
      LAYER M5 ;
        RECT  101.328 0 101.352 0.192 ;
    END
  END tx_d[372]
  PIN tx_d[373]
    DIRECTION OUTPUT ;
    USE SIGNAL ;
    PORT
      LAYER M5 ;
        RECT  101.424 0 101.448 0.192 ;
    END
  END tx_d[373]
  PIN tx_d[374]
    DIRECTION OUTPUT ;
    USE SIGNAL ;
    PORT
      LAYER M5 ;
        RECT  101.52 0 101.544 0.192 ;
    END
  END tx_d[374]
  PIN tx_d[375]
    DIRECTION OUTPUT ;
    USE SIGNAL ;
    PORT
      LAYER M5 ;
        RECT  101.616 0 101.64 0.192 ;
    END
  END tx_d[375]
  PIN tx_d[376]
    DIRECTION OUTPUT ;
    USE SIGNAL ;
    PORT
      LAYER M5 ;
        RECT  101.712 0 101.736 0.192 ;
    END
  END tx_d[376]
  PIN tx_d[377]
    DIRECTION OUTPUT ;
    USE SIGNAL ;
    PORT
      LAYER M5 ;
        RECT  101.808 0 101.832 0.192 ;
    END
  END tx_d[377]
  PIN tx_d[378]
    DIRECTION OUTPUT ;
    USE SIGNAL ;
    PORT
      LAYER M5 ;
        RECT  101.904 0 101.928 0.192 ;
    END
  END tx_d[378]
  PIN tx_d[379]
    DIRECTION OUTPUT ;
    USE SIGNAL ;
    PORT
      LAYER M5 ;
        RECT  102 0 102.024 0.192 ;
    END
  END tx_d[379]
  PIN tx_d[37]
    DIRECTION OUTPUT ;
    USE SIGNAL ;
    PORT
      LAYER M5 ;
        RECT  64.32 0 64.344 0.192 ;
    END
  END tx_d[37]
  PIN tx_d[380]
    DIRECTION OUTPUT ;
    USE SIGNAL ;
    PORT
      LAYER M5 ;
        RECT  102.096 0 102.12 0.192 ;
    END
  END tx_d[380]
  PIN tx_d[381]
    DIRECTION OUTPUT ;
    USE SIGNAL ;
    PORT
      LAYER M5 ;
        RECT  102.192 0 102.216 0.192 ;
    END
  END tx_d[381]
  PIN tx_d[382]
    DIRECTION OUTPUT ;
    USE SIGNAL ;
    PORT
      LAYER M5 ;
        RECT  102.288 0 102.312 0.192 ;
    END
  END tx_d[382]
  PIN tx_d[383]
    DIRECTION OUTPUT ;
    USE SIGNAL ;
    PORT
      LAYER M5 ;
        RECT  102.384 0 102.408 0.192 ;
    END
  END tx_d[383]
  PIN tx_d[384]
    DIRECTION OUTPUT ;
    USE SIGNAL ;
    PORT
      LAYER M5 ;
        RECT  102.48 0 102.504 0.192 ;
    END
  END tx_d[384]
  PIN tx_d[385]
    DIRECTION OUTPUT ;
    USE SIGNAL ;
    PORT
      LAYER M5 ;
        RECT  102.576 0 102.6 0.192 ;
    END
  END tx_d[385]
  PIN tx_d[386]
    DIRECTION OUTPUT ;
    USE SIGNAL ;
    PORT
      LAYER M5 ;
        RECT  102.672 0 102.696 0.192 ;
    END
  END tx_d[386]
  PIN tx_d[387]
    DIRECTION OUTPUT ;
    USE SIGNAL ;
    PORT
      LAYER M5 ;
        RECT  102.768 0 102.792 0.192 ;
    END
  END tx_d[387]
  PIN tx_d[388]
    DIRECTION OUTPUT ;
    USE SIGNAL ;
    PORT
      LAYER M5 ;
        RECT  102.864 0 102.888 0.192 ;
    END
  END tx_d[388]
  PIN tx_d[389]
    DIRECTION OUTPUT ;
    USE SIGNAL ;
    PORT
      LAYER M5 ;
        RECT  102.96 0 102.984 0.192 ;
    END
  END tx_d[389]
  PIN tx_d[38]
    DIRECTION OUTPUT ;
    USE SIGNAL ;
    PORT
      LAYER M5 ;
        RECT  64.416 0 64.44 0.192 ;
    END
  END tx_d[38]
  PIN tx_d[390]
    DIRECTION OUTPUT ;
    USE SIGNAL ;
    PORT
      LAYER M5 ;
        RECT  103.056 0 103.08 0.192 ;
    END
  END tx_d[390]
  PIN tx_d[391]
    DIRECTION OUTPUT ;
    USE SIGNAL ;
    PORT
      LAYER M5 ;
        RECT  103.152 0 103.176 0.192 ;
    END
  END tx_d[391]
  PIN tx_d[392]
    DIRECTION OUTPUT ;
    USE SIGNAL ;
    PORT
      LAYER M5 ;
        RECT  103.248 0 103.272 0.192 ;
    END
  END tx_d[392]
  PIN tx_d[393]
    DIRECTION OUTPUT ;
    USE SIGNAL ;
    PORT
      LAYER M5 ;
        RECT  103.344 0 103.368 0.192 ;
    END
  END tx_d[393]
  PIN tx_d[394]
    DIRECTION OUTPUT ;
    USE SIGNAL ;
    PORT
      LAYER M5 ;
        RECT  103.44 0 103.464 0.192 ;
    END
  END tx_d[394]
  PIN tx_d[395]
    DIRECTION OUTPUT ;
    USE SIGNAL ;
    PORT
      LAYER M5 ;
        RECT  103.536 0 103.56 0.192 ;
    END
  END tx_d[395]
  PIN tx_d[396]
    DIRECTION OUTPUT ;
    USE SIGNAL ;
    PORT
      LAYER M5 ;
        RECT  103.632 0 103.656 0.192 ;
    END
  END tx_d[396]
  PIN tx_d[397]
    DIRECTION OUTPUT ;
    USE SIGNAL ;
    PORT
      LAYER M5 ;
        RECT  103.728 0 103.752 0.192 ;
    END
  END tx_d[397]
  PIN tx_d[398]
    DIRECTION OUTPUT ;
    USE SIGNAL ;
    PORT
      LAYER M5 ;
        RECT  103.824 0 103.848 0.192 ;
    END
  END tx_d[398]
  PIN tx_d[399]
    DIRECTION OUTPUT ;
    USE SIGNAL ;
    PORT
      LAYER M5 ;
        RECT  103.92 0 103.944 0.192 ;
    END
  END tx_d[399]
  PIN tx_d[39]
    DIRECTION OUTPUT ;
    USE SIGNAL ;
    PORT
      LAYER M5 ;
        RECT  64.512 0 64.536 0.192 ;
    END
  END tx_d[39]
  PIN tx_d[3]
    DIRECTION OUTPUT ;
    USE SIGNAL ;
    PORT
      LAYER M5 ;
        RECT  60.384 0 60.408 0.192 ;
    END
  END tx_d[3]
  PIN tx_d[400]
    DIRECTION OUTPUT ;
    USE SIGNAL ;
    PORT
      LAYER M5 ;
        RECT  104.016 0 104.04 0.192 ;
    END
  END tx_d[400]
  PIN tx_d[401]
    DIRECTION OUTPUT ;
    USE SIGNAL ;
    PORT
      LAYER M5 ;
        RECT  104.112 0 104.136 0.192 ;
    END
  END tx_d[401]
  PIN tx_d[402]
    DIRECTION OUTPUT ;
    USE SIGNAL ;
    PORT
      LAYER M5 ;
        RECT  104.208 0 104.232 0.192 ;
    END
  END tx_d[402]
  PIN tx_d[403]
    DIRECTION OUTPUT ;
    USE SIGNAL ;
    PORT
      LAYER M5 ;
        RECT  104.304 0 104.328 0.192 ;
    END
  END tx_d[403]
  PIN tx_d[404]
    DIRECTION OUTPUT ;
    USE SIGNAL ;
    PORT
      LAYER M5 ;
        RECT  104.4 0 104.424 0.192 ;
    END
  END tx_d[404]
  PIN tx_d[405]
    DIRECTION OUTPUT ;
    USE SIGNAL ;
    PORT
      LAYER M5 ;
        RECT  104.496 0 104.52 0.192 ;
    END
  END tx_d[405]
  PIN tx_d[406]
    DIRECTION OUTPUT ;
    USE SIGNAL ;
    PORT
      LAYER M5 ;
        RECT  104.592 0 104.616 0.192 ;
    END
  END tx_d[406]
  PIN tx_d[407]
    DIRECTION OUTPUT ;
    USE SIGNAL ;
    PORT
      LAYER M5 ;
        RECT  104.688 0 104.712 0.192 ;
    END
  END tx_d[407]
  PIN tx_d[408]
    DIRECTION OUTPUT ;
    USE SIGNAL ;
    PORT
      LAYER M5 ;
        RECT  104.784 0 104.808 0.192 ;
    END
  END tx_d[408]
  PIN tx_d[409]
    DIRECTION OUTPUT ;
    USE SIGNAL ;
    PORT
      LAYER M5 ;
        RECT  105.6 0 105.624 0.192 ;
    END
  END tx_d[409]
  PIN tx_d[40]
    DIRECTION OUTPUT ;
    USE SIGNAL ;
    PORT
      LAYER M5 ;
        RECT  64.608 0 64.632 0.192 ;
    END
  END tx_d[40]
  PIN tx_d[410]
    DIRECTION OUTPUT ;
    USE SIGNAL ;
    PORT
      LAYER M5 ;
        RECT  105.696 0 105.72 0.192 ;
    END
  END tx_d[410]
  PIN tx_d[411]
    DIRECTION OUTPUT ;
    USE SIGNAL ;
    PORT
      LAYER M5 ;
        RECT  105.792 0 105.816 0.192 ;
    END
  END tx_d[411]
  PIN tx_d[412]
    DIRECTION OUTPUT ;
    USE SIGNAL ;
    PORT
      LAYER M5 ;
        RECT  105.888 0 105.912 0.192 ;
    END
  END tx_d[412]
  PIN tx_d[413]
    DIRECTION OUTPUT ;
    USE SIGNAL ;
    PORT
      LAYER M5 ;
        RECT  105.984 0 106.008 0.192 ;
    END
  END tx_d[413]
  PIN tx_d[414]
    DIRECTION OUTPUT ;
    USE SIGNAL ;
    PORT
      LAYER M5 ;
        RECT  106.08 0 106.104 0.192 ;
    END
  END tx_d[414]
  PIN tx_d[415]
    DIRECTION OUTPUT ;
    USE SIGNAL ;
    PORT
      LAYER M5 ;
        RECT  106.176 0 106.2 0.192 ;
    END
  END tx_d[415]
  PIN tx_d[416]
    DIRECTION OUTPUT ;
    USE SIGNAL ;
    PORT
      LAYER M5 ;
        RECT  106.272 0 106.296 0.192 ;
    END
  END tx_d[416]
  PIN tx_d[417]
    DIRECTION OUTPUT ;
    USE SIGNAL ;
    PORT
      LAYER M5 ;
        RECT  106.368 0 106.392 0.192 ;
    END
  END tx_d[417]
  PIN tx_d[418]
    DIRECTION OUTPUT ;
    USE SIGNAL ;
    PORT
      LAYER M5 ;
        RECT  106.464 0 106.488 0.192 ;
    END
  END tx_d[418]
  PIN tx_d[419]
    DIRECTION OUTPUT ;
    USE SIGNAL ;
    PORT
      LAYER M5 ;
        RECT  106.56 0 106.584 0.192 ;
    END
  END tx_d[419]
  PIN tx_d[41]
    DIRECTION OUTPUT ;
    USE SIGNAL ;
    PORT
      LAYER M5 ;
        RECT  64.704 0 64.728 0.192 ;
    END
  END tx_d[41]
  PIN tx_d[420]
    DIRECTION OUTPUT ;
    USE SIGNAL ;
    PORT
      LAYER M5 ;
        RECT  106.656 0 106.68 0.192 ;
    END
  END tx_d[420]
  PIN tx_d[421]
    DIRECTION OUTPUT ;
    USE SIGNAL ;
    PORT
      LAYER M5 ;
        RECT  106.752 0 106.776 0.192 ;
    END
  END tx_d[421]
  PIN tx_d[422]
    DIRECTION OUTPUT ;
    USE SIGNAL ;
    PORT
      LAYER M5 ;
        RECT  106.848 0 106.872 0.192 ;
    END
  END tx_d[422]
  PIN tx_d[423]
    DIRECTION OUTPUT ;
    USE SIGNAL ;
    PORT
      LAYER M5 ;
        RECT  106.944 0 106.968 0.192 ;
    END
  END tx_d[423]
  PIN tx_d[424]
    DIRECTION OUTPUT ;
    USE SIGNAL ;
    PORT
      LAYER M5 ;
        RECT  107.04 0 107.064 0.192 ;
    END
  END tx_d[424]
  PIN tx_d[425]
    DIRECTION OUTPUT ;
    USE SIGNAL ;
    PORT
      LAYER M5 ;
        RECT  107.136 0 107.16 0.192 ;
    END
  END tx_d[425]
  PIN tx_d[426]
    DIRECTION OUTPUT ;
    USE SIGNAL ;
    PORT
      LAYER M5 ;
        RECT  107.232 0 107.256 0.192 ;
    END
  END tx_d[426]
  PIN tx_d[427]
    DIRECTION OUTPUT ;
    USE SIGNAL ;
    PORT
      LAYER M5 ;
        RECT  107.328 0 107.352 0.192 ;
    END
  END tx_d[427]
  PIN tx_d[428]
    DIRECTION OUTPUT ;
    USE SIGNAL ;
    PORT
      LAYER M5 ;
        RECT  107.424 0 107.448 0.192 ;
    END
  END tx_d[428]
  PIN tx_d[429]
    DIRECTION OUTPUT ;
    USE SIGNAL ;
    PORT
      LAYER M5 ;
        RECT  107.52 0 107.544 0.192 ;
    END
  END tx_d[429]
  PIN tx_d[42]
    DIRECTION OUTPUT ;
    USE SIGNAL ;
    PORT
      LAYER M5 ;
        RECT  64.8 0 64.824 0.192 ;
    END
  END tx_d[42]
  PIN tx_d[430]
    DIRECTION OUTPUT ;
    USE SIGNAL ;
    PORT
      LAYER M5 ;
        RECT  107.616 0 107.64 0.192 ;
    END
  END tx_d[430]
  PIN tx_d[431]
    DIRECTION OUTPUT ;
    USE SIGNAL ;
    PORT
      LAYER M5 ;
        RECT  107.712 0 107.736 0.192 ;
    END
  END tx_d[431]
  PIN tx_d[432]
    DIRECTION OUTPUT ;
    USE SIGNAL ;
    PORT
      LAYER M5 ;
        RECT  107.808 0 107.832 0.192 ;
    END
  END tx_d[432]
  PIN tx_d[433]
    DIRECTION OUTPUT ;
    USE SIGNAL ;
    PORT
      LAYER M5 ;
        RECT  107.904 0 107.928 0.192 ;
    END
  END tx_d[433]
  PIN tx_d[434]
    DIRECTION OUTPUT ;
    USE SIGNAL ;
    PORT
      LAYER M5 ;
        RECT  108 0 108.024 0.192 ;
    END
  END tx_d[434]
  PIN tx_d[435]
    DIRECTION OUTPUT ;
    USE SIGNAL ;
    PORT
      LAYER M5 ;
        RECT  108.096 0 108.12 0.192 ;
    END
  END tx_d[435]
  PIN tx_d[436]
    DIRECTION OUTPUT ;
    USE SIGNAL ;
    PORT
      LAYER M5 ;
        RECT  108.192 0 108.216 0.192 ;
    END
  END tx_d[436]
  PIN tx_d[437]
    DIRECTION OUTPUT ;
    USE SIGNAL ;
    PORT
      LAYER M5 ;
        RECT  108.288 0 108.312 0.192 ;
    END
  END tx_d[437]
  PIN tx_d[438]
    DIRECTION OUTPUT ;
    USE SIGNAL ;
    PORT
      LAYER M5 ;
        RECT  108.384 0 108.408 0.192 ;
    END
  END tx_d[438]
  PIN tx_d[439]
    DIRECTION OUTPUT ;
    USE SIGNAL ;
    PORT
      LAYER M5 ;
        RECT  108.48 0 108.504 0.192 ;
    END
  END tx_d[439]
  PIN tx_d[43]
    DIRECTION OUTPUT ;
    USE SIGNAL ;
    PORT
      LAYER M5 ;
        RECT  64.896 0 64.92 0.192 ;
    END
  END tx_d[43]
  PIN tx_d[440]
    DIRECTION OUTPUT ;
    USE SIGNAL ;
    PORT
      LAYER M5 ;
        RECT  108.576 0 108.6 0.192 ;
    END
  END tx_d[440]
  PIN tx_d[441]
    DIRECTION OUTPUT ;
    USE SIGNAL ;
    PORT
      LAYER M5 ;
        RECT  108.672 0 108.696 0.192 ;
    END
  END tx_d[441]
  PIN tx_d[442]
    DIRECTION OUTPUT ;
    USE SIGNAL ;
    PORT
      LAYER M5 ;
        RECT  108.768 0 108.792 0.192 ;
    END
  END tx_d[442]
  PIN tx_d[443]
    DIRECTION OUTPUT ;
    USE SIGNAL ;
    PORT
      LAYER M5 ;
        RECT  108.864 0 108.888 0.192 ;
    END
  END tx_d[443]
  PIN tx_d[444]
    DIRECTION OUTPUT ;
    USE SIGNAL ;
    PORT
      LAYER M5 ;
        RECT  108.96 0 108.984 0.192 ;
    END
  END tx_d[444]
  PIN tx_d[445]
    DIRECTION OUTPUT ;
    USE SIGNAL ;
    PORT
      LAYER M5 ;
        RECT  109.056 0 109.08 0.192 ;
    END
  END tx_d[445]
  PIN tx_d[446]
    DIRECTION OUTPUT ;
    USE SIGNAL ;
    PORT
      LAYER M5 ;
        RECT  109.152 0 109.176 0.192 ;
    END
  END tx_d[446]
  PIN tx_d[447]
    DIRECTION OUTPUT ;
    USE SIGNAL ;
    PORT
      LAYER M5 ;
        RECT  109.248 0 109.272 0.192 ;
    END
  END tx_d[447]
  PIN tx_d[448]
    DIRECTION OUTPUT ;
    USE SIGNAL ;
    PORT
      LAYER M5 ;
        RECT  109.344 0 109.368 0.192 ;
    END
  END tx_d[448]
  PIN tx_d[449]
    DIRECTION OUTPUT ;
    USE SIGNAL ;
    PORT
      LAYER M5 ;
        RECT  109.44 0 109.464 0.192 ;
    END
  END tx_d[449]
  PIN tx_d[44]
    DIRECTION OUTPUT ;
    USE SIGNAL ;
    PORT
      LAYER M5 ;
        RECT  64.992 0 65.016 0.192 ;
    END
  END tx_d[44]
  PIN tx_d[450]
    DIRECTION OUTPUT ;
    USE SIGNAL ;
    PORT
      LAYER M5 ;
        RECT  109.536 0 109.56 0.192 ;
    END
  END tx_d[450]
  PIN tx_d[451]
    DIRECTION OUTPUT ;
    USE SIGNAL ;
    PORT
      LAYER M5 ;
        RECT  109.632 0 109.656 0.192 ;
    END
  END tx_d[451]
  PIN tx_d[452]
    DIRECTION OUTPUT ;
    USE SIGNAL ;
    PORT
      LAYER M5 ;
        RECT  109.728 0 109.752 0.192 ;
    END
  END tx_d[452]
  PIN tx_d[453]
    DIRECTION OUTPUT ;
    USE SIGNAL ;
    PORT
      LAYER M5 ;
        RECT  109.824 0 109.848 0.192 ;
    END
  END tx_d[453]
  PIN tx_d[454]
    DIRECTION OUTPUT ;
    USE SIGNAL ;
    PORT
      LAYER M5 ;
        RECT  109.92 0 109.944 0.192 ;
    END
  END tx_d[454]
  PIN tx_d[455]
    DIRECTION OUTPUT ;
    USE SIGNAL ;
    PORT
      LAYER M5 ;
        RECT  110.016 0 110.04 0.192 ;
    END
  END tx_d[455]
  PIN tx_d[456]
    DIRECTION OUTPUT ;
    USE SIGNAL ;
    PORT
      LAYER M5 ;
        RECT  110.112 0 110.136 0.192 ;
    END
  END tx_d[456]
  PIN tx_d[457]
    DIRECTION OUTPUT ;
    USE SIGNAL ;
    PORT
      LAYER M5 ;
        RECT  110.208 0 110.232 0.192 ;
    END
  END tx_d[457]
  PIN tx_d[458]
    DIRECTION OUTPUT ;
    USE SIGNAL ;
    PORT
      LAYER M5 ;
        RECT  110.976 0 111 0.192 ;
    END
  END tx_d[458]
  PIN tx_d[459]
    DIRECTION OUTPUT ;
    USE SIGNAL ;
    PORT
      LAYER M5 ;
        RECT  111.072 0 111.096 0.192 ;
    END
  END tx_d[459]
  PIN tx_d[45]
    DIRECTION OUTPUT ;
    USE SIGNAL ;
    PORT
      LAYER M5 ;
        RECT  65.088 0 65.112 0.192 ;
    END
  END tx_d[45]
  PIN tx_d[460]
    DIRECTION OUTPUT ;
    USE SIGNAL ;
    PORT
      LAYER M5 ;
        RECT  111.168 0 111.192 0.192 ;
    END
  END tx_d[460]
  PIN tx_d[461]
    DIRECTION OUTPUT ;
    USE SIGNAL ;
    PORT
      LAYER M5 ;
        RECT  111.264 0 111.288 0.192 ;
    END
  END tx_d[461]
  PIN tx_d[462]
    DIRECTION OUTPUT ;
    USE SIGNAL ;
    PORT
      LAYER M5 ;
        RECT  111.36 0 111.384 0.192 ;
    END
  END tx_d[462]
  PIN tx_d[463]
    DIRECTION OUTPUT ;
    USE SIGNAL ;
    PORT
      LAYER M5 ;
        RECT  111.456 0 111.48 0.192 ;
    END
  END tx_d[463]
  PIN tx_d[464]
    DIRECTION OUTPUT ;
    USE SIGNAL ;
    PORT
      LAYER M5 ;
        RECT  111.552 0 111.576 0.192 ;
    END
  END tx_d[464]
  PIN tx_d[465]
    DIRECTION OUTPUT ;
    USE SIGNAL ;
    PORT
      LAYER M5 ;
        RECT  111.648 0 111.672 0.192 ;
    END
  END tx_d[465]
  PIN tx_d[466]
    DIRECTION OUTPUT ;
    USE SIGNAL ;
    PORT
      LAYER M5 ;
        RECT  111.744 0 111.768 0.192 ;
    END
  END tx_d[466]
  PIN tx_d[467]
    DIRECTION OUTPUT ;
    USE SIGNAL ;
    PORT
      LAYER M5 ;
        RECT  111.84 0 111.864 0.192 ;
    END
  END tx_d[467]
  PIN tx_d[468]
    DIRECTION OUTPUT ;
    USE SIGNAL ;
    PORT
      LAYER M5 ;
        RECT  111.936 0 111.96 0.192 ;
    END
  END tx_d[468]
  PIN tx_d[469]
    DIRECTION OUTPUT ;
    USE SIGNAL ;
    PORT
      LAYER M5 ;
        RECT  112.032 0 112.056 0.192 ;
    END
  END tx_d[469]
  PIN tx_d[46]
    DIRECTION OUTPUT ;
    USE SIGNAL ;
    PORT
      LAYER M5 ;
        RECT  65.184 0 65.208 0.192 ;
    END
  END tx_d[46]
  PIN tx_d[470]
    DIRECTION OUTPUT ;
    USE SIGNAL ;
    PORT
      LAYER M5 ;
        RECT  112.128 0 112.152 0.192 ;
    END
  END tx_d[470]
  PIN tx_d[471]
    DIRECTION OUTPUT ;
    USE SIGNAL ;
    PORT
      LAYER M5 ;
        RECT  112.224 0 112.248 0.192 ;
    END
  END tx_d[471]
  PIN tx_d[472]
    DIRECTION OUTPUT ;
    USE SIGNAL ;
    PORT
      LAYER M5 ;
        RECT  112.32 0 112.344 0.192 ;
    END
  END tx_d[472]
  PIN tx_d[473]
    DIRECTION OUTPUT ;
    USE SIGNAL ;
    PORT
      LAYER M5 ;
        RECT  112.416 0 112.44 0.192 ;
    END
  END tx_d[473]
  PIN tx_d[474]
    DIRECTION OUTPUT ;
    USE SIGNAL ;
    PORT
      LAYER M5 ;
        RECT  112.512 0 112.536 0.192 ;
    END
  END tx_d[474]
  PIN tx_d[475]
    DIRECTION OUTPUT ;
    USE SIGNAL ;
    PORT
      LAYER M5 ;
        RECT  112.608 0 112.632 0.192 ;
    END
  END tx_d[475]
  PIN tx_d[476]
    DIRECTION OUTPUT ;
    USE SIGNAL ;
    PORT
      LAYER M5 ;
        RECT  112.704 0 112.728 0.192 ;
    END
  END tx_d[476]
  PIN tx_d[477]
    DIRECTION OUTPUT ;
    USE SIGNAL ;
    PORT
      LAYER M5 ;
        RECT  112.8 0 112.824 0.192 ;
    END
  END tx_d[477]
  PIN tx_d[478]
    DIRECTION OUTPUT ;
    USE SIGNAL ;
    PORT
      LAYER M5 ;
        RECT  112.896 0 112.92 0.192 ;
    END
  END tx_d[478]
  PIN tx_d[479]
    DIRECTION OUTPUT ;
    USE SIGNAL ;
    PORT
      LAYER M5 ;
        RECT  112.992 0 113.016 0.192 ;
    END
  END tx_d[479]
  PIN tx_d[47]
    DIRECTION OUTPUT ;
    USE SIGNAL ;
    PORT
      LAYER M5 ;
        RECT  65.28 0 65.304 0.192 ;
    END
  END tx_d[47]
  PIN tx_d[480]
    DIRECTION OUTPUT ;
    USE SIGNAL ;
    PORT
      LAYER M5 ;
        RECT  113.088 0 113.112 0.192 ;
    END
  END tx_d[480]
  PIN tx_d[481]
    DIRECTION OUTPUT ;
    USE SIGNAL ;
    PORT
      LAYER M5 ;
        RECT  113.184 0 113.208 0.192 ;
    END
  END tx_d[481]
  PIN tx_d[482]
    DIRECTION OUTPUT ;
    USE SIGNAL ;
    PORT
      LAYER M5 ;
        RECT  113.28 0 113.304 0.192 ;
    END
  END tx_d[482]
  PIN tx_d[483]
    DIRECTION OUTPUT ;
    USE SIGNAL ;
    PORT
      LAYER M5 ;
        RECT  113.376 0 113.4 0.192 ;
    END
  END tx_d[483]
  PIN tx_d[484]
    DIRECTION OUTPUT ;
    USE SIGNAL ;
    PORT
      LAYER M5 ;
        RECT  113.472 0 113.496 0.192 ;
    END
  END tx_d[484]
  PIN tx_d[485]
    DIRECTION OUTPUT ;
    USE SIGNAL ;
    PORT
      LAYER M5 ;
        RECT  113.568 0 113.592 0.192 ;
    END
  END tx_d[485]
  PIN tx_d[486]
    DIRECTION OUTPUT ;
    USE SIGNAL ;
    PORT
      LAYER M5 ;
        RECT  113.664 0 113.688 0.192 ;
    END
  END tx_d[486]
  PIN tx_d[487]
    DIRECTION OUTPUT ;
    USE SIGNAL ;
    PORT
      LAYER M5 ;
        RECT  113.76 0 113.784 0.192 ;
    END
  END tx_d[487]
  PIN tx_d[488]
    DIRECTION OUTPUT ;
    USE SIGNAL ;
    PORT
      LAYER M5 ;
        RECT  113.856 0 113.88 0.192 ;
    END
  END tx_d[488]
  PIN tx_d[489]
    DIRECTION OUTPUT ;
    USE SIGNAL ;
    PORT
      LAYER M5 ;
        RECT  113.952 0 113.976 0.192 ;
    END
  END tx_d[489]
  PIN tx_d[48]
    DIRECTION OUTPUT ;
    USE SIGNAL ;
    PORT
      LAYER M5 ;
        RECT  65.376 0 65.4 0.192 ;
    END
  END tx_d[48]
  PIN tx_d[490]
    DIRECTION OUTPUT ;
    USE SIGNAL ;
    PORT
      LAYER M5 ;
        RECT  114.048 0 114.072 0.192 ;
    END
  END tx_d[490]
  PIN tx_d[491]
    DIRECTION OUTPUT ;
    USE SIGNAL ;
    PORT
      LAYER M5 ;
        RECT  114.144 0 114.168 0.192 ;
    END
  END tx_d[491]
  PIN tx_d[492]
    DIRECTION OUTPUT ;
    USE SIGNAL ;
    PORT
      LAYER M5 ;
        RECT  114.24 0 114.264 0.192 ;
    END
  END tx_d[492]
  PIN tx_d[493]
    DIRECTION OUTPUT ;
    USE SIGNAL ;
    PORT
      LAYER M5 ;
        RECT  114.336 0 114.36 0.192 ;
    END
  END tx_d[493]
  PIN tx_d[494]
    DIRECTION OUTPUT ;
    USE SIGNAL ;
    PORT
      LAYER M5 ;
        RECT  114.432 0 114.456 0.192 ;
    END
  END tx_d[494]
  PIN tx_d[495]
    DIRECTION OUTPUT ;
    USE SIGNAL ;
    PORT
      LAYER M5 ;
        RECT  114.528 0 114.552 0.192 ;
    END
  END tx_d[495]
  PIN tx_d[496]
    DIRECTION OUTPUT ;
    USE SIGNAL ;
    PORT
      LAYER M5 ;
        RECT  114.624 0 114.648 0.192 ;
    END
  END tx_d[496]
  PIN tx_d[497]
    DIRECTION OUTPUT ;
    USE SIGNAL ;
    PORT
      LAYER M5 ;
        RECT  114.72 0 114.744 0.192 ;
    END
  END tx_d[497]
  PIN tx_d[498]
    DIRECTION OUTPUT ;
    USE SIGNAL ;
    PORT
      LAYER M5 ;
        RECT  114.816 0 114.84 0.192 ;
    END
  END tx_d[498]
  PIN tx_d[499]
    DIRECTION OUTPUT ;
    USE SIGNAL ;
    PORT
      LAYER M5 ;
        RECT  114.912 0 114.936 0.192 ;
    END
  END tx_d[499]
  PIN tx_d[49]
    DIRECTION OUTPUT ;
    USE SIGNAL ;
    PORT
      LAYER M5 ;
        RECT  65.472 0 65.496 0.192 ;
    END
  END tx_d[49]
  PIN tx_d[4]
    DIRECTION OUTPUT ;
    USE SIGNAL ;
    PORT
      LAYER M5 ;
        RECT  60.48 0 60.504 0.192 ;
    END
  END tx_d[4]
  PIN tx_d[500]
    DIRECTION OUTPUT ;
    USE SIGNAL ;
    PORT
      LAYER M5 ;
        RECT  115.008 0 115.032 0.192 ;
    END
  END tx_d[500]
  PIN tx_d[501]
    DIRECTION OUTPUT ;
    USE SIGNAL ;
    PORT
      LAYER M5 ;
        RECT  115.104 0 115.128 0.192 ;
    END
  END tx_d[501]
  PIN tx_d[502]
    DIRECTION OUTPUT ;
    USE SIGNAL ;
    PORT
      LAYER M5 ;
        RECT  115.2 0 115.224 0.192 ;
    END
  END tx_d[502]
  PIN tx_d[503]
    DIRECTION OUTPUT ;
    USE SIGNAL ;
    PORT
      LAYER M5 ;
        RECT  115.296 0 115.32 0.192 ;
    END
  END tx_d[503]
  PIN tx_d[504]
    DIRECTION OUTPUT ;
    USE SIGNAL ;
    PORT
      LAYER M5 ;
        RECT  115.392 0 115.416 0.192 ;
    END
  END tx_d[504]
  PIN tx_d[505]
    DIRECTION OUTPUT ;
    USE SIGNAL ;
    PORT
      LAYER M5 ;
        RECT  115.488 0 115.512 0.192 ;
    END
  END tx_d[505]
  PIN tx_d[506]
    DIRECTION OUTPUT ;
    USE SIGNAL ;
    PORT
      LAYER M5 ;
        RECT  115.584 0 115.608 0.192 ;
    END
  END tx_d[506]
  PIN tx_d[507]
    DIRECTION OUTPUT ;
    USE SIGNAL ;
    PORT
      LAYER M5 ;
        RECT  116.4 0 116.424 0.192 ;
    END
  END tx_d[507]
  PIN tx_d[508]
    DIRECTION OUTPUT ;
    USE SIGNAL ;
    PORT
      LAYER M5 ;
        RECT  116.496 0 116.52 0.192 ;
    END
  END tx_d[508]
  PIN tx_d[509]
    DIRECTION OUTPUT ;
    USE SIGNAL ;
    PORT
      LAYER M5 ;
        RECT  116.592 0 116.616 0.192 ;
    END
  END tx_d[509]
  PIN tx_d[50]
    DIRECTION OUTPUT ;
    USE SIGNAL ;
    PORT
      LAYER M5 ;
        RECT  65.568 0 65.592 0.192 ;
    END
  END tx_d[50]
  PIN tx_d[510]
    DIRECTION OUTPUT ;
    USE SIGNAL ;
    PORT
      LAYER M5 ;
        RECT  116.688 0 116.712 0.192 ;
    END
  END tx_d[510]
  PIN tx_d[511]
    DIRECTION OUTPUT ;
    USE SIGNAL ;
    PORT
      LAYER M5 ;
        RECT  116.784 0 116.808 0.192 ;
    END
  END tx_d[511]
  PIN tx_d[512]
    DIRECTION OUTPUT ;
    USE SIGNAL ;
    PORT
      LAYER M5 ;
        RECT  116.88 0 116.904 0.192 ;
    END
  END tx_d[512]
  PIN tx_d[513]
    DIRECTION OUTPUT ;
    USE SIGNAL ;
    PORT
      LAYER M5 ;
        RECT  116.976 0 117 0.192 ;
    END
  END tx_d[513]
  PIN tx_d[514]
    DIRECTION OUTPUT ;
    USE SIGNAL ;
    PORT
      LAYER M5 ;
        RECT  117.072 0 117.096 0.192 ;
    END
  END tx_d[514]
  PIN tx_d[515]
    DIRECTION OUTPUT ;
    USE SIGNAL ;
    PORT
      LAYER M5 ;
        RECT  117.168 0 117.192 0.192 ;
    END
  END tx_d[515]
  PIN tx_d[516]
    DIRECTION OUTPUT ;
    USE SIGNAL ;
    PORT
      LAYER M5 ;
        RECT  117.264 0 117.288 0.192 ;
    END
  END tx_d[516]
  PIN tx_d[517]
    DIRECTION OUTPUT ;
    USE SIGNAL ;
    PORT
      LAYER M5 ;
        RECT  117.36 0 117.384 0.192 ;
    END
  END tx_d[517]
  PIN tx_d[518]
    DIRECTION OUTPUT ;
    USE SIGNAL ;
    PORT
      LAYER M5 ;
        RECT  117.456 0 117.48 0.192 ;
    END
  END tx_d[518]
  PIN tx_d[519]
    DIRECTION OUTPUT ;
    USE SIGNAL ;
    PORT
      LAYER M5 ;
        RECT  117.552 0 117.576 0.192 ;
    END
  END tx_d[519]
  PIN tx_d[51]
    DIRECTION OUTPUT ;
    USE SIGNAL ;
    PORT
      LAYER M5 ;
        RECT  65.664 0 65.688 0.192 ;
    END
  END tx_d[51]
  PIN tx_d[520]
    DIRECTION OUTPUT ;
    USE SIGNAL ;
    PORT
      LAYER M5 ;
        RECT  117.648 0 117.672 0.192 ;
    END
  END tx_d[520]
  PIN tx_d[521]
    DIRECTION OUTPUT ;
    USE SIGNAL ;
    PORT
      LAYER M5 ;
        RECT  117.744 0 117.768 0.192 ;
    END
  END tx_d[521]
  PIN tx_d[522]
    DIRECTION OUTPUT ;
    USE SIGNAL ;
    PORT
      LAYER M5 ;
        RECT  117.84 0 117.864 0.192 ;
    END
  END tx_d[522]
  PIN tx_d[523]
    DIRECTION OUTPUT ;
    USE SIGNAL ;
    PORT
      LAYER M5 ;
        RECT  117.936 0 117.96 0.192 ;
    END
  END tx_d[523]
  PIN tx_d[524]
    DIRECTION OUTPUT ;
    USE SIGNAL ;
    PORT
      LAYER M5 ;
        RECT  118.032 0 118.056 0.192 ;
    END
  END tx_d[524]
  PIN tx_d[525]
    DIRECTION OUTPUT ;
    USE SIGNAL ;
    PORT
      LAYER M5 ;
        RECT  118.128 0 118.152 0.192 ;
    END
  END tx_d[525]
  PIN tx_d[526]
    DIRECTION OUTPUT ;
    USE SIGNAL ;
    PORT
      LAYER M5 ;
        RECT  118.224 0 118.248 0.192 ;
    END
  END tx_d[526]
  PIN tx_d[527]
    DIRECTION OUTPUT ;
    USE SIGNAL ;
    PORT
      LAYER M5 ;
        RECT  118.32 0 118.344 0.192 ;
    END
  END tx_d[527]
  PIN tx_d[528]
    DIRECTION OUTPUT ;
    USE SIGNAL ;
    PORT
      LAYER M5 ;
        RECT  118.416 0 118.44 0.192 ;
    END
  END tx_d[528]
  PIN tx_d[529]
    DIRECTION OUTPUT ;
    USE SIGNAL ;
    PORT
      LAYER M5 ;
        RECT  118.512 0 118.536 0.192 ;
    END
  END tx_d[529]
  PIN tx_d[52]
    DIRECTION OUTPUT ;
    USE SIGNAL ;
    PORT
      LAYER M5 ;
        RECT  65.76 0 65.784 0.192 ;
    END
  END tx_d[52]
  PIN tx_d[530]
    DIRECTION OUTPUT ;
    USE SIGNAL ;
    PORT
      LAYER M5 ;
        RECT  118.608 0 118.632 0.192 ;
    END
  END tx_d[530]
  PIN tx_d[531]
    DIRECTION OUTPUT ;
    USE SIGNAL ;
    PORT
      LAYER M5 ;
        RECT  118.704 0 118.728 0.192 ;
    END
  END tx_d[531]
  PIN tx_d[532]
    DIRECTION OUTPUT ;
    USE SIGNAL ;
    PORT
      LAYER M5 ;
        RECT  118.8 0 118.824 0.192 ;
    END
  END tx_d[532]
  PIN tx_d[533]
    DIRECTION OUTPUT ;
    USE SIGNAL ;
    PORT
      LAYER M5 ;
        RECT  118.896 0 118.92 0.192 ;
    END
  END tx_d[533]
  PIN tx_d[534]
    DIRECTION OUTPUT ;
    USE SIGNAL ;
    PORT
      LAYER M5 ;
        RECT  118.992 0 119.016 0.192 ;
    END
  END tx_d[534]
  PIN tx_d[535]
    DIRECTION OUTPUT ;
    USE SIGNAL ;
    PORT
      LAYER M5 ;
        RECT  119.088 0 119.112 0.192 ;
    END
  END tx_d[535]
  PIN tx_d[536]
    DIRECTION OUTPUT ;
    USE SIGNAL ;
    PORT
      LAYER M5 ;
        RECT  119.184 0 119.208 0.192 ;
    END
  END tx_d[536]
  PIN tx_d[537]
    DIRECTION OUTPUT ;
    USE SIGNAL ;
    PORT
      LAYER M5 ;
        RECT  119.28 0 119.304 0.192 ;
    END
  END tx_d[537]
  PIN tx_d[538]
    DIRECTION OUTPUT ;
    USE SIGNAL ;
    PORT
      LAYER M5 ;
        RECT  119.376 0 119.4 0.192 ;
    END
  END tx_d[538]
  PIN tx_d[539]
    DIRECTION OUTPUT ;
    USE SIGNAL ;
    PORT
      LAYER M5 ;
        RECT  119.472 0 119.496 0.192 ;
    END
  END tx_d[539]
  PIN tx_d[53]
    DIRECTION OUTPUT ;
    USE SIGNAL ;
    PORT
      LAYER M5 ;
        RECT  65.856 0 65.88 0.192 ;
    END
  END tx_d[53]
  PIN tx_d[540]
    DIRECTION OUTPUT ;
    USE SIGNAL ;
    PORT
      LAYER M5 ;
        RECT  119.568 0 119.592 0.192 ;
    END
  END tx_d[540]
  PIN tx_d[541]
    DIRECTION OUTPUT ;
    USE SIGNAL ;
    PORT
      LAYER M5 ;
        RECT  119.664 0 119.688 0.192 ;
    END
  END tx_d[541]
  PIN tx_d[542]
    DIRECTION OUTPUT ;
    USE SIGNAL ;
    PORT
      LAYER M5 ;
        RECT  119.76 0 119.784 0.192 ;
    END
  END tx_d[542]
  PIN tx_d[543]
    DIRECTION OUTPUT ;
    USE SIGNAL ;
    PORT
      LAYER M5 ;
        RECT  119.856 0 119.88 0.192 ;
    END
  END tx_d[543]
  PIN tx_d[544]
    DIRECTION OUTPUT ;
    USE SIGNAL ;
    PORT
      LAYER M5 ;
        RECT  119.952 0 119.976 0.192 ;
    END
  END tx_d[544]
  PIN tx_d[545]
    DIRECTION OUTPUT ;
    USE SIGNAL ;
    PORT
      LAYER M5 ;
        RECT  120.048 0 120.072 0.192 ;
    END
  END tx_d[545]
  PIN tx_d[546]
    DIRECTION OUTPUT ;
    USE SIGNAL ;
    PORT
      LAYER M5 ;
        RECT  120.144 0 120.168 0.192 ;
    END
  END tx_d[546]
  PIN tx_d[547]
    DIRECTION OUTPUT ;
    USE SIGNAL ;
    PORT
      LAYER M5 ;
        RECT  120.24 0 120.264 0.192 ;
    END
  END tx_d[547]
  PIN tx_d[548]
    DIRECTION OUTPUT ;
    USE SIGNAL ;
    PORT
      LAYER M5 ;
        RECT  120.336 0 120.36 0.192 ;
    END
  END tx_d[548]
  PIN tx_d[549]
    DIRECTION OUTPUT ;
    USE SIGNAL ;
    PORT
      LAYER M5 ;
        RECT  120.432 0 120.456 0.192 ;
    END
  END tx_d[549]
  PIN tx_d[54]
    DIRECTION OUTPUT ;
    USE SIGNAL ;
    PORT
      LAYER M5 ;
        RECT  65.952 0 65.976 0.192 ;
    END
  END tx_d[54]
  PIN tx_d[550]
    DIRECTION OUTPUT ;
    USE SIGNAL ;
    PORT
      LAYER M5 ;
        RECT  120.528 0 120.552 0.192 ;
    END
  END tx_d[550]
  PIN tx_d[551]
    DIRECTION OUTPUT ;
    USE SIGNAL ;
    PORT
      LAYER M5 ;
        RECT  120.624 0 120.648 0.192 ;
    END
  END tx_d[551]
  PIN tx_d[552]
    DIRECTION OUTPUT ;
    USE SIGNAL ;
    PORT
      LAYER M5 ;
        RECT  120.72 0 120.744 0.192 ;
    END
  END tx_d[552]
  PIN tx_d[553]
    DIRECTION OUTPUT ;
    USE SIGNAL ;
    PORT
      LAYER M5 ;
        RECT  120.816 0 120.84 0.192 ;
    END
  END tx_d[553]
  PIN tx_d[554]
    DIRECTION OUTPUT ;
    USE SIGNAL ;
    PORT
      LAYER M5 ;
        RECT  120.912 0 120.936 0.192 ;
    END
  END tx_d[554]
  PIN tx_d[555]
    DIRECTION OUTPUT ;
    USE SIGNAL ;
    PORT
      LAYER M5 ;
        RECT  121.008 0 121.032 0.192 ;
    END
  END tx_d[555]
  PIN tx_d[556]
    DIRECTION OUTPUT ;
    USE SIGNAL ;
    PORT
      LAYER M5 ;
        RECT  121.776 0 121.8 0.192 ;
    END
  END tx_d[556]
  PIN tx_d[557]
    DIRECTION OUTPUT ;
    USE SIGNAL ;
    PORT
      LAYER M5 ;
        RECT  121.872 0 121.896 0.192 ;
    END
  END tx_d[557]
  PIN tx_d[558]
    DIRECTION OUTPUT ;
    USE SIGNAL ;
    PORT
      LAYER M5 ;
        RECT  121.968 0 121.992 0.192 ;
    END
  END tx_d[558]
  PIN tx_d[559]
    DIRECTION OUTPUT ;
    USE SIGNAL ;
    PORT
      LAYER M5 ;
        RECT  122.064 0 122.088 0.192 ;
    END
  END tx_d[559]
  PIN tx_d[55]
    DIRECTION OUTPUT ;
    USE SIGNAL ;
    PORT
      LAYER M5 ;
        RECT  66.048 0 66.072 0.192 ;
    END
  END tx_d[55]
  PIN tx_d[560]
    DIRECTION OUTPUT ;
    USE SIGNAL ;
    PORT
      LAYER M5 ;
        RECT  122.16 0 122.184 0.192 ;
    END
  END tx_d[560]
  PIN tx_d[561]
    DIRECTION OUTPUT ;
    USE SIGNAL ;
    PORT
      LAYER M5 ;
        RECT  122.256 0 122.28 0.192 ;
    END
  END tx_d[561]
  PIN tx_d[562]
    DIRECTION OUTPUT ;
    USE SIGNAL ;
    PORT
      LAYER M5 ;
        RECT  122.352 0 122.376 0.192 ;
    END
  END tx_d[562]
  PIN tx_d[563]
    DIRECTION OUTPUT ;
    USE SIGNAL ;
    PORT
      LAYER M5 ;
        RECT  122.448 0 122.472 0.192 ;
    END
  END tx_d[563]
  PIN tx_d[564]
    DIRECTION OUTPUT ;
    USE SIGNAL ;
    PORT
      LAYER M5 ;
        RECT  122.544 0 122.568 0.192 ;
    END
  END tx_d[564]
  PIN tx_d[565]
    DIRECTION OUTPUT ;
    USE SIGNAL ;
    PORT
      LAYER M5 ;
        RECT  122.64 0 122.664 0.192 ;
    END
  END tx_d[565]
  PIN tx_d[566]
    DIRECTION OUTPUT ;
    USE SIGNAL ;
    PORT
      LAYER M5 ;
        RECT  122.736 0 122.76 0.192 ;
    END
  END tx_d[566]
  PIN tx_d[567]
    DIRECTION OUTPUT ;
    USE SIGNAL ;
    PORT
      LAYER M5 ;
        RECT  122.832 0 122.856 0.192 ;
    END
  END tx_d[567]
  PIN tx_d[568]
    DIRECTION OUTPUT ;
    USE SIGNAL ;
    PORT
      LAYER M5 ;
        RECT  122.928 0 122.952 0.192 ;
    END
  END tx_d[568]
  PIN tx_d[569]
    DIRECTION OUTPUT ;
    USE SIGNAL ;
    PORT
      LAYER M5 ;
        RECT  123.024 0 123.048 0.192 ;
    END
  END tx_d[569]
  PIN tx_d[56]
    DIRECTION OUTPUT ;
    USE SIGNAL ;
    PORT
      LAYER M5 ;
        RECT  66.144 0 66.168 0.192 ;
    END
  END tx_d[56]
  PIN tx_d[570]
    DIRECTION OUTPUT ;
    USE SIGNAL ;
    PORT
      LAYER M5 ;
        RECT  123.12 0 123.144 0.192 ;
    END
  END tx_d[570]
  PIN tx_d[571]
    DIRECTION OUTPUT ;
    USE SIGNAL ;
    PORT
      LAYER M5 ;
        RECT  123.216 0 123.24 0.192 ;
    END
  END tx_d[571]
  PIN tx_d[572]
    DIRECTION OUTPUT ;
    USE SIGNAL ;
    PORT
      LAYER M5 ;
        RECT  123.312 0 123.336 0.192 ;
    END
  END tx_d[572]
  PIN tx_d[573]
    DIRECTION OUTPUT ;
    USE SIGNAL ;
    PORT
      LAYER M5 ;
        RECT  123.408 0 123.432 0.192 ;
    END
  END tx_d[573]
  PIN tx_d[574]
    DIRECTION OUTPUT ;
    USE SIGNAL ;
    PORT
      LAYER M5 ;
        RECT  123.504 0 123.528 0.192 ;
    END
  END tx_d[574]
  PIN tx_d[575]
    DIRECTION OUTPUT ;
    USE SIGNAL ;
    PORT
      LAYER M5 ;
        RECT  123.6 0 123.624 0.192 ;
    END
  END tx_d[575]
  PIN tx_d[576]
    DIRECTION OUTPUT ;
    USE SIGNAL ;
    PORT
      LAYER M5 ;
        RECT  123.696 0 123.72 0.192 ;
    END
  END tx_d[576]
  PIN tx_d[577]
    DIRECTION OUTPUT ;
    USE SIGNAL ;
    PORT
      LAYER M5 ;
        RECT  123.792 0 123.816 0.192 ;
    END
  END tx_d[577]
  PIN tx_d[578]
    DIRECTION OUTPUT ;
    USE SIGNAL ;
    PORT
      LAYER M5 ;
        RECT  123.888 0 123.912 0.192 ;
    END
  END tx_d[578]
  PIN tx_d[579]
    DIRECTION OUTPUT ;
    USE SIGNAL ;
    PORT
      LAYER M5 ;
        RECT  123.984 0 124.008 0.192 ;
    END
  END tx_d[579]
  PIN tx_d[57]
    DIRECTION OUTPUT ;
    USE SIGNAL ;
    PORT
      LAYER M5 ;
        RECT  66.24 0 66.264 0.192 ;
    END
  END tx_d[57]
  PIN tx_d[580]
    DIRECTION OUTPUT ;
    USE SIGNAL ;
    PORT
      LAYER M5 ;
        RECT  124.08 0 124.104 0.192 ;
    END
  END tx_d[580]
  PIN tx_d[58]
    DIRECTION OUTPUT ;
    USE SIGNAL ;
    PORT
      LAYER M5 ;
        RECT  66.336 0 66.36 0.192 ;
    END
  END tx_d[58]
  PIN tx_d[59]
    DIRECTION OUTPUT ;
    USE SIGNAL ;
    PORT
      LAYER M5 ;
        RECT  66.432 0 66.456 0.192 ;
    END
  END tx_d[59]
  PIN tx_d[5]
    DIRECTION OUTPUT ;
    USE SIGNAL ;
    PORT
      LAYER M5 ;
        RECT  60.576 0 60.6 0.192 ;
    END
  END tx_d[5]
  PIN tx_d[60]
    DIRECTION OUTPUT ;
    USE SIGNAL ;
    PORT
      LAYER M5 ;
        RECT  66.528 0 66.552 0.192 ;
    END
  END tx_d[60]
  PIN tx_d[61]
    DIRECTION OUTPUT ;
    USE SIGNAL ;
    PORT
      LAYER M5 ;
        RECT  66.624 0 66.648 0.192 ;
    END
  END tx_d[61]
  PIN tx_d[62]
    DIRECTION OUTPUT ;
    USE SIGNAL ;
    PORT
      LAYER M5 ;
        RECT  66.72 0 66.744 0.192 ;
    END
  END tx_d[62]
  PIN tx_d[63]
    DIRECTION OUTPUT ;
    USE SIGNAL ;
    PORT
      LAYER M5 ;
        RECT  66.816 0 66.84 0.192 ;
    END
  END tx_d[63]
  PIN tx_d[64]
    DIRECTION OUTPUT ;
    USE SIGNAL ;
    PORT
      LAYER M5 ;
        RECT  66.912 0 66.936 0.192 ;
    END
  END tx_d[64]
  PIN tx_d[65]
    DIRECTION OUTPUT ;
    USE SIGNAL ;
    PORT
      LAYER M5 ;
        RECT  67.008 0 67.032 0.192 ;
    END
  END tx_d[65]
  PIN tx_d[66]
    DIRECTION OUTPUT ;
    USE SIGNAL ;
    PORT
      LAYER M5 ;
        RECT  67.776 0 67.8 0.192 ;
    END
  END tx_d[66]
  PIN tx_d[67]
    DIRECTION OUTPUT ;
    USE SIGNAL ;
    PORT
      LAYER M5 ;
        RECT  67.872 0 67.896 0.192 ;
    END
  END tx_d[67]
  PIN tx_d[68]
    DIRECTION OUTPUT ;
    USE SIGNAL ;
    PORT
      LAYER M5 ;
        RECT  67.968 0 67.992 0.192 ;
    END
  END tx_d[68]
  PIN tx_d[69]
    DIRECTION OUTPUT ;
    USE SIGNAL ;
    PORT
      LAYER M5 ;
        RECT  68.064 0 68.088 0.192 ;
    END
  END tx_d[69]
  PIN tx_d[6]
    DIRECTION OUTPUT ;
    USE SIGNAL ;
    PORT
      LAYER M5 ;
        RECT  60.672 0 60.696 0.192 ;
    END
  END tx_d[6]
  PIN tx_d[70]
    DIRECTION OUTPUT ;
    USE SIGNAL ;
    PORT
      LAYER M5 ;
        RECT  68.16 0 68.184 0.192 ;
    END
  END tx_d[70]
  PIN tx_d[71]
    DIRECTION OUTPUT ;
    USE SIGNAL ;
    PORT
      LAYER M5 ;
        RECT  68.256 0 68.28 0.192 ;
    END
  END tx_d[71]
  PIN tx_d[72]
    DIRECTION OUTPUT ;
    USE SIGNAL ;
    PORT
      LAYER M5 ;
        RECT  68.352 0 68.376 0.192 ;
    END
  END tx_d[72]
  PIN tx_d[73]
    DIRECTION OUTPUT ;
    USE SIGNAL ;
    PORT
      LAYER M5 ;
        RECT  68.448 0 68.472 0.192 ;
    END
  END tx_d[73]
  PIN tx_d[74]
    DIRECTION OUTPUT ;
    USE SIGNAL ;
    PORT
      LAYER M5 ;
        RECT  68.544 0 68.568 0.192 ;
    END
  END tx_d[74]
  PIN tx_d[75]
    DIRECTION OUTPUT ;
    USE SIGNAL ;
    PORT
      LAYER M5 ;
        RECT  68.64 0 68.664 0.192 ;
    END
  END tx_d[75]
  PIN tx_d[76]
    DIRECTION OUTPUT ;
    USE SIGNAL ;
    PORT
      LAYER M5 ;
        RECT  68.736 0 68.76 0.192 ;
    END
  END tx_d[76]
  PIN tx_d[77]
    DIRECTION OUTPUT ;
    USE SIGNAL ;
    PORT
      LAYER M5 ;
        RECT  68.832 0 68.856 0.192 ;
    END
  END tx_d[77]
  PIN tx_d[78]
    DIRECTION OUTPUT ;
    USE SIGNAL ;
    PORT
      LAYER M5 ;
        RECT  68.928 0 68.952 0.192 ;
    END
  END tx_d[78]
  PIN tx_d[79]
    DIRECTION OUTPUT ;
    USE SIGNAL ;
    PORT
      LAYER M5 ;
        RECT  69.024 0 69.048 0.192 ;
    END
  END tx_d[79]
  PIN tx_d[7]
    DIRECTION OUTPUT ;
    USE SIGNAL ;
    PORT
      LAYER M5 ;
        RECT  60.768 0 60.792 0.192 ;
    END
  END tx_d[7]
  PIN tx_d[80]
    DIRECTION OUTPUT ;
    USE SIGNAL ;
    PORT
      LAYER M5 ;
        RECT  69.12 0 69.144 0.192 ;
    END
  END tx_d[80]
  PIN tx_d[81]
    DIRECTION OUTPUT ;
    USE SIGNAL ;
    PORT
      LAYER M5 ;
        RECT  69.216 0 69.24 0.192 ;
    END
  END tx_d[81]
  PIN tx_d[82]
    DIRECTION OUTPUT ;
    USE SIGNAL ;
    PORT
      LAYER M5 ;
        RECT  69.312 0 69.336 0.192 ;
    END
  END tx_d[82]
  PIN tx_d[83]
    DIRECTION OUTPUT ;
    USE SIGNAL ;
    PORT
      LAYER M5 ;
        RECT  69.408 0 69.432 0.192 ;
    END
  END tx_d[83]
  PIN tx_d[84]
    DIRECTION OUTPUT ;
    USE SIGNAL ;
    PORT
      LAYER M5 ;
        RECT  69.504 0 69.528 0.192 ;
    END
  END tx_d[84]
  PIN tx_d[85]
    DIRECTION OUTPUT ;
    USE SIGNAL ;
    PORT
      LAYER M5 ;
        RECT  69.6 0 69.624 0.192 ;
    END
  END tx_d[85]
  PIN tx_d[86]
    DIRECTION OUTPUT ;
    USE SIGNAL ;
    PORT
      LAYER M5 ;
        RECT  69.696 0 69.72 0.192 ;
    END
  END tx_d[86]
  PIN tx_d[87]
    DIRECTION OUTPUT ;
    USE SIGNAL ;
    PORT
      LAYER M5 ;
        RECT  69.792 0 69.816 0.192 ;
    END
  END tx_d[87]
  PIN tx_d[88]
    DIRECTION OUTPUT ;
    USE SIGNAL ;
    PORT
      LAYER M5 ;
        RECT  69.888 0 69.912 0.192 ;
    END
  END tx_d[88]
  PIN tx_d[89]
    DIRECTION OUTPUT ;
    USE SIGNAL ;
    PORT
      LAYER M5 ;
        RECT  69.984 0 70.008 0.192 ;
    END
  END tx_d[89]
  PIN tx_d[8]
    DIRECTION OUTPUT ;
    USE SIGNAL ;
    PORT
      LAYER M5 ;
        RECT  60.864 0 60.888 0.192 ;
    END
  END tx_d[8]
  PIN tx_d[90]
    DIRECTION OUTPUT ;
    USE SIGNAL ;
    PORT
      LAYER M5 ;
        RECT  70.08 0 70.104 0.192 ;
    END
  END tx_d[90]
  PIN tx_d[91]
    DIRECTION OUTPUT ;
    USE SIGNAL ;
    PORT
      LAYER M5 ;
        RECT  70.176 0 70.2 0.192 ;
    END
  END tx_d[91]
  PIN tx_d[92]
    DIRECTION OUTPUT ;
    USE SIGNAL ;
    PORT
      LAYER M5 ;
        RECT  70.272 0 70.296 0.192 ;
    END
  END tx_d[92]
  PIN tx_d[93]
    DIRECTION OUTPUT ;
    USE SIGNAL ;
    PORT
      LAYER M5 ;
        RECT  70.368 0 70.392 0.192 ;
    END
  END tx_d[93]
  PIN tx_d[94]
    DIRECTION OUTPUT ;
    USE SIGNAL ;
    PORT
      LAYER M5 ;
        RECT  70.464 0 70.488 0.192 ;
    END
  END tx_d[94]
  PIN tx_d[95]
    DIRECTION OUTPUT ;
    USE SIGNAL ;
    PORT
      LAYER M5 ;
        RECT  70.56 0 70.584 0.192 ;
    END
  END tx_d[95]
  PIN tx_d[96]
    DIRECTION OUTPUT ;
    USE SIGNAL ;
    PORT
      LAYER M5 ;
        RECT  70.656 0 70.68 0.192 ;
    END
  END tx_d[96]
  PIN tx_d[97]
    DIRECTION OUTPUT ;
    USE SIGNAL ;
    PORT
      LAYER M5 ;
        RECT  70.752 0 70.776 0.192 ;
    END
  END tx_d[97]
  PIN tx_d[98]
    DIRECTION OUTPUT ;
    USE SIGNAL ;
    PORT
      LAYER M5 ;
        RECT  70.848 0 70.872 0.192 ;
    END
  END tx_d[98]
  PIN tx_d[99]
    DIRECTION OUTPUT ;
    USE SIGNAL ;
    PORT
      LAYER M5 ;
        RECT  70.944 0 70.968 0.192 ;
    END
  END tx_d[99]
  PIN tx_d[9]
    DIRECTION OUTPUT ;
    USE SIGNAL ;
    PORT
      LAYER M5 ;
        RECT  60.96 0 60.984 0.192 ;
    END
  END tx_d[9]
  PIN tx_v
    DIRECTION OUTPUT ;
    USE SIGNAL ;
    PORT
      LAYER M5 ;
        RECT  60 0 60.024 0.192 ;
    END
  END tx_v
  PIN VDD
    DIRECTION INOUT ;
    USE POWER ;
    PORT
      LAYER M5 ;
        RECT  234.792 2.151 234.912 23.769 ;
        RECT  229.392 2.151 229.512 23.769 ;
        RECT  223.992 2.151 224.112 23.769 ;
        RECT  218.592 2.151 218.712 23.769 ;
        RECT  213.192 2.151 213.312 23.769 ;
        RECT  207.792 2.151 207.912 23.769 ;
        RECT  202.392 2.151 202.512 23.769 ;
        RECT  196.992 2.151 197.112 23.769 ;
        RECT  191.592 2.151 191.712 23.769 ;
        RECT  186.192 2.151 186.312 23.769 ;
        RECT  180.792 2.151 180.912 23.769 ;
        RECT  175.392 2.151 175.512 23.769 ;
        RECT  169.992 2.151 170.112 23.769 ;
        RECT  164.592 2.151 164.712 23.769 ;
        RECT  159.192 2.151 159.312 23.769 ;
        RECT  153.792 2.151 153.912 23.769 ;
        RECT  148.392 2.151 148.512 23.769 ;
        RECT  142.992 2.151 143.112 23.769 ;
        RECT  137.592 2.151 137.712 23.769 ;
        RECT  132.192 2.151 132.312 23.769 ;
        RECT  126.792 2.151 126.912 23.769 ;
        RECT  121.392 2.151 121.512 23.769 ;
        RECT  115.992 2.151 116.112 23.769 ;
        RECT  110.592 2.151 110.712 23.769 ;
        RECT  105.192 2.151 105.312 23.769 ;
        RECT  99.792 2.151 99.912 23.769 ;
        RECT  94.392 2.151 94.512 23.769 ;
        RECT  88.992 2.151 89.112 23.769 ;
        RECT  83.592 2.151 83.712 23.769 ;
        RECT  78.192 2.151 78.312 23.769 ;
        RECT  72.792 2.151 72.912 23.769 ;
        RECT  67.392 2.151 67.512 23.769 ;
        RECT  61.992 2.151 62.112 23.769 ;
        RECT  56.592 2.151 56.712 23.769 ;
        RECT  51.192 2.151 51.312 23.769 ;
        RECT  45.792 2.151 45.912 23.769 ;
        RECT  40.392 2.151 40.512 23.769 ;
        RECT  34.992 2.151 35.112 23.769 ;
        RECT  29.592 2.151 29.712 23.769 ;
        RECT  24.192 2.151 24.312 23.769 ;
        RECT  18.792 2.151 18.912 23.769 ;
        RECT  13.392 2.151 13.512 23.769 ;
        RECT  7.992 2.151 8.112 23.769 ;
        RECT  2.592 2.151 2.712 23.769 ;
    END
  END VDD
  PIN VSS
    DIRECTION INOUT ;
    USE GROUND ;
    PORT
      LAYER M5 ;
        RECT  234.6 2.137 234.72 23.783 ;
        RECT  229.2 2.137 229.32 23.783 ;
        RECT  223.8 2.137 223.92 23.783 ;
        RECT  218.4 2.137 218.52 23.783 ;
        RECT  213 2.137 213.12 23.783 ;
        RECT  207.6 2.137 207.72 23.783 ;
        RECT  202.2 2.137 202.32 23.783 ;
        RECT  196.8 2.137 196.92 23.783 ;
        RECT  191.4 2.137 191.52 23.783 ;
        RECT  186 2.137 186.12 23.783 ;
        RECT  180.6 2.137 180.72 23.783 ;
        RECT  175.2 2.137 175.32 23.783 ;
        RECT  169.8 2.137 169.92 23.783 ;
        RECT  164.4 2.137 164.52 23.783 ;
        RECT  159 2.137 159.12 23.783 ;
        RECT  153.6 2.137 153.72 23.783 ;
        RECT  148.2 2.137 148.32 23.783 ;
        RECT  142.8 2.137 142.92 23.783 ;
        RECT  137.4 2.137 137.52 23.783 ;
        RECT  132 2.137 132.12 23.783 ;
        RECT  126.6 2.137 126.72 23.783 ;
        RECT  121.2 2.137 121.32 23.783 ;
        RECT  115.8 2.137 115.92 23.783 ;
        RECT  110.4 2.137 110.52 23.783 ;
        RECT  105 2.137 105.12 23.783 ;
        RECT  99.6 2.137 99.72 23.783 ;
        RECT  94.2 2.137 94.32 23.783 ;
        RECT  88.8 2.137 88.92 23.783 ;
        RECT  83.4 2.137 83.52 23.783 ;
        RECT  78 2.137 78.12 23.783 ;
        RECT  72.6 2.137 72.72 23.783 ;
        RECT  67.2 2.137 67.32 23.783 ;
        RECT  61.8 2.137 61.92 23.783 ;
        RECT  56.4 2.137 56.52 23.783 ;
        RECT  51 2.137 51.12 23.783 ;
        RECT  45.6 2.137 45.72 23.783 ;
        RECT  40.2 2.137 40.32 23.783 ;
        RECT  34.8 2.137 34.92 23.783 ;
        RECT  29.4 2.137 29.52 23.783 ;
        RECT  24 2.137 24.12 23.783 ;
        RECT  18.6 2.137 18.72 23.783 ;
        RECT  13.2 2.137 13.32 23.783 ;
        RECT  7.8 2.137 7.92 23.783 ;
        RECT  2.4 2.137 2.52 23.783 ;
    END
  END VSS
  # OT_OBS_CLOSED layer=M5 d_um=1.536 added=233
  OBS
    LAYER RVTN ;
     RECT  2.16 2.16 235.44 2.295 ;
     RECT  2.16 2.565 235.44 2.835 ;
     RECT  2.16 3.105 235.44 3.375 ;
     RECT  2.16 3.645 235.44 3.915 ;
     RECT  2.16 4.185 235.44 4.455 ;
     RECT  2.16 4.725 235.44 4.995 ;
     RECT  2.16 5.265 235.44 5.535 ;
     RECT  2.16 5.805 235.44 6.075 ;
     RECT  2.16 6.345 235.44 6.615 ;
     RECT  2.16 6.885 235.44 7.155 ;
     RECT  2.16 7.425 235.44 7.695 ;
     RECT  2.16 7.965 235.44 8.235 ;
     RECT  2.16 8.505 235.44 8.775 ;
     RECT  2.16 9.045 235.44 9.315 ;
     RECT  2.16 9.585 235.44 9.855 ;
     RECT  2.16 10.125 235.44 10.395 ;
     RECT  2.16 10.665 235.44 10.935 ;
     RECT  2.16 11.205 235.44 11.475 ;
     RECT  2.16 11.745 235.44 12.015 ;
     RECT  2.16 12.285 235.44 12.555 ;
     RECT  2.16 12.825 235.44 13.095 ;
     RECT  2.16 13.365 235.44 13.635 ;
     RECT  2.16 13.905 235.44 14.175 ;
     RECT  2.16 14.445 235.44 14.715 ;
     RECT  2.16 14.985 235.44 15.255 ;
     RECT  2.16 15.525 235.44 15.795 ;
     RECT  2.16 16.065 235.44 16.335 ;
     RECT  2.16 16.605 235.44 16.875 ;
     RECT  2.16 17.145 235.44 17.415 ;
     RECT  2.16 17.685 235.44 17.955 ;
     RECT  2.16 18.225 235.44 18.495 ;
     RECT  2.16 18.765 235.44 19.035 ;
     RECT  2.16 19.305 235.44 19.575 ;
     RECT  2.16 19.845 235.44 20.115 ;
     RECT  2.16 20.385 235.44 20.655 ;
     RECT  2.16 20.925 235.44 21.195 ;
     RECT  2.16 21.465 235.44 21.735 ;
     RECT  2.16 22.005 235.44 22.275 ;
     RECT  2.16 22.545 235.44 22.815 ;
     RECT  2.16 23.085 235.44 23.355 ;
     RECT  2.16 23.625 235.44 23.76 ;
    LAYER RVTP ;
     RECT  2.16 2.295 235.44 2.565 ;
     RECT  2.16 2.835 235.44 3.105 ;
     RECT  2.16 3.375 235.44 3.645 ;
     RECT  2.16 3.915 235.44 4.185 ;
     RECT  2.16 4.455 235.44 4.725 ;
     RECT  2.16 4.995 235.44 5.265 ;
     RECT  2.16 5.535 235.44 5.805 ;
     RECT  2.16 6.075 235.44 6.345 ;
     RECT  2.16 6.615 235.44 6.885 ;
     RECT  2.16 7.155 235.44 7.425 ;
     RECT  2.16 7.695 235.44 7.965 ;
     RECT  2.16 8.235 235.44 8.505 ;
     RECT  2.16 8.775 235.44 9.045 ;
     RECT  2.16 9.315 235.44 9.585 ;
     RECT  2.16 9.855 235.44 10.125 ;
     RECT  2.16 10.395 235.44 10.665 ;
     RECT  2.16 10.935 235.44 11.205 ;
     RECT  2.16 11.475 235.44 11.745 ;
     RECT  2.16 12.015 235.44 12.285 ;
     RECT  2.16 12.555 235.44 12.825 ;
     RECT  2.16 13.095 235.44 13.365 ;
     RECT  2.16 13.635 235.44 13.905 ;
     RECT  2.16 14.175 235.44 14.445 ;
     RECT  2.16 14.715 235.44 14.985 ;
     RECT  2.16 15.255 235.44 15.525 ;
     RECT  2.16 15.795 235.44 16.065 ;
     RECT  2.16 16.335 235.44 16.605 ;
     RECT  2.16 16.875 235.44 17.145 ;
     RECT  2.16 17.415 235.44 17.685 ;
     RECT  2.16 17.955 235.44 18.225 ;
     RECT  2.16 18.495 235.44 18.765 ;
     RECT  2.16 19.035 235.44 19.305 ;
     RECT  2.16 19.575 235.44 19.845 ;
     RECT  2.16 20.115 235.44 20.385 ;
     RECT  2.16 20.655 235.44 20.925 ;
     RECT  2.16 21.195 235.44 21.465 ;
     RECT  2.16 21.735 235.44 22.005 ;
     RECT  2.16 22.275 235.44 22.545 ;
     RECT  2.16 22.815 235.44 23.085 ;
     RECT  2.16 23.355 235.44 23.625 ;
    LAYER M1 ;
     RECT  2.16 2.151 235.44 23.769 ;
    LAYER M2 ;
     RECT  2.16 2.151 60.979 23.769 ;
     RECT  60.979 2.106 61.655 23.769 ;
     RECT  64.795 1.152 64.895 1.17 ;
     RECT  61.655 2.151 66.307 23.769 ;
     RECT  66.307 2.106 68.279 23.769 ;
     RECT  68.279 2.151 73.219 23.769 ;
     RECT  73.219 2.106 74.075 23.769 ;
     RECT  74.075 2.151 75.235 23.769 ;
     RECT  75.235 2.034 76.487 23.769 ;
     RECT  76.487 2.106 78.539 23.769 ;
     RECT  78.539 2.151 80.059 23.769 ;
     RECT  80.059 2.106 80.915 23.769 ;
     RECT  80.915 2.151 82.831 23.769 ;
     RECT  82.831 2.106 83.795 23.769 ;
     RECT  83.795 2.151 89.131 23.769 ;
     RECT  89.131 2.106 90.095 23.769 ;
     RECT  90.095 2.151 95.251 23.769 ;
     RECT  95.251 2.106 95.323 23.769 ;
     RECT  95.323 2.034 96.179 23.769 ;
     RECT  96.179 2.151 98.347 23.769 ;
     RECT  98.347 2.106 99.275 23.769 ;
     RECT  99.275 2.151 106.987 23.769 ;
     RECT  106.987 2.106 107.951 23.769 ;
     RECT  107.951 2.151 110.299 23.769 ;
     RECT  110.299 2.106 111.119 23.769 ;
     RECT  111.119 2.151 114.655 23.769 ;
     RECT  114.655 2.106 115.079 23.769 ;
     RECT  115.079 2.151 115.159 23.769 ;
     RECT  115.159 2.151 117.931 23.814 ;
     RECT  117.931 2.106 118.643 23.814 ;
     RECT  118.643 2.151 119.587 23.814 ;
     RECT  119.587 2.106 120.155 23.814 ;
     RECT  120.155 2.151 122.539 23.814 ;
     RECT  122.539 2.151 123.619 23.886 ;
     RECT  123.619 2.106 124.727 23.886 ;
     RECT  124.727 2.151 129.695 23.886 ;
     RECT  129.695 2.151 130.603 23.814 ;
     RECT  130.603 2.151 134.527 23.85 ;
     RECT  134.527 2.151 141.431 23.886 ;
     RECT  141.431 2.151 217.967 23.814 ;
     RECT  217.967 2.151 235.44 23.769 ;
    LAYER M3 ;
     RECT  74.016 0.187 76.662 0.235 ;
     RECT  82.872 0.187 82.89 0.235 ;
     RECT  87.192 0.187 87.642 0.235 ;
     RECT  90.756 0.187 93.366 0.235 ;
     RECT  94.968 0.187 94.986 0.235 ;
     RECT  100.368 0.187 101.646 0.235 ;
     RECT  105.732 0.187 106.29 0.235 ;
     RECT  107.028 0.187 107.046 0.235 ;
     RECT  108.684 0.187 108.702 0.235 ;
     RECT  115.272 0.187 115.29 0.235 ;
     RECT  116.532 0.187 116.55 0.235 ;
     RECT  86.976 0.235 87.642 0.283 ;
     RECT  105.732 0.235 107.046 0.283 ;
     RECT  122.4 0.187 123.03 0.283 ;
     RECT  108.684 0.235 109.242 0.331 ;
     RECT  65.196 0.187 65.214 0.523 ;
     RECT  71.928 0.187 72.414 0.523 ;
     RECT  73.908 0.235 76.662 0.523 ;
     RECT  77.508 0.187 77.526 0.523 ;
     RECT  79.056 0.187 79.29 0.523 ;
     RECT  85.86 0.187 85.878 0.523 ;
     RECT  116.532 0.235 116.658 0.523 ;
     RECT  62.964 0.187 63.558 0.571 ;
     RECT  64.872 0.523 65.214 0.571 ;
     RECT  66.672 0.187 68.706 0.571 ;
     RECT  73.908 0.523 77.526 0.571 ;
     RECT  78.66 0.523 79.29 0.571 ;
     RECT  80.136 0.187 80.154 0.571 ;
     RECT  81.036 0.187 81.342 0.571 ;
     RECT  82.872 0.235 83.214 0.571 ;
     RECT  88.704 0.187 88.722 0.571 ;
     RECT  94.968 0.235 95.13 0.571 ;
     RECT  95.976 0.187 96.822 0.571 ;
     RECT  99.18 0.523 99.198 0.571 ;
     RECT  100.368 0.235 101.862 0.571 ;
     RECT  108.684 0.331 109.278 0.571 ;
     RECT  110.052 0.235 110.286 0.571 ;
     RECT  116.388 0.523 116.658 0.571 ;
     RECT  118.872 0.475 118.89 0.571 ;
     RECT  119.772 0.187 119.79 0.571 ;
     RECT  120.636 0.187 120.654 0.571 ;
     RECT  122.364 0.283 123.03 0.571 ;
     RECT  123.876 0.187 123.894 0.571 ;
     RECT  112.716 0.571 113.058 0.619 ;
     RECT  70.38 0.187 70.398 1.099 ;
     RECT  71.46 0.523 72.414 1.099 ;
     RECT  73.908 0.571 77.742 1.099 ;
     RECT  78.66 0.571 80.298 1.099 ;
     RECT  81.036 0.571 81.954 1.099 ;
     RECT  116.388 0.571 116.946 1.099 ;
     RECT  60.732 0.187 60.75 1.147 ;
     RECT  62.748 0.571 63.558 1.147 ;
     RECT  64.872 0.571 68.706 1.147 ;
     RECT  73.62 1.099 77.742 1.147 ;
     RECT  82.872 0.571 83.934 1.147 ;
     RECT  85.14 0.523 85.878 1.147 ;
     RECT  94.968 0.571 96.822 1.147 ;
     RECT  97.884 0.571 99.198 1.147 ;
     RECT  103.932 0.187 104.562 1.147 ;
     RECT  60.48 1.147 61.254 1.195 ;
     RECT  62.748 1.147 68.706 1.675 ;
     RECT  100.368 0.571 101.97 1.675 ;
     RECT  118.872 0.571 118.926 1.675 ;
     RECT  122.364 0.571 123.894 1.675 ;
     RECT  60.372 1.195 61.254 1.723 ;
     RECT  62.424 1.675 68.706 1.723 ;
     RECT  70.38 1.099 72.414 1.723 ;
     RECT  73.44 1.147 77.742 1.723 ;
     RECT  78.66 1.099 81.954 1.723 ;
     RECT  82.872 1.147 85.878 1.723 ;
     RECT  86.976 0.283 87.678 1.723 ;
     RECT  88.632 0.571 88.722 1.723 ;
     RECT  89.856 0.523 89.874 1.723 ;
     RECT  90.756 0.235 93.474 1.723 ;
     RECT  94.968 1.147 99.198 1.723 ;
     RECT  100.188 1.675 101.97 1.723 ;
     RECT  103.536 1.147 104.562 1.723 ;
     RECT  105.732 0.283 107.082 1.723 ;
     RECT  108.684 0.571 110.286 1.723 ;
     RECT  111.384 0.187 111.762 1.723 ;
     RECT  112.716 0.619 113.238 1.723 ;
     RECT  115.272 0.235 115.362 1.723 ;
     RECT  116.388 1.099 117.342 1.723 ;
     RECT  118.224 1.675 118.926 1.723 ;
     RECT  119.772 0.571 120.654 1.723 ;
     RECT  121.968 1.675 123.894 1.723 ;
     RECT  73.332 1.723 77.814 1.771 ;
     RECT  121.788 1.723 124.29 1.771 ;
     RECT  94.932 1.723 110.286 1.819 ;
     RECT  111.204 1.723 115.47 1.819 ;
     RECT  121.788 1.771 124.686 1.819 ;
     RECT  59.94 1.723 61.398 2.101 ;
     RECT  62.28 1.723 72.414 2.101 ;
     RECT  73.332 1.771 77.886 2.101 ;
     RECT  78.624 1.723 94.05 2.101 ;
     RECT  59.94 2.101 72.414 2.143 ;
     RECT  73.224 2.101 94.05 2.143 ;
     RECT  94.932 1.819 115.506 2.143 ;
     RECT  116.388 1.723 121.05 2.143 ;
     RECT  121.788 1.819 125.082 2.143 ;
     RECT  59.94 2.143 125.082 2.263 ;
     RECT  2.415 2.143 2.505 2.413 ;
     RECT  7.815 2.143 7.905 2.413 ;
     RECT  13.215 2.143 13.305 2.413 ;
     RECT  18.615 2.143 18.705 2.413 ;
     RECT  24.015 2.143 24.105 2.413 ;
     RECT  29.415 2.143 29.505 2.413 ;
     RECT  34.815 2.143 34.905 2.413 ;
     RECT  40.215 2.143 40.305 2.413 ;
     RECT  45.615 2.143 45.705 2.413 ;
     RECT  51.015 2.143 51.105 2.413 ;
     RECT  56.415 2.143 56.505 2.413 ;
     RECT  126.615 2.143 126.705 2.413 ;
     RECT  132.015 2.143 132.105 2.413 ;
     RECT  137.415 2.143 137.505 2.413 ;
     RECT  142.815 2.143 142.905 2.413 ;
     RECT  148.215 2.143 148.305 2.413 ;
     RECT  153.615 2.143 153.705 2.413 ;
     RECT  159.015 2.143 159.105 2.413 ;
     RECT  164.415 2.143 164.505 2.413 ;
     RECT  169.815 2.143 169.905 2.413 ;
     RECT  175.215 2.143 175.305 2.413 ;
     RECT  180.615 2.143 180.705 2.413 ;
     RECT  186.015 2.143 186.105 2.413 ;
     RECT  191.415 2.143 191.505 2.413 ;
     RECT  196.815 2.143 196.905 2.413 ;
     RECT  202.215 2.143 202.305 2.413 ;
     RECT  207.615 2.143 207.705 2.413 ;
     RECT  213.015 2.143 213.105 2.413 ;
     RECT  218.415 2.143 218.505 2.413 ;
     RECT  223.815 2.143 223.905 2.413 ;
     RECT  229.215 2.143 229.305 2.413 ;
     RECT  234.615 2.143 234.705 2.413 ;
     RECT  59.832 2.263 125.082 2.605 ;
     RECT  59.184 2.605 125.082 2.641 ;
     RECT  59.184 2.641 125.298 3.001 ;
     RECT  59.184 3.001 125.442 3.181 ;
     RECT  59.184 3.181 125.73 4.109 ;
     RECT  59.292 4.109 125.73 4.289 ;
     RECT  59.364 4.289 125.73 4.919 ;
     RECT  59.616 4.919 125.73 5.189 ;
     RECT  59.904 5.189 125.73 5.459 ;
     RECT  126.615 2.413 126.897 5.995 ;
     RECT  60.048 5.459 125.73 6.277 ;
     RECT  126.615 5.995 126.99 6.277 ;
     RECT  56.415 2.413 56.697 6.313 ;
     RECT  58.716 6.283 58.734 6.313 ;
     RECT  58.716 6.313 58.842 6.349 ;
     RECT  60.048 6.277 126.99 6.385 ;
     RECT  128.088 6.349 128.106 6.385 ;
     RECT  60.048 6.385 128.106 6.421 ;
     RECT  60.048 6.421 128.214 6.511 ;
     RECT  60.048 6.511 128.826 6.571 ;
     RECT  132.015 2.413 132.297 6.583 ;
     RECT  132.015 6.583 132.894 6.619 ;
     RECT  56.415 6.313 56.79 6.655 ;
     RECT  57.528 6.421 57.546 6.655 ;
     RECT  135.9 6.139 135.918 6.667 ;
     RECT  51.015 2.413 51.297 6.691 ;
     RECT  54.144 6.349 54.162 6.691 ;
     RECT  58.716 6.349 58.95 6.691 ;
     RECT  59.94 6.571 128.826 6.691 ;
     RECT  52.668 6.277 52.686 6.809 ;
     RECT  53.82 6.691 54.162 6.845 ;
     RECT  58.716 6.691 128.826 6.859 ;
     RECT  46.98 6.655 46.998 6.889 ;
     RECT  55.188 6.889 55.206 6.925 ;
     RECT  137.415 2.413 137.697 6.925 ;
     RECT  54.144 6.845 54.162 6.961 ;
     RECT  55.08 6.925 55.206 6.961 ;
     RECT  58.716 6.859 129.366 6.961 ;
     RECT  132.015 6.619 133.146 6.961 ;
     RECT  46.764 6.889 46.998 6.989 ;
     RECT  58.716 6.961 129.618 7.045 ;
     RECT  50.796 6.691 51.297 7.051 ;
     RECT  136.908 6.925 137.697 7.051 ;
     RECT  132.015 6.961 133.866 7.099 ;
     RECT  43.272 6.961 43.29 7.123 ;
     RECT  48.78 7.051 48.798 7.123 ;
     RECT  132.015 7.099 134.046 7.147 ;
     RECT  135.216 6.667 135.918 7.147 ;
     RECT  43.236 7.123 43.29 7.159 ;
     RECT  56.415 6.655 57.546 7.159 ;
     RECT  58.716 7.045 129.69 7.187 ;
     RECT  128.124 7.187 129.69 7.195 ;
     RECT  130.536 6.955 130.554 7.195 ;
     RECT  132.015 7.147 135.918 7.229 ;
     RECT  40.215 2.413 40.497 7.231 ;
     RECT  48.78 7.123 49.482 7.231 ;
     RECT  52.56 6.817 52.578 7.231 ;
     RECT  128.124 7.195 130.554 7.231 ;
     RECT  135.9 7.229 135.918 7.231 ;
     RECT  136.764 7.051 137.697 7.231 ;
     RECT  48.6 7.231 49.482 7.259 ;
     RECT  44.676 7.231 44.694 7.321 ;
     RECT  48.6 7.259 49.41 7.349 ;
     RECT  132.015 7.229 135.162 7.349 ;
     RECT  139.968 7.231 139.986 7.349 ;
     RECT  44.532 7.321 44.694 7.357 ;
     RECT  45.615 2.413 45.897 7.357 ;
     RECT  141.768 6.853 141.786 7.357 ;
     RECT  52.344 7.231 52.578 7.385 ;
     RECT  132.015 7.349 135.126 7.385 ;
     RECT  135.9 7.231 137.697 7.385 ;
     RECT  43.2 7.159 43.29 7.387 ;
     RECT  44.424 7.357 44.694 7.421 ;
     RECT  45.504 7.357 45.897 7.421 ;
     RECT  48.6 7.349 49.23 7.421 ;
     RECT  140.724 7.321 140.742 7.435 ;
     RECT  141.66 7.357 141.786 7.435 ;
     RECT  48.6 7.421 48.69 7.465 ;
     RECT  56.415 7.159 57.726 7.465 ;
     RECT  58.716 7.187 127.314 7.465 ;
     RECT  138.564 7.387 138.582 7.465 ;
     RECT  39.312 7.231 40.497 7.501 ;
     RECT  45.615 7.421 45.897 7.501 ;
     RECT  46.764 6.989 46.926 7.501 ;
     RECT  50.724 7.051 51.297 7.501 ;
     RECT  137.196 7.385 137.697 7.501 ;
     RECT  138.42 7.465 138.582 7.501 ;
     RECT  140.724 7.435 141.786 7.501 ;
     RECT  142.815 2.413 143.097 7.501 ;
     RECT  52.56 7.385 52.578 7.591 ;
     RECT  137.196 7.501 138.582 7.591 ;
     RECT  44.532 7.421 44.694 7.619 ;
     RECT  43.2 7.387 43.362 7.655 ;
     RECT  45.615 7.501 46.926 7.655 ;
     RECT  137.196 7.591 139.122 7.663 ;
     RECT  54.144 6.961 55.206 7.723 ;
     RECT  54.108 7.723 55.206 7.735 ;
     RECT  56.415 7.465 127.314 7.735 ;
     RECT  128.124 7.231 131.13 7.735 ;
     RECT  132.015 7.385 132.318 7.735 ;
     RECT  137.196 7.663 139.23 7.763 ;
     RECT  50.472 7.501 51.297 7.771 ;
     RECT  165.744 7.465 165.762 7.771 ;
     RECT  166.968 7.699 166.986 7.771 ;
     RECT  162.468 7.699 162.486 7.799 ;
     RECT  166.896 7.771 166.986 7.799 ;
     RECT  46.8 7.655 46.926 7.861 ;
     RECT  50.472 7.771 51.39 7.861 ;
     RECT  47.88 7.465 48.69 7.889 ;
     RECT  50.328 7.861 51.39 7.889 ;
     RECT  54.108 7.735 127.314 7.889 ;
     RECT  138.492 7.763 139.23 7.889 ;
     RECT  165.528 7.771 166.158 7.897 ;
     RECT  166.896 7.799 166.914 7.897 ;
     RECT  204.444 7.771 204.462 7.897 ;
     RECT  54.108 7.889 95.562 7.925 ;
     RECT  140.544 7.501 143.097 7.925 ;
     RECT  204.408 7.897 204.462 7.933 ;
     RECT  46.8 7.861 46.998 7.949 ;
     RECT  141.012 7.925 143.097 7.961 ;
     RECT  165.528 7.897 166.914 7.961 ;
     RECT  96.336 7.889 127.314 7.969 ;
     RECT  55.764 7.925 95.562 7.997 ;
     RECT  96.336 7.969 127.386 8.155 ;
     RECT  128.124 7.735 132.318 8.155 ;
     RECT  47.88 7.889 48.618 8.167 ;
     RECT  166.356 7.961 166.374 8.195 ;
     RECT  42.012 7.771 42.03 8.239 ;
     RECT  54.108 7.925 54.99 8.239 ;
     RECT  47.844 8.167 48.618 8.267 ;
     RECT  50.328 7.889 51.297 8.275 ;
     RECT  52.56 7.591 52.722 8.311 ;
     RECT  133.272 7.385 135.126 8.311 ;
     RECT  135.9 7.385 136.026 8.311 ;
     RECT  141.012 7.961 141.75 8.339 ;
     RECT  49.716 8.275 51.297 8.477 ;
     RECT  96.336 8.155 132.318 8.509 ;
     RECT  133.272 8.311 136.026 8.509 ;
     RECT  96.336 8.509 136.026 8.581 ;
     RECT  15.12 8.581 15.138 8.743 ;
     RECT  55.836 7.997 95.562 8.743 ;
     RECT  142.815 7.961 143.097 8.743 ;
     RECT  96.336 8.581 136.206 8.771 ;
     RECT  52.2 8.311 52.722 8.815 ;
     RECT  46.98 7.949 46.998 8.851 ;
     RECT  48.6 8.267 48.618 8.851 ;
     RECT  55.764 8.743 95.562 8.969 ;
     RECT  142.344 8.743 143.097 8.969 ;
     RECT  53.604 8.239 54.99 9.067 ;
     RECT  45.615 7.655 45.897 9.085 ;
     RECT  46.764 8.851 46.998 9.085 ;
     RECT  47.844 8.267 47.862 9.085 ;
     RECT  138.492 7.889 139.158 9.085 ;
     RECT  46.764 9.085 47.862 9.113 ;
     RECT  48.6 8.851 49.05 9.113 ;
     RECT  53.46 9.067 55.026 9.121 ;
     RECT  55.764 8.969 90.018 9.121 ;
     RECT  138.492 9.085 139.194 9.239 ;
     RECT  14.904 8.743 15.138 9.247 ;
     RECT  13.215 2.413 13.497 9.391 ;
     RECT  14.796 9.247 15.138 9.391 ;
     RECT  90.756 8.969 95.562 9.391 ;
     RECT  96.336 8.771 136.134 9.391 ;
     RECT  137.196 7.763 137.697 9.391 ;
     RECT  53.46 9.121 90.018 9.509 ;
     RECT  52.092 8.815 52.722 9.517 ;
     RECT  53.46 9.509 89.838 9.517 ;
     RECT  141.012 8.339 141.03 9.589 ;
     RECT  180.615 2.413 180.897 9.595 ;
     RECT  49.932 8.477 51.297 9.625 ;
     RECT  138.528 9.239 139.194 9.625 ;
     RECT  140.472 9.589 141.03 9.625 ;
     RECT  43.2 7.655 43.218 9.661 ;
     RECT  49.86 9.625 51.297 9.661 ;
     RECT  52.092 9.517 89.838 9.661 ;
     RECT  138.528 9.625 141.03 9.689 ;
     RECT  90.756 9.391 136.134 9.751 ;
     RECT  142.56 8.969 143.097 9.787 ;
     RECT  49.86 9.661 89.838 9.815 ;
     RECT  24.015 2.413 24.297 9.859 ;
     RECT  140.544 9.689 141.03 9.895 ;
     RECT  90.756 9.751 136.314 9.931 ;
     RECT  90.648 9.931 136.314 9.959 ;
     RECT  140.544 9.895 141.678 10.012 ;
     RECT  137.124 9.391 137.697 10.027 ;
     RECT  54.684 9.815 89.838 10.049 ;
     RECT  138.528 9.689 139.77 10.049 ;
     RECT  39.168 7.501 40.497 10.057 ;
     RECT  42.012 8.239 42.318 10.057 ;
     RECT  46.98 9.113 47.862 10.057 ;
     RECT  48.6 9.113 48.618 10.057 ;
     RECT  138.528 10.049 139.662 10.061 ;
     RECT  140.544 10.012 141.714 10.093 ;
     RECT  142.524 9.787 143.097 10.093 ;
     RECT  41.832 10.057 42.318 10.165 ;
     RECT  137.124 10.027 137.79 10.205 ;
     RECT  55.044 10.049 89.838 10.315 ;
     RECT  90.648 9.959 136.242 10.315 ;
     RECT  140.544 10.093 143.097 10.355 ;
     RECT  13.215 9.391 15.138 10.561 ;
     RECT  46.98 10.057 48.618 10.561 ;
     RECT  24.015 9.859 24.534 10.589 ;
     RECT  41.652 10.165 42.318 10.589 ;
     RECT  55.044 10.315 136.242 10.589 ;
     RECT  96.876 10.589 136.17 10.625 ;
     RECT  46.764 10.561 48.618 10.633 ;
     RECT  13.215 10.561 15.786 10.669 ;
     RECT  38.772 10.057 40.497 10.669 ;
     RECT  43.2 9.661 43.722 10.741 ;
     RECT  44.532 7.619 44.55 10.741 ;
     RECT  38.772 10.669 41.094 10.769 ;
     RECT  138.528 10.061 139.158 10.831 ;
     RECT  55.044 10.589 96.138 10.859 ;
     RECT  138.528 10.831 139.662 10.859 ;
     RECT  46.656 10.633 48.618 10.867 ;
     RECT  49.86 9.815 53.91 10.867 ;
     RECT  55.044 10.859 96.102 10.939 ;
     RECT  46.656 10.867 53.91 10.967 ;
     RECT  45.36 9.085 45.897 10.975 ;
     RECT  46.656 10.967 48.618 10.975 ;
     RECT  49.356 10.967 53.91 11.069 ;
     RECT  42.012 10.589 42.318 11.101 ;
     RECT  43.2 10.741 44.55 11.101 ;
     RECT  54.72 10.939 96.102 11.165 ;
     RECT  52.2 11.069 53.91 11.173 ;
     RECT  54.72 11.165 91.89 11.173 ;
     RECT  42.012 11.101 44.55 11.209 ;
     RECT  45.36 10.975 48.618 11.209 ;
     RECT  52.2 11.173 91.89 11.273 ;
     RECT  9.9 11.137 9.918 11.371 ;
     RECT  49.356 11.069 51.354 11.435 ;
     RECT  52.2 11.273 52.722 11.669 ;
     RECT  92.88 11.165 96.102 11.669 ;
     RECT  220.356 11.281 220.374 11.669 ;
     RECT  12.168 11.281 12.186 11.677 ;
     RECT  95.94 11.669 96.102 11.705 ;
     RECT  96.876 10.625 135.954 11.705 ;
     RECT  21.384 11.209 21.402 11.713 ;
     RECT  42.012 11.209 48.618 11.713 ;
     RECT  11.448 11.677 12.186 11.749 ;
     RECT  96.084 11.705 96.102 11.785 ;
     RECT  96.876 11.705 96.966 11.785 ;
     RECT  153.615 2.413 153.897 11.785 ;
     RECT  164.415 2.413 164.697 11.785 ;
     RECT  172.008 11.515 172.026 11.803 ;
     RECT  49.824 11.435 51.354 11.821 ;
     RECT  53.82 11.273 91.89 11.911 ;
     RECT  92.88 11.669 94.95 11.911 ;
     RECT  42.012 11.713 48.942 11.939 ;
     RECT  96.084 11.785 96.966 11.939 ;
     RECT  97.992 11.705 135.954 11.939 ;
     RECT  183.384 11.011 183.402 11.947 ;
     RECT  96.948 11.939 96.966 11.975 ;
     RECT  96.084 11.939 96.102 11.981 ;
     RECT  172.008 11.803 172.494 11.983 ;
     RECT  53.82 11.911 94.95 12.019 ;
     RECT  98.352 11.939 135.954 12.091 ;
     RECT  45.36 11.939 48.942 12.181 ;
     RECT  49.824 11.821 51.498 12.181 ;
     RECT  52.308 11.669 52.722 12.181 ;
     RECT  53.604 12.019 94.95 12.181 ;
     RECT  42.012 11.939 44.55 12.209 ;
     RECT  98.352 12.091 136.026 12.209 ;
     RECT  9.828 11.371 9.918 12.217 ;
     RECT  52.308 12.181 94.95 12.232 ;
     RECT  52.308 12.232 68.346 12.281 ;
     RECT  175.215 2.413 175.497 12.283 ;
     RECT  18.615 2.413 18.897 12.289 ;
     RECT  99.615 12.209 136.026 12.289 ;
     RECT  137.124 10.205 137.697 12.289 ;
     RECT  207.615 2.413 207.897 12.331 ;
     RECT  24.015 10.589 24.297 12.361 ;
     RECT  148.215 2.413 148.497 12.361 ;
     RECT  159.015 2.413 159.297 12.361 ;
     RECT  169.815 2.413 170.097 12.361 ;
     RECT  207.504 12.331 207.897 12.361 ;
     RECT  53.892 12.281 68.346 12.389 ;
     RECT  69.156 12.232 94.95 12.389 ;
     RECT  99.615 12.289 137.697 12.389 ;
     RECT  148.104 12.361 148.497 12.413 ;
     RECT  153.504 11.785 153.897 12.413 ;
     RECT  158.904 12.361 159.297 12.413 ;
     RECT  164.304 11.785 164.697 12.413 ;
     RECT  169.704 12.361 170.097 12.413 ;
     RECT  45.36 12.181 51.498 12.427 ;
     RECT  45.36 12.427 51.534 12.479 ;
     RECT  19.728 10.057 19.746 12.487 ;
     RECT  53.892 12.389 67.497 12.515 ;
     RECT  207.072 12.361 207.897 12.557 ;
     RECT  223.815 2.413 224.097 12.571 ;
     RECT  174.528 12.283 175.497 12.595 ;
     RECT  23.616 12.361 24.297 12.631 ;
     RECT  45.36 12.479 51.297 12.749 ;
     RECT  53.892 12.515 55.278 12.749 ;
     RECT  69.156 12.389 92.142 12.749 ;
     RECT  13.215 10.669 16.218 12.757 ;
     RECT  52.308 12.281 53.118 12.757 ;
     RECT  56.052 12.515 67.497 12.785 ;
     RECT  228.168 11.131 228.186 12.793 ;
     RECT  229.215 2.413 229.497 12.793 ;
     RECT  180.216 9.595 180.897 12.811 ;
     RECT  92.88 12.389 94.95 12.857 ;
     RECT  21.384 11.713 21.618 12.865 ;
     RECT  99.615 12.389 100.206 12.893 ;
     RECT  11.448 11.749 12.258 12.901 ;
     RECT  13.215 12.757 16.542 12.901 ;
     RECT  101.124 12.389 137.697 12.929 ;
     RECT  63.612 12.785 67.497 13.019 ;
     RECT  96.912 12.829 96.93 13.019 ;
     RECT  221.076 12.859 221.094 13.019 ;
     RECT  9.612 12.217 9.918 13.027 ;
     RECT  63.648 13.019 67.497 13.055 ;
     RECT  17.928 12.289 18.897 13.063 ;
     RECT  19.728 12.487 20.322 13.063 ;
     RECT  52.2 12.757 53.118 13.063 ;
     RECT  53.892 12.749 55.242 13.063 ;
     RECT  98.352 12.209 98.37 13.063 ;
     RECT  178.992 12.619 179.01 13.063 ;
     RECT  180.18 12.811 180.897 13.063 ;
     RECT  220.284 11.785 220.302 13.063 ;
     RECT  98.352 13.063 98.442 13.091 ;
     RECT  178.992 13.063 180.897 13.171 ;
     RECT  49.392 12.749 51.297 13.289 ;
     RECT  11.448 12.901 16.542 13.333 ;
     RECT  178.992 13.171 181.314 13.333 ;
     RECT  9.612 13.027 10.53 13.369 ;
     RECT  11.448 13.333 17.118 13.369 ;
     RECT  17.928 13.063 20.322 13.369 ;
     RECT  69.228 12.749 92.142 13.369 ;
     RECT  92.88 12.857 93.006 13.369 ;
     RECT  226.368 13.135 226.386 13.369 ;
     RECT  172.008 11.983 173.142 13.405 ;
     RECT  174.204 12.595 175.497 13.405 ;
     RECT  42.012 12.209 42.318 13.441 ;
     RECT  69.228 13.369 93.006 13.469 ;
     RECT  153.615 12.413 153.897 13.531 ;
     RECT  69.228 13.469 77.274 13.559 ;
     RECT  101.772 12.929 137.697 13.559 ;
     RECT  138.6 10.859 139.662 13.567 ;
     RECT  140.58 10.355 143.097 13.567 ;
     RECT  152.928 13.531 153.897 13.567 ;
     RECT  49.86 13.289 51.297 13.603 ;
     RECT  152.568 13.567 153.897 13.613 ;
     RECT  136.764 13.559 137.697 13.639 ;
     RECT  138.6 13.567 143.097 13.639 ;
     RECT  152.928 13.613 153.897 13.661 ;
     RECT  63.684 13.055 67.497 13.667 ;
     RECT  101.772 13.559 136.026 13.667 ;
     RECT  98.424 13.091 98.442 13.675 ;
     RECT  94.215 12.857 94.95 13.703 ;
     RECT  98.424 13.675 98.622 13.829 ;
     RECT  218.415 2.413 218.697 13.867 ;
     RECT  221.976 13.801 221.994 13.901 ;
     RECT  220.284 13.063 220.986 13.915 ;
     RECT  164.415 12.413 164.697 13.945 ;
     RECT  225.972 13.369 226.386 13.945 ;
     RECT  186.015 2.413 186.297 13.963 ;
     RECT  196.815 2.413 197.097 13.963 ;
     RECT  207.615 12.557 207.897 13.963 ;
     RECT  100.908 13.801 100.926 13.973 ;
     RECT  17.928 13.369 20.394 13.981 ;
     RECT  153.504 13.661 153.897 13.997 ;
     RECT  164.304 13.945 164.697 13.997 ;
     RECT  218.304 13.867 218.697 13.997 ;
     RECT  185.904 13.963 186.297 14.009 ;
     RECT  196.704 13.963 197.097 14.009 ;
     RECT  52.2 13.063 55.242 14.099 ;
     RECT  69.228 13.559 77.094 14.099 ;
     RECT  228.168 12.793 229.497 14.107 ;
     RECT  49.86 13.603 51.426 14.143 ;
     RECT  52.2 14.099 55.062 14.143 ;
     RECT  207.504 13.963 207.897 14.155 ;
     RECT  207.252 14.155 207.897 14.203 ;
     RECT  207.18 14.203 207.897 14.215 ;
     RECT  23.616 12.631 24.534 14.243 ;
     RECT  49.86 14.143 55.062 14.279 ;
     RECT  78.015 13.469 93.006 14.279 ;
     RECT  98.424 13.829 98.442 14.279 ;
     RECT  82.98 14.279 93.006 14.299 ;
     RECT  45.36 12.749 48.618 14.341 ;
     RECT  82.98 14.299 93.186 14.369 ;
     RECT  9.612 13.369 17.118 14.449 ;
     RECT  17.892 13.981 20.394 14.449 ;
     RECT  208.872 11.821 208.89 14.485 ;
     RECT  45.36 14.341 49.05 14.521 ;
     RECT  210.132 11.755 210.15 14.521 ;
     RECT  213.015 2.413 213.297 14.611 ;
     RECT  45.36 14.521 49.122 14.675 ;
     RECT  183.384 11.947 183.834 14.731 ;
     RECT  210.132 14.521 210.186 14.791 ;
     RECT  76.86 14.099 77.094 14.819 ;
     RECT  45.36 14.675 49.014 14.909 ;
     RECT  76.86 14.819 77.022 14.909 ;
     RECT  102.24 13.667 136.026 14.909 ;
     RECT  223.128 12.571 224.097 14.909 ;
     RECT  56.052 12.785 62.838 14.981 ;
     RECT  49.86 14.279 53.91 14.989 ;
     RECT  69.228 14.099 76.086 15.025 ;
     RECT  76.86 14.909 76.878 15.025 ;
     RECT  78.015 14.279 82.242 15.025 ;
     RECT  82.98 14.369 93.006 15.025 ;
     RECT  182.268 12.523 182.286 15.025 ;
     RECT  225.972 13.945 226.674 15.061 ;
     RECT  227.808 14.107 229.497 15.061 ;
     RECT  178.488 13.333 181.314 15.223 ;
     RECT  223.2 14.909 224.097 15.259 ;
     RECT  21.384 12.865 22.014 15.295 ;
     RECT  43.272 12.209 44.55 15.331 ;
     RECT  45.36 14.909 47.862 15.331 ;
     RECT  178.38 15.223 181.314 15.331 ;
     RECT  63.684 13.667 64.35 15.359 ;
     RECT  136.764 13.639 143.097 15.421 ;
     RECT  65.376 13.667 67.497 15.449 ;
     RECT  48.6 14.909 49.014 15.457 ;
     RECT  49.752 14.989 53.91 15.457 ;
     RECT  220.284 13.915 221.886 15.499 ;
     RECT  220.284 15.499 222.318 15.529 ;
     RECT  225.972 15.061 229.497 15.565 ;
     RECT  153.615 13.997 153.897 15.592 ;
     RECT  164.415 13.997 164.697 15.592 ;
     RECT  186.015 14.009 186.297 15.592 ;
     RECT  196.815 14.009 197.097 15.592 ;
     RECT  218.415 13.997 218.697 15.592 ;
     RECT  41.904 13.441 42.318 15.601 ;
     RECT  43.272 15.331 47.862 15.601 ;
     RECT  169.815 12.413 170.097 15.601 ;
     RECT  182.16 15.025 182.286 15.601 ;
     RECT  206.496 14.215 207.897 15.601 ;
     RECT  225.864 15.565 229.497 15.601 ;
     RECT  136.764 15.421 143.154 15.629 ;
     RECT  153.504 15.592 153.897 15.629 ;
     RECT  164.304 15.592 164.697 15.629 ;
     RECT  185.904 15.592 186.297 15.629 ;
     RECT  196.704 15.592 197.097 15.629 ;
     RECT  41.904 15.601 47.862 15.691 ;
     RECT  48.6 15.457 53.91 15.691 ;
     RECT  78.015 15.025 93.006 15.691 ;
     RECT  41.904 15.691 53.91 15.719 ;
     RECT  101.664 15.295 101.97 15.719 ;
     RECT  136.764 15.629 143.097 15.719 ;
     RECT  223.2 15.259 224.694 15.755 ;
     RECT  177.984 15.331 181.314 15.763 ;
     RECT  77.688 15.691 93.006 15.773 ;
     RECT  102.708 14.909 136.026 15.871 ;
     RECT  225.72 15.601 229.497 15.871 ;
     RECT  218.304 15.592 218.697 15.899 ;
     RECT  21.384 15.295 22.59 15.961 ;
     RECT  39.168 10.769 40.497 15.961 ;
     RECT  177.372 15.763 181.314 15.961 ;
     RECT  182.16 15.601 182.43 15.961 ;
     RECT  183.384 14.731 183.87 15.961 ;
     RECT  9.612 14.449 20.394 15.979 ;
     RECT  21.348 15.961 22.59 15.979 ;
     RECT  210.132 14.791 210.258 15.979 ;
     RECT  212.328 14.611 213.297 15.979 ;
     RECT  219.816 15.529 222.318 15.979 ;
     RECT  45.615 15.719 53.91 15.989 ;
     RECT  69.228 15.025 76.878 15.989 ;
     RECT  172.008 13.405 175.497 15.997 ;
     RECT  48.6 15.989 53.91 16.024 ;
     RECT  150.48 15.601 150.498 16.027 ;
     RECT  162.468 15.601 162.486 16.027 ;
     RECT  169.815 15.601 170.442 16.027 ;
     RECT  177.372 15.961 182.43 16.027 ;
     RECT  194.364 15.601 194.382 16.027 ;
     RECT  102.672 15.871 136.026 16.033 ;
     RECT  136.764 15.719 138.294 16.033 ;
     RECT  9.612 15.979 22.59 16.069 ;
     RECT  210.132 15.979 210.366 16.075 ;
     RECT  214.344 15.601 214.362 16.075 ;
     RECT  219.6 15.979 222.318 16.075 ;
     RECT  48.6 16.024 54.054 16.105 ;
     RECT  218.415 15.899 218.697 16.105 ;
     RECT  219.492 16.075 222.318 16.105 ;
     RECT  223.2 15.755 224.097 16.105 ;
     RECT  54.864 14.279 55.062 16.141 ;
     RECT  56.052 14.981 62.73 16.141 ;
     RECT  169.815 16.027 170.55 16.141 ;
     RECT  206.352 15.601 207.897 16.141 ;
     RECT  212.328 15.979 213.318 16.141 ;
     RECT  150.48 16.027 150.57 16.157 ;
     RECT  162.468 16.027 162.558 16.157 ;
     RECT  194.364 16.027 194.454 16.157 ;
     RECT  214.344 16.075 214.434 16.157 ;
     RECT  153.615 15.629 153.897 16.171 ;
     RECT  210.132 16.075 210.474 16.205 ;
     RECT  214.416 16.157 214.434 16.205 ;
     RECT  177.372 16.027 182.502 16.219 ;
     RECT  183.384 15.961 183.942 16.219 ;
     RECT  64.476 16.141 64.494 16.259 ;
     RECT  78.015 15.773 93.006 16.259 ;
     RECT  212.328 16.141 213.426 16.259 ;
     RECT  41.904 15.719 44.766 16.267 ;
     RECT  48.6 16.105 54.09 16.267 ;
     RECT  54.864 16.141 62.73 16.267 ;
     RECT  166.464 16.171 166.482 16.267 ;
     RECT  102.672 16.033 138.294 16.295 ;
     RECT  146.484 16.171 146.502 16.301 ;
     RECT  150.48 16.157 150.498 16.301 ;
     RECT  153.615 16.171 154.494 16.301 ;
     RECT  162.468 16.157 162.486 16.301 ;
     RECT  190.404 16.171 190.422 16.301 ;
     RECT  194.364 16.157 194.382 16.301 ;
     RECT  198.36 16.171 198.378 16.301 ;
     RECT  63.684 15.359 63.702 16.303 ;
     RECT  66.744 15.449 67.497 16.303 ;
     RECT  9.612 16.069 22.734 16.315 ;
     RECT  38.772 15.961 40.497 16.339 ;
     RECT  48.6 16.267 62.73 16.367 ;
     RECT  38.772 16.339 40.59 16.375 ;
     RECT  41.328 16.267 44.766 16.375 ;
     RECT  54.864 16.367 62.73 16.375 ;
     RECT  68.328 12.389 68.346 16.375 ;
     RECT  69.228 15.989 75.834 16.397 ;
     RECT  46.764 15.989 47.862 16.403 ;
     RECT  63.684 16.303 64.386 16.403 ;
     RECT  177.372 16.219 183.942 16.411 ;
     RECT  48.6 16.367 54.09 16.439 ;
     RECT  177.372 16.411 184.23 16.501 ;
     RECT  212.328 16.259 213.297 16.501 ;
     RECT  102.852 16.295 138.294 16.507 ;
     RECT  139.032 15.719 143.097 16.507 ;
     RECT  48.6 16.439 54.018 16.529 ;
     RECT  54.864 16.375 62.802 16.529 ;
     RECT  68.22 16.375 68.346 16.529 ;
     RECT  69.228 16.397 69.534 16.529 ;
     RECT  210.132 16.205 210.258 16.529 ;
     RECT  9.612 16.315 22.77 16.537 ;
     RECT  45.615 15.989 45.99 16.541 ;
     RECT  46.764 16.403 46.998 16.541 ;
     RECT  212.112 16.501 213.297 16.541 ;
     RECT  38.772 16.375 44.766 16.601 ;
     RECT  48.6 16.529 53.982 16.601 ;
     RECT  41.58 16.601 44.766 16.609 ;
     RECT  45.615 16.541 45.897 16.609 ;
     RECT  38.772 16.601 40.806 16.637 ;
     RECT  177.156 16.501 184.23 16.645 ;
     RECT  208.872 14.485 209.394 16.645 ;
     RECT  210.132 16.529 210.186 16.645 ;
     RECT  54.864 16.529 62.514 16.673 ;
     RECT  218.415 16.105 224.097 16.681 ;
     RECT  224.964 15.871 229.497 16.681 ;
     RECT  149.22 16.747 149.238 16.771 ;
     RECT  70.272 16.397 75.834 16.799 ;
     RECT  9.612 16.537 22.806 16.807 ;
     RECT  26.208 16.339 26.226 16.807 ;
     RECT  169.815 16.141 170.586 16.807 ;
     RECT  171.432 15.997 175.497 16.807 ;
     RECT  177.048 16.645 184.23 16.829 ;
     RECT  70.272 16.799 75.69 16.835 ;
     RECT  25.992 16.807 26.226 16.879 ;
     RECT  34.815 2.413 35.097 16.891 ;
     RECT  94.215 13.703 94.497 16.891 ;
     RECT  166.464 16.267 166.518 16.891 ;
     RECT  206.136 16.141 207.897 16.891 ;
     RECT  208.872 16.645 210.186 16.891 ;
     RECT  166.464 16.891 166.59 16.925 ;
     RECT  206.136 16.891 210.186 16.951 ;
     RECT  25.992 16.879 26.37 16.979 ;
     RECT  9.432 16.807 22.806 17.032 ;
     RECT  23.616 14.243 24.297 17.032 ;
     RECT  99.615 12.893 99.897 17.035 ;
     RECT  159.015 12.413 159.297 17.035 ;
     RECT  164.415 15.629 164.697 17.035 ;
     RECT  34.815 16.891 35.19 17.069 ;
     RECT  54.864 16.673 55.134 17.069 ;
     RECT  65.376 15.449 65.394 17.069 ;
     RECT  66.708 16.303 67.497 17.069 ;
     RECT  94.215 16.891 94.59 17.069 ;
     RECT  102.852 16.507 143.097 17.069 ;
     RECT  99.615 17.035 99.99 17.075 ;
     RECT  148.215 12.413 148.497 17.077 ;
     RECT  149.22 16.771 149.562 17.077 ;
     RECT  103.392 17.069 143.097 17.083 ;
     RECT  166.5 16.925 166.59 17.083 ;
     RECT  204.408 7.933 204.606 17.083 ;
     RECT  41.58 16.609 45.897 17.105 ;
     RECT  169.815 16.807 175.497 17.131 ;
     RECT  78.015 16.259 78.822 17.149 ;
     RECT  79.776 16.259 93.006 17.149 ;
     RECT  25.992 16.979 26.298 17.185 ;
     RECT  9.432 17.032 24.297 17.221 ;
     RECT  148.215 17.077 149.562 17.221 ;
     RECT  153.615 16.301 153.897 17.221 ;
     RECT  159.015 17.035 159.39 17.221 ;
     RECT  164.415 17.035 164.79 17.221 ;
     RECT  169.815 17.131 175.518 17.221 ;
     RECT  186.015 15.629 186.297 17.221 ;
     RECT  191.415 2.413 191.697 17.221 ;
     RECT  196.815 15.629 197.097 17.221 ;
     RECT  202.215 2.413 202.497 17.221 ;
     RECT  218.415 16.681 229.497 17.221 ;
     RECT  148.104 17.221 149.562 17.261 ;
     RECT  158.904 17.221 159.39 17.261 ;
     RECT  169.704 17.221 175.518 17.261 ;
     RECT  191.304 17.221 191.697 17.261 ;
     RECT  202.104 17.221 202.497 17.261 ;
     RECT  153.504 17.221 153.897 17.275 ;
     RECT  166.5 17.083 166.698 17.309 ;
     RECT  47.844 16.403 47.862 17.339 ;
     RECT  78.015 17.149 93.006 17.339 ;
     RECT  103.392 17.083 143.226 17.339 ;
     RECT  148.215 17.261 149.562 17.339 ;
     RECT  56.052 16.673 62.514 17.347 ;
     RECT  41.58 17.105 44.55 17.375 ;
     RECT  48.6 16.601 53.802 17.383 ;
     RECT  142.704 17.339 143.226 17.405 ;
     RECT  131.652 17.339 141.858 17.411 ;
     RECT  169.815 17.261 175.518 17.413 ;
     RECT  185.904 17.221 186.297 17.419 ;
     RECT  41.904 17.375 44.55 17.447 ;
     RECT  56.052 17.347 62.55 17.447 ;
     RECT  166.5 17.309 166.626 17.453 ;
     RECT  169.815 17.413 175.698 17.453 ;
     RECT  194.364 17.083 194.49 17.453 ;
     RECT  46.836 16.541 46.998 17.455 ;
     RECT  212.292 16.541 213.297 17.491 ;
     RECT  166.5 17.453 166.518 17.501 ;
     RECT  185.904 17.419 186.318 17.515 ;
     RECT  191.415 17.261 191.697 17.515 ;
     RECT  196.704 17.221 197.097 17.515 ;
     RECT  198.288 17.083 198.306 17.515 ;
     RECT  202.215 17.261 202.497 17.515 ;
     RECT  70.272 16.835 75.546 17.519 ;
     RECT  142.704 17.405 143.19 17.549 ;
     RECT  148.215 17.339 148.59 17.549 ;
     RECT  159.015 17.261 159.39 17.549 ;
     RECT  164.304 17.221 164.79 17.549 ;
     RECT  212.292 17.491 213.39 17.549 ;
     RECT  25.956 17.185 26.298 17.563 ;
     RECT  48.6 17.383 53.946 17.563 ;
     RECT  38.808 16.637 40.806 17.581 ;
     RECT  46.836 17.455 47.034 17.581 ;
     RECT  25.848 17.563 26.298 17.609 ;
     RECT  42.012 17.447 44.55 17.609 ;
     RECT  48.6 17.563 54.054 17.609 ;
     RECT  78.015 17.339 92.97 17.609 ;
     RECT  144.036 9.931 144.054 17.609 ;
     RECT  205.56 16.951 210.186 17.609 ;
     RECT  25.848 17.609 26.046 17.645 ;
     RECT  103.392 17.339 130.77 17.645 ;
     RECT  153.504 17.275 154.278 17.645 ;
     RECT  155.808 17.347 155.826 17.645 ;
     RECT  185.904 17.515 186.39 17.645 ;
     RECT  190.404 17.515 190.422 17.645 ;
     RECT  191.415 17.515 191.79 17.645 ;
     RECT  196.704 17.515 197.19 17.645 ;
     RECT  202.215 17.515 202.59 17.645 ;
     RECT  42.084 17.609 44.442 17.681 ;
     RECT  46.836 17.581 47.07 17.681 ;
     RECT  70.272 17.519 70.722 17.725 ;
     RECT  204.408 17.083 204.642 17.725 ;
     RECT  27.324 16.879 27.342 17.755 ;
     RECT  48.6 17.609 53.982 17.761 ;
     RECT  63.684 16.403 63.702 17.761 ;
     RECT  153.504 17.645 153.897 17.789 ;
     RECT  164.304 17.549 164.697 17.789 ;
     RECT  194.364 17.453 194.454 17.789 ;
     RECT  218.304 17.221 229.497 17.789 ;
     RECT  198.288 17.515 198.378 17.803 ;
     RECT  31.752 17.803 31.77 17.845 ;
     RECT  34.815 17.069 35.097 17.851 ;
     RECT  33.228 17.803 33.246 17.879 ;
     RECT  38.772 17.581 40.806 17.879 ;
     RECT  48.456 17.761 53.982 17.879 ;
     RECT  71.496 17.519 75.546 17.879 ;
     RECT  150.48 17.761 150.498 17.879 ;
     RECT  162.468 17.761 162.486 17.879 ;
     RECT  198.144 17.803 198.378 17.879 ;
     RECT  31.68 17.845 31.77 17.885 ;
     RECT  34.704 17.851 35.097 17.888 ;
     RECT  38.772 17.879 40.497 17.915 ;
     RECT  30.852 17.887 30.87 17.959 ;
     RECT  33.3 17.887 33.318 17.959 ;
     RECT  198.324 17.879 198.378 17.959 ;
     RECT  38.808 17.915 40.497 17.981 ;
     RECT  30.78 17.959 30.87 17.987 ;
     RECT  33.3 17.959 33.39 17.987 ;
     RECT  204.408 17.725 204.75 18.031 ;
     RECT  194.436 17.789 194.454 18.059 ;
     RECT  198.324 17.959 198.558 18.059 ;
     RECT  72.615 17.879 75.546 18.121 ;
     RECT  203.76 18.031 204.75 18.121 ;
     RECT  205.56 17.609 209.682 18.121 ;
     RECT  169.815 17.453 175.59 18.125 ;
     RECT  26.784 17.755 27.342 18.149 ;
     RECT  30.78 17.987 30.798 18.149 ;
     RECT  33.372 17.987 33.39 18.149 ;
     RECT  63.576 17.761 63.702 18.149 ;
     RECT  70.164 17.725 70.722 18.149 ;
     RECT  76.752 15.989 76.878 18.149 ;
     RECT  72.615 18.121 75.942 18.173 ;
     RECT  198.324 18.059 198.342 18.173 ;
     RECT  26.784 18.149 27.234 18.185 ;
     RECT  26.784 18.185 26.802 18.221 ;
     RECT  31.752 17.885 31.77 18.221 ;
     RECT  214.344 17.761 214.362 18.283 ;
     RECT  142.704 17.549 143.097 18.301 ;
     RECT  43.164 17.681 44.442 18.329 ;
     RECT  63.756 18.157 63.774 18.329 ;
     RECT  103.392 17.645 130.698 18.329 ;
     RECT  185.904 17.645 186.297 18.329 ;
     RECT  196.704 17.645 197.097 18.329 ;
     RECT  106.668 18.329 130.698 18.391 ;
     RECT  7.815 2.413 8.097 18.427 ;
     RECT  9.36 17.221 24.297 18.427 ;
     RECT  131.652 17.411 141.714 18.427 ;
     RECT  142.488 18.301 143.097 18.427 ;
     RECT  25.632 17.959 25.65 18.463 ;
     RECT  54.864 17.069 54.882 18.463 ;
     RECT  43.164 18.329 43.902 18.491 ;
     RECT  70.704 18.149 70.722 18.491 ;
     RECT  78.015 17.609 92.934 18.491 ;
     RECT  214.344 18.283 214.398 18.509 ;
     RECT  54.864 18.463 55.062 18.523 ;
     RECT  39.168 17.981 40.497 18.527 ;
     RECT  106.668 18.391 130.734 18.527 ;
     RECT  25.596 18.463 25.65 18.535 ;
     RECT  80.136 18.491 92.934 18.535 ;
     RECT  25.524 18.535 25.65 18.571 ;
     RECT  54.756 18.523 55.062 18.571 ;
     RECT  78.015 18.491 79.362 18.571 ;
     RECT  106.704 18.527 130.734 18.571 ;
     RECT  131.652 18.427 143.097 18.571 ;
     RECT  46.764 17.887 46.782 18.599 ;
     RECT  106.704 18.571 143.097 18.599 ;
     RECT  56.052 17.447 62.514 18.661 ;
     RECT  25.524 18.571 25.686 18.689 ;
     RECT  72.615 18.173 75.546 18.689 ;
     RECT  77.832 18.571 79.362 18.689 ;
     RECT  80.136 18.535 93.006 18.689 ;
     RECT  106.704 18.599 141.786 18.689 ;
     RECT  56.052 18.661 62.586 18.697 ;
     RECT  77.832 18.689 79.254 18.697 ;
     RECT  131.58 18.689 141.786 18.701 ;
     RECT  56.052 18.697 62.694 18.733 ;
     RECT  80.28 18.689 92.898 18.749 ;
     RECT  25.668 18.689 25.686 18.761 ;
     RECT  70.74 18.661 70.758 18.761 ;
     RECT  39.6 18.527 40.497 18.797 ;
     RECT  55.98 18.733 62.694 18.841 ;
     RECT  177.156 16.829 184.23 18.841 ;
     RECT  186.015 18.329 186.297 18.841 ;
     RECT  48.456 17.879 53.946 18.869 ;
     RECT  131.58 18.701 136.674 18.893 ;
     RECT  26.748 18.805 26.766 18.959 ;
     RECT  72.615 18.689 75.438 18.959 ;
     RECT  77.688 18.697 79.254 18.959 ;
     RECT  48.528 18.869 53.946 18.967 ;
     RECT  54.72 18.571 55.062 18.967 ;
     RECT  55.98 18.841 62.766 18.995 ;
     RECT  48.528 18.967 55.062 19.031 ;
     RECT  131.58 18.893 136.602 19.031 ;
     RECT  103.392 18.329 105.93 19.075 ;
     RECT  103.068 19.075 105.93 19.099 ;
     RECT  48.996 19.031 55.062 19.111 ;
     RECT  76.752 18.149 76.77 19.111 ;
     RECT  77.688 18.959 78.39 19.111 ;
     RECT  102.6 19.099 105.93 19.133 ;
     RECT  142.815 18.599 143.097 19.147 ;
     RECT  148.215 17.549 148.497 19.147 ;
     RECT  153.615 17.789 153.897 19.147 ;
     RECT  159.015 17.549 159.297 19.147 ;
     RECT  164.415 17.789 164.697 19.147 ;
     RECT  169.815 18.125 175.497 19.147 ;
     RECT  191.415 17.645 191.697 19.147 ;
     RECT  196.815 18.329 197.097 19.147 ;
     RECT  202.215 17.645 202.497 19.147 ;
     RECT  203.76 18.121 209.682 19.147 ;
     RECT  212.292 17.549 213.297 19.147 ;
     RECT  106.704 18.689 130.662 19.181 ;
     RECT  55.98 18.995 62.658 19.229 ;
     RECT  69.228 16.529 69.246 19.229 ;
     RECT  76.752 19.111 78.39 19.229 ;
     RECT  102.6 19.133 102.762 19.229 ;
     RECT  103.536 19.133 105.93 19.229 ;
     RECT  131.58 19.031 136.566 19.229 ;
     RECT  202.215 19.147 202.59 19.229 ;
     RECT  218.415 17.789 229.497 19.229 ;
     RECT  142.815 19.147 143.19 19.277 ;
     RECT  146.484 19.147 146.502 19.277 ;
     RECT  148.215 19.147 148.59 19.277 ;
     RECT  153.615 19.147 154.494 19.277 ;
     RECT  159.015 19.147 159.39 19.277 ;
     RECT  164.415 19.147 164.79 19.277 ;
     RECT  169.815 19.147 175.59 19.277 ;
     RECT  186.015 18.841 186.39 19.277 ;
     RECT  190.404 19.147 190.422 19.277 ;
     RECT  191.415 19.147 191.79 19.277 ;
     RECT  194.364 19.147 194.382 19.277 ;
     RECT  196.815 19.147 197.19 19.277 ;
     RECT  203.76 19.147 210.366 19.277 ;
     RECT  214.344 18.509 214.362 19.277 ;
     RECT  80.604 18.749 92.898 19.301 ;
     RECT  80.604 19.301 92.826 19.337 ;
     RECT  76.752 19.229 78.297 19.379 ;
     RECT  103.716 19.229 105.93 19.381 ;
     RECT  106.704 19.181 130.626 19.381 ;
     RECT  166.464 19.147 166.482 19.381 ;
     RECT  177.156 18.841 184.914 19.381 ;
     RECT  166.464 19.381 166.626 19.387 ;
     RECT  169.815 19.277 175.497 19.471 ;
     RECT  55.98 19.229 59.886 19.499 ;
     RECT  76.752 19.379 76.77 19.499 ;
     RECT  80.964 19.337 92.826 19.499 ;
     RECT  186.015 19.277 186.297 19.507 ;
     RECT  212.292 19.147 213.39 19.507 ;
     RECT  169.704 19.471 175.497 19.517 ;
     RECT  185.832 19.507 186.297 19.543 ;
     RECT  142.815 19.277 143.154 19.579 ;
     RECT  103.716 19.381 130.626 19.643 ;
     RECT  165.744 19.387 166.626 19.643 ;
     RECT  177.156 19.381 184.95 19.643 ;
     RECT  48.996 19.111 55.098 19.651 ;
     RECT  115.236 19.643 130.626 19.661 ;
     RECT  80.964 19.499 92.718 19.679 ;
     RECT  165.744 19.643 166.59 19.679 ;
     RECT  218.415 19.229 228.474 19.679 ;
     RECT  137.415 18.701 141.786 19.741 ;
     RECT  142.632 19.579 143.154 19.741 ;
     RECT  48.996 19.651 55.17 19.769 ;
     RECT  55.98 19.499 59.094 19.769 ;
     RECT  71.496 17.879 71.874 19.769 ;
     RECT  72.615 18.959 74.682 19.769 ;
     RECT  76.356 19.651 76.518 19.769 ;
     RECT  81.468 19.679 92.718 19.769 ;
     RECT  103.716 19.643 114.282 19.769 ;
     RECT  118.008 19.661 130.626 19.769 ;
     RECT  165.744 19.679 166.482 19.769 ;
     RECT  45.615 17.105 45.897 19.771 ;
     RECT  49.068 19.769 55.17 19.777 ;
     RECT  55.98 19.769 57.438 19.777 ;
     RECT  177.156 19.643 184.806 19.777 ;
     RECT  203.76 19.277 209.646 19.777 ;
     RECT  76.356 19.769 76.374 19.805 ;
     RECT  81.468 19.769 92.646 19.805 ;
     RECT  48.024 19.771 48.042 19.811 ;
     RECT  165.744 19.769 165.762 19.811 ;
     RECT  72.615 19.769 73.314 19.819 ;
     RECT  49.068 19.777 57.438 19.841 ;
     RECT  150.48 19.147 150.498 19.849 ;
     RECT  162.468 19.147 162.486 19.849 ;
     RECT  70.56 19.777 70.578 19.853 ;
     RECT  75.42 18.959 75.438 19.853 ;
     RECT  176.832 19.777 184.806 19.853 ;
     RECT  46.764 19.615 46.782 19.877 ;
     RECT  55.836 19.841 57.438 19.877 ;
     RECT  58.284 19.769 58.842 19.877 ;
     RECT  137.415 19.741 143.154 19.877 ;
     RECT  150.48 19.849 150.57 19.877 ;
     RECT  153.615 19.277 153.954 19.877 ;
     RECT  162.468 19.849 162.558 19.877 ;
     RECT  164.415 19.277 164.754 19.877 ;
     RECT  153.615 19.877 153.897 19.912 ;
     RECT  164.415 19.877 164.697 19.912 ;
     RECT  196.815 19.277 197.097 19.912 ;
     RECT  218.415 19.679 222.57 19.921 ;
     RECT  150.552 19.877 150.57 19.949 ;
     RECT  162.54 19.877 162.558 19.949 ;
     RECT  196.704 19.912 197.097 19.949 ;
     RECT  43.884 18.491 43.902 19.963 ;
     RECT  119.412 19.769 130.626 19.963 ;
     RECT  78.015 19.379 78.297 20.011 ;
     RECT  79.236 18.959 79.254 20.011 ;
     RECT  55.836 19.877 57.042 20.039 ;
     RECT  65.088 19.345 65.106 20.039 ;
     RECT  74.052 19.769 74.682 20.039 ;
     RECT  78.015 20.011 79.254 20.039 ;
     RECT  118.008 19.769 118.674 20.039 ;
     RECT  212.292 19.507 213.642 20.039 ;
     RECT  60.66 19.229 62.514 20.047 ;
     RECT  78.015 20.039 78.642 20.048 ;
     RECT  153.504 19.912 153.897 20.048 ;
     RECT  164.304 19.912 164.697 20.048 ;
     RECT  119.412 19.963 131.166 20.059 ;
     RECT  131.904 19.229 136.494 20.059 ;
     RECT  81.468 19.805 92.394 20.075 ;
     RECT  185.796 19.543 186.297 20.083 ;
     RECT  101.088 20.011 101.106 20.093 ;
     RECT  55.872 20.039 57.042 20.111 ;
     RECT  98.604 20.011 98.622 20.141 ;
     RECT  60.66 20.047 62.73 20.147 ;
     RECT  64.368 20.047 64.386 20.147 ;
     RECT  70.704 20.047 70.722 20.147 ;
     RECT  74.052 20.039 74.466 20.147 ;
     RECT  47.808 19.849 47.898 20.155 ;
     RECT  59.868 19.499 59.886 20.155 ;
     RECT  60.66 20.147 62.154 20.155 ;
     RECT  100.8 20.107 100.818 20.219 ;
     RECT  115.236 19.661 117.162 20.219 ;
     RECT  119.412 20.059 136.494 20.219 ;
     RECT  185.796 20.083 186.426 20.219 ;
     RECT  47.34 20.155 47.898 20.309 ;
     RECT  58.32 19.877 58.698 20.309 ;
     RECT  64.188 20.155 64.206 20.309 ;
     RECT  72.432 19.819 73.314 20.309 ;
     RECT  212.292 20.039 213.534 20.309 ;
     RECT  102.744 19.229 102.762 20.333 ;
     RECT  59.868 20.155 62.154 20.345 ;
     RECT  81.468 20.075 92.322 20.345 ;
     RECT  103.716 19.769 114.174 20.345 ;
     RECT  7.815 18.427 24.297 20.381 ;
     RECT  47.808 20.309 47.898 20.381 ;
     RECT  104.184 20.345 114.174 20.381 ;
     RECT  104.184 20.381 105.894 20.429 ;
     RECT  49.068 19.841 54.954 20.453 ;
     RECT  58.464 20.309 58.698 20.453 ;
     RECT  49.104 20.453 54.954 20.489 ;
     RECT  63.288 20.389 63.306 20.489 ;
     RECT  106.668 20.381 106.686 20.489 ;
     RECT  45 19.771 45.897 20.573 ;
     RECT  43.884 19.963 44.154 20.579 ;
     RECT  108.072 20.381 113.922 20.579 ;
     RECT  119.7 20.219 136.494 20.579 ;
     RECT  58.68 20.453 58.698 20.615 ;
     RECT  43.884 20.579 43.938 20.621 ;
     RECT  47.88 20.381 47.898 20.651 ;
     RECT  61.236 20.345 62.154 20.651 ;
     RECT  118.116 20.039 118.674 20.669 ;
     RECT  72.615 20.309 73.314 20.687 ;
     RECT  177.156 19.853 184.806 20.695 ;
     RECT  117.144 20.219 117.162 20.717 ;
     RECT  120.312 20.579 130.878 20.759 ;
     RECT  214.956 20.539 215.262 20.759 ;
     RECT  49.104 20.489 54.81 20.849 ;
     RECT  177.156 20.695 184.842 20.849 ;
     RECT  177.156 20.849 184.662 20.857 ;
     RECT  177.048 20.857 184.662 20.875 ;
     RECT  211.5 20.059 211.518 20.885 ;
     RECT  118.584 20.669 118.674 20.893 ;
     RECT  214.956 20.759 214.974 20.909 ;
     RECT  49.104 20.849 54.63 20.921 ;
     RECT  176.904 20.875 184.662 20.921 ;
     RECT  55.872 20.111 56.697 20.957 ;
     RECT  143.928 17.653 143.946 20.957 ;
     RECT  59.868 20.345 60.354 20.993 ;
     RECT  118.584 20.893 118.71 21.005 ;
     RECT  46.764 20.695 46.854 21.029 ;
     RECT  58.716 20.731 58.734 21.029 ;
     RECT  118.584 21.005 118.674 21.029 ;
     RECT  203.508 19.777 209.646 21.029 ;
     RECT  131.976 20.579 136.494 21.091 ;
     RECT  137.415 19.877 143.097 21.091 ;
     RECT  121.215 20.759 130.878 21.101 ;
     RECT  60.336 20.993 60.354 21.155 ;
     RECT  71.496 19.769 71.514 21.191 ;
     RECT  177.048 20.921 184.662 21.197 ;
     RECT  185.796 20.219 186.297 21.245 ;
     RECT  104.184 20.429 105.297 21.263 ;
     RECT  177.156 21.197 184.662 21.293 ;
     RECT  61.815 20.651 62.154 21.299 ;
     RECT  118.62 21.029 118.674 21.299 ;
     RECT  131.976 21.091 143.097 21.299 ;
     RECT  201.456 18.769 201.474 21.299 ;
     RECT  74.052 20.147 74.07 21.389 ;
     RECT  131.976 21.299 136.494 21.433 ;
     RECT  43.884 20.621 43.902 21.497 ;
     RECT  108.288 20.579 113.922 21.497 ;
     RECT  120.312 20.759 120.33 21.533 ;
     RECT  118.656 21.299 118.674 21.569 ;
     RECT  153.615 20.048 153.897 21.631 ;
     RECT  164.415 20.048 164.697 21.631 ;
     RECT  196.815 19.949 197.097 21.631 ;
     RECT  49.104 20.921 54.09 21.659 ;
     RECT  131.904 21.433 136.494 21.677 ;
     RECT  153.504 21.631 153.897 21.677 ;
     RECT  164.304 21.631 164.697 21.677 ;
     RECT  185.904 21.245 186.297 21.677 ;
     RECT  196.704 21.631 197.097 21.677 ;
     RECT  203.508 21.029 209.502 21.731 ;
     RECT  203.724 21.731 209.502 21.811 ;
     RECT  108.288 21.497 110.697 21.839 ;
     RECT  203.724 21.811 209.538 21.965 ;
     RECT  49.104 21.659 53.982 22.045 ;
     RECT  81.468 20.345 92.214 22.045 ;
     RECT  121.215 21.101 130.626 22.073 ;
     RECT  204.084 21.965 209.538 22.109 ;
     RECT  7.815 20.381 23.094 22.171 ;
     RECT  204.372 22.109 209.538 22.199 ;
     RECT  81.18 22.045 92.214 22.207 ;
     RECT  177.156 21.293 184.338 22.207 ;
     RECT  111.42 21.497 113.922 22.301 ;
     RECT  204.48 22.199 209.538 22.343 ;
     RECT  48.96 22.045 53.982 22.469 ;
     RECT  217.944 19.921 222.57 22.469 ;
     RECT  176.976 22.207 184.338 22.513 ;
     RECT  111.42 22.301 113.274 22.577 ;
     RECT  48.96 22.469 53.658 22.585 ;
     RECT  122.292 22.073 130.626 22.613 ;
     RECT  122.292 22.613 130.266 22.649 ;
     RECT  122.292 22.649 130.158 22.739 ;
     RECT  204.516 22.343 209.538 22.739 ;
     RECT  223.815 19.679 228.474 22.739 ;
     RECT  7.74 22.171 23.094 22.747 ;
     RECT  212.292 20.309 213.354 22.747 ;
     RECT  132.015 21.677 136.494 22.775 ;
     RECT  115.236 20.219 116.097 22.783 ;
     RECT  205.452 22.739 209.538 22.811 ;
     RECT  122.436 22.739 130.158 22.847 ;
     RECT  111.42 22.577 112.554 22.877 ;
     RECT  176.868 22.513 184.338 22.891 ;
     RECT  7.488 22.747 23.094 23.009 ;
     RECT  176.868 22.891 184.518 23.009 ;
     RECT  111.528 22.877 112.554 23.021 ;
     RECT  111.528 23.021 111.978 23.081 ;
     RECT  169.815 19.517 175.497 23.081 ;
     RECT  111.96 23.081 111.978 23.117 ;
     RECT  217.944 22.469 222.354 23.189 ;
     RECT  22.392 23.009 22.41 23.279 ;
     RECT  48.852 22.585 53.658 23.279 ;
     RECT  122.508 22.847 130.158 23.279 ;
     RECT  132.015 22.775 136.314 23.279 ;
     RECT  137.415 21.299 143.097 23.279 ;
     RECT  176.868 23.009 184.41 23.279 ;
     RECT  205.488 22.811 209.538 23.279 ;
     RECT  217.944 23.189 221.994 23.279 ;
     RECT  223.815 22.739 228.366 23.279 ;
     RECT  48.852 23.279 53.406 23.287 ;
     RECT  80.964 22.207 92.214 23.351 ;
     RECT  122.508 23.279 129.87 23.351 ;
     RECT  205.632 23.279 209.538 23.351 ;
     RECT  7.488 23.009 21.654 23.405 ;
     RECT  169.815 23.081 174.474 23.405 ;
     RECT  176.868 23.279 184.014 23.405 ;
     RECT  212.148 22.747 213.354 23.405 ;
     RECT  104.832 21.263 105.297 23.423 ;
     RECT  7.488 23.405 21.51 23.453 ;
     RECT  212.256 23.405 213.354 23.453 ;
     RECT  137.415 23.279 141.894 23.501 ;
     RECT  2.415 2.413 2.697 23.507 ;
     RECT  24.015 20.381 24.297 23.507 ;
     RECT  29.415 2.413 29.697 23.507 ;
     RECT  34.815 17.888 35.097 23.507 ;
     RECT  40.215 18.797 40.497 23.507 ;
     RECT  45.615 20.573 45.897 23.507 ;
     RECT  56.415 20.957 56.697 23.507 ;
     RECT  61.815 21.299 62.097 23.507 ;
     RECT  67.215 17.069 67.497 23.507 ;
     RECT  72.615 20.687 72.897 23.507 ;
     RECT  78.015 20.048 78.297 23.507 ;
     RECT  94.215 17.069 94.497 23.507 ;
     RECT  99.615 17.075 99.897 23.507 ;
     RECT  105.015 23.423 105.297 23.507 ;
     RECT  108.54 21.839 110.697 23.507 ;
     RECT  115.164 22.783 116.097 23.507 ;
     RECT  121.215 22.073 121.497 23.507 ;
     RECT  137.415 23.501 141.714 23.507 ;
     RECT  142.815 23.279 143.097 23.507 ;
     RECT  148.215 19.277 148.497 23.507 ;
     RECT  153.615 21.677 153.897 23.507 ;
     RECT  159.015 19.277 159.297 23.507 ;
     RECT  164.415 21.677 164.697 23.507 ;
     RECT  175.215 23.081 175.497 23.507 ;
     RECT  186.015 21.677 186.297 23.507 ;
     RECT  191.415 19.277 191.697 23.507 ;
     RECT  196.815 21.677 197.097 23.507 ;
     RECT  202.215 19.229 202.497 23.507 ;
     RECT  223.815 23.279 227.97 23.507 ;
     RECT  229.215 19.229 229.497 23.507 ;
     RECT  234.615 2.413 234.897 23.507 ;
     RECT  7.488 23.453 21.15 23.549 ;
     RECT  48.528 23.287 53.406 23.549 ;
     RECT  80.964 23.351 92.106 23.549 ;
     RECT  108.54 23.507 110.505 23.549 ;
     RECT  122.508 23.351 129.798 23.549 ;
     RECT  132.015 23.279 135.954 23.549 ;
     RECT  138.312 23.507 141.714 23.549 ;
     RECT  176.868 23.405 183.834 23.549 ;
     RECT  205.632 23.351 209.394 23.549 ;
     RECT  217.944 23.279 221.922 23.549 ;
     RECT  224.748 23.507 227.97 23.549 ;
     RECT  80.964 23.549 88.074 23.597 ;
     RECT  122.508 23.549 129.69 23.597 ;
     RECT  138.312 23.549 141.426 23.597 ;
     RECT  88.815 23.549 91.746 23.621 ;
     RECT  169.815 23.405 170.514 23.621 ;
     RECT  122.508 23.597 124.254 23.645 ;
     RECT  128.268 23.597 129.69 23.645 ;
     RECT  132.015 23.549 135.522 23.645 ;
     RECT  171.252 23.405 174.474 23.645 ;
     RECT  108.648 23.549 110.505 23.657 ;
     RECT  171.252 23.645 171.342 23.657 ;
     RECT  172.08 23.645 174.474 23.657 ;
     RECT  7.488 23.549 21.042 23.665 ;
     RECT  212.4 23.453 213.354 23.665 ;
     RECT  108.648 23.657 109.386 23.693 ;
     RECT  129.6 23.645 129.69 23.693 ;
     RECT  109.368 23.693 109.386 23.729 ;
     RECT  172.08 23.657 174.078 23.729 ;
     RECT  7.38 23.665 21.042 23.741 ;
     RECT  48.528 23.549 52.578 23.741 ;
     RECT  80.964 23.597 87.21 23.741 ;
     RECT  88.056 23.597 88.074 23.741 ;
     RECT  89.892 23.621 91.746 23.741 ;
     RECT  172.08 23.729 173.538 23.741 ;
     RECT  176.868 23.549 183.546 23.741 ;
     RECT  205.632 23.549 208.71 23.741 ;
     RECT  212.4 23.665 213.606 23.741 ;
     RECT  224.892 23.549 227.862 23.741 ;
     RECT  2.415 23.507 2.505 23.777 ;
     RECT  18 23.741 19.134 23.777 ;
     RECT  24.015 23.507 24.105 23.777 ;
     RECT  29.415 23.507 29.505 23.777 ;
     RECT  34.815 23.507 34.905 23.777 ;
     RECT  40.215 23.507 40.305 23.777 ;
     RECT  45.615 23.507 45.705 23.777 ;
     RECT  48.528 23.741 51.714 23.777 ;
     RECT  56.415 23.507 56.505 23.777 ;
     RECT  61.815 23.507 61.905 23.777 ;
     RECT  67.215 23.507 67.305 23.777 ;
     RECT  72.615 23.507 72.705 23.777 ;
     RECT  78.015 23.507 78.105 23.777 ;
     RECT  80.964 23.741 84.51 23.777 ;
     RECT  88.815 23.621 88.905 23.777 ;
     RECT  94.215 23.507 94.305 23.777 ;
     RECT  99.615 23.507 99.705 23.777 ;
     RECT  105.015 23.507 105.105 23.777 ;
     RECT  110.415 23.657 110.505 23.777 ;
     RECT  115.164 23.507 115.905 23.777 ;
     RECT  121.215 23.507 121.305 23.777 ;
     RECT  132.015 23.645 134.802 23.777 ;
     RECT  137.415 23.507 137.505 23.777 ;
     RECT  142.815 23.507 142.905 23.777 ;
     RECT  148.215 23.507 148.305 23.777 ;
     RECT  153.615 23.507 153.705 23.777 ;
     RECT  159.015 23.507 159.105 23.777 ;
     RECT  164.415 23.507 164.505 23.777 ;
     RECT  169.815 23.621 169.905 23.777 ;
     RECT  175.215 23.507 175.305 23.777 ;
     RECT  177.696 23.741 183.474 23.777 ;
     RECT  186.015 23.507 186.105 23.777 ;
     RECT  191.415 23.507 191.505 23.777 ;
     RECT  196.815 23.507 196.905 23.777 ;
     RECT  202.215 23.507 202.305 23.777 ;
     RECT  205.632 23.741 208.602 23.777 ;
     RECT  213.015 23.741 213.174 23.777 ;
     RECT  223.815 23.507 223.905 23.777 ;
     RECT  229.215 23.507 229.305 23.777 ;
     RECT  234.615 23.507 234.705 23.777 ;
     RECT  115.164 23.777 115.182 23.819 ;
     RECT  217.944 23.549 221.598 23.819 ;
     RECT  130.608 23.593 130.626 23.855 ;
     RECT  132.156 23.777 134.802 23.855 ;
     RECT  125.244 23.597 127.314 23.891 ;
     RECT  129.672 23.693 129.69 23.891 ;
     RECT  132.156 23.855 134.73 23.891 ;
     RECT  140.76 23.597 141.426 23.891 ;
     RECT  177.696 23.777 179.91 23.933 ;
     RECT  205.632 23.777 207.09 23.933 ;
     RECT  208.044 23.777 208.602 23.933 ;
     RECT  11.772 23.741 12.006 23.981 ;
     RECT  15.444 23.741 16.398 23.981 ;
     RECT  19.116 23.777 19.134 23.981 ;
     RECT  80.964 23.777 82.71 23.981 ;
     RECT  90 23.741 90.018 23.981 ;
     RECT  128.844 23.645 128.862 23.981 ;
     RECT  140.76 23.891 141.39 23.981 ;
     RECT  176.868 23.741 176.886 23.981 ;
     RECT  204.516 22.739 204.534 23.981 ;
     RECT  218.124 23.819 221.598 23.981 ;
     RECT  11.988 23.981 12.006 24.029 ;
     RECT  181.152 23.777 183.474 24.029 ;
     RECT  205.632 23.933 206.334 24.029 ;
     RECT  7.74 23.741 9.054 24.557 ;
     RECT  13.104 23.741 14.67 24.557 ;
     RECT  20.988 23.741 21.006 24.557 ;
     RECT  48.528 23.777 50.49 24.557 ;
     RECT  51.372 23.777 51.714 24.557 ;
     RECT  80.964 23.981 82.062 24.557 ;
     RECT  83.736 23.777 84.51 24.557 ;
     RECT  122.508 23.645 123.39 24.557 ;
     RECT  125.244 23.891 125.442 24.557 ;
     RECT  127.08 23.891 127.314 24.557 ;
     RECT  132.156 23.891 133.866 24.557 ;
     RECT  140.76 23.981 141.174 24.557 ;
     RECT  172.08 23.741 173.322 24.557 ;
     RECT  177.696 23.933 177.714 24.557 ;
     RECT  178.704 23.933 179.91 24.557 ;
     RECT  181.152 24.029 181.17 24.557 ;
     RECT  182.16 24.029 183.474 24.557 ;
     RECT  208.584 23.933 208.602 24.557 ;
     RECT  213.156 23.777 213.174 24.557 ;
     RECT  218.736 23.981 221.598 24.557 ;
     RECT  225 23.741 226.854 24.557 ;
     RECT  8.388 24.557 9.054 24.605 ;
     RECT  13.68 24.557 14.67 24.605 ;
     RECT  81.18 24.557 82.062 24.605 ;
     RECT  122.652 24.557 122.67 24.605 ;
     RECT  127.152 24.557 127.314 24.605 ;
     RECT  81.432 24.605 82.062 24.653 ;
     RECT  127.296 24.605 127.314 24.653 ;
     RECT  138.312 23.597 139.986 24.653 ;
     RECT  206.316 24.029 206.334 25.085 ;
     RECT  10.008 23.741 10.026 25.133 ;
     RECT  13.968 24.605 14.67 25.133 ;
     RECT  15.444 23.981 15.462 25.133 ;
     RECT  16.38 23.981 16.398 25.133 ;
     RECT  18 23.777 18.018 25.133 ;
     RECT  48.636 24.557 50.49 25.133 ;
     RECT  51.696 24.557 51.714 25.133 ;
     RECT  82.044 24.653 82.062 25.133 ;
     RECT  84.06 24.557 84.078 25.133 ;
     RECT  85.392 23.741 85.95 25.133 ;
     RECT  91.116 23.741 91.134 25.133 ;
     RECT  124.236 23.645 124.254 25.133 ;
     RECT  125.244 24.557 125.262 25.133 ;
     RECT  132.732 24.557 133.866 25.133 ;
     RECT  134.712 23.891 134.73 25.133 ;
     RECT  138.312 24.653 138.726 25.133 ;
     RECT  139.608 24.653 139.986 25.133 ;
     RECT  140.76 24.557 140.778 25.133 ;
     RECT  172.08 24.557 172.566 25.133 ;
     RECT  178.704 24.557 179.37 25.133 ;
     RECT  182.16 24.557 182.898 25.133 ;
     RECT  218.736 24.557 219.114 25.133 ;
     RECT  219.852 24.557 220.482 25.133 ;
     RECT  221.58 24.557 221.598 25.133 ;
     RECT  225.72 24.557 225.738 25.133 ;
     RECT  226.836 24.557 226.854 25.133 ;
     RECT  48.852 25.133 48.87 25.181 ;
     RECT  138.708 25.133 138.726 25.181 ;
     RECT  219.096 25.133 219.114 25.181 ;
     RECT  85.428 25.133 85.446 25.805 ;
     RECT  87.3 25.675 87.318 25.805 ;
     RECT  125.748 25.675 125.766 25.805 ;
     RECT  129.168 25.675 129.186 25.805 ;
     RECT  140.256 25.675 140.562 25.805 ;
     RECT  177.984 25.675 178.29 25.805 ;
     RECT  179.424 25.675 179.442 25.805 ;
     RECT  221.22 25.675 221.238 25.805 ;
    LAYER M4 ;
     RECT  2.408 2.148 2.512 23.772 ;
     RECT  2.512 2.418 2.704 23.502 ;
     RECT  7.333 23.712 7.429 23.736 ;
     RECT  7.429 23.424 7.525 23.736 ;
     RECT  7.525 23.376 7.621 23.736 ;
     RECT  7.621 23.376 7.729 23.88 ;
     RECT  7.729 23.376 7.808 24.552 ;
     RECT  7.808 2.148 7.912 24.552 ;
     RECT  7.912 2.418 8.104 24.552 ;
     RECT  8.104 23.376 8.377 24.552 ;
     RECT  8.377 23.376 9.299 24.6 ;
     RECT  9.565 18.672 10.109 18.696 ;
     RECT  9.997 25.104 10.355 25.128 ;
     RECT  9.299 23.376 10.897 23.736 ;
     RECT  10.897 22.608 11.009 23.736 ;
     RECT  9.097 20.352 11.221 20.376 ;
     RECT  11.221 18.768 11.509 18.792 ;
     RECT  11.509 18.528 11.581 18.792 ;
     RECT  11.581 18.24 11.761 18.792 ;
     RECT  11.009 23.376 11.761 23.736 ;
     RECT  11.761 23.376 11.977 23.976 ;
     RECT  11.761 17.568 12.233 18.792 ;
     RECT  11.221 20.352 12.565 21.048 ;
     RECT  12.233 18.24 13.021 18.792 ;
     RECT  11.977 23.376 13.093 24.024 ;
     RECT  10.861 16.368 13.208 16.392 ;
     RECT  13.021 18.24 13.208 18.84 ;
     RECT  12.565 20.352 13.208 21.144 ;
     RECT  13.093 23.376 13.208 24.552 ;
     RECT  13.208 2.148 13.312 24.552 ;
     RECT  13.312 2.418 13.504 24.552 ;
     RECT  13.504 16.368 13.619 21.144 ;
     RECT  13.504 22.512 13.669 24.552 ;
     RECT  13.669 22.512 13.781 24.6 ;
     RECT  13.619 16.368 13.907 19.368 ;
     RECT  13.781 23.376 13.957 24.6 ;
     RECT  13.957 23.376 14.099 25.128 ;
     RECT  13.619 20.352 14.821 21.144 ;
     RECT  13.907 16.512 14.893 19.368 ;
     RECT  14.821 20.352 14.893 21.24 ;
     RECT  14.893 16.512 14.969 21.24 ;
     RECT  14.969 16.512 15.181 16.536 ;
     RECT  15.181 16.224 15.221 16.536 ;
     RECT  14.969 18.048 15.509 21.24 ;
     RECT  14.099 23.376 15.757 23.736 ;
     RECT  15.757 23.376 16.019 23.976 ;
     RECT  15.221 16.224 16.297 16.248 ;
     RECT  15.509 18.768 16.501 21.24 ;
     RECT  16.501 17.952 16.513 21.24 ;
     RECT  16.513 17.952 16.547 21.672 ;
     RECT  14.099 25.104 16.595 25.128 ;
     RECT  16.019 23.376 16.981 23.736 ;
     RECT  16.547 19.296 17.66 21.672 ;
     RECT  16.981 22.704 17.66 23.736 ;
     RECT  16.547 17.952 17.701 18.024 ;
     RECT  17.66 19.296 17.701 23.736 ;
     RECT  17.989 25.104 18.323 25.128 ;
     RECT  16.297 16.224 18.385 16.824 ;
     RECT  17.701 17.952 18.385 23.736 ;
     RECT  18.385 16.224 18.493 23.736 ;
     RECT  18.493 15.984 18.608 23.736 ;
     RECT  18.608 2.148 18.712 23.772 ;
     RECT  18.712 2.418 18.904 23.772 ;
     RECT  18.904 23.376 19.105 23.772 ;
     RECT  18.904 15.984 19.505 19.272 ;
     RECT  19.105 23.376 19.619 23.976 ;
     RECT  18.904 21.12 19.897 21.576 ;
     RECT  19.897 20.544 19.948 21.576 ;
     RECT  19.505 15.984 20.369 18.744 ;
     RECT  19.619 23.376 20.977 23.736 ;
     RECT  20.977 23.376 21.053 24.552 ;
     RECT  21.053 23.376 21.089 23.496 ;
     RECT  21.053 24.528 21.251 24.552 ;
     RECT  19.948 20.544 21.305 21.144 ;
     RECT  21.089 23.376 21.539 23.448 ;
     RECT  21.305 20.592 21.635 21.144 ;
     RECT  20.369 15.984 21.665 18.504 ;
     RECT  21.539 23.376 21.676 23.4 ;
     RECT  21.665 16.032 24.008 18.504 ;
     RECT  21.635 20.592 24.008 20.616 ;
     RECT  24.008 2.148 24.112 23.772 ;
     RECT  24.112 2.418 24.304 23.502 ;
     RECT  24.304 17.616 25.837 18.504 ;
     RECT  25.837 17.568 26.057 18.504 ;
     RECT  24.304 16.032 29.408 16.392 ;
     RECT  26.057 17.616 29.408 18.504 ;
     RECT  24.304 20.592 29.408 20.616 ;
     RECT  29.408 2.148 29.512 23.772 ;
     RECT  29.512 2.418 29.704 23.502 ;
     RECT  29.704 16.032 33.253 16.392 ;
     RECT  29.704 17.616 33.253 18.504 ;
     RECT  33.253 16.032 34.808 18.504 ;
     RECT  29.704 20.592 34.808 20.616 ;
     RECT  34.808 2.148 34.912 23.772 ;
     RECT  34.912 2.418 35.104 23.502 ;
     RECT  39.733 7.392 40.208 7.416 ;
     RECT  40.093 10.608 40.208 10.632 ;
     RECT  35.104 16.032 40.208 18.504 ;
     RECT  35.104 20.592 40.208 20.616 ;
     RECT  40.208 2.148 40.312 23.772 ;
     RECT  40.312 2.418 40.504 23.502 ;
     RECT  40.504 10.608 42.829 10.632 ;
     RECT  40.504 20.592 42.997 20.616 ;
     RECT  40.504 16.032 43.117 18.504 ;
     RECT  42.997 19.968 43.949 20.616 ;
     RECT  43.117 15.984 44.597 18.504 ;
     RECT  43.949 19.968 44.989 20.568 ;
     RECT  40.504 7.392 45.493 7.416 ;
     RECT  45.493 7.392 45.608 7.944 ;
     RECT  42.829 10.608 45.608 11.256 ;
     RECT  45.397 15.024 45.608 15.048 ;
     RECT  44.597 16.272 45.608 18.504 ;
     RECT  44.989 19.776 45.608 20.568 ;
     RECT  45.608 2.148 45.712 23.772 ;
     RECT  45.712 2.418 45.904 23.502 ;
     RECT  45.904 10.608 46.204 11.976 ;
     RECT  46.204 11.952 47.333 11.976 ;
     RECT  46.204 10.608 48.131 10.632 ;
     RECT  48.085 12.528 48.169 12.552 ;
     RECT  48.517 24.528 48.625 24.552 ;
     RECT  48.085 9.552 48.805 9.576 ;
     RECT  48.625 24.528 48.841 25.128 ;
     RECT  48.517 11.376 48.997 11.4 ;
     RECT  45.904 19.776 49.093 19.8 ;
     RECT  45.904 7.92 49.196 7.944 ;
     RECT  48.841 24.528 49.235 25.176 ;
     RECT  49.196 7.392 49.237 7.944 ;
     RECT  48.805 8.928 49.237 9.576 ;
     RECT  48.997 11.376 49.241 12.216 ;
     RECT  49.237 7.392 49.283 9.576 ;
     RECT  49.057 23.376 49.309 23.4 ;
     RECT  49.093 19.776 49.313 20.328 ;
     RECT  49.241 11.376 49.345 11.736 ;
     RECT  45.904 16.272 49.561 18.504 ;
     RECT  49.561 15.984 49.741 18.504 ;
     RECT  49.235 24.528 49.811 25.128 ;
     RECT  49.741 15.168 49.929 18.504 ;
     RECT  49.313 19.776 49.929 19.8 ;
     RECT  49.309 23.376 50.281 23.448 ;
     RECT  49.929 15.168 50.857 19.8 ;
     RECT  49.283 8.448 50.869 8.472 ;
     RECT  50.857 15.168 50.965 20.616 ;
     RECT  49.345 11.328 51.001 11.736 ;
     RECT  50.869 7.728 51.008 8.472 ;
     RECT  49.283 9.552 51.008 9.576 ;
     RECT  51.001 10.608 51.008 11.736 ;
     RECT  50.965 15.168 51.008 20.712 ;
     RECT  50.281 23.376 51.008 23.544 ;
     RECT  51.008 2.148 51.112 23.772 ;
     RECT  51.112 2.418 51.304 23.772 ;
     RECT  51.304 23.376 51.361 23.772 ;
     RECT  49.811 25.104 51.361 25.128 ;
     RECT  51.304 15.84 51.437 19.368 ;
     RECT  51.304 13.632 51.443 13.656 ;
     RECT  51.437 15.84 51.545 18.792 ;
     RECT  51.304 14.784 51.964 14.808 ;
     RECT  51.361 23.376 52.019 25.128 ;
     RECT  52.019 23.376 52.115 24.552 ;
     RECT  51.304 20.592 52.193 20.856 ;
     RECT  51.304 7.728 52.369 7.752 ;
     RECT  52.193 20.736 52.409 20.856 ;
     RECT  52.115 23.376 52.589 23.736 ;
     RECT  51.545 15.936 52.877 18.792 ;
     RECT  52.589 23.376 52.985 23.496 ;
     RECT  52.985 23.376 53.021 23.4 ;
     RECT  52.877 15.936 53.077 16.392 ;
     RECT  52.409 20.736 53.161 20.76 ;
     RECT  51.304 10.608 53.237 12.504 ;
     RECT  53.161 20.304 53.273 20.76 ;
     RECT  52.369 7.728 53.449 8.472 ;
     RECT  51.304 9.552 53.449 9.576 ;
     RECT  52.877 17.568 53.773 18.792 ;
     RECT  53.273 20.304 53.773 20.328 ;
     RECT  53.773 17.568 54.065 20.328 ;
     RECT  53.449 7.728 54.137 9.576 ;
     RECT  53.237 10.608 54.277 10.632 ;
     RECT  53.237 11.712 54.277 12.504 ;
     RECT  54.065 18.48 54.317 20.328 ;
     RECT  54.317 18.48 54.785 19.656 ;
     RECT  54.277 10.608 54.961 12.504 ;
     RECT  54.137 7.968 55.037 9.576 ;
     RECT  54.785 19.536 55.037 19.656 ;
     RECT  54.961 10.608 56.329 12.552 ;
     RECT  55.037 7.968 56.408 8.568 ;
     RECT  55.037 9.552 56.408 9.576 ;
     RECT  56.329 10.608 56.408 12.888 ;
     RECT  53.077 15.504 56.408 16.392 ;
     RECT  54.785 18.48 56.408 18.552 ;
     RECT  55.037 19.632 56.408 19.656 ;
     RECT  56.408 2.148 56.512 23.772 ;
     RECT  56.512 2.418 56.704 23.502 ;
     RECT  56.704 18.48 57.017 19.656 ;
     RECT  56.704 15.36 57.089 16.392 ;
     RECT  56.704 7.632 57.809 13.08 ;
     RECT  57.017 18.48 57.881 18.552 ;
     RECT  57.809 7.632 58.093 12.888 ;
     RECT  58.093 7.488 58.453 12.888 ;
     RECT  58.453 7.248 58.493 12.888 ;
     RECT  57.089 15.36 58.669 15.384 ;
     RECT  58.493 7.248 58.705 12.84 ;
     RECT  58.669 14.928 58.709 15.384 ;
     RECT  58.705 6.288 58.745 12.84 ;
     RECT  57.881 18.528 59.077 18.552 ;
     RECT  57.017 19.632 59.077 19.656 ;
     RECT  58.745 7.344 59.141 12.84 ;
     RECT  59.077 18.528 59.141 19.656 ;
     RECT  58.709 14.928 59.845 15.336 ;
     RECT  57.089 16.368 59.845 16.392 ;
     RECT  59.845 14.928 59.891 16.392 ;
     RECT  58.745 6.288 59.929 6.312 ;
     RECT  59.141 7.344 59.929 12.504 ;
     RECT  59.891 15.312 59.933 16.392 ;
     RECT  60.037 2.928 60.085 2.952 ;
     RECT  60.085 2.88 60.323 2.952 ;
     RECT  59.929 1.728 60.361 1.752 ;
     RECT  60.361 1.2 60.469 1.752 ;
     RECT  59.929 6.288 60.477 12.504 ;
     RECT  60.477 6.288 60.541 12.552 ;
     RECT  60.469 1.152 60.649 1.752 ;
     RECT  60.649 1.152 60.661 1.8 ;
     RECT  60.661 0.192 60.761 1.8 ;
     RECT  60.761 1.152 60.865 1.8 ;
     RECT  59.141 19.104 60.997 19.656 ;
     RECT  60.541 6.288 61.009 12.792 ;
     RECT  60.865 1.152 61.045 1.848 ;
     RECT  61.045 1.152 61.265 2.328 ;
     RECT  61.265 1.728 61.405 2.328 ;
     RECT  61.405 1.728 61.808 2.424 ;
     RECT  61.621 4.656 61.808 4.68 ;
     RECT  61.009 6.288 61.808 13.08 ;
     RECT  59.933 15.312 61.808 15.336 ;
     RECT  59.933 16.368 61.808 16.392 ;
     RECT  60.997 19.104 61.808 19.848 ;
     RECT  61.808 1.728 61.912 23.772 ;
     RECT  61.912 1.728 62.104 23.502 ;
     RECT  62.104 1.728 62.413 1.8 ;
     RECT  62.413 1.68 62.705 1.8 ;
     RECT  62.677 0.288 62.737 0.312 ;
     RECT  62.737 0.288 62.773 0.6 ;
     RECT  62.773 0.192 62.915 0.6 ;
     RECT  62.705 1.68 63.157 1.752 ;
     RECT  62.104 6.288 63.445 12.552 ;
     RECT  63.445 5.712 63.457 12.552 ;
     RECT  62.915 0.192 63.613 0.216 ;
     RECT  63.457 5.712 63.685 12.744 ;
     RECT  63.157 1.2 63.733 1.752 ;
     RECT  63.685 6.288 63.749 12.744 ;
     RECT  63.733 1.2 63.925 2.184 ;
     RECT  63.925 1.152 64.021 2.184 ;
     RECT  64.021 1.152 64.181 2.328 ;
     RECT  64.105 3.408 64.189 3.432 ;
     RECT  64.105 4.512 64.211 4.536 ;
     RECT  63.749 6.288 64.259 12.504 ;
     RECT  64.181 1.728 64.961 2.328 ;
     RECT  64.844 0.528 65.141 0.552 ;
     RECT  65.141 0.192 65.225 0.552 ;
     RECT  64.673 3.984 65.441 4.008 ;
     RECT  64.309 5.136 65.585 5.16 ;
     RECT  64.961 1.728 65.797 2.376 ;
     RECT  65.797 1.728 66.053 2.904 ;
     RECT  65.653 0.576 66.125 0.6 ;
     RECT  64.259 6.336 66.179 12.504 ;
     RECT  66.179 6.336 66.421 12.264 ;
     RECT  66.053 2.88 66.476 2.904 ;
     RECT  66.229 4.032 66.476 4.056 ;
     RECT  66.476 2.88 66.589 4.056 ;
     RECT  66.053 1.728 66.665 1.8 ;
     RECT  66.648 0.192 66.845 0.312 ;
     RECT  66.589 2.88 67.208 4.248 ;
     RECT  66.421 5.712 67.208 12.264 ;
     RECT  62.104 16.368 67.208 16.392 ;
     RECT  62.104 19.824 67.208 19.848 ;
     RECT  67.208 2.148 67.312 23.772 ;
     RECT  67.312 2.148 67.504 23.502 ;
     RECT  67.504 6.336 67.529 12.264 ;
     RECT  67.529 6.336 67.565 9.912 ;
     RECT  66.845 0.192 67.82 0.216 ;
     RECT  67.82 0.192 67.907 0.552 ;
     RECT  67.565 6.336 68.429 9.528 ;
     RECT  68.605 4.56 68.689 5.16 ;
     RECT  67.907 0.192 68.717 0.216 ;
     RECT  68.689 4.704 68.717 5.16 ;
     RECT  67.733 1.728 68.885 1.848 ;
     RECT  68.717 4.704 68.897 4.728 ;
     RECT  68.885 1.728 69.109 1.896 ;
     RECT  68.429 8.688 69.109 9.528 ;
     RECT  69.109 1.728 69.205 2.28 ;
     RECT  68.429 6.336 69.301 7.704 ;
     RECT  69.389 3.408 69.461 3.432 ;
     RECT  69.301 5.712 69.469 7.704 ;
     RECT  69.109 8.688 69.469 9.672 ;
     RECT  69.461 3.408 69.545 3.48 ;
     RECT  69.469 5.712 69.545 9.672 ;
     RECT  67.529 11.376 69.757 12.264 ;
     RECT  69.205 1.728 69.781 2.328 ;
     RECT  69.545 3.408 69.781 3.432 ;
     RECT  69.781 1.728 70.013 3.432 ;
     RECT  67.504 16.368 70.013 16.392 ;
     RECT  69.545 6.336 70.081 9.672 ;
     RECT  69.757 11.232 70.081 12.264 ;
     RECT  70.081 6.336 70.405 12.264 ;
     RECT  70.325 0.192 70.409 0.216 ;
     RECT  70.225 4.704 70.481 4.728 ;
     RECT  70.013 1.728 70.517 2.376 ;
     RECT  70.405 6.336 70.691 12.552 ;
     RECT  70.517 1.728 70.741 2.328 ;
     RECT  70.549 4.416 70.769 4.44 ;
     RECT  70.013 3.408 71.125 3.432 ;
     RECT  70.741 1.104 71.129 2.328 ;
     RECT  70.691 9.648 71.413 12.552 ;
     RECT  71.413 9.648 71.489 12.792 ;
     RECT  71.129 1.728 71.497 2.328 ;
     RECT  71.489 10.848 71.497 12.792 ;
     RECT  71.497 11.232 71.557 12.792 ;
     RECT  71.516 14.352 71.557 14.376 ;
     RECT  71.489 9.648 71.561 9.672 ;
     RECT  71.449 0.528 71.651 0.552 ;
     RECT  71.497 1.776 71.777 2.328 ;
     RECT  71.777 1.872 71.813 2.328 ;
     RECT  71.797 0.288 71.873 0.36 ;
     RECT  71.873 0.192 72.083 0.36 ;
     RECT  72.083 0.192 72.173 0.264 ;
     RECT  71.813 2.148 72.181 2.328 ;
     RECT  71.125 3.408 72.181 4.008 ;
     RECT  72.181 2.148 72.188 4.008 ;
     RECT  71.557 11.232 72.241 14.376 ;
     RECT  72.173 0.192 72.46 0.216 ;
     RECT  72.188 2.148 72.608 4.296 ;
     RECT  70.691 6.336 72.608 8.52 ;
     RECT  71.701 9.504 72.608 9.528 ;
     RECT  72.241 11.232 72.608 14.76 ;
     RECT  70.873 16.416 72.608 16.44 ;
     RECT  67.504 19.824 72.608 19.848 ;
     RECT  72.608 2.148 72.712 23.772 ;
     RECT  72.712 2.148 72.904 23.502 ;
     RECT  72.904 2.832 72.929 3.048 ;
     RECT  72.904 10.848 73.253 13.656 ;
     RECT  72.904 9.504 73.289 9.528 ;
     RECT  72.904 14.736 73.289 15.72 ;
     RECT  72.929 2.832 73.331 2.856 ;
     RECT  73.189 1.728 73.381 1.8 ;
     RECT  73.253 11.376 73.505 13.656 ;
     RECT  73.381 1.152 73.609 1.8 ;
     RECT  73.609 1.104 73.765 1.8 ;
     RECT  72.904 8.496 73.937 8.52 ;
     RECT  73.289 15.696 74.005 15.72 ;
     RECT  73.765 0.192 74.204 1.8 ;
     RECT  73.897 18.144 74.245 18.168 ;
     RECT  74.245 18.144 74.332 18.792 ;
     RECT  74.149 8.976 74.581 9 ;
     RECT  74.005 15.696 74.693 16.68 ;
     RECT  74.204 0.192 74.725 2.28 ;
     RECT  73.505 11.376 74.941 13.56 ;
     RECT  74.941 10.848 74.945 13.56 ;
     RECT  74.945 11.952 74.965 13.56 ;
     RECT  74.581 8.976 74.977 9.816 ;
     RECT  74.945 10.848 74.977 10.872 ;
     RECT  74.725 0.192 75.059 2.328 ;
     RECT  74.977 8.976 75.089 10.872 ;
     RECT  72.904 6.336 75.121 7.368 ;
     RECT  75.089 8.976 75.121 10.728 ;
     RECT  74.965 11.952 75.169 14.376 ;
     RECT  74.693 15.696 75.233 16.584 ;
     RECT  75.059 1.728 75.251 2.328 ;
     RECT  75.233 15.696 75.337 15.816 ;
     RECT  72.904 19.824 75.409 19.848 ;
     RECT  75.121 6.336 75.443 10.728 ;
     RECT  75.337 14.832 75.449 15.816 ;
     RECT  75.409 19.344 75.449 19.848 ;
     RECT  75.169 11.952 75.484 13.848 ;
     RECT  75.473 2.88 75.685 2.904 ;
     RECT  72.904 4.56 75.737 4.584 ;
     RECT  75.685 2.88 75.769 3.432 ;
     RECT  75.484 11.952 75.817 13.704 ;
     RECT  75.769 2.88 75.853 4.008 ;
     RECT  75.443 6.336 75.917 8.328 ;
     RECT  75.443 9.696 76.025 10.728 ;
     RECT  75.917 6.336 76.261 7.464 ;
     RECT  76.261 5.712 76.349 7.464 ;
     RECT  75.251 1.728 76.357 1.752 ;
     RECT  75.853 2.88 76.457 3.144 ;
     RECT  76.357 1.728 76.837 1.8 ;
     RECT  75.059 0.192 76.933 0.216 ;
     RECT  76.025 10.176 76.961 10.728 ;
     RECT  76.417 9.12 77.173 9.144 ;
     RECT  76.961 10.176 77.173 10.68 ;
     RECT  76.933 0.192 77.276 0.552 ;
     RECT  76.837 1.728 77.276 2.616 ;
     RECT  77.276 0.192 77.363 2.616 ;
     RECT  77.363 0.192 77.537 0.6 ;
     RECT  77.363 1.728 77.597 2.616 ;
     RECT  75.449 15.792 77.677 15.816 ;
     RECT  74.332 18.144 77.677 18.168 ;
     RECT  75.449 19.344 77.677 19.368 ;
     RECT  77.537 0.576 77.753 0.6 ;
     RECT  77.173 9.12 77.756 10.68 ;
     RECT  76.349 6.336 77.797 7.464 ;
     RECT  77.756 8.688 77.797 10.68 ;
     RECT  77.597 1.728 78.008 2.904 ;
     RECT  77.797 6.336 78.008 10.68 ;
     RECT  75.817 11.952 78.008 13.656 ;
     RECT  77.677 15.744 78.008 15.816 ;
     RECT  77.677 18.144 78.008 19.368 ;
     RECT  78.008 1.728 78.112 23.772 ;
     RECT  78.112 1.728 78.304 23.502 ;
     RECT  78.304 11.952 78.689 13.656 ;
     RECT  78.304 9.072 78.725 10.68 ;
     RECT  78.649 0.528 78.853 0.552 ;
     RECT  78.304 17.664 78.869 20.04 ;
     RECT  78.304 6.336 79.297 6.936 ;
     RECT  78.304 7.92 79.297 7.944 ;
     RECT  79.297 6.336 79.333 7.944 ;
     RECT  79.333 5.52 79.429 7.944 ;
     RECT  79.429 5.184 79.475 7.944 ;
     RECT  78.304 15.744 79.477 15.816 ;
     RECT  79.475 5.184 79.517 5.208 ;
     RECT  78.853 0.192 79.525 0.552 ;
     RECT  78.725 10.224 79.621 10.68 ;
     RECT  79.477 15.408 79.628 15.816 ;
     RECT  78.869 17.664 79.669 17.688 ;
     RECT  78.304 1.728 79.685 1.8 ;
     RECT  79.685 1.728 79.693 2.664 ;
     RECT  79.657 5.136 79.769 5.16 ;
     RECT  79.669 17.088 79.877 17.688 ;
     RECT  78.689 11.952 80.053 13.512 ;
     RECT  79.628 15.408 80.053 15.864 ;
     RECT  79.693 1.632 80.125 2.664 ;
     RECT  80.125 1.632 80.197 2.952 ;
     RECT  80.053 14.832 80.233 15.864 ;
     RECT  79.877 17.088 80.233 17.496 ;
     RECT  79.621 10.224 80.269 10.92 ;
     RECT  80.053 11.952 80.269 13.656 ;
     RECT  80.197 1.632 80.281 3.432 ;
     RECT  80.269 10.224 80.309 13.656 ;
     RECT  80.233 14.832 80.377 17.496 ;
     RECT  80.281 1.632 80.381 2.952 ;
     RECT  79.525 0.192 80.54 0.6 ;
     RECT  80.381 1.632 80.54 2.376 ;
     RECT  80.54 0.192 80.569 2.376 ;
     RECT  80.569 0.192 80.627 2.328 ;
     RECT  80.377 14.784 80.633 17.496 ;
     RECT  78.869 18.72 80.669 20.04 ;
     RECT  80.309 12.24 80.677 13.656 ;
     RECT  80.677 12.24 80.764 14.232 ;
     RECT  79.475 6.336 80.881 7.944 ;
     RECT  80.627 1.632 80.915 2.328 ;
     RECT  80.809 3.936 80.963 3.96 ;
     RECT  80.821 5.136 80.963 5.16 ;
     RECT  78.725 9.072 81.133 9.096 ;
     RECT  80.309 10.224 81.133 11.16 ;
     RECT  80.953 24.528 81.169 24.552 ;
     RECT  81.133 9.072 81.173 11.16 ;
     RECT  81.061 4.56 81.245 4.584 ;
     RECT  81.133 23.376 81.308 23.4 ;
     RECT  81.169 24.528 81.308 24.6 ;
     RECT  81.173 9.36 81.349 11.16 ;
     RECT  80.764 12.24 81.349 14.136 ;
     RECT  80.627 0.192 81.353 0.216 ;
     RECT  80.633 15.408 81.356 17.496 ;
     RECT  80.669 18.72 81.356 18.84 ;
     RECT  81.308 23.376 81.395 24.6 ;
     RECT  81.395 24.528 81.421 24.6 ;
     RECT  81.356 15.408 81.733 18.84 ;
     RECT  80.669 19.968 81.733 20.04 ;
     RECT  81.733 15.408 81.779 20.04 ;
     RECT  81.421 24.528 81.971 24.648 ;
     RECT  80.915 1.728 82.001 2.328 ;
     RECT  81.349 9.36 82.037 14.136 ;
     RECT  82.033 25.104 82.259 25.128 ;
     RECT  80.881 6.336 82.289 8.04 ;
     RECT  81.779 15.408 82.361 17.4 ;
     RECT  82.117 2.88 82.393 2.904 ;
     RECT  81.395 23.376 82.405 23.544 ;
     RECT  82.037 9.36 82.573 11.256 ;
     RECT  82.393 2.88 82.645 3.24 ;
     RECT  82.405 23.376 82.739 23.976 ;
     RECT  81.829 0.576 82.789 0.6 ;
     RECT  81.779 18.672 82.861 20.04 ;
     RECT  82.789 0.192 82.901 0.6 ;
     RECT  82.901 0.24 82.937 0.6 ;
     RECT  82.037 12.24 82.969 14.136 ;
     RECT  82.645 2.88 82.981 3.672 ;
     RECT  82.001 1.728 83.077 1.848 ;
     RECT  82.981 2.88 83.077 4.008 ;
     RECT  82.861 18.672 83.077 20.616 ;
     RECT  83.077 18.672 83.125 21.048 ;
     RECT  83.077 1.728 83.189 4.008 ;
     RECT  82.289 6.336 83.221 7.416 ;
     RECT  82.573 8.448 83.221 11.256 ;
     RECT  82.969 12.24 83.221 14.808 ;
     RECT  82.739 23.376 83.221 23.772 ;
     RECT  82.937 0.24 83.225 0.264 ;
     RECT  83.221 8.448 83.401 14.808 ;
     RECT  82.361 15.84 83.401 17.4 ;
     RECT  83.189 1.824 83.408 4.008 ;
     RECT  83.221 6.24 83.408 7.416 ;
     RECT  83.401 8.448 83.408 17.4 ;
     RECT  83.125 18.384 83.408 21.336 ;
     RECT  83.221 22.464 83.408 23.772 ;
     RECT  83.408 1.824 83.704 23.772 ;
     RECT  83.704 23.376 83.725 23.772 ;
     RECT  83.725 23.376 84.049 24.552 ;
     RECT  83.704 8.448 84.089 21.72 ;
     RECT  83.704 1.824 84.257 2.376 ;
     RECT  83.704 3.744 84.467 3.768 ;
     RECT  83.905 0.576 84.469 0.6 ;
     RECT  84.257 1.728 84.469 2.376 ;
     RECT  84.469 0.576 84.557 2.376 ;
     RECT  84.557 1.68 84.697 2.376 ;
     RECT  84.089 8.544 84.733 21.72 ;
     RECT  84.697 1.68 84.803 2.952 ;
     RECT  84.803 1.68 84.851 2.856 ;
     RECT  84.733 8.544 84.989 22.152 ;
     RECT  84.989 8.928 85.045 22.152 ;
     RECT  84.049 23.376 85.045 25.128 ;
     RECT  83.704 6.336 85.093 7.416 ;
     RECT  84.949 0.528 85.169 0.552 ;
     RECT  85.045 8.928 85.283 25.128 ;
     RECT  85.283 25.104 85.373 25.128 ;
     RECT  85.283 8.928 85.385 23.592 ;
     RECT  85.385 8.928 85.421 20.616 ;
     RECT  85.373 25.104 85.457 25.8 ;
     RECT  85.457 25.104 85.475 25.704 ;
     RECT  84.851 1.68 85.571 2.424 ;
     RECT  85.571 1.728 85.813 2.424 ;
     RECT  85.421 8.928 85.925 9.24 ;
     RECT  85.475 25.104 86.147 25.128 ;
     RECT  85.385 21.6 86.389 23.592 ;
     RECT  85.421 10.272 86.425 20.616 ;
     RECT  86.389 21.6 86.425 23.736 ;
     RECT  85.093 6.336 86.453 7.656 ;
     RECT  86.389 3.984 86.531 4.008 ;
     RECT  86.54 5.136 86.627 5.16 ;
     RECT  85.925 9.072 86.681 9.24 ;
     RECT  85.813 1.728 86.773 2.664 ;
     RECT  85.717 0.192 86.869 0.216 ;
     RECT  86.869 0.192 87.149 0.6 ;
     RECT  86.773 1.728 87.203 3 ;
     RECT  86.681 9.216 87.221 9.24 ;
     RECT  87.253 25.68 87.289 25.704 ;
     RECT  87.289 25.68 87.34 25.8 ;
     RECT  87.34 25.776 87.373 25.8 ;
     RECT  87.361 4.176 87.509 4.2 ;
     RECT  86.425 10.272 87.721 23.736 ;
     RECT  87.203 2.832 87.779 3 ;
     RECT  87.721 10.224 87.805 23.736 ;
     RECT  87.203 1.728 88.309 1.8 ;
     RECT  87.149 0.192 88.501 0.552 ;
     RECT  88.501 0.192 88.661 0.6 ;
     RECT  88.661 0.192 88.733 0.216 ;
     RECT  88.309 1.728 88.808 2.184 ;
     RECT  87.836 3.36 88.808 3.432 ;
     RECT  86.453 6.336 88.808 7.992 ;
     RECT  87.805 10.272 88.808 23.736 ;
     RECT  88.808 1.728 88.912 23.772 ;
     RECT  88.912 1.728 89.104 23.736 ;
     RECT  89.104 15.936 89.219 21.144 ;
     RECT  89.104 14.832 89.237 14.952 ;
     RECT  89.219 18.432 89.309 21.144 ;
     RECT  89.309 18.432 89.345 18.744 ;
     RECT  89.804 0.528 89.891 0.552 ;
     RECT  89.104 22.8 89.989 23.736 ;
     RECT  89.989 22.8 90.083 23.976 ;
     RECT  89.104 5.136 90.281 5.16 ;
     RECT  89.219 15.936 90.281 17.112 ;
     RECT  90.083 22.8 90.371 23.736 ;
     RECT  89.104 3.408 90.529 3.432 ;
     RECT  89.104 6.336 90.565 13.704 ;
     RECT  89.237 14.832 90.565 14.856 ;
     RECT  89.104 1.728 90.577 2.328 ;
     RECT  90.281 16.368 90.605 17.112 ;
     RECT  90.565 6.336 90.611 14.856 ;
     RECT  90.605 17.088 90.785 17.112 ;
     RECT  90.611 13.584 90.821 14.856 ;
     RECT  89.309 19.728 90.893 21.144 ;
     RECT  90.997 4.56 91.145 4.632 ;
     RECT  90.893 19.728 91.181 20.328 ;
     RECT  91.145 4.56 91.217 4.584 ;
     RECT  91.181 19.728 91.253 20.088 ;
     RECT  91.105 25.104 91.331 25.128 ;
     RECT  89.345 18.432 91.357 18.456 ;
     RECT  90.529 3.312 91.393 3.432 ;
     RECT  90.611 6.336 91.505 12.552 ;
     RECT  91.505 6.336 91.577 12.36 ;
     RECT  90.577 1.728 91.612 1.8 ;
     RECT  90.821 13.584 91.667 14.328 ;
     RECT  91.357 18.144 91.717 18.456 ;
     RECT  90.371 23.376 91.757 23.736 ;
     RECT  90.701 0.192 91.765 0.264 ;
     RECT  91.717 18.144 91.865 18.744 ;
     RECT  91.757 23.472 91.901 23.496 ;
     RECT  91.825 16.896 91.909 16.92 ;
     RECT  91.765 0.192 91.973 0.6 ;
     RECT  91.909 16.656 91.996 16.92 ;
     RECT  91.393 2.88 92.009 3.432 ;
     RECT  91.612 1.728 92.077 1.848 ;
     RECT  92.077 1.728 92.225 2.712 ;
     RECT  92.225 1.728 92.413 2.376 ;
     RECT  91.577 6.336 92.617 9.72 ;
     RECT  91.577 10.896 92.617 12.36 ;
     RECT  92.413 1.728 92.653 1.8 ;
     RECT  92.653 1.632 92.771 1.8 ;
     RECT  91.973 0.192 93.109 0.216 ;
     RECT  91.667 13.584 93.116 14.088 ;
     RECT  93.116 13.584 93.203 14.328 ;
     RECT  93.157 5.232 93.301 5.256 ;
     RECT  93.301 4.56 93.397 5.256 ;
     RECT  93.397 3.984 93.481 5.256 ;
     RECT  92.617 6.336 93.481 12.36 ;
     RECT  93.109 0.192 93.485 0.264 ;
     RECT  93.485 0.192 93.539 0.216 ;
     RECT  93.481 3.984 94.028 12.36 ;
     RECT  92.771 1.728 94.208 1.8 ;
     RECT  94.028 3.264 94.208 12.36 ;
     RECT  93.203 13.584 94.208 13.848 ;
     RECT  91.996 16.896 94.208 16.92 ;
     RECT  91.865 18.144 94.208 18.168 ;
     RECT  91.253 20.016 94.208 20.088 ;
     RECT  94.208 1.728 94.312 23.772 ;
     RECT  94.312 1.728 94.504 23.502 ;
     RECT  94.504 5.28 94.601 12.36 ;
     RECT  94.504 16.896 94.601 17.064 ;
     RECT  94.504 1.728 94.745 3.96 ;
     RECT  94.745 1.728 94.853 3.864 ;
     RECT  94.853 1.728 94.931 3.24 ;
     RECT  94.957 0.192 95.04 0.216 ;
     RECT  94.931 2.88 95.212 3.24 ;
     RECT  95.212 2.88 95.321 2.904 ;
     RECT  95.04 0.192 95.345 0.264 ;
     RECT  94.601 5.328 96.085 12.36 ;
     RECT  94.504 13.584 96.085 13.848 ;
     RECT  96.085 5.328 96.229 13.848 ;
     RECT  96.217 2.784 96.364 2.808 ;
     RECT  94.931 1.728 96.469 1.8 ;
     RECT  96.364 2.784 96.469 2.856 ;
     RECT  96.469 1.728 96.509 2.856 ;
     RECT  95.345 0.192 96.833 0.6 ;
     RECT  96.509 1.728 96.893 2.76 ;
     RECT  96.229 4.56 97.036 13.848 ;
     RECT  96.893 1.152 97.301 2.76 ;
     RECT  97.301 1.728 97.477 2.76 ;
     RECT  97.477 1.728 97.573 2.904 ;
     RECT  97.573 1.728 97.669 3.432 ;
     RECT  97.669 1.728 97.697 4.008 ;
     RECT  97.697 1.728 97.841 2.904 ;
     RECT  97.697 3.984 97.985 4.008 ;
     RECT  97.829 0.576 98.525 0.6 ;
     RECT  94.504 20.016 98.593 20.088 ;
     RECT  98.593 20.016 98.633 20.136 ;
     RECT  97.841 1.728 99.013 2.856 ;
     RECT  99.013 1.728 99.061 3.048 ;
     RECT  99.169 0.528 99.347 0.552 ;
     RECT  99.061 1.728 99.608 3.912 ;
     RECT  97.036 5.328 99.608 13.848 ;
     RECT  94.601 17.04 99.608 17.064 ;
     RECT  94.504 18.144 99.608 18.168 ;
     RECT  98.633 20.064 99.608 20.136 ;
     RECT  99.608 1.728 99.712 23.772 ;
     RECT  99.712 1.728 99.904 23.502 ;
     RECT  99.904 1.728 100.177 1.8 ;
     RECT  99.904 20.064 100.829 20.136 ;
     RECT  99.904 2.88 100.979 13.848 ;
     RECT  100.357 0.192 101.125 0.216 ;
     RECT  100.177 1.68 101.125 1.8 ;
     RECT  100.979 4.416 101.153 13.848 ;
     RECT  100.979 2.88 101.219 3.432 ;
     RECT  101.125 0.192 101.261 1.8 ;
     RECT  101.219 2.88 101.645 2.952 ;
     RECT  101.261 0.192 101.657 0.6 ;
     RECT  101.657 0.24 101.873 0.6 ;
     RECT  101.261 1.728 101.948 1.8 ;
     RECT  101.645 2.832 101.948 2.952 ;
     RECT  101.873 0.576 101.981 0.6 ;
     RECT  101.948 1.728 102.277 2.952 ;
     RECT  102.277 1.728 102.449 3.048 ;
     RECT  99.904 18.144 102.589 18.168 ;
     RECT  100.829 20.064 102.589 20.088 ;
     RECT  102.552 3.408 102.661 3.432 ;
     RECT  102.589 18.144 102.733 20.088 ;
     RECT  102.661 3.408 102.773 3.528 ;
     RECT  101.153 5.328 102.805 13.848 ;
     RECT  99.904 17.04 102.997 17.064 ;
     RECT  102.997 16.992 103.084 17.064 ;
     RECT  102.449 1.728 103.525 2.376 ;
     RECT  103.525 1.152 103.609 2.856 ;
     RECT  102.805 5.136 103.637 13.848 ;
     RECT  103.609 1.728 103.709 2.856 ;
     RECT  102.733 18.144 103.745 20.328 ;
     RECT  103.813 0.288 103.877 0.312 ;
     RECT  103.877 0.192 103.955 0.312 ;
     RECT  103.885 3.408 103.969 3.432 ;
     RECT  103.637 5.328 104.389 13.848 ;
     RECT  101.941 15.6 104.389 15.624 ;
     RECT  103.955 0.192 104.573 0.216 ;
     RECT  103.709 1.728 104.929 2.376 ;
     RECT  104.929 1.728 105.008 2.904 ;
     RECT  104.101 3.984 105.008 4.008 ;
     RECT  104.389 5.328 105.008 15.624 ;
     RECT  103.084 17.04 105.008 17.064 ;
     RECT  103.745 18.144 105.008 19.128 ;
     RECT  103.745 20.16 105.008 20.328 ;
     RECT  105.008 1.728 105.112 23.772 ;
     RECT  105.112 1.728 105.304 23.502 ;
     RECT  105.304 2.88 105.401 2.904 ;
     RECT  105.304 3.984 106.265 15.48 ;
     RECT  106.265 4.416 106.409 15.48 ;
     RECT  105.304 1.728 106.632 1.8 ;
     RECT  105.721 0.192 106.645 0.216 ;
     RECT  106.645 0.192 106.769 0.6 ;
     RECT  106.409 4.416 106.769 13.608 ;
     RECT  106.769 0.192 107.057 0.312 ;
     RECT  107.057 0.288 107.093 0.312 ;
     RECT  106.632 1.68 107.267 1.8 ;
     RECT  107.267 1.728 107.477 1.8 ;
     RECT  107.477 1.728 107.701 1.848 ;
     RECT  105.304 18.144 107.773 18.168 ;
     RECT  107.773 18.144 107.813 18.264 ;
     RECT  107.629 3.744 107.893 3.768 ;
     RECT  107.893 3.072 107.989 3.768 ;
     RECT  106.769 5.136 107.989 13.608 ;
     RECT  107.989 3.072 108.133 13.608 ;
     RECT  106.409 14.64 108.133 15.48 ;
     RECT  107.813 18.24 108.313 18.264 ;
     RECT  105.304 19.584 108.313 20.424 ;
     RECT  108.133 3.072 108.637 15.48 ;
     RECT  108.373 0.192 108.661 0.216 ;
     RECT  108.637 2.88 108.661 15.48 ;
     RECT  105.304 16.848 108.661 16.872 ;
     RECT  107.701 1.728 108.745 1.896 ;
     RECT  108.661 2.88 108.745 16.872 ;
     RECT  108.745 1.728 108.755 16.872 ;
     RECT  108.755 1.728 108.821 2.904 ;
     RECT  108.661 0.192 108.949 0.312 ;
     RECT  108.821 1.728 108.949 2.28 ;
     RECT  108.755 4.512 108.961 16.872 ;
     RECT  108.961 4.512 108.997 16.92 ;
     RECT  108.949 0.192 109.187 2.28 ;
     RECT  108.313 18.24 109.289 20.424 ;
     RECT  109.187 0.192 109.325 1.848 ;
     RECT  108.997 4.512 109.813 17.208 ;
     RECT  109.325 1.728 109.901 1.848 ;
     RECT  109.901 1.776 109.973 1.848 ;
     RECT  109.325 0.192 110.009 0.648 ;
     RECT  109.813 4.512 110.101 17.544 ;
     RECT  110.009 0.192 110.297 0.264 ;
     RECT  110.297 0.192 110.339 0.216 ;
     RECT  109.973 1.824 110.408 1.848 ;
     RECT  110.101 3.984 110.408 17.544 ;
     RECT  109.289 19.008 110.408 20.424 ;
     RECT  110.408 1.824 110.512 23.772 ;
     RECT  110.512 1.824 110.704 23.502 ;
     RECT  110.704 3.984 111.017 4.2 ;
     RECT  110.704 1.824 111.193 2.184 ;
     RECT  111.017 3.984 111.233 4.008 ;
     RECT  111.329 0.192 111.412 0.216 ;
     RECT  111.193 1.728 111.553 2.184 ;
     RECT  111.412 0.192 111.665 0.264 ;
     RECT  111.553 1.68 111.683 2.184 ;
     RECT  110.704 5.328 111.737 20.472 ;
     RECT  111.683 1.728 111.805 2.184 ;
     RECT  111.737 5.328 111.805 17.016 ;
     RECT  111.805 5.136 111.809 17.016 ;
     RECT  111.665 0.192 111.817 0.216 ;
     RECT  110.704 22.848 112.129 22.872 ;
     RECT  111.805 1.728 112.259 2.856 ;
     RECT  112.129 22.8 112.525 22.872 ;
     RECT  111.809 15.984 112.769 17.016 ;
     RECT  111.809 5.136 112.777 14.808 ;
     RECT  112.489 3.936 112.849 3.96 ;
     RECT  112.777 5.136 112.849 14.856 ;
     RECT  112.769 15.984 112.885 17.208 ;
     RECT  111.737 18.192 112.885 20.472 ;
     RECT  112.849 3.936 112.892 14.856 ;
     RECT  112.892 3.36 112.979 14.856 ;
     RECT  112.979 3.936 112.997 14.856 ;
     RECT  112.661 0.576 113.068 0.6 ;
     RECT  113.068 0.576 113.069 0.648 ;
     RECT  112.997 3.984 113.125 14.856 ;
     RECT  113.125 3.984 113.173 14.904 ;
     RECT  112.885 15.984 113.173 20.472 ;
     RECT  113.069 0.624 113.249 0.648 ;
     RECT  113.173 3.984 113.353 20.472 ;
     RECT  113.353 3.984 113.363 20.904 ;
     RECT  113.363 3.984 113.465 14.808 ;
     RECT  113.465 3.984 113.537 4.008 ;
     RECT  112.259 1.728 113.653 2.376 ;
     RECT  112.525 22.8 113.893 23.016 ;
     RECT  113.465 5.328 114.361 14.808 ;
     RECT  114.361 5.328 114.397 15 ;
     RECT  113.363 15.984 114.397 20.904 ;
     RECT  113.653 1.728 114.709 2.904 ;
     RECT  114.709 1.728 114.757 3.432 ;
     RECT  114.397 5.328 114.829 20.904 ;
     RECT  114.757 1.728 114.901 4.008 ;
     RECT  115.189 0.192 115.285 0.216 ;
     RECT  115.285 0.192 115.301 0.264 ;
     RECT  115.301 0.24 115.373 0.264 ;
     RECT  114.901 1.728 115.693 4.056 ;
     RECT  114.829 5.136 115.693 20.904 ;
     RECT  115.693 1.728 115.808 20.904 ;
     RECT  113.893 22.272 115.808 23.016 ;
     RECT  115.808 1.728 115.912 23.772 ;
     RECT  115.912 1.728 116.104 23.502 ;
     RECT  116.377 0.528 116.521 0.552 ;
     RECT  116.521 0.192 116.723 0.552 ;
     RECT  116.723 0.24 116.819 0.552 ;
     RECT  116.917 0.576 117.011 0.6 ;
     RECT  116.104 5.136 117.107 20.904 ;
     RECT  116.104 1.728 117.308 2.328 ;
     RECT  117.308 1.104 117.395 2.328 ;
     RECT  117.395 1.68 117.637 2.328 ;
     RECT  117.241 4.56 118.141 4.584 ;
     RECT  117.107 5.568 118.141 20.904 ;
     RECT  117.637 1.68 118.259 2.376 ;
     RECT  118.259 1.728 118.309 2.376 ;
     RECT  118.309 1.728 118.433 3.096 ;
     RECT  118.141 4.56 118.501 20.904 ;
     RECT  118.501 4.176 118.573 20.904 ;
     RECT  118.573 4.176 118.613 21 ;
     RECT  118.613 5.136 118.721 21 ;
     RECT  118.597 0.576 118.844 0.6 ;
     RECT  118.844 0.48 118.937 0.6 ;
     RECT  118.721 5.136 119.081 20.904 ;
     RECT  118.433 1.728 119.441 2.952 ;
     RECT  119.441 1.728 119.513 2.904 ;
     RECT  119.717 0.192 119.941 0.216 ;
     RECT  119.653 4.56 120.085 4.584 ;
     RECT  119.081 5.568 120.085 20.904 ;
     RECT  119.941 0.192 120.197 0.6 ;
     RECT  120.085 4.56 120.229 20.904 ;
     RECT  120.229 4.08 120.301 20.904 ;
     RECT  116.104 22.272 120.301 23.016 ;
     RECT  120.197 0.192 120.665 0.216 ;
     RECT  119.513 1.728 120.733 2.328 ;
     RECT  120.733 1.728 121.208 2.424 ;
     RECT  120.301 4.08 121.208 23.016 ;
     RECT  121.208 1.728 121.312 23.772 ;
     RECT  121.312 1.728 121.504 23.502 ;
     RECT  121.504 4.416 121.619 23.016 ;
     RECT  121.504 1.728 121.667 3 ;
     RECT  121.619 4.56 121.907 23.016 ;
     RECT  121.667 1.728 121.916 2.328 ;
     RECT  121.916 1.68 122.221 2.328 ;
     RECT  122.245 0.192 122.309 0.216 ;
     RECT  121.907 5.136 122.393 23.016 ;
     RECT  122.309 0.192 122.533 0.312 ;
     RECT  122.497 24.528 122.641 24.552 ;
     RECT  122.605 3.408 122.689 3.432 ;
     RECT  122.393 5.568 122.78 23.016 ;
     RECT  122.641 24.528 122.78 24.6 ;
     RECT  122.533 0.192 122.821 0.6 ;
     RECT  122.221 1.68 122.821 1.752 ;
     RECT  122.821 0.192 122.969 1.752 ;
     RECT  122.78 5.568 123.155 24.6 ;
     RECT  122.969 1.728 123.205 1.752 ;
     RECT  122.969 0.192 123.401 0.6 ;
     RECT  123.155 5.568 123.731 24.552 ;
     RECT  123.037 3.84 123.797 3.864 ;
     RECT  123.401 0.192 123.905 0.216 ;
     RECT  123.731 5.568 123.923 23.64 ;
     RECT  123.205 1.728 124.165 2.184 ;
     RECT  124.165 1.728 124.265 2.28 ;
     RECT  124.265 1.728 124.345 1.848 ;
     RECT  124.345 1.776 124.697 1.848 ;
     RECT  124.837 2.832 124.985 2.856 ;
     RECT  124.697 1.824 125.093 1.848 ;
     RECT  123.923 5.568 125.413 23.592 ;
     RECT  124.225 25.104 125.413 25.128 ;
     RECT  125.413 5.568 125.459 25.128 ;
     RECT  125.459 5.568 125.525 24.552 ;
     RECT  125.525 6 125.555 24.552 ;
     RECT  125.701 25.68 125.737 25.704 ;
     RECT  125.737 25.68 125.788 25.8 ;
     RECT  125.788 25.776 125.821 25.8 ;
     RECT  125.555 6 126.608 23.64 ;
     RECT  126.608 2.148 126.712 23.772 ;
     RECT  126.712 2.418 126.904 23.502 ;
     RECT  126.904 6 127.001 23.502 ;
     RECT  127.069 24.528 127.141 24.552 ;
     RECT  127.141 24.528 127.285 24.6 ;
     RECT  127.001 6.096 127.571 23.502 ;
     RECT  127.285 24.528 127.715 24.648 ;
     RECT  127.571 6.144 127.765 23.502 ;
     RECT  127.715 24.624 128.003 24.648 ;
     RECT  127.765 6.144 128.833 23.64 ;
     RECT  128.833 6.144 128.963 23.976 ;
     RECT  129.109 25.68 129.157 25.704 ;
     RECT  129.157 25.68 129.197 25.8 ;
     RECT  129.197 25.776 129.241 25.8 ;
     RECT  128.963 6.144 129.58 23.592 ;
     RECT  129.58 6.144 132.008 23.016 ;
     RECT  132.008 2.148 132.112 23.772 ;
     RECT  132.112 2.418 132.145 23.772 ;
     RECT  132.145 2.418 132.304 24.552 ;
     RECT  132.304 6.144 132.721 24.552 ;
     RECT  132.721 6.144 133.043 25.128 ;
     RECT  133.043 24.528 133.427 25.128 ;
     RECT  133.043 6.144 134.273 23.496 ;
     RECT  134.273 9.6 134.341 23.496 ;
     RECT  134.341 9.6 134.737 23.592 ;
     RECT  133.427 25.104 134.741 25.128 ;
     RECT  134.737 9.6 135.539 23.64 ;
     RECT  134.273 6.144 135.683 8.568 ;
     RECT  135.683 6.144 135.821 7.944 ;
     RECT  135.539 9.6 135.857 23.448 ;
     RECT  135.821 6.144 135.929 6.168 ;
     RECT  135.821 7.2 137.408 7.944 ;
     RECT  135.857 9.6 137.408 23.016 ;
     RECT  137.408 2.148 137.512 23.772 ;
     RECT  137.512 2.418 137.704 23.502 ;
     RECT  137.704 9.6 137.801 23.4 ;
     RECT  137.704 7.392 138.593 7.944 ;
     RECT  137.801 11.136 138.697 23.4 ;
     RECT  138.301 25.104 138.697 25.128 ;
     RECT  138.697 25.104 139.021 25.176 ;
     RECT  139.021 24.528 139.187 25.176 ;
     RECT  139.187 24.624 139.283 25.176 ;
     RECT  137.801 9.6 139.673 10.056 ;
     RECT  138.697 11.136 139.885 23.448 ;
     RECT  139.283 25.104 140.197 25.176 ;
     RECT  140.197 25.104 140.245 25.704 ;
     RECT  140.245 25.104 140.617 25.8 ;
     RECT  140.617 25.104 141.011 25.128 ;
     RECT  138.593 7.44 141.113 7.944 ;
     RECT  139.885 11.136 141.145 23.592 ;
     RECT  141.145 11.136 141.395 24.552 ;
     RECT  141.395 11.136 141.587 23.976 ;
     RECT  139.673 9.6 141.689 10.008 ;
     RECT  141.113 7.92 142.808 7.944 ;
     RECT  141.689 9.6 142.808 9.624 ;
     RECT  141.587 11.136 142.808 23.496 ;
     RECT  142.808 2.148 142.912 23.772 ;
     RECT  142.912 2.418 143.104 23.502 ;
     RECT  143.104 7.92 148.208 7.944 ;
     RECT  143.104 9.6 148.208 9.624 ;
     RECT  143.104 11.136 148.208 23.016 ;
     RECT  148.208 2.148 148.312 23.772 ;
     RECT  148.312 2.418 148.504 23.502 ;
     RECT  148.504 7.92 153.608 7.944 ;
     RECT  148.504 9.6 153.608 9.624 ;
     RECT  148.504 11.136 153.608 23.016 ;
     RECT  153.608 2.148 153.712 23.772 ;
     RECT  153.712 2.418 153.904 23.502 ;
     RECT  153.904 7.92 159.008 7.944 ;
     RECT  153.904 9.6 159.008 9.624 ;
     RECT  153.904 11.136 159.008 12.888 ;
     RECT  153.904 13.92 159.008 23.016 ;
     RECT  159.008 2.148 159.112 23.772 ;
     RECT  159.112 2.418 159.304 23.502 ;
     RECT  159.304 7.92 164.408 7.944 ;
     RECT  159.304 9.6 164.408 9.624 ;
     RECT  159.304 11.136 164.408 12.888 ;
     RECT  159.304 13.92 164.408 23.016 ;
     RECT  164.408 2.148 164.512 23.772 ;
     RECT  164.512 2.418 164.704 23.502 ;
     RECT  164.704 7.92 165.629 7.944 ;
     RECT  164.704 9.6 169.808 9.624 ;
     RECT  164.704 11.136 169.808 12.888 ;
     RECT  164.704 13.92 169.808 23.016 ;
     RECT  169.808 2.148 169.912 23.772 ;
     RECT  169.912 2.418 170.104 23.502 ;
     RECT  170.104 13.92 171.154 23.352 ;
     RECT  171.154 13.92 171.565 23.4 ;
     RECT  171.565 13.92 172.717 23.64 ;
     RECT  172.717 13.92 172.741 23.976 ;
     RECT  172.069 25.104 172.741 25.128 ;
     RECT  172.741 13.92 172.979 25.128 ;
     RECT  172.979 13.92 173.459 24.552 ;
     RECT  173.459 13.92 173.549 23.736 ;
     RECT  173.549 13.92 174.035 23.496 ;
     RECT  170.104 9.6 175.208 9.624 ;
     RECT  170.104 11.136 175.208 12.888 ;
     RECT  174.035 13.92 175.208 23.448 ;
     RECT  175.208 2.148 175.312 23.772 ;
     RECT  175.312 2.418 175.504 23.502 ;
     RECT  175.504 13.92 176.857 23.016 ;
     RECT  176.857 13.92 177.685 23.976 ;
     RECT  177.925 25.68 177.973 25.704 ;
     RECT  177.685 13.92 178.163 24.552 ;
     RECT  177.973 25.68 178.345 25.8 ;
     RECT  178.163 13.92 178.451 23.928 ;
     RECT  178.451 13.92 179.165 23.736 ;
     RECT  178.693 25.104 179.365 25.128 ;
     RECT  179.365 25.104 179.413 25.704 ;
     RECT  179.413 25.104 179.497 25.8 ;
     RECT  179.497 25.104 179.699 25.128 ;
     RECT  179.165 23.376 179.881 23.736 ;
     RECT  179.881 23.376 180.179 24.552 ;
     RECT  175.504 9.6 180.608 9.624 ;
     RECT  175.504 11.136 180.608 12.888 ;
     RECT  179.165 13.92 180.608 22.344 ;
     RECT  180.179 23.376 180.608 23.772 ;
     RECT  180.608 2.148 180.712 23.772 ;
     RECT  180.712 2.418 180.904 23.772 ;
     RECT  180.904 23.376 181.141 23.772 ;
     RECT  181.141 23.376 181.331 24.552 ;
     RECT  180.904 13.92 181.361 22.296 ;
     RECT  181.331 23.376 181.907 24.024 ;
     RECT  181.907 23.376 182.972 23.736 ;
     RECT  182.149 25.104 182.972 25.128 ;
     RECT  182.972 23.376 183.155 25.128 ;
     RECT  183.155 23.376 183.58 24.552 ;
     RECT  183.58 23.376 183.773 23.496 ;
     RECT  183.58 24.528 183.827 24.552 ;
     RECT  183.773 23.376 183.923 23.448 ;
     RECT  183.923 23.376 184.06 23.4 ;
     RECT  180.904 11.136 186.008 12.888 ;
     RECT  181.361 13.92 186.008 22.248 ;
     RECT  186.008 2.148 186.112 23.772 ;
     RECT  186.112 2.418 186.304 23.502 ;
     RECT  186.304 11.136 191.408 12.888 ;
     RECT  186.304 13.92 191.408 22.248 ;
     RECT  191.408 2.148 191.512 23.772 ;
     RECT  191.512 2.418 191.704 23.502 ;
     RECT  191.704 11.136 196.808 12.888 ;
     RECT  191.704 13.92 196.808 22.248 ;
     RECT  196.808 2.148 196.912 23.772 ;
     RECT  196.912 2.418 197.104 23.502 ;
     RECT  197.104 11.136 202.208 12.888 ;
     RECT  197.104 13.92 202.208 22.248 ;
     RECT  202.208 2.148 202.312 23.772 ;
     RECT  202.312 2.418 202.504 23.502 ;
     RECT  202.504 13.92 204.721 22.248 ;
     RECT  204.505 23.952 205.621 23.976 ;
     RECT  205.621 23.952 205.765 24.024 ;
     RECT  205.765 23.328 205.907 24.024 ;
     RECT  204.721 13.92 205.913 22.296 ;
     RECT  205.907 23.328 206.195 23.928 ;
     RECT  205.765 25.056 206.345 25.08 ;
     RECT  205.913 13.92 207.493 21.672 ;
     RECT  202.504 11.136 207.608 12.888 ;
     RECT  207.493 13.92 207.608 21.768 ;
     RECT  206.195 23.376 207.608 23.928 ;
     RECT  207.608 2.148 207.712 23.928 ;
     RECT  207.712 2.418 207.904 23.928 ;
     RECT  207.904 13.92 208.06 21.864 ;
     RECT  208.06 13.92 208.289 21.624 ;
     RECT  207.904 23.376 208.573 23.928 ;
     RECT  208.573 23.376 208.732 24.552 ;
     RECT  208.732 24.528 208.787 24.552 ;
     RECT  208.732 23.376 209.171 23.496 ;
     RECT  209.171 23.376 209.267 23.448 ;
     RECT  209.267 23.424 209.363 23.448 ;
     RECT  207.904 11.136 210.161 12.888 ;
     RECT  212.137 23.376 212.245 23.4 ;
     RECT  212.245 23.376 212.348 23.448 ;
     RECT  210.161 11.136 213.008 11.16 ;
     RECT  210.161 12.576 213.008 12.888 ;
     RECT  208.289 13.92 213.008 21.528 ;
     RECT  212.348 23.376 213.008 23.736 ;
     RECT  213.008 2.148 213.112 23.772 ;
     RECT  213.112 2.418 213.145 23.772 ;
     RECT  213.145 2.418 213.304 24.552 ;
     RECT  213.304 23.712 213.635 24.552 ;
     RECT  213.635 24.528 213.731 24.552 ;
     RECT  213.304 13.92 218.293 21.528 ;
     RECT  213.304 11.136 218.408 11.16 ;
     RECT  213.304 12.576 218.408 12.888 ;
     RECT  218.293 13.872 218.408 21.528 ;
     RECT  218.113 23.952 218.408 23.976 ;
     RECT  218.408 2.148 218.512 23.976 ;
     RECT  218.512 2.418 218.704 23.976 ;
     RECT  218.704 23.376 218.833 23.976 ;
     RECT  218.725 25.104 218.833 25.128 ;
     RECT  218.833 23.376 219.011 25.128 ;
     RECT  219.011 24.528 219.085 25.128 ;
     RECT  219.085 24.528 219.491 25.176 ;
     RECT  219.491 24.528 219.875 25.128 ;
     RECT  219.011 23.376 220.213 23.496 ;
     RECT  220.213 23.376 220.931 23.736 ;
     RECT  219.875 25.104 221.029 25.128 ;
     RECT  218.704 12.576 221.105 12.888 ;
     RECT  221.029 24.528 221.173 25.128 ;
     RECT  218.704 13.872 221.209 21.528 ;
     RECT  221.173 24.528 221.209 25.704 ;
     RECT  221.209 13.872 221.293 21.672 ;
     RECT  221.209 24.528 221.293 25.8 ;
     RECT  221.293 24.528 221.315 25.128 ;
     RECT  221.293 13.872 221.429 21.528 ;
     RECT  220.931 23.376 221.74 23.448 ;
     RECT  221.74 23.376 221.932 23.4 ;
     RECT  221.315 25.104 221.987 25.128 ;
     RECT  221.429 13.872 222.005 14.136 ;
     RECT  218.704 11.136 223.808 11.16 ;
     RECT  221.105 12.576 223.808 12.6 ;
     RECT  222.005 14.112 223.808 14.136 ;
     RECT  221.429 15.264 223.808 21.528 ;
     RECT  223.808 2.148 223.912 23.772 ;
     RECT  223.912 2.418 224.104 23.736 ;
     RECT  224.104 15.264 224.705 21.528 ;
     RECT  224.104 23.376 224.989 23.736 ;
     RECT  224.989 23.376 225.116 24.552 ;
     RECT  225.116 23.328 225.203 24.552 ;
     RECT  225.203 23.376 225.692 24.552 ;
     RECT  225.692 23.376 225.779 25.128 ;
     RECT  224.705 15.312 225.857 21.528 ;
     RECT  225.857 15.312 226.073 19.32 ;
     RECT  225.857 20.304 226.181 21.528 ;
     RECT  226.073 15.312 226.289 15.528 ;
     RECT  225.779 23.376 226.451 24.552 ;
     RECT  226.181 21.504 226.541 21.528 ;
     RECT  226.825 25.104 226.931 25.128 ;
     RECT  226.073 16.512 226.973 19.32 ;
     RECT  226.973 16.512 227.068 19.224 ;
     RECT  227.068 16.608 227.081 19.224 ;
     RECT  226.181 20.304 227.189 20.328 ;
     RECT  226.289 15.456 227.477 15.528 ;
     RECT  227.081 16.896 227.513 19.224 ;
     RECT  227.513 16.896 227.693 17.112 ;
     RECT  227.477 15.456 227.729 15.48 ;
     RECT  227.693 17.088 227.765 17.112 ;
     RECT  226.451 23.376 227.765 23.736 ;
     RECT  224.104 14.112 227.837 14.136 ;
     RECT  227.765 23.424 227.873 23.736 ;
     RECT  227.873 23.424 227.891 23.496 ;
     RECT  227.891 23.424 227.945 23.448 ;
     RECT  227.513 18.144 228.053 19.224 ;
     RECT  224.104 11.136 228.197 11.16 ;
     RECT  228.053 18.24 229.208 19.224 ;
     RECT  229.208 2.148 229.312 23.772 ;
     RECT  229.312 2.418 229.504 23.502 ;
     RECT  234.608 2.148 234.712 23.772 ;
     RECT  234.712 2.418 234.904 23.502 ;
    LAYER M5 ;
     RECT  60 0.144 124.392 1.763 ;
     RECT  60.096 1.763 124.392 1.811 ;
     RECT  63.456 1.811 78.312 1.859 ;
     RECT  2.4 2.137 2.52 2.151 ;
     RECT  7.8 2.137 7.92 2.151 ;
     RECT  13.2 2.137 13.32 2.151 ;
     RECT  18.6 2.137 18.72 2.151 ;
     RECT  24 2.137 24.12 2.151 ;
     RECT  29.4 2.137 29.52 2.151 ;
     RECT  34.8 2.137 34.92 2.151 ;
     RECT  40.2 2.137 40.32 2.151 ;
     RECT  45.6 2.137 45.72 2.151 ;
     RECT  51 2.137 51.12 2.151 ;
     RECT  56.4 2.137 56.52 2.151 ;
     RECT  126.6 2.137 126.72 2.151 ;
     RECT  132 2.137 132.12 2.151 ;
     RECT  137.4 2.137 137.52 2.151 ;
     RECT  142.8 2.137 142.92 2.151 ;
     RECT  148.2 2.137 148.32 2.151 ;
     RECT  153.6 2.137 153.72 2.151 ;
     RECT  159 2.137 159.12 2.151 ;
     RECT  164.4 2.137 164.52 2.151 ;
     RECT  169.8 2.137 169.92 2.151 ;
     RECT  175.2 2.137 175.32 2.151 ;
     RECT  180.6 2.137 180.72 2.151 ;
     RECT  186 2.137 186.12 2.151 ;
     RECT  191.4 2.137 191.52 2.151 ;
     RECT  196.8 2.137 196.92 2.151 ;
     RECT  202.2 2.137 202.32 2.151 ;
     RECT  207.6 2.137 207.72 2.151 ;
     RECT  213 2.137 213.12 2.151 ;
     RECT  218.4 2.137 218.52 2.151 ;
     RECT  223.8 2.137 223.92 2.151 ;
     RECT  229.2 2.137 229.32 2.151 ;
     RECT  234.6 2.137 234.72 2.151 ;
     RECT  102 1.811 124.392 2.195 ;
     RECT  102 2.195 122.664 2.291 ;
     RECT  124.176 2.195 124.392 2.291 ;
     RECT  60.096 1.811 62.112 2.339 ;
     RECT  79.728 1.811 100.968 2.339 ;
     RECT  82.128 2.339 100.968 2.387 ;
     RECT  61.536 2.339 62.112 2.435 ;
     RECT  84.768 2.387 91.608 2.435 ;
     RECT  68.64 1.859 78.312 2.627 ;
     RECT  79.728 2.339 81.096 2.675 ;
     RECT  85.824 2.435 91.608 2.675 ;
     RECT  98.928 2.387 100.968 2.821 ;
     RECT  102 2.291 108.12 2.821 ;
     RECT  68.64 2.627 76.296 2.867 ;
     RECT  86.592 2.675 91.608 2.867 ;
     RECT  98.928 2.821 108.12 2.867 ;
     RECT  60.096 2.339 60.312 2.915 ;
     RECT  68.64 2.867 72.912 2.915 ;
     RECT  77.616 2.627 78.312 2.915 ;
     RECT  82.128 2.387 83.712 2.915 ;
     RECT  93.312 2.387 96.264 2.915 ;
     RECT  97.488 2.387 97.704 2.915 ;
     RECT  110.112 2.291 122.664 2.915 ;
     RECT  60.288 2.915 60.312 2.963 ;
     RECT  86.592 2.867 86.808 3.011 ;
     RECT  99.024 2.867 108.12 3.059 ;
     RECT  70.56 2.915 72.912 3.443 ;
     RECT  80.208 2.675 81.096 3.443 ;
     RECT  97.584 2.915 97.704 3.443 ;
     RECT  99.12 3.059 108.12 3.443 ;
     RECT  114.72 2.915 122.664 3.443 ;
     RECT  68.64 2.915 69.528 3.491 ;
     RECT  82.656 2.915 83.712 3.683 ;
     RECT  82.992 3.683 83.712 3.733 ;
     RECT  84.768 2.435 84.84 3.733 ;
     RECT  99.36 3.443 108.12 3.733 ;
     RECT  86.592 3.011 86.616 3.973 ;
     RECT  63.456 1.859 67.512 4.019 ;
     RECT  70.56 3.443 71.256 4.019 ;
     RECT  74.16 2.867 76.296 4.019 ;
     RECT  82.992 3.733 84.84 4.019 ;
     RECT  97.68 3.443 97.704 4.019 ;
     RECT  99.36 3.733 108.744 4.019 ;
     RECT  110.112 2.915 113.496 4.019 ;
     RECT  65.376 4.019 67.512 4.067 ;
     RECT  114.912 3.443 121.896 4.067 ;
     RECT  70.56 4.019 71.064 4.451 ;
     RECT  110.112 4.019 113.4 4.501 ;
     RECT  96.24 2.915 96.264 4.549 ;
     RECT  68.64 3.491 69.336 4.595 ;
     RECT  74.16 4.019 75.144 4.595 ;
     RECT  80.928 3.443 81.096 4.595 ;
     RECT  87.888 2.867 91.608 4.595 ;
     RECT  93.312 2.915 95.16 4.595 ;
     RECT  96.24 4.549 96.984 4.595 ;
     RECT  106.464 4.019 108.744 4.595 ;
     RECT  109.728 4.501 113.4 4.595 ;
     RECT  115.8 4.067 121.896 4.595 ;
     RECT  91.104 4.595 91.608 4.643 ;
     RECT  120.432 4.595 121.656 4.739 ;
     RECT  80.928 4.595 80.952 5.125 ;
     RECT  63.456 4.019 64.344 5.171 ;
     RECT  65.376 4.067 65.4 5.171 ;
     RECT  80.832 5.125 80.952 5.171 ;
     RECT  86.496 3.973 86.616 5.171 ;
     RECT  87.888 4.595 90.072 5.171 ;
     RECT  106.848 4.595 108.744 5.171 ;
     RECT  115.8 4.595 117.096 5.171 ;
     RECT  109.728 4.595 113.112 5.315 ;
     RECT  79.44 5.173 79.464 5.555 ;
     RECT  121.2 4.739 121.656 5.605 ;
     RECT  63.456 5.171 64.248 5.747 ;
     RECT  66.432 4.067 67.512 5.747 ;
     RECT  69.312 4.595 69.336 5.747 ;
     RECT  76.272 4.019 76.296 5.747 ;
     RECT  94.08 4.595 95.16 5.747 ;
     RECT  99.36 4.019 103.272 5.795 ;
     RECT  63.648 5.747 64.248 5.843 ;
     RECT  103.248 5.795 103.272 5.843 ;
     RECT  108.096 5.171 108.744 5.941 ;
     RECT  109.728 5.315 112.968 5.941 ;
     RECT  118.704 4.595 118.824 6.085 ;
     RECT  126.6 2.151 126.912 6.085 ;
     RECT  124.368 2.291 124.392 6.181 ;
     RECT  83.4 4.019 84.84 6.229 ;
     RECT  108.096 5.941 112.968 6.229 ;
     RECT  64.176 5.843 64.248 6.323 ;
     RECT  99.36 5.795 101.688 6.323 ;
     RECT  94.08 5.747 94.512 6.371 ;
     RECT  107.712 6.229 112.968 6.371 ;
     RECT  105 4.019 105.312 6.517 ;
     RECT  123.792 6.181 124.392 6.517 ;
     RECT  123.792 6.517 124.728 6.563 ;
     RECT  104.88 6.517 105.312 6.659 ;
     RECT  119.952 6.373 119.976 6.659 ;
     RECT  118.56 6.085 118.824 6.709 ;
     RECT  108.384 6.371 111.576 6.851 ;
     RECT  112.896 6.371 112.968 6.901 ;
     RECT  115.8 5.171 116.112 6.997 ;
     RECT  118.56 6.709 119.64 7.043 ;
     RECT  119.616 7.043 119.64 7.091 ;
     RECT  115.152 6.997 116.112 7.189 ;
     RECT  108.72 6.851 111.576 7.235 ;
     RECT  107.184 7.141 107.208 7.285 ;
     RECT  107.088 7.285 107.208 7.331 ;
     RECT  108.72 7.235 111.48 7.331 ;
     RECT  112.896 6.901 113.016 7.333 ;
     RECT  114.672 7.189 116.112 7.333 ;
     RECT  45.6 2.151 45.912 7.381 ;
     RECT  71.04 4.451 71.064 7.381 ;
     RECT  121.2 5.605 122.52 7.381 ;
     RECT  80.832 5.171 80.856 7.427 ;
     RECT  107.088 7.331 107.112 7.427 ;
     RECT  78 2.915 78.312 7.429 ;
     RECT  112.896 7.333 116.112 7.429 ;
     RECT  60.72 6.805 60.744 7.475 ;
     RECT  118.56 7.043 118.584 7.475 ;
     RECT  112.896 7.429 116.328 7.523 ;
     RECT  114 7.523 116.328 7.571 ;
     RECT  96.96 4.595 96.984 7.573 ;
     RECT  115.152 7.571 116.328 7.573 ;
     RECT  121.104 7.381 122.52 7.619 ;
     RECT  83.232 6.229 84.84 7.621 ;
     RECT  96.912 7.573 96.984 7.621 ;
     RECT  103.92 7.525 103.944 7.621 ;
     RECT  115.152 7.573 116.616 7.621 ;
     RECT  64.176 6.323 64.2 7.669 ;
     RECT  70.656 7.381 71.064 7.669 ;
     RECT  72.24 3.443 72.912 7.669 ;
     RECT  51 2.151 51.312 7.717 ;
     RECT  96.912 7.621 97.704 7.763 ;
     RECT  56.4 2.151 56.712 7.765 ;
     RECT  58.464 7.237 58.488 7.765 ;
     RECT  103.824 7.621 103.944 7.861 ;
     RECT  105 6.659 105.312 7.861 ;
     RECT  115.152 7.621 116.904 7.907 ;
     RECT  61.8 2.435 62.112 7.909 ;
     RECT  132 2.151 132.312 7.909 ;
     RECT  45.504 7.381 45.912 7.955 ;
     RECT  118.32 7.813 118.344 7.955 ;
     RECT  86.496 5.171 86.52 8.003 ;
     RECT  97.68 7.763 97.704 8.003 ;
     RECT  108.72 7.331 111.384 8.051 ;
     RECT  61.8 7.909 62.808 8.243 ;
     RECT  103.824 7.861 105.312 8.243 ;
     RECT  75.408 7.957 75.432 8.293 ;
     RECT  109.728 8.051 111.384 8.293 ;
     RECT  121.104 7.619 121.608 8.293 ;
     RECT  124.368 6.563 124.728 8.389 ;
     RECT  50.88 7.717 51.312 8.483 ;
     RECT  61.8 8.243 62.112 8.485 ;
     RECT  126.6 6.085 127.56 8.485 ;
     RECT  124.368 8.389 124.872 8.531 ;
     RECT  120.624 8.293 121.608 8.533 ;
     RECT  135.648 7.621 135.672 8.579 ;
     RECT  112.896 7.523 113.016 8.627 ;
     RECT  64.128 7.669 64.2 8.675 ;
     RECT  64.176 8.675 64.2 8.677 ;
     RECT  77.808 7.429 78.312 8.723 ;
     RECT  109.728 8.293 111.576 8.725 ;
     RECT  112.896 8.627 112.968 8.725 ;
     RECT  58.464 7.765 58.632 8.771 ;
     RECT  115.152 7.907 116.52 8.819 ;
     RECT  114 7.571 114.024 8.867 ;
     RECT  49.248 7.381 49.272 8.963 ;
     RECT  120.528 8.533 121.608 9.155 ;
     RECT  99.36 6.323 101.208 9.203 ;
     RECT  124.368 8.531 124.728 9.251 ;
     RECT  129.264 8.485 129.288 9.251 ;
     RECT  115.8 8.819 116.52 9.253 ;
     RECT  70.656 7.669 72.912 9.347 ;
     RECT  115.8 9.253 116.616 9.395 ;
     RECT  103.824 8.243 103.848 9.445 ;
     RECT  104.88 8.243 105.312 9.445 ;
     RECT  108.72 8.051 108.744 9.445 ;
     RECT  109.728 8.725 112.968 9.445 ;
     RECT  58.464 8.771 58.488 9.491 ;
     RECT  126.6 8.485 127.608 9.541 ;
     RECT  103.824 9.445 105.816 9.587 ;
     RECT  87.888 5.171 89.112 9.637 ;
     RECT  75.408 8.293 75.864 9.731 ;
     RECT  91.584 4.643 91.608 9.731 ;
     RECT  61.68 8.485 62.112 9.877 ;
     RECT  115.8 9.395 116.328 9.971 ;
     RECT  120.96 9.155 121.608 10.115 ;
     RECT  87.888 9.637 89.208 10.213 ;
     RECT  61.68 9.877 62.904 10.259 ;
     RECT  78 8.723 78.312 10.261 ;
     RECT  64.176 8.677 65.16 10.307 ;
     RECT  75.408 9.731 75.432 10.307 ;
     RECT  87.744 10.213 89.208 10.307 ;
     RECT  99.6 9.203 101.208 10.307 ;
     RECT  108.72 9.445 112.968 10.307 ;
     RECT  107.712 9.157 107.736 10.309 ;
     RECT  61.8 10.259 62.904 10.355 ;
     RECT  71.04 9.347 72.912 10.355 ;
     RECT  88.8 10.307 89.208 10.355 ;
     RECT  107.616 10.309 107.736 10.355 ;
     RECT  117.648 10.021 117.672 10.405 ;
     RECT  107.616 10.355 107.64 10.643 ;
     RECT  117.456 10.405 117.672 10.739 ;
     RECT  114.576 10.405 114.6 10.835 ;
     RECT  117.456 10.739 117.48 10.835 ;
     RECT  105 9.587 105.312 10.837 ;
     RECT  71.424 10.355 72.912 10.883 ;
     RECT  121.2 10.115 121.608 10.883 ;
     RECT  79.632 10.789 79.656 10.931 ;
     RECT  110.016 10.307 112.968 10.931 ;
     RECT  83.232 7.621 85.128 10.979 ;
     RECT  45.6 7.955 45.912 10.981 ;
     RECT  124.368 9.251 124.584 10.981 ;
     RECT  51 8.483 51.312 11.029 ;
     RECT  124.368 10.981 125.208 11.029 ;
     RECT  126.6 9.541 128.232 11.029 ;
     RECT  108.864 10.307 108.936 11.075 ;
     RECT  105 10.837 106.248 11.077 ;
     RECT  115.8 9.971 116.112 11.125 ;
     RECT  110.4 10.931 112.968 11.221 ;
     RECT  105 11.077 106.536 11.267 ;
     RECT  115.8 11.125 116.76 11.267 ;
     RECT  86.736 10.501 86.76 11.269 ;
     RECT  87.744 10.307 87.768 11.269 ;
     RECT  124.368 11.029 128.232 11.269 ;
     RECT  84.72 10.979 85.128 11.317 ;
     RECT  105 11.267 106.248 11.363 ;
     RECT  48.096 9.541 48.12 11.365 ;
     RECT  86.736 11.269 87.768 11.411 ;
     RECT  124.08 11.269 128.232 11.411 ;
     RECT  72.24 10.883 72.912 11.459 ;
     RECT  99.6 10.307 100.392 11.459 ;
     RECT  124.368 11.411 128.232 11.651 ;
     RECT  126.6 11.651 128.232 11.699 ;
     RECT  84.72 11.317 85.272 11.701 ;
     RECT  51 11.029 52.056 11.747 ;
     RECT  108.864 11.075 108.888 11.749 ;
     RECT  105 11.363 105.432 11.795 ;
     RECT  108.72 11.749 108.888 11.795 ;
     RECT  119.472 10.741 119.496 11.891 ;
     RECT  124.368 11.651 125.208 11.891 ;
     RECT  115.8 11.267 116.112 11.893 ;
     RECT  105 11.795 105.312 11.941 ;
     RECT  45.6 10.981 46.152 11.987 ;
     RECT  87.264 11.411 87.768 11.987 ;
     RECT  64.176 10.307 64.2 12.035 ;
     RECT  77.472 10.261 78.312 12.035 ;
     RECT  110.4 11.221 113.208 12.035 ;
     RECT  121.2 10.883 121.512 12.181 ;
     RECT  48.096 11.365 49.032 12.227 ;
     RECT  66.528 5.747 67.512 12.229 ;
     RECT  83.232 10.979 83.712 12.229 ;
     RECT  148.2 2.151 148.512 12.229 ;
     RECT  66.144 12.229 67.512 12.275 ;
     RECT  123.264 12.181 123.288 12.371 ;
     RECT  54.24 11.845 54.264 12.467 ;
     RECT  55.392 9.541 55.416 12.467 ;
     RECT  66.144 12.275 66.168 12.515 ;
     RECT  126.6 11.699 127.272 12.515 ;
     RECT  75.408 11.941 75.432 12.517 ;
     RECT  207.6 2.151 207.912 12.517 ;
     RECT  48.096 12.227 48.12 12.563 ;
     RECT  60.528 9.637 60.552 12.563 ;
     RECT  84.72 11.701 86.04 12.563 ;
     RECT  87.504 11.987 87.768 12.563 ;
     RECT  103.824 9.587 103.848 12.563 ;
     RECT  129.12 12.565 129.144 12.707 ;
     RECT  75.408 12.517 75.768 12.757 ;
     RECT  120.72 12.181 121.512 12.757 ;
     RECT  96.096 11.941 96.12 12.803 ;
     RECT  115.008 11.893 116.112 12.853 ;
     RECT  104.88 11.941 105.312 12.995 ;
     RECT  115.008 12.853 117 12.995 ;
     RECT  108.72 11.795 108.744 13.043 ;
     RECT  120.72 12.757 122.472 13.043 ;
     RECT  75.408 12.757 75.816 13.091 ;
     RECT  82.992 12.229 83.712 13.091 ;
     RECT  124.368 11.891 124.584 13.091 ;
     RECT  81.792 12.517 81.816 13.139 ;
     RECT  112.752 12.035 113.208 13.139 ;
     RECT  87.504 12.563 87.624 13.283 ;
     RECT  121.2 13.043 122.472 13.379 ;
     RECT  80.448 13.045 80.472 13.429 ;
     RECT  83.28 13.091 83.712 13.477 ;
     RECT  85.248 12.563 86.04 13.477 ;
     RECT  87.504 13.283 87.576 13.477 ;
     RECT  88.8 10.355 89.112 13.477 ;
     RECT  109.392 13.045 109.416 13.523 ;
     RECT  75.408 13.091 75.768 13.525 ;
     RECT  79.488 13.429 80.472 13.621 ;
     RECT  153.6 2.151 153.912 13.621 ;
     RECT  74.976 13.525 75.768 13.715 ;
     RECT  115.008 12.995 116.112 13.715 ;
     RECT  124.368 13.091 124.392 13.763 ;
     RECT  74.976 13.715 75.432 13.859 ;
     RECT  134.064 13.429 134.088 13.907 ;
     RECT  83.28 13.477 84.072 14.197 ;
     RECT  90.576 13.045 90.6 14.243 ;
     RECT  91.632 10.885 91.656 14.339 ;
     RECT  93.168 13.813 93.192 14.339 ;
     RECT  71.568 13.621 71.592 14.387 ;
     RECT  74.976 13.859 75.144 14.387 ;
     RECT  121.2 13.379 121.512 14.437 ;
     RECT  124.32 14.389 124.344 14.533 ;
     RECT  128.928 14.293 128.952 14.627 ;
     RECT  114.528 14.197 114.552 14.677 ;
     RECT  121.2 14.437 121.896 14.677 ;
     RECT  51 11.747 51.432 14.773 ;
     RECT  85.248 13.477 87.576 14.773 ;
     RECT  88.8 13.477 89.304 14.773 ;
     RECT  105 12.995 105.312 14.773 ;
     RECT  83.136 14.197 84.072 14.867 ;
     RECT  113.136 13.139 113.208 14.915 ;
     RECT  123.552 14.533 124.344 14.917 ;
     RECT  121.2 14.677 122.328 14.965 ;
     RECT  123.36 14.917 124.344 14.965 ;
     RECT  130.128 14.053 130.152 14.965 ;
     RECT  45.6 11.987 45.912 15.013 ;
     RECT  136.032 14.965 136.056 15.107 ;
     RECT  121.2 14.965 124.344 15.155 ;
     RECT  123.36 15.155 124.344 15.203 ;
     RECT  51 14.773 51.912 15.205 ;
     RECT  121.2 15.155 122.328 15.251 ;
     RECT  129.264 14.965 130.584 15.251 ;
     RECT  85.248 14.773 89.304 15.301 ;
     RECT  113.184 14.915 113.208 15.301 ;
     RECT  114.528 14.677 114.6 15.301 ;
     RECT  115.8 13.715 116.112 15.301 ;
     RECT  135.024 15.205 135.048 15.347 ;
     RECT  124.32 15.203 124.344 15.395 ;
     RECT  129.84 15.251 129.96 15.395 ;
     RECT  79.488 13.621 81.672 15.443 ;
     RECT  113.184 15.301 113.352 15.443 ;
     RECT  132 7.909 132.504 15.443 ;
     RECT  105 14.773 106.104 15.491 ;
     RECT  126.6 12.515 127.08 15.587 ;
     RECT  50.88 15.205 51.912 15.875 ;
     RECT  85.152 15.301 89.304 15.877 ;
     RECT  51 15.875 51.912 15.971 ;
     RECT  59.856 14.917 59.88 16.019 ;
     RECT  79.68 15.443 81.432 16.019 ;
     RECT  108.672 15.445 108.696 16.019 ;
     RECT  114.528 15.301 116.112 16.067 ;
     RECT  110.4 12.035 111.576 16.069 ;
     RECT  214.32 15.973 214.344 16.115 ;
     RECT  53.088 15.493 53.112 16.259 ;
     RECT  218.4 2.151 218.712 16.261 ;
     RECT  45.408 15.013 45.912 16.307 ;
     RECT  51 15.971 51.432 16.355 ;
     RECT  13.2 2.151 13.512 16.357 ;
     RECT  84.864 15.877 89.304 16.403 ;
     RECT  40.2 2.151 40.512 16.405 ;
     RECT  83.136 14.867 83.832 16.405 ;
     RECT  84.864 16.403 89.208 16.405 ;
     RECT  121.2 15.251 121.896 16.405 ;
     RECT  81.408 16.019 81.432 16.501 ;
     RECT  113.328 15.443 113.352 16.547 ;
     RECT  129.936 15.395 129.96 16.549 ;
     RECT  137.4 2.151 137.712 16.549 ;
     RECT  75.12 14.387 75.144 16.595 ;
     RECT  109.872 16.069 111.576 16.595 ;
     RECT  121.2 16.405 122.568 16.595 ;
     RECT  83.136 16.405 89.208 16.691 ;
     RECT  135.024 16.645 135.048 16.693 ;
     RECT  152.928 13.621 153.912 16.787 ;
     RECT  121.2 16.595 122.088 16.789 ;
     RECT  128.784 16.549 129.96 16.789 ;
     RECT  132 15.443 132.312 16.789 ;
     RECT  153.312 16.787 153.912 16.837 ;
     RECT  128.592 16.789 129.96 16.883 ;
     RECT  153.312 16.837 154.44 16.883 ;
     RECT  169.8 2.151 170.112 16.885 ;
     RECT  40.2 16.405 41.16 16.931 ;
     RECT  139.056 16.549 139.08 16.931 ;
     RECT  209.328 16.789 209.352 16.931 ;
     RECT  83.184 16.691 89.208 16.979 ;
     RECT  128.592 16.883 129.576 16.979 ;
     RECT  135.024 16.693 135.624 16.979 ;
     RECT  136.8 16.549 137.712 16.981 ;
     RECT  103.008 15.589 103.032 17.027 ;
     RECT  135.024 16.979 135.048 17.029 ;
     RECT  79.68 16.019 80.424 17.075 ;
     RECT  13.2 16.357 13.896 17.077 ;
     RECT  169.8 16.885 170.472 17.077 ;
     RECT  180.6 2.151 180.912 17.077 ;
     RECT  79.68 17.075 80.136 17.123 ;
     RECT  120.816 16.789 122.088 17.123 ;
     RECT  128.592 16.979 129.432 17.123 ;
     RECT  136.752 16.981 137.712 17.123 ;
     RECT  148.2 12.229 149.256 17.123 ;
     RECT  172.704 16.405 172.728 17.123 ;
     RECT  226.992 16.501 227.016 17.123 ;
     RECT  126.6 15.587 127.032 17.125 ;
     RECT  81.408 16.501 82.056 17.219 ;
     RECT  112.8 17.077 112.824 17.219 ;
     RECT  153.6 16.883 154.44 17.315 ;
     RECT  169.8 17.077 170.52 17.315 ;
     RECT  178.416 17.077 178.44 17.315 ;
     RECT  180.384 17.077 180.912 17.315 ;
     RECT  134.64 17.029 135.048 17.317 ;
     RECT  180.6 17.315 180.912 17.317 ;
     RECT  196.8 2.151 197.112 17.317 ;
     RECT  13.2 17.077 14.76 17.363 ;
     RECT  126.6 17.125 127.704 17.363 ;
     RECT  164.4 2.151 164.712 17.365 ;
     RECT  198.192 17.077 198.216 17.413 ;
     RECT  166.464 17.269 166.488 17.459 ;
     RECT  196.704 17.317 197.112 17.459 ;
     RECT  169.8 17.315 170.472 17.507 ;
     RECT  109.872 16.595 110.712 17.509 ;
     RECT  164.4 17.365 165.336 17.605 ;
     RECT  207.072 12.517 207.912 17.605 ;
     RECT  83.232 16.979 89.208 17.651 ;
     RECT  218.4 16.261 218.856 17.651 ;
     RECT  33.264 16.885 33.288 17.843 ;
     RECT  43.104 16.309 43.128 17.941 ;
     RECT  43.008 17.941 43.128 17.987 ;
     RECT  177.504 17.653 177.528 17.987 ;
     RECT  114.864 16.067 116.112 18.133 ;
     RECT  137.4 17.123 137.712 18.133 ;
     RECT  198.096 17.413 198.216 18.133 ;
     RECT  91.92 16.645 91.944 18.179 ;
     RECT  134.544 17.317 135.048 18.179 ;
     RECT  81.408 17.219 81.432 18.229 ;
     RECT  83.232 17.651 89.112 18.275 ;
     RECT  137.4 18.133 138.36 18.275 ;
     RECT  129.12 17.123 129.432 18.277 ;
     RECT  114.864 18.133 116.232 18.323 ;
     RECT  121.2 17.123 122.088 18.323 ;
     RECT  83.232 18.275 87.528 18.373 ;
     RECT  129.12 18.277 130.104 18.419 ;
     RECT  139.584 16.933 139.608 18.419 ;
     RECT  134.544 18.179 134.664 18.421 ;
     RECT  83.136 18.373 87.528 18.467 ;
     RECT  129.12 18.419 129.144 18.467 ;
     RECT  136.128 17.461 136.152 18.467 ;
     RECT  134.064 18.421 134.664 18.515 ;
     RECT  134.064 18.515 134.568 18.755 ;
     RECT  18.6 2.151 18.912 18.805 ;
     RECT  14.736 17.363 14.76 18.851 ;
     RECT  56.4 7.765 57 18.851 ;
     RECT  206.352 17.605 207.912 18.947 ;
     RECT  131.184 16.789 132.312 18.949 ;
     RECT  115.8 18.323 116.232 18.995 ;
     RECT  221.904 15.877 221.928 18.995 ;
     RECT  215.424 18.949 215.448 19.045 ;
     RECT  198.096 18.133 198.936 19.091 ;
     RECT  214.944 19.045 215.448 19.091 ;
     RECT  61.8 10.355 62.112 19.093 ;
     RECT  59.088 18.517 59.112 19.139 ;
     RECT  130.272 18.949 132.312 19.139 ;
     RECT  137.4 18.275 137.832 19.187 ;
     RECT  81.408 18.229 81.768 19.235 ;
     RECT  78 12.035 78.312 19.237 ;
     RECT  124.8 19.141 124.824 19.283 ;
     RECT  198.912 19.091 198.936 19.283 ;
     RECT  222.336 19.045 222.36 19.379 ;
     RECT  134.064 18.755 134.52 19.427 ;
     RECT  164.4 17.605 165.672 19.427 ;
     RECT  126.6 17.363 127.032 19.475 ;
     RECT  13.2 17.363 13.512 19.573 ;
     RECT  83.136 18.467 87.432 19.621 ;
     RECT  88.8 18.275 89.112 19.621 ;
     RECT  18.288 18.805 18.912 19.811 ;
     RECT  49.968 19.333 49.992 19.811 ;
     RECT  61.008 19.093 62.112 19.859 ;
     RECT  74.256 18.757 74.28 19.859 ;
     RECT  141.792 19.669 141.816 19.861 ;
     RECT  141.696 19.861 141.816 19.907 ;
     RECT  171.936 18.757 171.96 19.907 ;
     RECT  43.008 17.987 43.032 20.003 ;
     RECT  78 19.237 79.272 20.003 ;
     RECT  109.824 17.509 110.712 20.003 ;
     RECT  131.088 19.139 132.312 20.003 ;
     RECT  180.6 17.317 181.032 20.003 ;
     RECT  81.408 19.235 81.432 20.051 ;
     RECT  132 20.003 132.312 20.293 ;
     RECT  118.56 20.101 118.584 20.339 ;
     RECT  13.2 19.573 13.608 20.341 ;
     RECT  12.576 20.341 13.608 20.579 ;
     RECT  134.496 19.427 134.52 20.579 ;
     RECT  139.68 19.861 139.704 20.579 ;
     RECT  214.944 19.091 214.968 20.579 ;
     RECT  216.576 20.149 216.6 20.579 ;
     RECT  141.696 19.907 141.72 20.629 ;
     RECT  128.736 20.581 128.76 20.677 ;
     RECT  207.072 18.947 207.912 20.723 ;
     RECT  140.784 20.629 141.72 20.771 ;
     RECT  128.736 20.677 129.528 20.819 ;
     RECT  132 20.293 132.408 20.963 ;
     RECT  12.576 20.579 13.512 21.155 ;
     RECT  16.512 17.941 16.536 21.155 ;
     RECT  21.6 20.581 21.624 21.155 ;
     RECT  83.136 19.621 89.112 21.155 ;
     RECT  141.696 20.771 141.72 21.155 ;
     RECT  83.136 21.155 83.928 21.347 ;
     RECT  205.632 19.669 205.656 21.395 ;
     RECT  18.6 19.811 18.912 21.541 ;
     RECT  207.504 20.723 207.912 21.541 ;
     RECT  126.6 19.475 126.912 21.589 ;
     RECT  17.616 21.541 19.896 21.637 ;
     RECT  83.232 21.347 83.928 21.731 ;
     RECT  207.504 21.541 208.008 21.779 ;
     RECT  125.76 21.589 126.912 21.829 ;
     RECT  207.6 21.779 208.008 21.875 ;
     RECT  125.712 21.829 126.912 21.973 ;
     RECT  177.984 21.829 178.008 22.021 ;
     RECT  179.424 21.589 179.448 22.021 ;
     RECT  128.736 20.819 128.76 22.165 ;
     RECT  177.984 22.021 179.448 22.309 ;
     RECT  171.984 22.165 172.008 22.501 ;
     RECT  171.408 22.501 172.008 22.741 ;
     RECT  171.312 22.741 172.008 23.317 ;
     RECT  7.8 2.151 8.112 23.365 ;
     RECT  13.2 21.155 13.512 23.365 ;
     RECT  16.848 21.637 19.896 23.365 ;
     RECT  51 16.355 51.312 23.365 ;
     RECT  83.232 21.731 83.712 23.365 ;
     RECT  84.912 21.155 89.112 23.365 ;
     RECT  90.336 22.789 90.36 23.365 ;
     RECT  123.216 21.829 123.24 23.365 ;
     RECT  125.328 21.973 126.912 23.365 ;
     RECT  128.736 22.165 129.336 23.365 ;
     RECT  132 20.963 132.312 23.365 ;
     RECT  134.256 22.309 134.28 23.365 ;
     RECT  140.256 21.589 140.568 23.365 ;
     RECT  171.12 23.317 172.008 23.365 ;
     RECT  177.984 22.309 179.592 23.365 ;
     RECT  180.6 20.003 180.912 23.365 ;
     RECT  206.16 23.317 206.184 23.365 ;
     RECT  207.6 21.875 207.912 23.365 ;
     RECT  213 2.151 213.312 23.365 ;
     RECT  218.4 17.651 218.712 23.365 ;
     RECT  221.232 21.637 221.256 23.365 ;
     RECT  223.8 2.151 224.112 23.365 ;
     RECT  225.168 23.317 225.192 23.365 ;
     RECT  7.536 23.365 21.624 23.413 ;
     RECT  132 23.365 135.624 23.413 ;
     RECT  171.12 23.365 173.928 23.413 ;
     RECT  205.968 23.365 209.256 23.413 ;
     RECT  212.592 23.365 213.312 23.413 ;
     RECT  49.296 23.365 52.584 23.461 ;
     RECT  81.264 23.365 91.608 23.461 ;
     RECT  138.96 23.365 141.768 23.461 ;
     RECT  142.8 2.151 143.112 23.461 ;
     RECT  223.8 23.365 227.688 23.461 ;
     RECT  122.928 23.365 129.432 23.557 ;
     RECT  7.44 23.413 21.624 23.701 ;
     RECT  177.456 23.365 184.008 23.701 ;
     RECT  212.496 23.413 213.312 23.701 ;
     RECT  2.4 2.151 2.712 23.769 ;
     RECT  24 2.151 24.312 23.769 ;
     RECT  29.4 2.151 29.712 23.769 ;
     RECT  34.8 2.151 35.112 23.769 ;
     RECT  40.2 16.931 40.512 23.769 ;
     RECT  45.6 16.307 45.912 23.769 ;
     RECT  56.4 18.851 56.712 23.769 ;
     RECT  61.8 19.859 62.112 23.769 ;
     RECT  67.2 12.275 67.512 23.769 ;
     RECT  72.6 11.459 72.912 23.769 ;
     RECT  78 20.003 78.312 23.769 ;
     RECT  94.2 6.371 94.512 23.769 ;
     RECT  99.6 11.459 99.912 23.769 ;
     RECT  105 15.491 105.312 23.769 ;
     RECT  110.4 20.003 110.712 23.769 ;
     RECT  115.8 18.995 116.112 23.769 ;
     RECT  121.2 18.323 121.512 23.769 ;
     RECT  137.4 19.187 137.712 23.769 ;
     RECT  138.96 23.461 143.112 23.769 ;
     RECT  148.2 17.123 148.512 23.769 ;
     RECT  153.6 17.315 153.912 23.769 ;
     RECT  159 2.151 159.312 23.769 ;
     RECT  164.4 19.427 164.712 23.769 ;
     RECT  169.8 17.507 170.112 23.769 ;
     RECT  175.2 2.151 175.512 23.769 ;
     RECT  186 2.151 186.312 23.769 ;
     RECT  191.4 2.151 191.712 23.769 ;
     RECT  196.8 17.459 197.112 23.769 ;
     RECT  202.2 2.151 202.512 23.769 ;
     RECT  229.2 2.151 229.512 23.769 ;
     RECT  234.6 2.151 234.912 23.769 ;
     RECT  2.4 23.769 2.52 23.783 ;
     RECT  24 23.769 24.12 23.783 ;
     RECT  29.4 23.769 29.52 23.783 ;
     RECT  34.8 23.769 34.92 23.783 ;
     RECT  40.2 23.769 40.32 23.783 ;
     RECT  45.6 23.769 45.72 23.783 ;
     RECT  56.4 23.769 56.52 23.783 ;
     RECT  61.8 23.769 61.92 23.783 ;
     RECT  67.2 23.769 67.32 23.783 ;
     RECT  72.6 23.769 72.72 23.783 ;
     RECT  78 23.769 78.12 23.783 ;
     RECT  94.2 23.769 94.32 23.783 ;
     RECT  99.6 23.769 99.72 23.783 ;
     RECT  105 23.769 105.12 23.783 ;
     RECT  110.4 23.769 110.52 23.783 ;
     RECT  115.8 23.769 115.92 23.783 ;
     RECT  121.2 23.769 121.32 23.783 ;
     RECT  132 23.413 135.72 23.783 ;
     RECT  137.4 23.769 137.52 23.783 ;
     RECT  138.96 23.769 142.92 23.783 ;
     RECT  148.2 23.769 148.32 23.783 ;
     RECT  153.6 23.769 153.72 23.783 ;
     RECT  159 23.769 159.12 23.783 ;
     RECT  164.4 23.769 164.52 23.783 ;
     RECT  169.8 23.769 169.92 23.783 ;
     RECT  175.2 23.769 175.32 23.783 ;
     RECT  186 23.769 186.12 23.783 ;
     RECT  191.4 23.769 191.52 23.783 ;
     RECT  196.8 23.769 196.92 23.783 ;
     RECT  202.2 23.769 202.32 23.783 ;
     RECT  218.4 23.365 221.88 23.783 ;
     RECT  223.8 23.461 227.88 23.783 ;
     RECT  229.2 23.769 229.32 23.783 ;
     RECT  234.6 23.769 234.72 23.783 ;
     RECT  205.968 23.413 209.352 23.941 ;
     RECT  49.296 23.461 52.68 24.517 ;
     RECT  122.832 23.557 129.528 24.517 ;
     RECT  212.4 23.701 213.624 24.517 ;
     RECT  49.104 24.517 52.68 25.093 ;
     RECT  138.96 23.783 141.864 25.093 ;
     RECT  218.976 23.783 221.88 25.093 ;
     RECT  7.344 23.701 21.624 25.744 ;
     RECT  49.008 25.093 52.68 25.744 ;
     RECT  81.264 23.461 91.8 25.744 ;
     RECT  122.736 24.517 129.528 25.744 ;
     RECT  132.72 23.783 135.72 25.744 ;
     RECT  138.864 25.093 141.864 25.744 ;
     RECT  171.12 23.413 174.12 25.744 ;
     RECT  177.264 23.701 184.008 25.744 ;
     RECT  205.68 23.941 209.352 25.744 ;
     RECT  212.4 24.517 213.72 25.744 ;
     RECT  218.976 25.093 221.976 25.744 ;
     RECT  224.88 23.783 227.88 25.744 ;
     RECT  85.392 25.744 85.416 25.811 ;
     RECT  87.312 25.744 87.336 25.811 ;
     RECT  125.76 25.744 125.784 25.811 ;
     RECT  129.168 25.744 129.192 25.811 ;
     RECT  140.256 25.744 140.568 25.811 ;
     RECT  177.984 25.744 178.296 25.811 ;
     RECT  179.424 25.744 179.448 25.811 ;
     RECT  221.232 25.744 221.256 25.811 ;
     RECT  62.112 1.811 63.456 5.747 ;
     RECT  78.312 1.811 79.728 2.675 ;
     RECT  100.968 1.811 102 2.821 ;
     RECT  67.512 1.859 68.64 4.595 ;
     RECT  122.664 2.195 124.176 2.291 ;
     RECT  108.12 2.291 110.112 3.733 ;
     RECT  60.312 2.339 61.536 2.435 ;
     RECT  81.096 2.339 82.128 2.915 ;
     RECT  83.712 2.387 84.768 3.733 ;
     RECT  96.264 2.387 97.488 2.915 ;
     RECT  97.704 2.387 98.928 2.867 ;
     RECT  60.312 2.435 61.8 2.963 ;
     RECT  84.84 2.435 85.824 2.675 ;
     RECT  76.296 2.627 77.616 2.915 ;
     RECT  86.496 2.675 86.592 3.973 ;
     RECT  72.912 2.867 74.16 4.595 ;
     RECT  86.808 2.867 87.888 3.011 ;
     RECT  97.704 2.867 99.024 3.059 ;
     RECT  69.528 2.915 70.56 3.491 ;
     RECT  95.16 2.915 96.24 4.595 ;
     RECT  96.264 2.915 97.584 3.443 ;
     RECT  113.496 2.915 114.72 3.443 ;
     RECT  86.616 3.011 87.888 5.171 ;
     RECT  97.704 3.059 99.12 3.443 ;
     RECT  71.256 3.443 72.24 4.019 ;
     RECT  96.264 3.443 97.68 4.019 ;
     RECT  113.496 3.443 114.912 4.019 ;
     RECT  69.336 3.491 70.56 4.451 ;
     RECT  108.744 3.733 110.112 4.501 ;
     RECT  64.344 4.019 65.376 5.171 ;
     RECT  71.064 4.019 72.24 7.669 ;
     RECT  75.144 4.019 76.272 4.595 ;
     RECT  96.264 4.019 96.984 4.549 ;
     RECT  105.312 4.019 106.464 4.595 ;
     RECT  113.4 4.019 114.912 4.067 ;
     RECT  65.4 4.067 66.432 5.171 ;
     RECT  108.744 4.501 109.728 5.941 ;
     RECT  90.072 4.595 91.104 4.643 ;
     RECT  117.096 4.595 118.704 5.171 ;
     RECT  121.656 4.595 121.896 5.605 ;
     RECT  90.072 4.643 91.584 5.171 ;
     RECT  86.52 5.171 87.888 8.003 ;
     RECT  107.712 5.171 108.096 6.229 ;
     RECT  118.56 5.171 118.704 6.085 ;
     RECT  78.312 5.173 79.44 5.555 ;
     RECT  79.464 5.173 80.832 5.555 ;
     RECT  122.52 6.181 123.792 6.563 ;
     RECT  107.712 6.371 108.384 6.851 ;
     RECT  111.576 6.371 112.896 7.235 ;
     RECT  118.824 6.373 119.952 6.659 ;
     RECT  119.976 6.373 121.2 6.659 ;
     RECT  104.88 6.659 105 7.525 ;
     RECT  118.824 6.659 121.2 6.709 ;
     RECT  119.64 6.709 121.2 7.091 ;
     RECT  60.744 6.805 61.8 7.475 ;
     RECT  107.712 6.851 108.72 7.141 ;
     RECT  118.584 7.043 119.616 7.091 ;
     RECT  120.528 7.091 121.2 7.381 ;
     RECT  107.208 7.141 108.72 7.331 ;
     RECT  111.48 7.235 112.896 7.331 ;
     RECT  111.384 7.331 112.896 8.293 ;
     RECT  120.528 7.381 121.104 8.293 ;
     RECT  61.68 7.475 61.8 8.485 ;
     RECT  113.016 7.523 114 8.627 ;
     RECT  103.944 7.525 105 7.861 ;
     RECT  114.024 7.571 115.152 8.819 ;
     RECT  85.128 7.621 86.496 8.003 ;
     RECT  57 7.765 58.464 9.491 ;
     RECT  116.904 7.813 118.32 7.907 ;
     RECT  116.52 7.907 116.616 9.253 ;
     RECT  62.808 7.909 64.128 8.243 ;
     RECT  108.744 8.051 109.728 9.445 ;
     RECT  103.848 8.243 104.88 9.445 ;
     RECT  111.576 8.293 112.896 8.725 ;
     RECT  120.528 8.293 120.624 8.533 ;
     RECT  112.968 8.627 114 8.867 ;
     RECT  64.128 8.675 64.176 9.877 ;
     RECT  65.16 8.677 66.528 10.307 ;
     RECT  107.736 9.157 108.72 10.307 ;
     RECT  116.328 9.395 116.616 9.971 ;
     RECT  55.416 9.541 56.4 12.467 ;
     RECT  103.848 9.587 105 11.941 ;
     RECT  105.312 9.587 105.816 10.837 ;
     RECT  60.552 9.637 61.68 10.259 ;
     RECT  62.904 9.877 64.176 10.355 ;
     RECT  116.112 9.971 116.616 10.021 ;
     RECT  116.112 10.021 117.648 10.405 ;
     RECT  60.552 10.259 61.8 12.563 ;
     RECT  87.768 10.307 88.8 12.563 ;
     RECT  107.736 10.307 108.864 10.355 ;
     RECT  108.936 10.307 110.016 10.931 ;
     RECT  107.64 10.355 108.864 10.643 ;
     RECT  114.6 10.405 115.8 10.835 ;
     RECT  116.112 10.405 117.456 10.835 ;
     RECT  86.76 10.501 87.744 11.269 ;
     RECT  108.72 10.643 108.864 11.749 ;
     RECT  78.312 10.789 79.632 10.931 ;
     RECT  115.008 10.835 115.8 11.893 ;
     RECT  116.112 10.835 116.76 11.125 ;
     RECT  108.936 10.931 110.4 11.075 ;
     RECT  83.712 10.979 84.72 12.563 ;
     RECT  125.208 10.981 126.6 11.029 ;
     RECT  108.888 11.075 110.4 11.795 ;
     RECT  85.272 11.317 86.736 11.411 ;
     RECT  85.272 11.411 87.264 11.701 ;
     RECT  124.08 11.411 124.368 12.181 ;
     RECT  125.208 11.651 126.6 11.891 ;
     RECT  86.04 11.701 87.264 11.987 ;
     RECT  108.744 11.795 110.4 13.043 ;
     RECT  54.264 11.845 55.392 12.467 ;
     RECT  103.848 11.941 104.88 12.563 ;
     RECT  86.04 11.987 87.504 13.477 ;
     RECT  111.576 12.035 112.752 13.139 ;
     RECT  123.288 12.181 124.368 12.371 ;
     RECT  66.168 12.275 67.2 12.515 ;
     RECT  81.816 12.517 82.992 13.091 ;
     RECT  83.712 12.563 85.248 13.477 ;
     RECT  87.624 12.563 88.8 13.283 ;
     RECT  109.392 13.043 110.4 13.045 ;
     RECT  80.472 13.045 81.792 13.139 ;
     RECT  89.112 13.045 90.576 13.477 ;
     RECT  90.6 13.045 91.632 14.243 ;
     RECT  109.416 13.045 110.4 13.523 ;
     RECT  81.816 13.091 83.28 13.139 ;
     RECT  80.472 13.139 83.28 13.621 ;
     RECT  87.576 13.283 88.8 14.773 ;
     RECT  121.512 13.379 122.472 14.437 ;
     RECT  78.312 13.429 79.488 15.443 ;
     RECT  84.072 13.477 85.248 14.867 ;
     RECT  89.304 13.477 90.576 14.243 ;
     RECT  71.592 13.621 72.6 14.387 ;
     RECT  81.672 13.621 83.28 14.197 ;
     RECT  115.008 13.715 115.8 14.197 ;
     RECT  91.656 13.813 93.168 14.339 ;
     RECT  93.192 13.813 94.2 14.339 ;
     RECT  81.672 14.197 83.136 15.443 ;
     RECT  113.208 14.197 114.528 15.301 ;
     RECT  114.552 14.197 115.8 14.677 ;
     RECT  128.952 14.293 130.128 14.627 ;
     RECT  121.896 14.437 122.472 14.533 ;
     RECT  121.896 14.533 123.552 14.677 ;
     RECT  129.264 14.627 130.128 14.965 ;
     RECT  114.6 14.677 115.8 15.301 ;
     RECT  122.328 14.677 123.552 14.917 ;
     RECT  83.832 14.867 85.248 15.301 ;
     RECT  122.328 14.917 123.36 14.965 ;
     RECT  130.584 14.965 132 15.251 ;
     RECT  136.056 14.965 137.4 15.107 ;
     RECT  136.8 15.107 137.4 16.549 ;
     RECT  122.328 15.155 123.36 15.203 ;
     RECT  122.328 15.203 122.568 15.251 ;
     RECT  121.896 15.251 122.568 16.405 ;
     RECT  129.264 15.251 129.84 15.395 ;
     RECT  83.832 15.301 85.152 15.877 ;
     RECT  113.352 15.301 114.528 16.067 ;
     RECT  135.024 15.347 135.048 16.645 ;
     RECT  129.264 15.395 129.936 16.549 ;
     RECT  78.312 15.443 79.68 17.123 ;
     RECT  81.432 15.443 83.136 16.501 ;
     RECT  51.912 15.493 53.088 15.971 ;
     RECT  83.832 15.877 84.864 16.405 ;
     RECT  213.312 15.973 214.32 16.115 ;
     RECT  80.424 16.019 81.408 17.075 ;
     RECT  113.352 16.067 114.864 16.547 ;
     RECT  82.056 16.501 83.136 16.691 ;
     RECT  137.712 16.549 139.056 16.931 ;
     RECT  82.056 16.691 83.184 16.979 ;
     RECT  135.624 16.693 136.8 16.979 ;
     RECT  129.96 16.789 131.184 16.883 ;
     RECT  207.912 16.789 209.328 16.931 ;
     RECT  129.576 16.883 131.184 16.979 ;
     RECT  33.288 16.885 34.8 17.843 ;
     RECT  137.712 16.931 139.08 16.933 ;
     RECT  137.712 16.933 139.584 18.133 ;
     RECT  82.056 16.979 83.232 17.219 ;
     RECT  129.432 16.979 131.184 18.277 ;
     RECT  135.048 16.979 136.8 16.981 ;
     RECT  135.048 16.981 136.752 17.123 ;
     RECT  80.136 17.075 81.408 17.123 ;
     RECT  197.112 17.077 198.192 17.413 ;
     RECT  128.592 17.123 129.12 17.125 ;
     RECT  135.048 17.123 137.4 17.461 ;
     RECT  127.704 17.125 129.12 17.363 ;
     RECT  81.432 17.219 83.232 18.229 ;
     RECT  13.512 17.363 14.736 18.851 ;
     RECT  165.336 17.365 166.464 17.459 ;
     RECT  197.112 17.413 198.096 19.091 ;
     RECT  165.336 17.459 165.672 17.605 ;
     RECT  135.048 17.461 136.128 18.179 ;
     RECT  136.152 17.461 137.4 18.467 ;
     RECT  138.36 18.133 139.584 18.275 ;
     RECT  134.664 18.179 136.128 18.467 ;
     RECT  81.768 18.229 83.232 18.373 ;
     RECT  87.528 18.275 88.8 18.467 ;
     RECT  130.104 18.277 131.184 18.419 ;
     RECT  81.768 18.373 83.136 19.235 ;
     RECT  129.144 18.419 131.184 18.467 ;
     RECT  87.432 18.467 88.8 19.621 ;
     RECT  130.272 18.467 131.184 18.949 ;
     RECT  72.912 18.757 74.256 19.859 ;
     RECT  13.512 18.851 13.608 19.573 ;
     RECT  206.352 18.947 207.072 19.669 ;
     RECT  222.36 19.045 223.8 19.379 ;
     RECT  49.992 19.333 51 19.811 ;
     RECT  141.816 19.669 142.8 19.907 ;
     RECT  205.656 19.669 207.072 20.723 ;
     RECT  141.72 19.907 142.8 21.155 ;
     RECT  128.76 20.819 129.336 22.165 ;
     RECT  83.928 21.155 84.912 21.731 ;
     RECT  179.448 21.589 180.6 22.309 ;
     RECT  83.712 21.731 84.912 23.365 ;
     RECT  178.008 21.829 179.424 22.021 ;
     RECT  207.912 21.875 208.008 23.365 ;
     RECT  179.592 22.309 180.6 23.365 ;
     RECT  170.112 22.501 171.408 22.741 ;
     RECT  170.112 22.741 171.312 23.317 ;
     RECT  89.112 22.789 90.336 23.365 ;
     RECT  170.112 23.317 171.12 23.769 ;
     RECT  206.184 23.317 207.6 23.365 ;
     RECT  224.112 23.317 225.168 23.365 ;
     RECT  121.512 23.365 122.928 23.557 ;
     RECT  137.712 23.365 138.96 23.769 ;
     RECT  141.768 23.365 142.8 23.461 ;
     RECT  173.928 23.365 175.2 23.413 ;
     RECT  227.688 23.365 229.2 23.461 ;
     RECT  174.12 23.413 175.2 23.783 ;
     RECT  227.88 23.461 229.2 23.783 ;
     RECT  121.512 23.557 122.832 23.769 ;
     RECT  121.32 23.769 122.832 23.783 ;
     RECT  137.52 23.769 138.96 23.783 ;
     RECT  169.92 23.769 171.12 23.783 ;
     RECT  122.736 23.783 122.832 24.517 ;
     RECT  138.864 23.783 138.96 25.093 ;
  END
END ot_lkep_ts
END LIBRARY
